VERSION 5.8 ;
BUSBITCHARS "[]" ;
DIVIDERCHAR "/" ;
UNITS
    DATABASE MICRONS 1000 ;
END UNITS

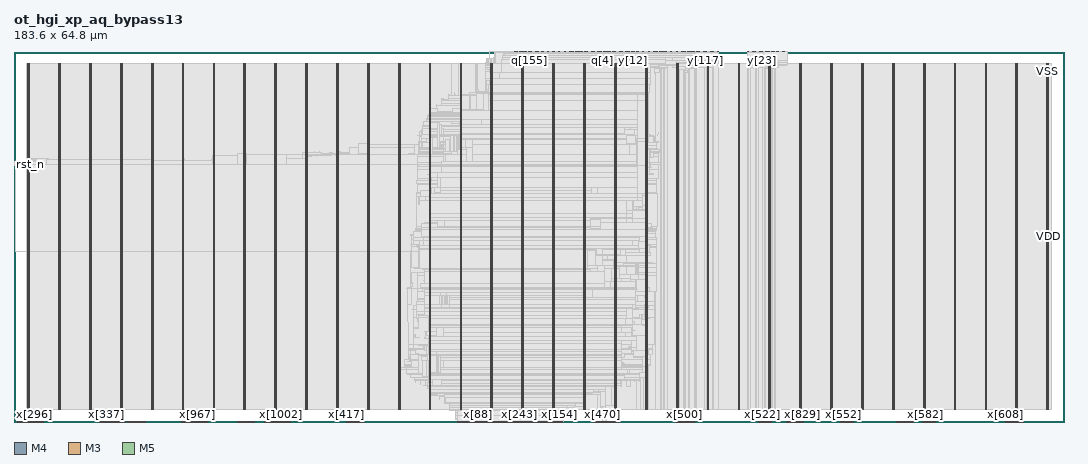
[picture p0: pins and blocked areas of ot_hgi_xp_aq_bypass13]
MACRO ot_hgi_xp_aq_bypass13
  FOREIGN ot_hgi_xp_aq_bypass13 0 0 ;
  CLASS BLOCK ;
  SIZE 183.6 BY 64.8 ;
  PIN clk
    DIRECTION INPUT ;
    USE SIGNAL ;
    PORT
      LAYER M4 ;
        RECT  0 44.88 0.084 44.904 ;
    END
  END clk
  PIN e[0]
    DIRECTION OUTPUT ;
    USE SIGNAL ;
    PORT
      LAYER M3 ;
        RECT  101.844 64.763 101.862 64.8 ;
    END
  END e[0]
  PIN e[1]
    DIRECTION OUTPUT ;
    USE SIGNAL ;
    PORT
      LAYER M3 ;
        RECT  101.916 64.763 101.934 64.8 ;
    END
  END e[1]
  PIN e[2]
    DIRECTION OUTPUT ;
    USE SIGNAL ;
    PORT
      LAYER M3 ;
        RECT  101.988 64.763 102.006 64.8 ;
    END
  END e[2]
  PIN e[3]
    DIRECTION OUTPUT ;
    USE SIGNAL ;
    PORT
      LAYER M3 ;
        RECT  102.06 64.763 102.078 64.8 ;
    END
  END e[3]
  PIN e[4]
    DIRECTION OUTPUT ;
    USE SIGNAL ;
    PORT
      LAYER M3 ;
        RECT  102.132 64.763 102.15 64.8 ;
    END
  END e[4]
  PIN e[5]
    DIRECTION OUTPUT ;
    USE SIGNAL ;
    PORT
      LAYER M3 ;
        RECT  102.204 64.763 102.222 64.8 ;
    END
  END e[5]
  PIN e[6]
    DIRECTION OUTPUT ;
    USE SIGNAL ;
    PORT
      LAYER M3 ;
        RECT  102.276 64.763 102.294 64.8 ;
    END
  END e[6]
  PIN e[7]
    DIRECTION OUTPUT ;
    USE SIGNAL ;
    PORT
      LAYER M3 ;
        RECT  102.348 64.763 102.366 64.8 ;
    END
  END e[7]
  PIN e[8]
    DIRECTION OUTPUT ;
    USE SIGNAL ;
    PORT
      LAYER M3 ;
        RECT  102.42 64.763 102.438 64.8 ;
    END
  END e[8]
  PIN e[9]
    DIRECTION OUTPUT ;
    USE SIGNAL ;
    PORT
      LAYER M3 ;
        RECT  102.492 64.763 102.51 64.8 ;
    END
  END e[9]
  PIN fault
    DIRECTION OUTPUT ;
    USE SIGNAL ;
    PORT
      LAYER M3 ;
        RECT  102.564 64.763 102.582 64.8 ;
    END
  END fault
  PIN fp4
    DIRECTION INPUT ;
    USE SIGNAL ;
    PORT
      LAYER M4 ;
        RECT  0 44.976 0.084 45 ;
    END
  END fp4
  PIN q[0]
    DIRECTION OUTPUT ;
    USE SIGNAL ;
    PORT
      LAYER M3 ;
        RECT  102.636 64.763 102.654 64.8 ;
    END
  END q[0]
  PIN q[100]
    DIRECTION OUTPUT ;
    USE SIGNAL ;
    PORT
      LAYER M5 ;
        RECT  89.136 64.716 89.16 64.8 ;
    END
  END q[100]
  PIN q[101]
    DIRECTION OUTPUT ;
    USE SIGNAL ;
    PORT
      LAYER M5 ;
        RECT  89.232 64.716 89.256 64.8 ;
    END
  END q[101]
  PIN q[102]
    DIRECTION OUTPUT ;
    USE SIGNAL ;
    PORT
      LAYER M5 ;
        RECT  89.328 64.716 89.352 64.8 ;
    END
  END q[102]
  PIN q[103]
    DIRECTION OUTPUT ;
    USE SIGNAL ;
    PORT
      LAYER M5 ;
        RECT  89.424 64.716 89.448 64.8 ;
    END
  END q[103]
  PIN q[104]
    DIRECTION OUTPUT ;
    USE SIGNAL ;
    PORT
      LAYER M5 ;
        RECT  89.52 64.716 89.544 64.8 ;
    END
  END q[104]
  PIN q[105]
    DIRECTION OUTPUT ;
    USE SIGNAL ;
    PORT
      LAYER M5 ;
        RECT  89.616 64.716 89.64 64.8 ;
    END
  END q[105]
  PIN q[106]
    DIRECTION OUTPUT ;
    USE SIGNAL ;
    PORT
      LAYER M5 ;
        RECT  89.712 64.716 89.736 64.8 ;
    END
  END q[106]
  PIN q[107]
    DIRECTION OUTPUT ;
    USE SIGNAL ;
    PORT
      LAYER M5 ;
        RECT  89.808 64.716 89.832 64.8 ;
    END
  END q[107]
  PIN q[108]
    DIRECTION OUTPUT ;
    USE SIGNAL ;
    PORT
      LAYER M5 ;
        RECT  89.904 64.716 89.928 64.8 ;
    END
  END q[108]
  PIN q[109]
    DIRECTION OUTPUT ;
    USE SIGNAL ;
    PORT
      LAYER M5 ;
        RECT  90 64.716 90.024 64.8 ;
    END
  END q[109]
  PIN q[10]
    DIRECTION OUTPUT ;
    USE SIGNAL ;
    PORT
      LAYER M3 ;
        RECT  103.356 64.763 103.374 64.8 ;
    END
  END q[10]
  PIN q[110]
    DIRECTION OUTPUT ;
    USE SIGNAL ;
    PORT
      LAYER M5 ;
        RECT  90.096 64.716 90.12 64.8 ;
    END
  END q[110]
  PIN q[111]
    DIRECTION OUTPUT ;
    USE SIGNAL ;
    PORT
      LAYER M5 ;
        RECT  90.192 64.716 90.216 64.8 ;
    END
  END q[111]
  PIN q[112]
    DIRECTION OUTPUT ;
    USE SIGNAL ;
    PORT
      LAYER M5 ;
        RECT  90.288 64.716 90.312 64.8 ;
    END
  END q[112]
  PIN q[113]
    DIRECTION OUTPUT ;
    USE SIGNAL ;
    PORT
      LAYER M5 ;
        RECT  90.384 64.716 90.408 64.8 ;
    END
  END q[113]
  PIN q[114]
    DIRECTION OUTPUT ;
    USE SIGNAL ;
    PORT
      LAYER M5 ;
        RECT  90.48 64.716 90.504 64.8 ;
    END
  END q[114]
  PIN q[115]
    DIRECTION OUTPUT ;
    USE SIGNAL ;
    PORT
      LAYER M5 ;
        RECT  90.576 64.716 90.6 64.8 ;
    END
  END q[115]
  PIN q[116]
    DIRECTION OUTPUT ;
    USE SIGNAL ;
    PORT
      LAYER M5 ;
        RECT  90.672 64.716 90.696 64.8 ;
    END
  END q[116]
  PIN q[117]
    DIRECTION OUTPUT ;
    USE SIGNAL ;
    PORT
      LAYER M5 ;
        RECT  96.912 64.716 96.936 64.8 ;
    END
  END q[117]
  PIN q[118]
    DIRECTION OUTPUT ;
    USE SIGNAL ;
    PORT
      LAYER M5 ;
        RECT  97.008 64.716 97.032 64.8 ;
    END
  END q[118]
  PIN q[119]
    DIRECTION OUTPUT ;
    USE SIGNAL ;
    PORT
      LAYER M5 ;
        RECT  97.104 64.716 97.128 64.8 ;
    END
  END q[119]
  PIN q[11]
    DIRECTION OUTPUT ;
    USE SIGNAL ;
    PORT
      LAYER M3 ;
        RECT  103.428 64.763 103.446 64.8 ;
    END
  END q[11]
  PIN q[120]
    DIRECTION OUTPUT ;
    USE SIGNAL ;
    PORT
      LAYER M5 ;
        RECT  97.2 64.716 97.224 64.8 ;
    END
  END q[120]
  PIN q[121]
    DIRECTION OUTPUT ;
    USE SIGNAL ;
    PORT
      LAYER M5 ;
        RECT  97.296 64.716 97.32 64.8 ;
    END
  END q[121]
  PIN q[122]
    DIRECTION OUTPUT ;
    USE SIGNAL ;
    PORT
      LAYER M5 ;
        RECT  97.392 64.716 97.416 64.8 ;
    END
  END q[122]
  PIN q[123]
    DIRECTION OUTPUT ;
    USE SIGNAL ;
    PORT
      LAYER M5 ;
        RECT  97.488 64.716 97.512 64.8 ;
    END
  END q[123]
  PIN q[124]
    DIRECTION OUTPUT ;
    USE SIGNAL ;
    PORT
      LAYER M5 ;
        RECT  97.584 64.716 97.608 64.8 ;
    END
  END q[124]
  PIN q[125]
    DIRECTION OUTPUT ;
    USE SIGNAL ;
    PORT
      LAYER M5 ;
        RECT  97.68 64.716 97.704 64.8 ;
    END
  END q[125]
  PIN q[126]
    DIRECTION OUTPUT ;
    USE SIGNAL ;
    PORT
      LAYER M5 ;
        RECT  97.776 64.716 97.8 64.8 ;
    END
  END q[126]
  PIN q[127]
    DIRECTION OUTPUT ;
    USE SIGNAL ;
    PORT
      LAYER M5 ;
        RECT  97.872 64.716 97.896 64.8 ;
    END
  END q[127]
  PIN q[128]
    DIRECTION OUTPUT ;
    USE SIGNAL ;
    PORT
      LAYER M5 ;
        RECT  97.968 64.716 97.992 64.8 ;
    END
  END q[128]
  PIN q[129]
    DIRECTION OUTPUT ;
    USE SIGNAL ;
    PORT
      LAYER M5 ;
        RECT  98.064 64.716 98.088 64.8 ;
    END
  END q[129]
  PIN q[12]
    DIRECTION OUTPUT ;
    USE SIGNAL ;
    PORT
      LAYER M3 ;
        RECT  103.5 64.763 103.518 64.8 ;
    END
  END q[12]
  PIN q[130]
    DIRECTION OUTPUT ;
    USE SIGNAL ;
    PORT
      LAYER M5 ;
        RECT  98.16 64.716 98.184 64.8 ;
    END
  END q[130]
  PIN q[131]
    DIRECTION OUTPUT ;
    USE SIGNAL ;
    PORT
      LAYER M5 ;
        RECT  98.256 64.716 98.28 64.8 ;
    END
  END q[131]
  PIN q[132]
    DIRECTION OUTPUT ;
    USE SIGNAL ;
    PORT
      LAYER M5 ;
        RECT  98.352 64.716 98.376 64.8 ;
    END
  END q[132]
  PIN q[133]
    DIRECTION OUTPUT ;
    USE SIGNAL ;
    PORT
      LAYER M5 ;
        RECT  98.448 64.716 98.472 64.8 ;
    END
  END q[133]
  PIN q[134]
    DIRECTION OUTPUT ;
    USE SIGNAL ;
    PORT
      LAYER M5 ;
        RECT  98.544 64.716 98.568 64.8 ;
    END
  END q[134]
  PIN q[135]
    DIRECTION OUTPUT ;
    USE SIGNAL ;
    PORT
      LAYER M5 ;
        RECT  98.64 64.716 98.664 64.8 ;
    END
  END q[135]
  PIN q[136]
    DIRECTION OUTPUT ;
    USE SIGNAL ;
    PORT
      LAYER M5 ;
        RECT  98.736 64.716 98.76 64.8 ;
    END
  END q[136]
  PIN q[137]
    DIRECTION OUTPUT ;
    USE SIGNAL ;
    PORT
      LAYER M5 ;
        RECT  98.832 64.716 98.856 64.8 ;
    END
  END q[137]
  PIN q[138]
    DIRECTION OUTPUT ;
    USE SIGNAL ;
    PORT
      LAYER M5 ;
        RECT  98.928 64.716 98.952 64.8 ;
    END
  END q[138]
  PIN q[139]
    DIRECTION OUTPUT ;
    USE SIGNAL ;
    PORT
      LAYER M5 ;
        RECT  99.024 64.716 99.048 64.8 ;
    END
  END q[139]
  PIN q[13]
    DIRECTION OUTPUT ;
    USE SIGNAL ;
    PORT
      LAYER M3 ;
        RECT  103.572 64.763 103.59 64.8 ;
    END
  END q[13]
  PIN q[140]
    DIRECTION OUTPUT ;
    USE SIGNAL ;
    PORT
      LAYER M5 ;
        RECT  99.12 64.716 99.144 64.8 ;
    END
  END q[140]
  PIN q[141]
    DIRECTION OUTPUT ;
    USE SIGNAL ;
    PORT
      LAYER M5 ;
        RECT  99.216 64.716 99.24 64.8 ;
    END
  END q[141]
  PIN q[142]
    DIRECTION OUTPUT ;
    USE SIGNAL ;
    PORT
      LAYER M5 ;
        RECT  99.312 64.716 99.336 64.8 ;
    END
  END q[142]
  PIN q[143]
    DIRECTION OUTPUT ;
    USE SIGNAL ;
    PORT
      LAYER M5 ;
        RECT  99.408 64.716 99.432 64.8 ;
    END
  END q[143]
  PIN q[144]
    DIRECTION OUTPUT ;
    USE SIGNAL ;
    PORT
      LAYER M5 ;
        RECT  99.504 64.716 99.528 64.8 ;
    END
  END q[144]
  PIN q[145]
    DIRECTION OUTPUT ;
    USE SIGNAL ;
    PORT
      LAYER M5 ;
        RECT  99.6 64.716 99.624 64.8 ;
    END
  END q[145]
  PIN q[146]
    DIRECTION OUTPUT ;
    USE SIGNAL ;
    PORT
      LAYER M5 ;
        RECT  99.696 64.716 99.72 64.8 ;
    END
  END q[146]
  PIN q[147]
    DIRECTION OUTPUT ;
    USE SIGNAL ;
    PORT
      LAYER M5 ;
        RECT  99.792 64.716 99.816 64.8 ;
    END
  END q[147]
  PIN q[148]
    DIRECTION OUTPUT ;
    USE SIGNAL ;
    PORT
      LAYER M5 ;
        RECT  99.888 64.716 99.912 64.8 ;
    END
  END q[148]
  PIN q[149]
    DIRECTION OUTPUT ;
    USE SIGNAL ;
    PORT
      LAYER M3 ;
        RECT  89.748 64.763 89.766 64.8 ;
    END
  END q[149]
  PIN q[14]
    DIRECTION OUTPUT ;
    USE SIGNAL ;
    PORT
      LAYER M3 ;
        RECT  103.644 64.763 103.662 64.8 ;
    END
  END q[14]
  PIN q[150]
    DIRECTION OUTPUT ;
    USE SIGNAL ;
    PORT
      LAYER M3 ;
        RECT  89.82 64.763 89.838 64.8 ;
    END
  END q[150]
  PIN q[151]
    DIRECTION OUTPUT ;
    USE SIGNAL ;
    PORT
      LAYER M3 ;
        RECT  89.892 64.763 89.91 64.8 ;
    END
  END q[151]
  PIN q[152]
    DIRECTION OUTPUT ;
    USE SIGNAL ;
    PORT
      LAYER M3 ;
        RECT  89.964 64.763 89.982 64.8 ;
    END
  END q[152]
  PIN q[153]
    DIRECTION OUTPUT ;
    USE SIGNAL ;
    PORT
      LAYER M3 ;
        RECT  90.036 64.763 90.054 64.8 ;
    END
  END q[153]
  PIN q[154]
    DIRECTION OUTPUT ;
    USE SIGNAL ;
    PORT
      LAYER M3 ;
        RECT  90.108 64.763 90.126 64.8 ;
    END
  END q[154]
  PIN q[155]
    DIRECTION OUTPUT ;
    USE SIGNAL ;
    PORT
      LAYER M3 ;
        RECT  90.18 64.763 90.198 64.8 ;
    END
  END q[155]
  PIN q[156]
    DIRECTION OUTPUT ;
    USE SIGNAL ;
    PORT
      LAYER M3 ;
        RECT  90.252 64.763 90.27 64.8 ;
    END
  END q[156]
  PIN q[157]
    DIRECTION OUTPUT ;
    USE SIGNAL ;
    PORT
      LAYER M3 ;
        RECT  90.324 64.763 90.342 64.8 ;
    END
  END q[157]
  PIN q[158]
    DIRECTION OUTPUT ;
    USE SIGNAL ;
    PORT
      LAYER M3 ;
        RECT  90.396 64.763 90.414 64.8 ;
    END
  END q[158]
  PIN q[159]
    DIRECTION OUTPUT ;
    USE SIGNAL ;
    PORT
      LAYER M3 ;
        RECT  90.468 64.763 90.486 64.8 ;
    END
  END q[159]
  PIN q[15]
    DIRECTION OUTPUT ;
    USE SIGNAL ;
    PORT
      LAYER M3 ;
        RECT  103.716 64.763 103.734 64.8 ;
    END
  END q[15]
  PIN q[160]
    DIRECTION OUTPUT ;
    USE SIGNAL ;
    PORT
      LAYER M3 ;
        RECT  90.54 64.763 90.558 64.8 ;
    END
  END q[160]
  PIN q[161]
    DIRECTION OUTPUT ;
    USE SIGNAL ;
    PORT
      LAYER M3 ;
        RECT  90.612 64.763 90.63 64.8 ;
    END
  END q[161]
  PIN q[162]
    DIRECTION OUTPUT ;
    USE SIGNAL ;
    PORT
      LAYER M3 ;
        RECT  90.684 64.763 90.702 64.8 ;
    END
  END q[162]
  PIN q[163]
    DIRECTION OUTPUT ;
    USE SIGNAL ;
    PORT
      LAYER M3 ;
        RECT  90.756 64.763 90.774 64.8 ;
    END
  END q[163]
  PIN q[164]
    DIRECTION OUTPUT ;
    USE SIGNAL ;
    PORT
      LAYER M3 ;
        RECT  90.828 64.763 90.846 64.8 ;
    END
  END q[164]
  PIN q[165]
    DIRECTION OUTPUT ;
    USE SIGNAL ;
    PORT
      LAYER M3 ;
        RECT  90.9 64.763 90.918 64.8 ;
    END
  END q[165]
  PIN q[166]
    DIRECTION OUTPUT ;
    USE SIGNAL ;
    PORT
      LAYER M3 ;
        RECT  90.972 64.763 90.99 64.8 ;
    END
  END q[166]
  PIN q[167]
    DIRECTION OUTPUT ;
    USE SIGNAL ;
    PORT
      LAYER M3 ;
        RECT  91.044 64.763 91.062 64.8 ;
    END
  END q[167]
  PIN q[168]
    DIRECTION OUTPUT ;
    USE SIGNAL ;
    PORT
      LAYER M3 ;
        RECT  91.116 64.763 91.134 64.8 ;
    END
  END q[168]
  PIN q[169]
    DIRECTION OUTPUT ;
    USE SIGNAL ;
    PORT
      LAYER M3 ;
        RECT  91.188 64.763 91.206 64.8 ;
    END
  END q[169]
  PIN q[16]
    DIRECTION OUTPUT ;
    USE SIGNAL ;
    PORT
      LAYER M3 ;
        RECT  103.788 64.763 103.806 64.8 ;
    END
  END q[16]
  PIN q[170]
    DIRECTION OUTPUT ;
    USE SIGNAL ;
    PORT
      LAYER M3 ;
        RECT  91.26 64.763 91.278 64.8 ;
    END
  END q[170]
  PIN q[171]
    DIRECTION OUTPUT ;
    USE SIGNAL ;
    PORT
      LAYER M3 ;
        RECT  91.332 64.763 91.35 64.8 ;
    END
  END q[171]
  PIN q[172]
    DIRECTION OUTPUT ;
    USE SIGNAL ;
    PORT
      LAYER M3 ;
        RECT  91.404 64.763 91.422 64.8 ;
    END
  END q[172]
  PIN q[173]
    DIRECTION OUTPUT ;
    USE SIGNAL ;
    PORT
      LAYER M3 ;
        RECT  91.476 64.763 91.494 64.8 ;
    END
  END q[173]
  PIN q[174]
    DIRECTION OUTPUT ;
    USE SIGNAL ;
    PORT
      LAYER M3 ;
        RECT  91.548 64.763 91.566 64.8 ;
    END
  END q[174]
  PIN q[175]
    DIRECTION OUTPUT ;
    USE SIGNAL ;
    PORT
      LAYER M3 ;
        RECT  91.62 64.763 91.638 64.8 ;
    END
  END q[175]
  PIN q[176]
    DIRECTION OUTPUT ;
    USE SIGNAL ;
    PORT
      LAYER M3 ;
        RECT  91.692 64.763 91.71 64.8 ;
    END
  END q[176]
  PIN q[177]
    DIRECTION OUTPUT ;
    USE SIGNAL ;
    PORT
      LAYER M3 ;
        RECT  91.764 64.763 91.782 64.8 ;
    END
  END q[177]
  PIN q[178]
    DIRECTION OUTPUT ;
    USE SIGNAL ;
    PORT
      LAYER M3 ;
        RECT  91.836 64.763 91.854 64.8 ;
    END
  END q[178]
  PIN q[179]
    DIRECTION OUTPUT ;
    USE SIGNAL ;
    PORT
      LAYER M3 ;
        RECT  91.908 64.763 91.926 64.8 ;
    END
  END q[179]
  PIN q[17]
    DIRECTION OUTPUT ;
    USE SIGNAL ;
    PORT
      LAYER M3 ;
        RECT  103.86 64.763 103.878 64.8 ;
    END
  END q[17]
  PIN q[180]
    DIRECTION OUTPUT ;
    USE SIGNAL ;
    PORT
      LAYER M3 ;
        RECT  91.98 64.763 91.998 64.8 ;
    END
  END q[180]
  PIN q[181]
    DIRECTION OUTPUT ;
    USE SIGNAL ;
    PORT
      LAYER M5 ;
        RECT  93.84 64.716 93.864 64.8 ;
    END
  END q[181]
  PIN q[182]
    DIRECTION OUTPUT ;
    USE SIGNAL ;
    PORT
      LAYER M5 ;
        RECT  93.936 64.716 93.96 64.8 ;
    END
  END q[182]
  PIN q[183]
    DIRECTION OUTPUT ;
    USE SIGNAL ;
    PORT
      LAYER M5 ;
        RECT  94.032 64.716 94.056 64.8 ;
    END
  END q[183]
  PIN q[184]
    DIRECTION OUTPUT ;
    USE SIGNAL ;
    PORT
      LAYER M5 ;
        RECT  94.128 64.716 94.152 64.8 ;
    END
  END q[184]
  PIN q[185]
    DIRECTION OUTPUT ;
    USE SIGNAL ;
    PORT
      LAYER M5 ;
        RECT  94.224 64.716 94.248 64.8 ;
    END
  END q[185]
  PIN q[186]
    DIRECTION OUTPUT ;
    USE SIGNAL ;
    PORT
      LAYER M5 ;
        RECT  94.32 64.716 94.344 64.8 ;
    END
  END q[186]
  PIN q[187]
    DIRECTION OUTPUT ;
    USE SIGNAL ;
    PORT
      LAYER M5 ;
        RECT  94.416 64.716 94.44 64.8 ;
    END
  END q[187]
  PIN q[188]
    DIRECTION OUTPUT ;
    USE SIGNAL ;
    PORT
      LAYER M5 ;
        RECT  94.512 64.716 94.536 64.8 ;
    END
  END q[188]
  PIN q[189]
    DIRECTION OUTPUT ;
    USE SIGNAL ;
    PORT
      LAYER M5 ;
        RECT  94.608 64.716 94.632 64.8 ;
    END
  END q[189]
  PIN q[18]
    DIRECTION OUTPUT ;
    USE SIGNAL ;
    PORT
      LAYER M3 ;
        RECT  103.932 64.763 103.95 64.8 ;
    END
  END q[18]
  PIN q[190]
    DIRECTION OUTPUT ;
    USE SIGNAL ;
    PORT
      LAYER M5 ;
        RECT  94.704 64.716 94.728 64.8 ;
    END
  END q[190]
  PIN q[191]
    DIRECTION OUTPUT ;
    USE SIGNAL ;
    PORT
      LAYER M5 ;
        RECT  94.8 64.716 94.824 64.8 ;
    END
  END q[191]
  PIN q[192]
    DIRECTION OUTPUT ;
    USE SIGNAL ;
    PORT
      LAYER M5 ;
        RECT  94.896 64.716 94.92 64.8 ;
    END
  END q[192]
  PIN q[193]
    DIRECTION OUTPUT ;
    USE SIGNAL ;
    PORT
      LAYER M5 ;
        RECT  94.992 64.716 95.016 64.8 ;
    END
  END q[193]
  PIN q[194]
    DIRECTION OUTPUT ;
    USE SIGNAL ;
    PORT
      LAYER M5 ;
        RECT  95.088 64.716 95.112 64.8 ;
    END
  END q[194]
  PIN q[195]
    DIRECTION OUTPUT ;
    USE SIGNAL ;
    PORT
      LAYER M5 ;
        RECT  95.184 64.716 95.208 64.8 ;
    END
  END q[195]
  PIN q[196]
    DIRECTION OUTPUT ;
    USE SIGNAL ;
    PORT
      LAYER M5 ;
        RECT  95.28 64.716 95.304 64.8 ;
    END
  END q[196]
  PIN q[197]
    DIRECTION OUTPUT ;
    USE SIGNAL ;
    PORT
      LAYER M5 ;
        RECT  95.376 64.716 95.4 64.8 ;
    END
  END q[197]
  PIN q[198]
    DIRECTION OUTPUT ;
    USE SIGNAL ;
    PORT
      LAYER M5 ;
        RECT  95.472 64.716 95.496 64.8 ;
    END
  END q[198]
  PIN q[199]
    DIRECTION OUTPUT ;
    USE SIGNAL ;
    PORT
      LAYER M5 ;
        RECT  95.568 64.716 95.592 64.8 ;
    END
  END q[199]
  PIN q[19]
    DIRECTION OUTPUT ;
    USE SIGNAL ;
    PORT
      LAYER M3 ;
        RECT  104.004 64.763 104.022 64.8 ;
    END
  END q[19]
  PIN q[1]
    DIRECTION OUTPUT ;
    USE SIGNAL ;
    PORT
      LAYER M3 ;
        RECT  102.708 64.763 102.726 64.8 ;
    END
  END q[1]
  PIN q[200]
    DIRECTION OUTPUT ;
    USE SIGNAL ;
    PORT
      LAYER M5 ;
        RECT  95.664 64.716 95.688 64.8 ;
    END
  END q[200]
  PIN q[201]
    DIRECTION OUTPUT ;
    USE SIGNAL ;
    PORT
      LAYER M5 ;
        RECT  95.76 64.716 95.784 64.8 ;
    END
  END q[201]
  PIN q[202]
    DIRECTION OUTPUT ;
    USE SIGNAL ;
    PORT
      LAYER M5 ;
        RECT  95.856 64.716 95.88 64.8 ;
    END
  END q[202]
  PIN q[203]
    DIRECTION OUTPUT ;
    USE SIGNAL ;
    PORT
      LAYER M5 ;
        RECT  95.952 64.716 95.976 64.8 ;
    END
  END q[203]
  PIN q[204]
    DIRECTION OUTPUT ;
    USE SIGNAL ;
    PORT
      LAYER M5 ;
        RECT  96.048 64.716 96.072 64.8 ;
    END
  END q[204]
  PIN q[205]
    DIRECTION OUTPUT ;
    USE SIGNAL ;
    PORT
      LAYER M5 ;
        RECT  96.144 64.716 96.168 64.8 ;
    END
  END q[205]
  PIN q[206]
    DIRECTION OUTPUT ;
    USE SIGNAL ;
    PORT
      LAYER M5 ;
        RECT  96.24 64.716 96.264 64.8 ;
    END
  END q[206]
  PIN q[207]
    DIRECTION OUTPUT ;
    USE SIGNAL ;
    PORT
      LAYER M5 ;
        RECT  96.336 64.716 96.36 64.8 ;
    END
  END q[207]
  PIN q[208]
    DIRECTION OUTPUT ;
    USE SIGNAL ;
    PORT
      LAYER M5 ;
        RECT  96.432 64.716 96.456 64.8 ;
    END
  END q[208]
  PIN q[209]
    DIRECTION OUTPUT ;
    USE SIGNAL ;
    PORT
      LAYER M5 ;
        RECT  96.528 64.716 96.552 64.8 ;
    END
  END q[209]
  PIN q[20]
    DIRECTION OUTPUT ;
    USE SIGNAL ;
    PORT
      LAYER M3 ;
        RECT  104.076 64.763 104.094 64.8 ;
    END
  END q[20]
  PIN q[210]
    DIRECTION OUTPUT ;
    USE SIGNAL ;
    PORT
      LAYER M5 ;
        RECT  96.624 64.716 96.648 64.8 ;
    END
  END q[210]
  PIN q[211]
    DIRECTION OUTPUT ;
    USE SIGNAL ;
    PORT
      LAYER M5 ;
        RECT  96.72 64.716 96.744 64.8 ;
    END
  END q[211]
  PIN q[212]
    DIRECTION OUTPUT ;
    USE SIGNAL ;
    PORT
      LAYER M5 ;
        RECT  96.816 64.716 96.84 64.8 ;
    END
  END q[212]
  PIN q[213]
    DIRECTION OUTPUT ;
    USE SIGNAL ;
    PORT
      LAYER M5 ;
        RECT  99.984 64.716 100.008 64.8 ;
    END
  END q[213]
  PIN q[214]
    DIRECTION OUTPUT ;
    USE SIGNAL ;
    PORT
      LAYER M5 ;
        RECT  100.08 64.716 100.104 64.8 ;
    END
  END q[214]
  PIN q[215]
    DIRECTION OUTPUT ;
    USE SIGNAL ;
    PORT
      LAYER M5 ;
        RECT  100.176 64.716 100.2 64.8 ;
    END
  END q[215]
  PIN q[216]
    DIRECTION OUTPUT ;
    USE SIGNAL ;
    PORT
      LAYER M5 ;
        RECT  100.272 64.716 100.296 64.8 ;
    END
  END q[216]
  PIN q[217]
    DIRECTION OUTPUT ;
    USE SIGNAL ;
    PORT
      LAYER M5 ;
        RECT  100.368 64.716 100.392 64.8 ;
    END
  END q[217]
  PIN q[218]
    DIRECTION OUTPUT ;
    USE SIGNAL ;
    PORT
      LAYER M5 ;
        RECT  100.464 64.716 100.488 64.8 ;
    END
  END q[218]
  PIN q[219]
    DIRECTION OUTPUT ;
    USE SIGNAL ;
    PORT
      LAYER M5 ;
        RECT  100.56 64.716 100.584 64.8 ;
    END
  END q[219]
  PIN q[21]
    DIRECTION OUTPUT ;
    USE SIGNAL ;
    PORT
      LAYER M3 ;
        RECT  87.444 64.763 87.462 64.8 ;
    END
  END q[21]
  PIN q[220]
    DIRECTION OUTPUT ;
    USE SIGNAL ;
    PORT
      LAYER M5 ;
        RECT  100.656 64.716 100.68 64.8 ;
    END
  END q[220]
  PIN q[221]
    DIRECTION OUTPUT ;
    USE SIGNAL ;
    PORT
      LAYER M5 ;
        RECT  100.752 64.716 100.776 64.8 ;
    END
  END q[221]
  PIN q[222]
    DIRECTION OUTPUT ;
    USE SIGNAL ;
    PORT
      LAYER M5 ;
        RECT  100.848 64.716 100.872 64.8 ;
    END
  END q[222]
  PIN q[223]
    DIRECTION OUTPUT ;
    USE SIGNAL ;
    PORT
      LAYER M5 ;
        RECT  100.944 64.716 100.968 64.8 ;
    END
  END q[223]
  PIN q[224]
    DIRECTION OUTPUT ;
    USE SIGNAL ;
    PORT
      LAYER M5 ;
        RECT  101.04 64.716 101.064 64.8 ;
    END
  END q[224]
  PIN q[225]
    DIRECTION OUTPUT ;
    USE SIGNAL ;
    PORT
      LAYER M5 ;
        RECT  101.136 64.716 101.16 64.8 ;
    END
  END q[225]
  PIN q[226]
    DIRECTION OUTPUT ;
    USE SIGNAL ;
    PORT
      LAYER M5 ;
        RECT  101.232 64.716 101.256 64.8 ;
    END
  END q[226]
  PIN q[227]
    DIRECTION OUTPUT ;
    USE SIGNAL ;
    PORT
      LAYER M5 ;
        RECT  101.328 64.716 101.352 64.8 ;
    END
  END q[227]
  PIN q[228]
    DIRECTION OUTPUT ;
    USE SIGNAL ;
    PORT
      LAYER M5 ;
        RECT  101.424 64.716 101.448 64.8 ;
    END
  END q[228]
  PIN q[229]
    DIRECTION OUTPUT ;
    USE SIGNAL ;
    PORT
      LAYER M5 ;
        RECT  101.52 64.716 101.544 64.8 ;
    END
  END q[229]
  PIN q[22]
    DIRECTION OUTPUT ;
    USE SIGNAL ;
    PORT
      LAYER M3 ;
        RECT  87.516 64.763 87.534 64.8 ;
    END
  END q[22]
  PIN q[230]
    DIRECTION OUTPUT ;
    USE SIGNAL ;
    PORT
      LAYER M5 ;
        RECT  101.616 64.716 101.64 64.8 ;
    END
  END q[230]
  PIN q[231]
    DIRECTION OUTPUT ;
    USE SIGNAL ;
    PORT
      LAYER M5 ;
        RECT  101.712 64.716 101.736 64.8 ;
    END
  END q[231]
  PIN q[232]
    DIRECTION OUTPUT ;
    USE SIGNAL ;
    PORT
      LAYER M5 ;
        RECT  101.808 64.716 101.832 64.8 ;
    END
  END q[232]
  PIN q[233]
    DIRECTION OUTPUT ;
    USE SIGNAL ;
    PORT
      LAYER M5 ;
        RECT  101.904 64.716 101.928 64.8 ;
    END
  END q[233]
  PIN q[234]
    DIRECTION OUTPUT ;
    USE SIGNAL ;
    PORT
      LAYER M5 ;
        RECT  102 64.716 102.024 64.8 ;
    END
  END q[234]
  PIN q[235]
    DIRECTION OUTPUT ;
    USE SIGNAL ;
    PORT
      LAYER M5 ;
        RECT  102.096 64.716 102.12 64.8 ;
    END
  END q[235]
  PIN q[236]
    DIRECTION OUTPUT ;
    USE SIGNAL ;
    PORT
      LAYER M5 ;
        RECT  102.192 64.716 102.216 64.8 ;
    END
  END q[236]
  PIN q[237]
    DIRECTION OUTPUT ;
    USE SIGNAL ;
    PORT
      LAYER M5 ;
        RECT  102.288 64.716 102.312 64.8 ;
    END
  END q[237]
  PIN q[238]
    DIRECTION OUTPUT ;
    USE SIGNAL ;
    PORT
      LAYER M5 ;
        RECT  102.384 64.716 102.408 64.8 ;
    END
  END q[238]
  PIN q[239]
    DIRECTION OUTPUT ;
    USE SIGNAL ;
    PORT
      LAYER M5 ;
        RECT  102.48 64.716 102.504 64.8 ;
    END
  END q[239]
  PIN q[23]
    DIRECTION OUTPUT ;
    USE SIGNAL ;
    PORT
      LAYER M3 ;
        RECT  87.588 64.763 87.606 64.8 ;
    END
  END q[23]
  PIN q[240]
    DIRECTION OUTPUT ;
    USE SIGNAL ;
    PORT
      LAYER M5 ;
        RECT  102.576 64.716 102.6 64.8 ;
    END
  END q[240]
  PIN q[241]
    DIRECTION OUTPUT ;
    USE SIGNAL ;
    PORT
      LAYER M5 ;
        RECT  102.672 64.716 102.696 64.8 ;
    END
  END q[241]
  PIN q[242]
    DIRECTION OUTPUT ;
    USE SIGNAL ;
    PORT
      LAYER M5 ;
        RECT  102.768 64.716 102.792 64.8 ;
    END
  END q[242]
  PIN q[243]
    DIRECTION OUTPUT ;
    USE SIGNAL ;
    PORT
      LAYER M5 ;
        RECT  102.864 64.716 102.888 64.8 ;
    END
  END q[243]
  PIN q[244]
    DIRECTION OUTPUT ;
    USE SIGNAL ;
    PORT
      LAYER M5 ;
        RECT  102.96 64.716 102.984 64.8 ;
    END
  END q[244]
  PIN q[245]
    DIRECTION OUTPUT ;
    USE SIGNAL ;
    PORT
      LAYER M3 ;
        RECT  106.452 64.763 106.47 64.8 ;
    END
  END q[245]
  PIN q[246]
    DIRECTION OUTPUT ;
    USE SIGNAL ;
    PORT
      LAYER M3 ;
        RECT  106.524 64.763 106.542 64.8 ;
    END
  END q[246]
  PIN q[247]
    DIRECTION OUTPUT ;
    USE SIGNAL ;
    PORT
      LAYER M3 ;
        RECT  106.596 64.763 106.614 64.8 ;
    END
  END q[247]
  PIN q[248]
    DIRECTION OUTPUT ;
    USE SIGNAL ;
    PORT
      LAYER M3 ;
        RECT  106.668 64.763 106.686 64.8 ;
    END
  END q[248]
  PIN q[249]
    DIRECTION OUTPUT ;
    USE SIGNAL ;
    PORT
      LAYER M3 ;
        RECT  106.74 64.763 106.758 64.8 ;
    END
  END q[249]
  PIN q[24]
    DIRECTION OUTPUT ;
    USE SIGNAL ;
    PORT
      LAYER M3 ;
        RECT  87.66 64.763 87.678 64.8 ;
    END
  END q[24]
  PIN q[250]
    DIRECTION OUTPUT ;
    USE SIGNAL ;
    PORT
      LAYER M3 ;
        RECT  106.812 64.763 106.83 64.8 ;
    END
  END q[250]
  PIN q[251]
    DIRECTION OUTPUT ;
    USE SIGNAL ;
    PORT
      LAYER M3 ;
        RECT  106.884 64.763 106.902 64.8 ;
    END
  END q[251]
  PIN q[252]
    DIRECTION OUTPUT ;
    USE SIGNAL ;
    PORT
      LAYER M3 ;
        RECT  106.956 64.763 106.974 64.8 ;
    END
  END q[252]
  PIN q[253]
    DIRECTION OUTPUT ;
    USE SIGNAL ;
    PORT
      LAYER M3 ;
        RECT  107.028 64.763 107.046 64.8 ;
    END
  END q[253]
  PIN q[254]
    DIRECTION OUTPUT ;
    USE SIGNAL ;
    PORT
      LAYER M3 ;
        RECT  107.1 64.763 107.118 64.8 ;
    END
  END q[254]
  PIN q[255]
    DIRECTION OUTPUT ;
    USE SIGNAL ;
    PORT
      LAYER M3 ;
        RECT  107.172 64.763 107.19 64.8 ;
    END
  END q[255]
  PIN q[25]
    DIRECTION OUTPUT ;
    USE SIGNAL ;
    PORT
      LAYER M3 ;
        RECT  87.732 64.763 87.75 64.8 ;
    END
  END q[25]
  PIN q[26]
    DIRECTION OUTPUT ;
    USE SIGNAL ;
    PORT
      LAYER M3 ;
        RECT  87.804 64.763 87.822 64.8 ;
    END
  END q[26]
  PIN q[27]
    DIRECTION OUTPUT ;
    USE SIGNAL ;
    PORT
      LAYER M3 ;
        RECT  87.876 64.763 87.894 64.8 ;
    END
  END q[27]
  PIN q[28]
    DIRECTION OUTPUT ;
    USE SIGNAL ;
    PORT
      LAYER M3 ;
        RECT  87.948 64.763 87.966 64.8 ;
    END
  END q[28]
  PIN q[29]
    DIRECTION OUTPUT ;
    USE SIGNAL ;
    PORT
      LAYER M3 ;
        RECT  88.02 64.763 88.038 64.8 ;
    END
  END q[29]
  PIN q[2]
    DIRECTION OUTPUT ;
    USE SIGNAL ;
    PORT
      LAYER M3 ;
        RECT  102.78 64.763 102.798 64.8 ;
    END
  END q[2]
  PIN q[30]
    DIRECTION OUTPUT ;
    USE SIGNAL ;
    PORT
      LAYER M3 ;
        RECT  88.092 64.763 88.11 64.8 ;
    END
  END q[30]
  PIN q[31]
    DIRECTION OUTPUT ;
    USE SIGNAL ;
    PORT
      LAYER M3 ;
        RECT  88.164 64.763 88.182 64.8 ;
    END
  END q[31]
  PIN q[32]
    DIRECTION OUTPUT ;
    USE SIGNAL ;
    PORT
      LAYER M3 ;
        RECT  88.236 64.763 88.254 64.8 ;
    END
  END q[32]
  PIN q[33]
    DIRECTION OUTPUT ;
    USE SIGNAL ;
    PORT
      LAYER M3 ;
        RECT  88.308 64.763 88.326 64.8 ;
    END
  END q[33]
  PIN q[34]
    DIRECTION OUTPUT ;
    USE SIGNAL ;
    PORT
      LAYER M3 ;
        RECT  88.38 64.763 88.398 64.8 ;
    END
  END q[34]
  PIN q[35]
    DIRECTION OUTPUT ;
    USE SIGNAL ;
    PORT
      LAYER M3 ;
        RECT  88.452 64.763 88.47 64.8 ;
    END
  END q[35]
  PIN q[36]
    DIRECTION OUTPUT ;
    USE SIGNAL ;
    PORT
      LAYER M3 ;
        RECT  88.524 64.763 88.542 64.8 ;
    END
  END q[36]
  PIN q[37]
    DIRECTION OUTPUT ;
    USE SIGNAL ;
    PORT
      LAYER M3 ;
        RECT  88.596 64.763 88.614 64.8 ;
    END
  END q[37]
  PIN q[38]
    DIRECTION OUTPUT ;
    USE SIGNAL ;
    PORT
      LAYER M3 ;
        RECT  88.668 64.763 88.686 64.8 ;
    END
  END q[38]
  PIN q[39]
    DIRECTION OUTPUT ;
    USE SIGNAL ;
    PORT
      LAYER M3 ;
        RECT  88.74 64.763 88.758 64.8 ;
    END
  END q[39]
  PIN q[3]
    DIRECTION OUTPUT ;
    USE SIGNAL ;
    PORT
      LAYER M3 ;
        RECT  102.852 64.763 102.87 64.8 ;
    END
  END q[3]
  PIN q[40]
    DIRECTION OUTPUT ;
    USE SIGNAL ;
    PORT
      LAYER M3 ;
        RECT  88.812 64.763 88.83 64.8 ;
    END
  END q[40]
  PIN q[41]
    DIRECTION OUTPUT ;
    USE SIGNAL ;
    PORT
      LAYER M3 ;
        RECT  88.884 64.763 88.902 64.8 ;
    END
  END q[41]
  PIN q[42]
    DIRECTION OUTPUT ;
    USE SIGNAL ;
    PORT
      LAYER M3 ;
        RECT  88.956 64.763 88.974 64.8 ;
    END
  END q[42]
  PIN q[43]
    DIRECTION OUTPUT ;
    USE SIGNAL ;
    PORT
      LAYER M3 ;
        RECT  89.028 64.763 89.046 64.8 ;
    END
  END q[43]
  PIN q[44]
    DIRECTION OUTPUT ;
    USE SIGNAL ;
    PORT
      LAYER M3 ;
        RECT  89.1 64.763 89.118 64.8 ;
    END
  END q[44]
  PIN q[45]
    DIRECTION OUTPUT ;
    USE SIGNAL ;
    PORT
      LAYER M3 ;
        RECT  89.172 64.763 89.19 64.8 ;
    END
  END q[45]
  PIN q[46]
    DIRECTION OUTPUT ;
    USE SIGNAL ;
    PORT
      LAYER M3 ;
        RECT  89.244 64.763 89.262 64.8 ;
    END
  END q[46]
  PIN q[47]
    DIRECTION OUTPUT ;
    USE SIGNAL ;
    PORT
      LAYER M3 ;
        RECT  89.316 64.763 89.334 64.8 ;
    END
  END q[47]
  PIN q[48]
    DIRECTION OUTPUT ;
    USE SIGNAL ;
    PORT
      LAYER M3 ;
        RECT  89.388 64.763 89.406 64.8 ;
    END
  END q[48]
  PIN q[49]
    DIRECTION OUTPUT ;
    USE SIGNAL ;
    PORT
      LAYER M3 ;
        RECT  89.46 64.763 89.478 64.8 ;
    END
  END q[49]
  PIN q[4]
    DIRECTION OUTPUT ;
    USE SIGNAL ;
    PORT
      LAYER M3 ;
        RECT  102.924 64.763 102.942 64.8 ;
    END
  END q[4]
  PIN q[50]
    DIRECTION OUTPUT ;
    USE SIGNAL ;
    PORT
      LAYER M3 ;
        RECT  89.532 64.763 89.55 64.8 ;
    END
  END q[50]
  PIN q[51]
    DIRECTION OUTPUT ;
    USE SIGNAL ;
    PORT
      LAYER M3 ;
        RECT  89.604 64.763 89.622 64.8 ;
    END
  END q[51]
  PIN q[52]
    DIRECTION OUTPUT ;
    USE SIGNAL ;
    PORT
      LAYER M3 ;
        RECT  89.676 64.763 89.694 64.8 ;
    END
  END q[52]
  PIN q[53]
    DIRECTION OUTPUT ;
    USE SIGNAL ;
    PORT
      LAYER M5 ;
        RECT  90.768 64.716 90.792 64.8 ;
    END
  END q[53]
  PIN q[54]
    DIRECTION OUTPUT ;
    USE SIGNAL ;
    PORT
      LAYER M5 ;
        RECT  90.864 64.716 90.888 64.8 ;
    END
  END q[54]
  PIN q[55]
    DIRECTION OUTPUT ;
    USE SIGNAL ;
    PORT
      LAYER M5 ;
        RECT  90.96 64.716 90.984 64.8 ;
    END
  END q[55]
  PIN q[56]
    DIRECTION OUTPUT ;
    USE SIGNAL ;
    PORT
      LAYER M5 ;
        RECT  91.056 64.716 91.08 64.8 ;
    END
  END q[56]
  PIN q[57]
    DIRECTION OUTPUT ;
    USE SIGNAL ;
    PORT
      LAYER M5 ;
        RECT  91.152 64.716 91.176 64.8 ;
    END
  END q[57]
  PIN q[58]
    DIRECTION OUTPUT ;
    USE SIGNAL ;
    PORT
      LAYER M5 ;
        RECT  91.248 64.716 91.272 64.8 ;
    END
  END q[58]
  PIN q[59]
    DIRECTION OUTPUT ;
    USE SIGNAL ;
    PORT
      LAYER M5 ;
        RECT  91.344 64.716 91.368 64.8 ;
    END
  END q[59]
  PIN q[5]
    DIRECTION OUTPUT ;
    USE SIGNAL ;
    PORT
      LAYER M3 ;
        RECT  102.996 64.763 103.014 64.8 ;
    END
  END q[5]
  PIN q[60]
    DIRECTION OUTPUT ;
    USE SIGNAL ;
    PORT
      LAYER M5 ;
        RECT  91.44 64.716 91.464 64.8 ;
    END
  END q[60]
  PIN q[61]
    DIRECTION OUTPUT ;
    USE SIGNAL ;
    PORT
      LAYER M5 ;
        RECT  91.536 64.716 91.56 64.8 ;
    END
  END q[61]
  PIN q[62]
    DIRECTION OUTPUT ;
    USE SIGNAL ;
    PORT
      LAYER M5 ;
        RECT  91.632 64.716 91.656 64.8 ;
    END
  END q[62]
  PIN q[63]
    DIRECTION OUTPUT ;
    USE SIGNAL ;
    PORT
      LAYER M5 ;
        RECT  91.728 64.716 91.752 64.8 ;
    END
  END q[63]
  PIN q[64]
    DIRECTION OUTPUT ;
    USE SIGNAL ;
    PORT
      LAYER M5 ;
        RECT  91.824 64.716 91.848 64.8 ;
    END
  END q[64]
  PIN q[65]
    DIRECTION OUTPUT ;
    USE SIGNAL ;
    PORT
      LAYER M5 ;
        RECT  91.92 64.716 91.944 64.8 ;
    END
  END q[65]
  PIN q[66]
    DIRECTION OUTPUT ;
    USE SIGNAL ;
    PORT
      LAYER M5 ;
        RECT  92.016 64.716 92.04 64.8 ;
    END
  END q[66]
  PIN q[67]
    DIRECTION OUTPUT ;
    USE SIGNAL ;
    PORT
      LAYER M5 ;
        RECT  92.112 64.716 92.136 64.8 ;
    END
  END q[67]
  PIN q[68]
    DIRECTION OUTPUT ;
    USE SIGNAL ;
    PORT
      LAYER M5 ;
        RECT  92.208 64.716 92.232 64.8 ;
    END
  END q[68]
  PIN q[69]
    DIRECTION OUTPUT ;
    USE SIGNAL ;
    PORT
      LAYER M5 ;
        RECT  92.304 64.716 92.328 64.8 ;
    END
  END q[69]
  PIN q[6]
    DIRECTION OUTPUT ;
    USE SIGNAL ;
    PORT
      LAYER M3 ;
        RECT  103.068 64.763 103.086 64.8 ;
    END
  END q[6]
  PIN q[70]
    DIRECTION OUTPUT ;
    USE SIGNAL ;
    PORT
      LAYER M5 ;
        RECT  92.4 64.716 92.424 64.8 ;
    END
  END q[70]
  PIN q[71]
    DIRECTION OUTPUT ;
    USE SIGNAL ;
    PORT
      LAYER M5 ;
        RECT  92.496 64.716 92.52 64.8 ;
    END
  END q[71]
  PIN q[72]
    DIRECTION OUTPUT ;
    USE SIGNAL ;
    PORT
      LAYER M5 ;
        RECT  92.592 64.716 92.616 64.8 ;
    END
  END q[72]
  PIN q[73]
    DIRECTION OUTPUT ;
    USE SIGNAL ;
    PORT
      LAYER M5 ;
        RECT  92.688 64.716 92.712 64.8 ;
    END
  END q[73]
  PIN q[74]
    DIRECTION OUTPUT ;
    USE SIGNAL ;
    PORT
      LAYER M5 ;
        RECT  92.784 64.716 92.808 64.8 ;
    END
  END q[74]
  PIN q[75]
    DIRECTION OUTPUT ;
    USE SIGNAL ;
    PORT
      LAYER M5 ;
        RECT  92.88 64.716 92.904 64.8 ;
    END
  END q[75]
  PIN q[76]
    DIRECTION OUTPUT ;
    USE SIGNAL ;
    PORT
      LAYER M5 ;
        RECT  92.976 64.716 93 64.8 ;
    END
  END q[76]
  PIN q[77]
    DIRECTION OUTPUT ;
    USE SIGNAL ;
    PORT
      LAYER M5 ;
        RECT  93.072 64.716 93.096 64.8 ;
    END
  END q[77]
  PIN q[78]
    DIRECTION OUTPUT ;
    USE SIGNAL ;
    PORT
      LAYER M5 ;
        RECT  93.168 64.716 93.192 64.8 ;
    END
  END q[78]
  PIN q[79]
    DIRECTION OUTPUT ;
    USE SIGNAL ;
    PORT
      LAYER M5 ;
        RECT  93.264 64.716 93.288 64.8 ;
    END
  END q[79]
  PIN q[7]
    DIRECTION OUTPUT ;
    USE SIGNAL ;
    PORT
      LAYER M3 ;
        RECT  103.14 64.763 103.158 64.8 ;
    END
  END q[7]
  PIN q[80]
    DIRECTION OUTPUT ;
    USE SIGNAL ;
    PORT
      LAYER M5 ;
        RECT  93.36 64.716 93.384 64.8 ;
    END
  END q[80]
  PIN q[81]
    DIRECTION OUTPUT ;
    USE SIGNAL ;
    PORT
      LAYER M5 ;
        RECT  93.456 64.716 93.48 64.8 ;
    END
  END q[81]
  PIN q[82]
    DIRECTION OUTPUT ;
    USE SIGNAL ;
    PORT
      LAYER M5 ;
        RECT  93.552 64.716 93.576 64.8 ;
    END
  END q[82]
  PIN q[83]
    DIRECTION OUTPUT ;
    USE SIGNAL ;
    PORT
      LAYER M5 ;
        RECT  93.648 64.716 93.672 64.8 ;
    END
  END q[83]
  PIN q[84]
    DIRECTION OUTPUT ;
    USE SIGNAL ;
    PORT
      LAYER M5 ;
        RECT  93.744 64.716 93.768 64.8 ;
    END
  END q[84]
  PIN q[85]
    DIRECTION OUTPUT ;
    USE SIGNAL ;
    PORT
      LAYER M5 ;
        RECT  87.696 64.716 87.72 64.8 ;
    END
  END q[85]
  PIN q[86]
    DIRECTION OUTPUT ;
    USE SIGNAL ;
    PORT
      LAYER M5 ;
        RECT  87.792 64.716 87.816 64.8 ;
    END
  END q[86]
  PIN q[87]
    DIRECTION OUTPUT ;
    USE SIGNAL ;
    PORT
      LAYER M5 ;
        RECT  87.888 64.716 87.912 64.8 ;
    END
  END q[87]
  PIN q[88]
    DIRECTION OUTPUT ;
    USE SIGNAL ;
    PORT
      LAYER M5 ;
        RECT  87.984 64.716 88.008 64.8 ;
    END
  END q[88]
  PIN q[89]
    DIRECTION OUTPUT ;
    USE SIGNAL ;
    PORT
      LAYER M5 ;
        RECT  88.08 64.716 88.104 64.8 ;
    END
  END q[89]
  PIN q[8]
    DIRECTION OUTPUT ;
    USE SIGNAL ;
    PORT
      LAYER M3 ;
        RECT  103.212 64.763 103.23 64.8 ;
    END
  END q[8]
  PIN q[90]
    DIRECTION OUTPUT ;
    USE SIGNAL ;
    PORT
      LAYER M5 ;
        RECT  88.176 64.716 88.2 64.8 ;
    END
  END q[90]
  PIN q[91]
    DIRECTION OUTPUT ;
    USE SIGNAL ;
    PORT
      LAYER M5 ;
        RECT  88.272 64.716 88.296 64.8 ;
    END
  END q[91]
  PIN q[92]
    DIRECTION OUTPUT ;
    USE SIGNAL ;
    PORT
      LAYER M5 ;
        RECT  88.368 64.716 88.392 64.8 ;
    END
  END q[92]
  PIN q[93]
    DIRECTION OUTPUT ;
    USE SIGNAL ;
    PORT
      LAYER M5 ;
        RECT  88.464 64.716 88.488 64.8 ;
    END
  END q[93]
  PIN q[94]
    DIRECTION OUTPUT ;
    USE SIGNAL ;
    PORT
      LAYER M5 ;
        RECT  88.56 64.716 88.584 64.8 ;
    END
  END q[94]
  PIN q[95]
    DIRECTION OUTPUT ;
    USE SIGNAL ;
    PORT
      LAYER M5 ;
        RECT  88.656 64.716 88.68 64.8 ;
    END
  END q[95]
  PIN q[96]
    DIRECTION OUTPUT ;
    USE SIGNAL ;
    PORT
      LAYER M5 ;
        RECT  88.752 64.716 88.776 64.8 ;
    END
  END q[96]
  PIN q[97]
    DIRECTION OUTPUT ;
    USE SIGNAL ;
    PORT
      LAYER M5 ;
        RECT  88.848 64.716 88.872 64.8 ;
    END
  END q[97]
  PIN q[98]
    DIRECTION OUTPUT ;
    USE SIGNAL ;
    PORT
      LAYER M5 ;
        RECT  88.944 64.716 88.968 64.8 ;
    END
  END q[98]
  PIN q[99]
    DIRECTION OUTPUT ;
    USE SIGNAL ;
    PORT
      LAYER M5 ;
        RECT  89.04 64.716 89.064 64.8 ;
    END
  END q[99]
  PIN q[9]
    DIRECTION OUTPUT ;
    USE SIGNAL ;
    PORT
      LAYER M3 ;
        RECT  103.284 64.763 103.302 64.8 ;
    END
  END q[9]
  PIN rst_n
    DIRECTION INPUT ;
    USE SIGNAL ;
    PORT
      LAYER M4 ;
        RECT  0 45.072 0.084 45.096 ;
    END
  END rst_n
  PIN v
    DIRECTION INPUT ;
    USE SIGNAL ;
    PORT
      LAYER M4 ;
        RECT  0 45.168 0.084 45.192 ;
    END
  END v
  PIN vo
    DIRECTION OUTPUT ;
    USE SIGNAL ;
    PORT
      LAYER M3 ;
        RECT  107.244 64.763 107.262 64.8 ;
    END
  END vo
  PIN x[0]
    DIRECTION INPUT ;
    USE SIGNAL ;
    PORT
      LAYER M5 ;
        RECT  80.592 0 80.616 0.084 ;
    END
  END x[0]
  PIN x[1000]
    DIRECTION INPUT ;
    USE SIGNAL ;
    PORT
      LAYER M3 ;
        RECT  46.62 0 46.638 0.037 ;
    END
  END x[1000]
  PIN x[1001]
    DIRECTION INPUT ;
    USE SIGNAL ;
    PORT
      LAYER M3 ;
        RECT  46.692 0 46.71 0.037 ;
    END
  END x[1001]
  PIN x[1002]
    DIRECTION INPUT ;
    USE SIGNAL ;
    PORT
      LAYER M3 ;
        RECT  46.764 0 46.782 0.037 ;
    END
  END x[1002]
  PIN x[1003]
    DIRECTION INPUT ;
    USE SIGNAL ;
    PORT
      LAYER M3 ;
        RECT  46.836 0 46.854 0.037 ;
    END
  END x[1003]
  PIN x[1004]
    DIRECTION INPUT ;
    USE SIGNAL ;
    PORT
      LAYER M3 ;
        RECT  46.908 0 46.926 0.037 ;
    END
  END x[1004]
  PIN x[1005]
    DIRECTION INPUT ;
    USE SIGNAL ;
    PORT
      LAYER M3 ;
        RECT  46.98 0 46.998 0.037 ;
    END
  END x[1005]
  PIN x[1006]
    DIRECTION INPUT ;
    USE SIGNAL ;
    PORT
      LAYER M3 ;
        RECT  47.052 0 47.07 0.037 ;
    END
  END x[1006]
  PIN x[1007]
    DIRECTION INPUT ;
    USE SIGNAL ;
    PORT
      LAYER M3 ;
        RECT  47.124 0 47.142 0.037 ;
    END
  END x[1007]
  PIN x[1008]
    DIRECTION INPUT ;
    USE SIGNAL ;
    PORT
      LAYER M3 ;
        RECT  47.196 0 47.214 0.037 ;
    END
  END x[1008]
  PIN x[1009]
    DIRECTION INPUT ;
    USE SIGNAL ;
    PORT
      LAYER M3 ;
        RECT  47.268 0 47.286 0.037 ;
    END
  END x[1009]
  PIN x[100]
    DIRECTION INPUT ;
    USE SIGNAL ;
    PORT
      LAYER M5 ;
        RECT  77.904 0 77.928 0.084 ;
    END
  END x[100]
  PIN x[1010]
    DIRECTION INPUT ;
    USE SIGNAL ;
    PORT
      LAYER M3 ;
        RECT  47.34 0 47.358 0.037 ;
    END
  END x[1010]
  PIN x[1011]
    DIRECTION INPUT ;
    USE SIGNAL ;
    PORT
      LAYER M3 ;
        RECT  47.412 0 47.43 0.037 ;
    END
  END x[1011]
  PIN x[1012]
    DIRECTION INPUT ;
    USE SIGNAL ;
    PORT
      LAYER M3 ;
        RECT  47.484 0 47.502 0.037 ;
    END
  END x[1012]
  PIN x[1013]
    DIRECTION INPUT ;
    USE SIGNAL ;
    PORT
      LAYER M3 ;
        RECT  47.556 0 47.574 0.037 ;
    END
  END x[1013]
  PIN x[1014]
    DIRECTION INPUT ;
    USE SIGNAL ;
    PORT
      LAYER M3 ;
        RECT  47.628 0 47.646 0.037 ;
    END
  END x[1014]
  PIN x[1015]
    DIRECTION INPUT ;
    USE SIGNAL ;
    PORT
      LAYER M3 ;
        RECT  47.7 0 47.718 0.037 ;
    END
  END x[1015]
  PIN x[1016]
    DIRECTION INPUT ;
    USE SIGNAL ;
    PORT
      LAYER M3 ;
        RECT  47.772 0 47.79 0.037 ;
    END
  END x[1016]
  PIN x[1017]
    DIRECTION INPUT ;
    USE SIGNAL ;
    PORT
      LAYER M3 ;
        RECT  47.844 0 47.862 0.037 ;
    END
  END x[1017]
  PIN x[1018]
    DIRECTION INPUT ;
    USE SIGNAL ;
    PORT
      LAYER M3 ;
        RECT  47.916 0 47.934 0.037 ;
    END
  END x[1018]
  PIN x[1019]
    DIRECTION INPUT ;
    USE SIGNAL ;
    PORT
      LAYER M3 ;
        RECT  47.988 0 48.006 0.037 ;
    END
  END x[1019]
  PIN x[101]
    DIRECTION INPUT ;
    USE SIGNAL ;
    PORT
      LAYER M5 ;
        RECT  78 0 78.024 0.084 ;
    END
  END x[101]
  PIN x[1020]
    DIRECTION INPUT ;
    USE SIGNAL ;
    PORT
      LAYER M3 ;
        RECT  48.06 0 48.078 0.037 ;
    END
  END x[1020]
  PIN x[1021]
    DIRECTION INPUT ;
    USE SIGNAL ;
    PORT
      LAYER M3 ;
        RECT  48.132 0 48.15 0.037 ;
    END
  END x[1021]
  PIN x[1022]
    DIRECTION INPUT ;
    USE SIGNAL ;
    PORT
      LAYER M3 ;
        RECT  48.204 0 48.222 0.037 ;
    END
  END x[1022]
  PIN x[1023]
    DIRECTION INPUT ;
    USE SIGNAL ;
    PORT
      LAYER M3 ;
        RECT  48.276 0 48.294 0.037 ;
    END
  END x[1023]
  PIN x[102]
    DIRECTION INPUT ;
    USE SIGNAL ;
    PORT
      LAYER M5 ;
        RECT  78.096 0 78.12 0.084 ;
    END
  END x[102]
  PIN x[103]
    DIRECTION INPUT ;
    USE SIGNAL ;
    PORT
      LAYER M5 ;
        RECT  78.192 0 78.216 0.084 ;
    END
  END x[103]
  PIN x[104]
    DIRECTION INPUT ;
    USE SIGNAL ;
    PORT
      LAYER M5 ;
        RECT  78.288 0 78.312 0.084 ;
    END
  END x[104]
  PIN x[105]
    DIRECTION INPUT ;
    USE SIGNAL ;
    PORT
      LAYER M5 ;
        RECT  78.384 0 78.408 0.084 ;
    END
  END x[105]
  PIN x[106]
    DIRECTION INPUT ;
    USE SIGNAL ;
    PORT
      LAYER M5 ;
        RECT  78.48 0 78.504 0.084 ;
    END
  END x[106]
  PIN x[107]
    DIRECTION INPUT ;
    USE SIGNAL ;
    PORT
      LAYER M5 ;
        RECT  78.576 0 78.6 0.084 ;
    END
  END x[107]
  PIN x[108]
    DIRECTION INPUT ;
    USE SIGNAL ;
    PORT
      LAYER M5 ;
        RECT  78.672 0 78.696 0.084 ;
    END
  END x[108]
  PIN x[109]
    DIRECTION INPUT ;
    USE SIGNAL ;
    PORT
      LAYER M5 ;
        RECT  78.768 0 78.792 0.084 ;
    END
  END x[109]
  PIN x[10]
    DIRECTION INPUT ;
    USE SIGNAL ;
    PORT
      LAYER M5 ;
        RECT  81.552 0 81.576 0.084 ;
    END
  END x[10]
  PIN x[110]
    DIRECTION INPUT ;
    USE SIGNAL ;
    PORT
      LAYER M5 ;
        RECT  78.864 0 78.888 0.084 ;
    END
  END x[110]
  PIN x[111]
    DIRECTION INPUT ;
    USE SIGNAL ;
    PORT
      LAYER M5 ;
        RECT  78.96 0 78.984 0.084 ;
    END
  END x[111]
  PIN x[112]
    DIRECTION INPUT ;
    USE SIGNAL ;
    PORT
      LAYER M5 ;
        RECT  79.056 0 79.08 0.084 ;
    END
  END x[112]
  PIN x[113]
    DIRECTION INPUT ;
    USE SIGNAL ;
    PORT
      LAYER M5 ;
        RECT  79.152 0 79.176 0.084 ;
    END
  END x[113]
  PIN x[114]
    DIRECTION INPUT ;
    USE SIGNAL ;
    PORT
      LAYER M5 ;
        RECT  79.248 0 79.272 0.084 ;
    END
  END x[114]
  PIN x[115]
    DIRECTION INPUT ;
    USE SIGNAL ;
    PORT
      LAYER M5 ;
        RECT  79.344 0 79.368 0.084 ;
    END
  END x[115]
  PIN x[116]
    DIRECTION INPUT ;
    USE SIGNAL ;
    PORT
      LAYER M5 ;
        RECT  79.44 0 79.464 0.084 ;
    END
  END x[116]
  PIN x[117]
    DIRECTION INPUT ;
    USE SIGNAL ;
    PORT
      LAYER M5 ;
        RECT  79.536 0 79.56 0.084 ;
    END
  END x[117]
  PIN x[118]
    DIRECTION INPUT ;
    USE SIGNAL ;
    PORT
      LAYER M5 ;
        RECT  79.632 0 79.656 0.084 ;
    END
  END x[118]
  PIN x[119]
    DIRECTION INPUT ;
    USE SIGNAL ;
    PORT
      LAYER M5 ;
        RECT  79.728 0 79.752 0.084 ;
    END
  END x[119]
  PIN x[11]
    DIRECTION INPUT ;
    USE SIGNAL ;
    PORT
      LAYER M5 ;
        RECT  81.648 0 81.672 0.084 ;
    END
  END x[11]
  PIN x[120]
    DIRECTION INPUT ;
    USE SIGNAL ;
    PORT
      LAYER M5 ;
        RECT  79.824 0 79.848 0.084 ;
    END
  END x[120]
  PIN x[121]
    DIRECTION INPUT ;
    USE SIGNAL ;
    PORT
      LAYER M5 ;
        RECT  79.92 0 79.944 0.084 ;
    END
  END x[121]
  PIN x[122]
    DIRECTION INPUT ;
    USE SIGNAL ;
    PORT
      LAYER M5 ;
        RECT  80.016 0 80.04 0.084 ;
    END
  END x[122]
  PIN x[123]
    DIRECTION INPUT ;
    USE SIGNAL ;
    PORT
      LAYER M5 ;
        RECT  80.112 0 80.136 0.084 ;
    END
  END x[123]
  PIN x[124]
    DIRECTION INPUT ;
    USE SIGNAL ;
    PORT
      LAYER M5 ;
        RECT  80.208 0 80.232 0.084 ;
    END
  END x[124]
  PIN x[125]
    DIRECTION INPUT ;
    USE SIGNAL ;
    PORT
      LAYER M5 ;
        RECT  80.304 0 80.328 0.084 ;
    END
  END x[125]
  PIN x[126]
    DIRECTION INPUT ;
    USE SIGNAL ;
    PORT
      LAYER M5 ;
        RECT  80.4 0 80.424 0.084 ;
    END
  END x[126]
  PIN x[127]
    DIRECTION INPUT ;
    USE SIGNAL ;
    PORT
      LAYER M5 ;
        RECT  80.496 0 80.52 0.084 ;
    END
  END x[127]
  PIN x[128]
    DIRECTION INPUT ;
    USE SIGNAL ;
    PORT
      LAYER M5 ;
        RECT  92.88 0 92.904 0.084 ;
    END
  END x[128]
  PIN x[129]
    DIRECTION INPUT ;
    USE SIGNAL ;
    PORT
      LAYER M5 ;
        RECT  92.976 0 93 0.084 ;
    END
  END x[129]
  PIN x[12]
    DIRECTION INPUT ;
    USE SIGNAL ;
    PORT
      LAYER M5 ;
        RECT  81.744 0 81.768 0.084 ;
    END
  END x[12]
  PIN x[130]
    DIRECTION INPUT ;
    USE SIGNAL ;
    PORT
      LAYER M5 ;
        RECT  93.072 0 93.096 0.084 ;
    END
  END x[130]
  PIN x[131]
    DIRECTION INPUT ;
    USE SIGNAL ;
    PORT
      LAYER M5 ;
        RECT  93.168 0 93.192 0.084 ;
    END
  END x[131]
  PIN x[132]
    DIRECTION INPUT ;
    USE SIGNAL ;
    PORT
      LAYER M5 ;
        RECT  93.264 0 93.288 0.084 ;
    END
  END x[132]
  PIN x[133]
    DIRECTION INPUT ;
    USE SIGNAL ;
    PORT
      LAYER M5 ;
        RECT  93.36 0 93.384 0.084 ;
    END
  END x[133]
  PIN x[134]
    DIRECTION INPUT ;
    USE SIGNAL ;
    PORT
      LAYER M5 ;
        RECT  93.456 0 93.48 0.084 ;
    END
  END x[134]
  PIN x[135]
    DIRECTION INPUT ;
    USE SIGNAL ;
    PORT
      LAYER M5 ;
        RECT  93.552 0 93.576 0.084 ;
    END
  END x[135]
  PIN x[136]
    DIRECTION INPUT ;
    USE SIGNAL ;
    PORT
      LAYER M5 ;
        RECT  93.648 0 93.672 0.084 ;
    END
  END x[136]
  PIN x[137]
    DIRECTION INPUT ;
    USE SIGNAL ;
    PORT
      LAYER M5 ;
        RECT  93.744 0 93.768 0.084 ;
    END
  END x[137]
  PIN x[138]
    DIRECTION INPUT ;
    USE SIGNAL ;
    PORT
      LAYER M5 ;
        RECT  93.84 0 93.864 0.084 ;
    END
  END x[138]
  PIN x[139]
    DIRECTION INPUT ;
    USE SIGNAL ;
    PORT
      LAYER M5 ;
        RECT  93.936 0 93.96 0.084 ;
    END
  END x[139]
  PIN x[13]
    DIRECTION INPUT ;
    USE SIGNAL ;
    PORT
      LAYER M5 ;
        RECT  81.84 0 81.864 0.084 ;
    END
  END x[13]
  PIN x[140]
    DIRECTION INPUT ;
    USE SIGNAL ;
    PORT
      LAYER M5 ;
        RECT  94.032 0 94.056 0.084 ;
    END
  END x[140]
  PIN x[141]
    DIRECTION INPUT ;
    USE SIGNAL ;
    PORT
      LAYER M5 ;
        RECT  94.128 0 94.152 0.084 ;
    END
  END x[141]
  PIN x[142]
    DIRECTION INPUT ;
    USE SIGNAL ;
    PORT
      LAYER M5 ;
        RECT  94.224 0 94.248 0.084 ;
    END
  END x[142]
  PIN x[143]
    DIRECTION INPUT ;
    USE SIGNAL ;
    PORT
      LAYER M5 ;
        RECT  94.32 0 94.344 0.084 ;
    END
  END x[143]
  PIN x[144]
    DIRECTION INPUT ;
    USE SIGNAL ;
    PORT
      LAYER M5 ;
        RECT  94.416 0 94.44 0.084 ;
    END
  END x[144]
  PIN x[145]
    DIRECTION INPUT ;
    USE SIGNAL ;
    PORT
      LAYER M5 ;
        RECT  94.512 0 94.536 0.084 ;
    END
  END x[145]
  PIN x[146]
    DIRECTION INPUT ;
    USE SIGNAL ;
    PORT
      LAYER M5 ;
        RECT  94.608 0 94.632 0.084 ;
    END
  END x[146]
  PIN x[147]
    DIRECTION INPUT ;
    USE SIGNAL ;
    PORT
      LAYER M5 ;
        RECT  94.704 0 94.728 0.084 ;
    END
  END x[147]
  PIN x[148]
    DIRECTION INPUT ;
    USE SIGNAL ;
    PORT
      LAYER M5 ;
        RECT  94.8 0 94.824 0.084 ;
    END
  END x[148]
  PIN x[149]
    DIRECTION INPUT ;
    USE SIGNAL ;
    PORT
      LAYER M5 ;
        RECT  94.896 0 94.92 0.084 ;
    END
  END x[149]
  PIN x[14]
    DIRECTION INPUT ;
    USE SIGNAL ;
    PORT
      LAYER M5 ;
        RECT  81.936 0 81.96 0.084 ;
    END
  END x[14]
  PIN x[150]
    DIRECTION INPUT ;
    USE SIGNAL ;
    PORT
      LAYER M5 ;
        RECT  94.992 0 95.016 0.084 ;
    END
  END x[150]
  PIN x[151]
    DIRECTION INPUT ;
    USE SIGNAL ;
    PORT
      LAYER M5 ;
        RECT  95.088 0 95.112 0.084 ;
    END
  END x[151]
  PIN x[152]
    DIRECTION INPUT ;
    USE SIGNAL ;
    PORT
      LAYER M5 ;
        RECT  95.184 0 95.208 0.084 ;
    END
  END x[152]
  PIN x[153]
    DIRECTION INPUT ;
    USE SIGNAL ;
    PORT
      LAYER M5 ;
        RECT  95.28 0 95.304 0.084 ;
    END
  END x[153]
  PIN x[154]
    DIRECTION INPUT ;
    USE SIGNAL ;
    PORT
      LAYER M5 ;
        RECT  95.376 0 95.4 0.084 ;
    END
  END x[154]
  PIN x[155]
    DIRECTION INPUT ;
    USE SIGNAL ;
    PORT
      LAYER M5 ;
        RECT  95.472 0 95.496 0.084 ;
    END
  END x[155]
  PIN x[156]
    DIRECTION INPUT ;
    USE SIGNAL ;
    PORT
      LAYER M5 ;
        RECT  95.568 0 95.592 0.084 ;
    END
  END x[156]
  PIN x[157]
    DIRECTION INPUT ;
    USE SIGNAL ;
    PORT
      LAYER M5 ;
        RECT  95.664 0 95.688 0.084 ;
    END
  END x[157]
  PIN x[158]
    DIRECTION INPUT ;
    USE SIGNAL ;
    PORT
      LAYER M5 ;
        RECT  95.76 0 95.784 0.084 ;
    END
  END x[158]
  PIN x[159]
    DIRECTION INPUT ;
    USE SIGNAL ;
    PORT
      LAYER M5 ;
        RECT  95.856 0 95.88 0.084 ;
    END
  END x[159]
  PIN x[15]
    DIRECTION INPUT ;
    USE SIGNAL ;
    PORT
      LAYER M5 ;
        RECT  82.032 0 82.056 0.084 ;
    END
  END x[15]
  PIN x[160]
    DIRECTION INPUT ;
    USE SIGNAL ;
    PORT
      LAYER M5 ;
        RECT  83.664 0 83.688 0.084 ;
    END
  END x[160]
  PIN x[161]
    DIRECTION INPUT ;
    USE SIGNAL ;
    PORT
      LAYER M5 ;
        RECT  83.76 0 83.784 0.084 ;
    END
  END x[161]
  PIN x[162]
    DIRECTION INPUT ;
    USE SIGNAL ;
    PORT
      LAYER M5 ;
        RECT  83.856 0 83.88 0.084 ;
    END
  END x[162]
  PIN x[163]
    DIRECTION INPUT ;
    USE SIGNAL ;
    PORT
      LAYER M5 ;
        RECT  83.952 0 83.976 0.084 ;
    END
  END x[163]
  PIN x[164]
    DIRECTION INPUT ;
    USE SIGNAL ;
    PORT
      LAYER M5 ;
        RECT  84.048 0 84.072 0.084 ;
    END
  END x[164]
  PIN x[165]
    DIRECTION INPUT ;
    USE SIGNAL ;
    PORT
      LAYER M5 ;
        RECT  84.144 0 84.168 0.084 ;
    END
  END x[165]
  PIN x[166]
    DIRECTION INPUT ;
    USE SIGNAL ;
    PORT
      LAYER M5 ;
        RECT  84.24 0 84.264 0.084 ;
    END
  END x[166]
  PIN x[167]
    DIRECTION INPUT ;
    USE SIGNAL ;
    PORT
      LAYER M5 ;
        RECT  84.336 0 84.36 0.084 ;
    END
  END x[167]
  PIN x[168]
    DIRECTION INPUT ;
    USE SIGNAL ;
    PORT
      LAYER M5 ;
        RECT  84.432 0 84.456 0.084 ;
    END
  END x[168]
  PIN x[169]
    DIRECTION INPUT ;
    USE SIGNAL ;
    PORT
      LAYER M5 ;
        RECT  84.528 0 84.552 0.084 ;
    END
  END x[169]
  PIN x[16]
    DIRECTION INPUT ;
    USE SIGNAL ;
    PORT
      LAYER M5 ;
        RECT  82.128 0 82.152 0.084 ;
    END
  END x[16]
  PIN x[170]
    DIRECTION INPUT ;
    USE SIGNAL ;
    PORT
      LAYER M5 ;
        RECT  84.624 0 84.648 0.084 ;
    END
  END x[170]
  PIN x[171]
    DIRECTION INPUT ;
    USE SIGNAL ;
    PORT
      LAYER M5 ;
        RECT  84.72 0 84.744 0.084 ;
    END
  END x[171]
  PIN x[172]
    DIRECTION INPUT ;
    USE SIGNAL ;
    PORT
      LAYER M5 ;
        RECT  84.816 0 84.84 0.084 ;
    END
  END x[172]
  PIN x[173]
    DIRECTION INPUT ;
    USE SIGNAL ;
    PORT
      LAYER M5 ;
        RECT  84.912 0 84.936 0.084 ;
    END
  END x[173]
  PIN x[174]
    DIRECTION INPUT ;
    USE SIGNAL ;
    PORT
      LAYER M5 ;
        RECT  85.008 0 85.032 0.084 ;
    END
  END x[174]
  PIN x[175]
    DIRECTION INPUT ;
    USE SIGNAL ;
    PORT
      LAYER M5 ;
        RECT  85.104 0 85.128 0.084 ;
    END
  END x[175]
  PIN x[176]
    DIRECTION INPUT ;
    USE SIGNAL ;
    PORT
      LAYER M5 ;
        RECT  85.2 0 85.224 0.084 ;
    END
  END x[176]
  PIN x[177]
    DIRECTION INPUT ;
    USE SIGNAL ;
    PORT
      LAYER M5 ;
        RECT  85.296 0 85.32 0.084 ;
    END
  END x[177]
  PIN x[178]
    DIRECTION INPUT ;
    USE SIGNAL ;
    PORT
      LAYER M5 ;
        RECT  85.392 0 85.416 0.084 ;
    END
  END x[178]
  PIN x[179]
    DIRECTION INPUT ;
    USE SIGNAL ;
    PORT
      LAYER M5 ;
        RECT  85.488 0 85.512 0.084 ;
    END
  END x[179]
  PIN x[17]
    DIRECTION INPUT ;
    USE SIGNAL ;
    PORT
      LAYER M5 ;
        RECT  82.224 0 82.248 0.084 ;
    END
  END x[17]
  PIN x[180]
    DIRECTION INPUT ;
    USE SIGNAL ;
    PORT
      LAYER M5 ;
        RECT  85.584 0 85.608 0.084 ;
    END
  END x[180]
  PIN x[181]
    DIRECTION INPUT ;
    USE SIGNAL ;
    PORT
      LAYER M5 ;
        RECT  85.68 0 85.704 0.084 ;
    END
  END x[181]
  PIN x[182]
    DIRECTION INPUT ;
    USE SIGNAL ;
    PORT
      LAYER M5 ;
        RECT  85.776 0 85.8 0.084 ;
    END
  END x[182]
  PIN x[183]
    DIRECTION INPUT ;
    USE SIGNAL ;
    PORT
      LAYER M5 ;
        RECT  85.872 0 85.896 0.084 ;
    END
  END x[183]
  PIN x[184]
    DIRECTION INPUT ;
    USE SIGNAL ;
    PORT
      LAYER M5 ;
        RECT  85.968 0 85.992 0.084 ;
    END
  END x[184]
  PIN x[185]
    DIRECTION INPUT ;
    USE SIGNAL ;
    PORT
      LAYER M5 ;
        RECT  86.064 0 86.088 0.084 ;
    END
  END x[185]
  PIN x[186]
    DIRECTION INPUT ;
    USE SIGNAL ;
    PORT
      LAYER M5 ;
        RECT  86.16 0 86.184 0.084 ;
    END
  END x[186]
  PIN x[187]
    DIRECTION INPUT ;
    USE SIGNAL ;
    PORT
      LAYER M5 ;
        RECT  86.256 0 86.28 0.084 ;
    END
  END x[187]
  PIN x[188]
    DIRECTION INPUT ;
    USE SIGNAL ;
    PORT
      LAYER M5 ;
        RECT  86.352 0 86.376 0.084 ;
    END
  END x[188]
  PIN x[189]
    DIRECTION INPUT ;
    USE SIGNAL ;
    PORT
      LAYER M5 ;
        RECT  86.448 0 86.472 0.084 ;
    END
  END x[189]
  PIN x[18]
    DIRECTION INPUT ;
    USE SIGNAL ;
    PORT
      LAYER M5 ;
        RECT  82.32 0 82.344 0.084 ;
    END
  END x[18]
  PIN x[190]
    DIRECTION INPUT ;
    USE SIGNAL ;
    PORT
      LAYER M5 ;
        RECT  86.544 0 86.568 0.084 ;
    END
  END x[190]
  PIN x[191]
    DIRECTION INPUT ;
    USE SIGNAL ;
    PORT
      LAYER M5 ;
        RECT  86.64 0 86.664 0.084 ;
    END
  END x[191]
  PIN x[192]
    DIRECTION INPUT ;
    USE SIGNAL ;
    PORT
      LAYER M5 ;
        RECT  86.736 0 86.76 0.084 ;
    END
  END x[192]
  PIN x[193]
    DIRECTION INPUT ;
    USE SIGNAL ;
    PORT
      LAYER M5 ;
        RECT  86.832 0 86.856 0.084 ;
    END
  END x[193]
  PIN x[194]
    DIRECTION INPUT ;
    USE SIGNAL ;
    PORT
      LAYER M5 ;
        RECT  86.928 0 86.952 0.084 ;
    END
  END x[194]
  PIN x[195]
    DIRECTION INPUT ;
    USE SIGNAL ;
    PORT
      LAYER M5 ;
        RECT  87.024 0 87.048 0.084 ;
    END
  END x[195]
  PIN x[196]
    DIRECTION INPUT ;
    USE SIGNAL ;
    PORT
      LAYER M5 ;
        RECT  87.12 0 87.144 0.084 ;
    END
  END x[196]
  PIN x[197]
    DIRECTION INPUT ;
    USE SIGNAL ;
    PORT
      LAYER M5 ;
        RECT  87.216 0 87.24 0.084 ;
    END
  END x[197]
  PIN x[198]
    DIRECTION INPUT ;
    USE SIGNAL ;
    PORT
      LAYER M5 ;
        RECT  87.312 0 87.336 0.084 ;
    END
  END x[198]
  PIN x[199]
    DIRECTION INPUT ;
    USE SIGNAL ;
    PORT
      LAYER M5 ;
        RECT  87.408 0 87.432 0.084 ;
    END
  END x[199]
  PIN x[19]
    DIRECTION INPUT ;
    USE SIGNAL ;
    PORT
      LAYER M5 ;
        RECT  82.416 0 82.44 0.084 ;
    END
  END x[19]
  PIN x[1]
    DIRECTION INPUT ;
    USE SIGNAL ;
    PORT
      LAYER M5 ;
        RECT  80.688 0 80.712 0.084 ;
    END
  END x[1]
  PIN x[200]
    DIRECTION INPUT ;
    USE SIGNAL ;
    PORT
      LAYER M5 ;
        RECT  87.504 0 87.528 0.084 ;
    END
  END x[200]
  PIN x[201]
    DIRECTION INPUT ;
    USE SIGNAL ;
    PORT
      LAYER M5 ;
        RECT  87.6 0 87.624 0.084 ;
    END
  END x[201]
  PIN x[202]
    DIRECTION INPUT ;
    USE SIGNAL ;
    PORT
      LAYER M5 ;
        RECT  87.696 0 87.72 0.084 ;
    END
  END x[202]
  PIN x[203]
    DIRECTION INPUT ;
    USE SIGNAL ;
    PORT
      LAYER M5 ;
        RECT  87.792 0 87.816 0.084 ;
    END
  END x[203]
  PIN x[204]
    DIRECTION INPUT ;
    USE SIGNAL ;
    PORT
      LAYER M5 ;
        RECT  87.888 0 87.912 0.084 ;
    END
  END x[204]
  PIN x[205]
    DIRECTION INPUT ;
    USE SIGNAL ;
    PORT
      LAYER M5 ;
        RECT  87.984 0 88.008 0.084 ;
    END
  END x[205]
  PIN x[206]
    DIRECTION INPUT ;
    USE SIGNAL ;
    PORT
      LAYER M5 ;
        RECT  88.08 0 88.104 0.084 ;
    END
  END x[206]
  PIN x[207]
    DIRECTION INPUT ;
    USE SIGNAL ;
    PORT
      LAYER M5 ;
        RECT  88.176 0 88.2 0.084 ;
    END
  END x[207]
  PIN x[208]
    DIRECTION INPUT ;
    USE SIGNAL ;
    PORT
      LAYER M5 ;
        RECT  88.272 0 88.296 0.084 ;
    END
  END x[208]
  PIN x[209]
    DIRECTION INPUT ;
    USE SIGNAL ;
    PORT
      LAYER M5 ;
        RECT  88.368 0 88.392 0.084 ;
    END
  END x[209]
  PIN x[20]
    DIRECTION INPUT ;
    USE SIGNAL ;
    PORT
      LAYER M5 ;
        RECT  82.512 0 82.536 0.084 ;
    END
  END x[20]
  PIN x[210]
    DIRECTION INPUT ;
    USE SIGNAL ;
    PORT
      LAYER M5 ;
        RECT  88.464 0 88.488 0.084 ;
    END
  END x[210]
  PIN x[211]
    DIRECTION INPUT ;
    USE SIGNAL ;
    PORT
      LAYER M5 ;
        RECT  88.56 0 88.584 0.084 ;
    END
  END x[211]
  PIN x[212]
    DIRECTION INPUT ;
    USE SIGNAL ;
    PORT
      LAYER M5 ;
        RECT  88.656 0 88.68 0.084 ;
    END
  END x[212]
  PIN x[213]
    DIRECTION INPUT ;
    USE SIGNAL ;
    PORT
      LAYER M5 ;
        RECT  88.752 0 88.776 0.084 ;
    END
  END x[213]
  PIN x[214]
    DIRECTION INPUT ;
    USE SIGNAL ;
    PORT
      LAYER M5 ;
        RECT  88.848 0 88.872 0.084 ;
    END
  END x[214]
  PIN x[215]
    DIRECTION INPUT ;
    USE SIGNAL ;
    PORT
      LAYER M5 ;
        RECT  88.944 0 88.968 0.084 ;
    END
  END x[215]
  PIN x[216]
    DIRECTION INPUT ;
    USE SIGNAL ;
    PORT
      LAYER M5 ;
        RECT  89.04 0 89.064 0.084 ;
    END
  END x[216]
  PIN x[217]
    DIRECTION INPUT ;
    USE SIGNAL ;
    PORT
      LAYER M5 ;
        RECT  89.136 0 89.16 0.084 ;
    END
  END x[217]
  PIN x[218]
    DIRECTION INPUT ;
    USE SIGNAL ;
    PORT
      LAYER M5 ;
        RECT  89.232 0 89.256 0.084 ;
    END
  END x[218]
  PIN x[219]
    DIRECTION INPUT ;
    USE SIGNAL ;
    PORT
      LAYER M5 ;
        RECT  89.328 0 89.352 0.084 ;
    END
  END x[219]
  PIN x[21]
    DIRECTION INPUT ;
    USE SIGNAL ;
    PORT
      LAYER M5 ;
        RECT  82.608 0 82.632 0.084 ;
    END
  END x[21]
  PIN x[220]
    DIRECTION INPUT ;
    USE SIGNAL ;
    PORT
      LAYER M5 ;
        RECT  89.424 0 89.448 0.084 ;
    END
  END x[220]
  PIN x[221]
    DIRECTION INPUT ;
    USE SIGNAL ;
    PORT
      LAYER M5 ;
        RECT  89.52 0 89.544 0.084 ;
    END
  END x[221]
  PIN x[222]
    DIRECTION INPUT ;
    USE SIGNAL ;
    PORT
      LAYER M5 ;
        RECT  89.616 0 89.64 0.084 ;
    END
  END x[222]
  PIN x[223]
    DIRECTION INPUT ;
    USE SIGNAL ;
    PORT
      LAYER M5 ;
        RECT  89.712 0 89.736 0.084 ;
    END
  END x[223]
  PIN x[224]
    DIRECTION INPUT ;
    USE SIGNAL ;
    PORT
      LAYER M3 ;
        RECT  86.94 0 86.958 0.037 ;
    END
  END x[224]
  PIN x[225]
    DIRECTION INPUT ;
    USE SIGNAL ;
    PORT
      LAYER M3 ;
        RECT  87.012 0 87.03 0.037 ;
    END
  END x[225]
  PIN x[226]
    DIRECTION INPUT ;
    USE SIGNAL ;
    PORT
      LAYER M3 ;
        RECT  87.084 0 87.102 0.037 ;
    END
  END x[226]
  PIN x[227]
    DIRECTION INPUT ;
    USE SIGNAL ;
    PORT
      LAYER M3 ;
        RECT  87.156 0 87.174 0.037 ;
    END
  END x[227]
  PIN x[228]
    DIRECTION INPUT ;
    USE SIGNAL ;
    PORT
      LAYER M3 ;
        RECT  87.228 0 87.246 0.037 ;
    END
  END x[228]
  PIN x[229]
    DIRECTION INPUT ;
    USE SIGNAL ;
    PORT
      LAYER M3 ;
        RECT  87.3 0 87.318 0.037 ;
    END
  END x[229]
  PIN x[22]
    DIRECTION INPUT ;
    USE SIGNAL ;
    PORT
      LAYER M5 ;
        RECT  82.704 0 82.728 0.084 ;
    END
  END x[22]
  PIN x[230]
    DIRECTION INPUT ;
    USE SIGNAL ;
    PORT
      LAYER M3 ;
        RECT  87.372 0 87.39 0.037 ;
    END
  END x[230]
  PIN x[231]
    DIRECTION INPUT ;
    USE SIGNAL ;
    PORT
      LAYER M3 ;
        RECT  87.444 0 87.462 0.037 ;
    END
  END x[231]
  PIN x[232]
    DIRECTION INPUT ;
    USE SIGNAL ;
    PORT
      LAYER M3 ;
        RECT  87.516 0 87.534 0.037 ;
    END
  END x[232]
  PIN x[233]
    DIRECTION INPUT ;
    USE SIGNAL ;
    PORT
      LAYER M3 ;
        RECT  87.588 0 87.606 0.037 ;
    END
  END x[233]
  PIN x[234]
    DIRECTION INPUT ;
    USE SIGNAL ;
    PORT
      LAYER M3 ;
        RECT  87.66 0 87.678 0.037 ;
    END
  END x[234]
  PIN x[235]
    DIRECTION INPUT ;
    USE SIGNAL ;
    PORT
      LAYER M3 ;
        RECT  87.732 0 87.75 0.037 ;
    END
  END x[235]
  PIN x[236]
    DIRECTION INPUT ;
    USE SIGNAL ;
    PORT
      LAYER M3 ;
        RECT  87.804 0 87.822 0.037 ;
    END
  END x[236]
  PIN x[237]
    DIRECTION INPUT ;
    USE SIGNAL ;
    PORT
      LAYER M3 ;
        RECT  87.876 0 87.894 0.037 ;
    END
  END x[237]
  PIN x[238]
    DIRECTION INPUT ;
    USE SIGNAL ;
    PORT
      LAYER M3 ;
        RECT  87.948 0 87.966 0.037 ;
    END
  END x[238]
  PIN x[239]
    DIRECTION INPUT ;
    USE SIGNAL ;
    PORT
      LAYER M3 ;
        RECT  88.02 0 88.038 0.037 ;
    END
  END x[239]
  PIN x[23]
    DIRECTION INPUT ;
    USE SIGNAL ;
    PORT
      LAYER M5 ;
        RECT  82.8 0 82.824 0.084 ;
    END
  END x[23]
  PIN x[240]
    DIRECTION INPUT ;
    USE SIGNAL ;
    PORT
      LAYER M3 ;
        RECT  88.092 0 88.11 0.037 ;
    END
  END x[240]
  PIN x[241]
    DIRECTION INPUT ;
    USE SIGNAL ;
    PORT
      LAYER M3 ;
        RECT  88.164 0 88.182 0.037 ;
    END
  END x[241]
  PIN x[242]
    DIRECTION INPUT ;
    USE SIGNAL ;
    PORT
      LAYER M3 ;
        RECT  88.236 0 88.254 0.037 ;
    END
  END x[242]
  PIN x[243]
    DIRECTION INPUT ;
    USE SIGNAL ;
    PORT
      LAYER M3 ;
        RECT  88.308 0 88.326 0.037 ;
    END
  END x[243]
  PIN x[244]
    DIRECTION INPUT ;
    USE SIGNAL ;
    PORT
      LAYER M3 ;
        RECT  88.38 0 88.398 0.037 ;
    END
  END x[244]
  PIN x[245]
    DIRECTION INPUT ;
    USE SIGNAL ;
    PORT
      LAYER M3 ;
        RECT  88.452 0 88.47 0.037 ;
    END
  END x[245]
  PIN x[246]
    DIRECTION INPUT ;
    USE SIGNAL ;
    PORT
      LAYER M3 ;
        RECT  88.524 0 88.542 0.037 ;
    END
  END x[246]
  PIN x[247]
    DIRECTION INPUT ;
    USE SIGNAL ;
    PORT
      LAYER M3 ;
        RECT  88.596 0 88.614 0.037 ;
    END
  END x[247]
  PIN x[248]
    DIRECTION INPUT ;
    USE SIGNAL ;
    PORT
      LAYER M3 ;
        RECT  88.668 0 88.686 0.037 ;
    END
  END x[248]
  PIN x[249]
    DIRECTION INPUT ;
    USE SIGNAL ;
    PORT
      LAYER M3 ;
        RECT  88.74 0 88.758 0.037 ;
    END
  END x[249]
  PIN x[24]
    DIRECTION INPUT ;
    USE SIGNAL ;
    PORT
      LAYER M5 ;
        RECT  82.896 0 82.92 0.084 ;
    END
  END x[24]
  PIN x[250]
    DIRECTION INPUT ;
    USE SIGNAL ;
    PORT
      LAYER M3 ;
        RECT  88.812 0 88.83 0.037 ;
    END
  END x[250]
  PIN x[251]
    DIRECTION INPUT ;
    USE SIGNAL ;
    PORT
      LAYER M3 ;
        RECT  88.884 0 88.902 0.037 ;
    END
  END x[251]
  PIN x[252]
    DIRECTION INPUT ;
    USE SIGNAL ;
    PORT
      LAYER M3 ;
        RECT  88.956 0 88.974 0.037 ;
    END
  END x[252]
  PIN x[253]
    DIRECTION INPUT ;
    USE SIGNAL ;
    PORT
      LAYER M3 ;
        RECT  89.028 0 89.046 0.037 ;
    END
  END x[253]
  PIN x[254]
    DIRECTION INPUT ;
    USE SIGNAL ;
    PORT
      LAYER M3 ;
        RECT  89.1 0 89.118 0.037 ;
    END
  END x[254]
  PIN x[255]
    DIRECTION INPUT ;
    USE SIGNAL ;
    PORT
      LAYER M3 ;
        RECT  89.172 0 89.19 0.037 ;
    END
  END x[255]
  PIN x[256]
    DIRECTION INPUT ;
    USE SIGNAL ;
    PORT
      LAYER M5 ;
        RECT  102.864 0 102.888 0.084 ;
    END
  END x[256]
  PIN x[257]
    DIRECTION INPUT ;
    USE SIGNAL ;
    PORT
      LAYER M5 ;
        RECT  102.96 0 102.984 0.084 ;
    END
  END x[257]
  PIN x[258]
    DIRECTION INPUT ;
    USE SIGNAL ;
    PORT
      LAYER M5 ;
        RECT  103.056 0 103.08 0.084 ;
    END
  END x[258]
  PIN x[259]
    DIRECTION INPUT ;
    USE SIGNAL ;
    PORT
      LAYER M5 ;
        RECT  103.152 0 103.176 0.084 ;
    END
  END x[259]
  PIN x[25]
    DIRECTION INPUT ;
    USE SIGNAL ;
    PORT
      LAYER M5 ;
        RECT  82.992 0 83.016 0.084 ;
    END
  END x[25]
  PIN x[260]
    DIRECTION INPUT ;
    USE SIGNAL ;
    PORT
      LAYER M5 ;
        RECT  103.248 0 103.272 0.084 ;
    END
  END x[260]
  PIN x[261]
    DIRECTION INPUT ;
    USE SIGNAL ;
    PORT
      LAYER M5 ;
        RECT  103.344 0 103.368 0.084 ;
    END
  END x[261]
  PIN x[262]
    DIRECTION INPUT ;
    USE SIGNAL ;
    PORT
      LAYER M5 ;
        RECT  103.44 0 103.464 0.084 ;
    END
  END x[262]
  PIN x[263]
    DIRECTION INPUT ;
    USE SIGNAL ;
    PORT
      LAYER M5 ;
        RECT  103.536 0 103.56 0.084 ;
    END
  END x[263]
  PIN x[264]
    DIRECTION INPUT ;
    USE SIGNAL ;
    PORT
      LAYER M5 ;
        RECT  103.632 0 103.656 0.084 ;
    END
  END x[264]
  PIN x[265]
    DIRECTION INPUT ;
    USE SIGNAL ;
    PORT
      LAYER M5 ;
        RECT  103.728 0 103.752 0.084 ;
    END
  END x[265]
  PIN x[266]
    DIRECTION INPUT ;
    USE SIGNAL ;
    PORT
      LAYER M5 ;
        RECT  103.824 0 103.848 0.084 ;
    END
  END x[266]
  PIN x[267]
    DIRECTION INPUT ;
    USE SIGNAL ;
    PORT
      LAYER M5 ;
        RECT  103.92 0 103.944 0.084 ;
    END
  END x[267]
  PIN x[268]
    DIRECTION INPUT ;
    USE SIGNAL ;
    PORT
      LAYER M5 ;
        RECT  104.016 0 104.04 0.084 ;
    END
  END x[268]
  PIN x[269]
    DIRECTION INPUT ;
    USE SIGNAL ;
    PORT
      LAYER M5 ;
        RECT  104.112 0 104.136 0.084 ;
    END
  END x[269]
  PIN x[26]
    DIRECTION INPUT ;
    USE SIGNAL ;
    PORT
      LAYER M5 ;
        RECT  83.088 0 83.112 0.084 ;
    END
  END x[26]
  PIN x[270]
    DIRECTION INPUT ;
    USE SIGNAL ;
    PORT
      LAYER M5 ;
        RECT  104.208 0 104.232 0.084 ;
    END
  END x[270]
  PIN x[271]
    DIRECTION INPUT ;
    USE SIGNAL ;
    PORT
      LAYER M5 ;
        RECT  104.304 0 104.328 0.084 ;
    END
  END x[271]
  PIN x[272]
    DIRECTION INPUT ;
    USE SIGNAL ;
    PORT
      LAYER M5 ;
        RECT  104.4 0 104.424 0.084 ;
    END
  END x[272]
  PIN x[273]
    DIRECTION INPUT ;
    USE SIGNAL ;
    PORT
      LAYER M5 ;
        RECT  104.496 0 104.52 0.084 ;
    END
  END x[273]
  PIN x[274]
    DIRECTION INPUT ;
    USE SIGNAL ;
    PORT
      LAYER M5 ;
        RECT  104.592 0 104.616 0.084 ;
    END
  END x[274]
  PIN x[275]
    DIRECTION INPUT ;
    USE SIGNAL ;
    PORT
      LAYER M5 ;
        RECT  104.688 0 104.712 0.084 ;
    END
  END x[275]
  PIN x[276]
    DIRECTION INPUT ;
    USE SIGNAL ;
    PORT
      LAYER M5 ;
        RECT  104.784 0 104.808 0.084 ;
    END
  END x[276]
  PIN x[277]
    DIRECTION INPUT ;
    USE SIGNAL ;
    PORT
      LAYER M5 ;
        RECT  104.88 0 104.904 0.084 ;
    END
  END x[277]
  PIN x[278]
    DIRECTION INPUT ;
    USE SIGNAL ;
    PORT
      LAYER M5 ;
        RECT  104.976 0 105 0.084 ;
    END
  END x[278]
  PIN x[279]
    DIRECTION INPUT ;
    USE SIGNAL ;
    PORT
      LAYER M5 ;
        RECT  105.072 0 105.096 0.084 ;
    END
  END x[279]
  PIN x[27]
    DIRECTION INPUT ;
    USE SIGNAL ;
    PORT
      LAYER M5 ;
        RECT  83.184 0 83.208 0.084 ;
    END
  END x[27]
  PIN x[280]
    DIRECTION INPUT ;
    USE SIGNAL ;
    PORT
      LAYER M5 ;
        RECT  105.168 0 105.192 0.084 ;
    END
  END x[280]
  PIN x[281]
    DIRECTION INPUT ;
    USE SIGNAL ;
    PORT
      LAYER M5 ;
        RECT  105.264 0 105.288 0.084 ;
    END
  END x[281]
  PIN x[282]
    DIRECTION INPUT ;
    USE SIGNAL ;
    PORT
      LAYER M5 ;
        RECT  105.36 0 105.384 0.084 ;
    END
  END x[282]
  PIN x[283]
    DIRECTION INPUT ;
    USE SIGNAL ;
    PORT
      LAYER M5 ;
        RECT  105.456 0 105.48 0.084 ;
    END
  END x[283]
  PIN x[284]
    DIRECTION INPUT ;
    USE SIGNAL ;
    PORT
      LAYER M5 ;
        RECT  105.552 0 105.576 0.084 ;
    END
  END x[284]
  PIN x[285]
    DIRECTION INPUT ;
    USE SIGNAL ;
    PORT
      LAYER M5 ;
        RECT  105.648 0 105.672 0.084 ;
    END
  END x[285]
  PIN x[286]
    DIRECTION INPUT ;
    USE SIGNAL ;
    PORT
      LAYER M5 ;
        RECT  105.744 0 105.768 0.084 ;
    END
  END x[286]
  PIN x[287]
    DIRECTION INPUT ;
    USE SIGNAL ;
    PORT
      LAYER M5 ;
        RECT  105.84 0 105.864 0.084 ;
    END
  END x[287]
  PIN x[288]
    DIRECTION INPUT ;
    USE SIGNAL ;
    PORT
      LAYER M3 ;
        RECT  0.54 0 0.558 0.037 ;
    END
  END x[288]
  PIN x[289]
    DIRECTION INPUT ;
    USE SIGNAL ;
    PORT
      LAYER M3 ;
        RECT  0.612 0 0.63 0.037 ;
    END
  END x[289]
  PIN x[28]
    DIRECTION INPUT ;
    USE SIGNAL ;
    PORT
      LAYER M5 ;
        RECT  83.28 0 83.304 0.084 ;
    END
  END x[28]
  PIN x[290]
    DIRECTION INPUT ;
    USE SIGNAL ;
    PORT
      LAYER M3 ;
        RECT  0.684 0 0.702 0.037 ;
    END
  END x[290]
  PIN x[291]
    DIRECTION INPUT ;
    USE SIGNAL ;
    PORT
      LAYER M3 ;
        RECT  0.756 0 0.774 0.037 ;
    END
  END x[291]
  PIN x[292]
    DIRECTION INPUT ;
    USE SIGNAL ;
    PORT
      LAYER M3 ;
        RECT  0.828 0 0.846 0.037 ;
    END
  END x[292]
  PIN x[293]
    DIRECTION INPUT ;
    USE SIGNAL ;
    PORT
      LAYER M3 ;
        RECT  0.9 0 0.918 0.037 ;
    END
  END x[293]
  PIN x[294]
    DIRECTION INPUT ;
    USE SIGNAL ;
    PORT
      LAYER M3 ;
        RECT  0.972 0 0.99 0.037 ;
    END
  END x[294]
  PIN x[295]
    DIRECTION INPUT ;
    USE SIGNAL ;
    PORT
      LAYER M3 ;
        RECT  1.044 0 1.062 0.037 ;
    END
  END x[295]
  PIN x[296]
    DIRECTION INPUT ;
    USE SIGNAL ;
    PORT
      LAYER M3 ;
        RECT  1.116 0 1.134 0.037 ;
    END
  END x[296]
  PIN x[297]
    DIRECTION INPUT ;
    USE SIGNAL ;
    PORT
      LAYER M3 ;
        RECT  1.188 0 1.206 0.037 ;
    END
  END x[297]
  PIN x[298]
    DIRECTION INPUT ;
    USE SIGNAL ;
    PORT
      LAYER M3 ;
        RECT  1.26 0 1.278 0.037 ;
    END
  END x[298]
  PIN x[299]
    DIRECTION INPUT ;
    USE SIGNAL ;
    PORT
      LAYER M3 ;
        RECT  1.332 0 1.35 0.037 ;
    END
  END x[299]
  PIN x[29]
    DIRECTION INPUT ;
    USE SIGNAL ;
    PORT
      LAYER M5 ;
        RECT  83.376 0 83.4 0.084 ;
    END
  END x[29]
  PIN x[2]
    DIRECTION INPUT ;
    USE SIGNAL ;
    PORT
      LAYER M5 ;
        RECT  80.784 0 80.808 0.084 ;
    END
  END x[2]
  PIN x[300]
    DIRECTION INPUT ;
    USE SIGNAL ;
    PORT
      LAYER M3 ;
        RECT  1.404 0 1.422 0.037 ;
    END
  END x[300]
  PIN x[301]
    DIRECTION INPUT ;
    USE SIGNAL ;
    PORT
      LAYER M3 ;
        RECT  1.476 0 1.494 0.037 ;
    END
  END x[301]
  PIN x[302]
    DIRECTION INPUT ;
    USE SIGNAL ;
    PORT
      LAYER M3 ;
        RECT  1.548 0 1.566 0.037 ;
    END
  END x[302]
  PIN x[303]
    DIRECTION INPUT ;
    USE SIGNAL ;
    PORT
      LAYER M3 ;
        RECT  1.62 0 1.638 0.037 ;
    END
  END x[303]
  PIN x[304]
    DIRECTION INPUT ;
    USE SIGNAL ;
    PORT
      LAYER M3 ;
        RECT  1.692 0 1.71 0.037 ;
    END
  END x[304]
  PIN x[305]
    DIRECTION INPUT ;
    USE SIGNAL ;
    PORT
      LAYER M3 ;
        RECT  1.764 0 1.782 0.037 ;
    END
  END x[305]
  PIN x[306]
    DIRECTION INPUT ;
    USE SIGNAL ;
    PORT
      LAYER M3 ;
        RECT  1.836 0 1.854 0.037 ;
    END
  END x[306]
  PIN x[307]
    DIRECTION INPUT ;
    USE SIGNAL ;
    PORT
      LAYER M3 ;
        RECT  1.908 0 1.926 0.037 ;
    END
  END x[307]
  PIN x[308]
    DIRECTION INPUT ;
    USE SIGNAL ;
    PORT
      LAYER M3 ;
        RECT  1.98 0 1.998 0.037 ;
    END
  END x[308]
  PIN x[309]
    DIRECTION INPUT ;
    USE SIGNAL ;
    PORT
      LAYER M3 ;
        RECT  2.052 0 2.07 0.037 ;
    END
  END x[309]
  PIN x[30]
    DIRECTION INPUT ;
    USE SIGNAL ;
    PORT
      LAYER M5 ;
        RECT  83.472 0 83.496 0.084 ;
    END
  END x[30]
  PIN x[310]
    DIRECTION INPUT ;
    USE SIGNAL ;
    PORT
      LAYER M3 ;
        RECT  2.124 0 2.142 0.037 ;
    END
  END x[310]
  PIN x[311]
    DIRECTION INPUT ;
    USE SIGNAL ;
    PORT
      LAYER M3 ;
        RECT  2.196 0 2.214 0.037 ;
    END
  END x[311]
  PIN x[312]
    DIRECTION INPUT ;
    USE SIGNAL ;
    PORT
      LAYER M3 ;
        RECT  2.268 0 2.286 0.037 ;
    END
  END x[312]
  PIN x[313]
    DIRECTION INPUT ;
    USE SIGNAL ;
    PORT
      LAYER M3 ;
        RECT  2.34 0 2.358 0.037 ;
    END
  END x[313]
  PIN x[314]
    DIRECTION INPUT ;
    USE SIGNAL ;
    PORT
      LAYER M3 ;
        RECT  2.412 0 2.43 0.037 ;
    END
  END x[314]
  PIN x[315]
    DIRECTION INPUT ;
    USE SIGNAL ;
    PORT
      LAYER M3 ;
        RECT  2.484 0 2.502 0.037 ;
    END
  END x[315]
  PIN x[316]
    DIRECTION INPUT ;
    USE SIGNAL ;
    PORT
      LAYER M3 ;
        RECT  2.556 0 2.574 0.037 ;
    END
  END x[316]
  PIN x[317]
    DIRECTION INPUT ;
    USE SIGNAL ;
    PORT
      LAYER M3 ;
        RECT  2.628 0 2.646 0.037 ;
    END
  END x[317]
  PIN x[318]
    DIRECTION INPUT ;
    USE SIGNAL ;
    PORT
      LAYER M3 ;
        RECT  2.7 0 2.718 0.037 ;
    END
  END x[318]
  PIN x[319]
    DIRECTION INPUT ;
    USE SIGNAL ;
    PORT
      LAYER M3 ;
        RECT  2.772 0 2.79 0.037 ;
    END
  END x[319]
  PIN x[31]
    DIRECTION INPUT ;
    USE SIGNAL ;
    PORT
      LAYER M5 ;
        RECT  83.568 0 83.592 0.084 ;
    END
  END x[31]
  PIN x[320]
    DIRECTION INPUT ;
    USE SIGNAL ;
    PORT
      LAYER M3 ;
        RECT  14.94 0 14.958 0.037 ;
    END
  END x[320]
  PIN x[321]
    DIRECTION INPUT ;
    USE SIGNAL ;
    PORT
      LAYER M3 ;
        RECT  15.012 0 15.03 0.037 ;
    END
  END x[321]
  PIN x[322]
    DIRECTION INPUT ;
    USE SIGNAL ;
    PORT
      LAYER M3 ;
        RECT  15.084 0 15.102 0.037 ;
    END
  END x[322]
  PIN x[323]
    DIRECTION INPUT ;
    USE SIGNAL ;
    PORT
      LAYER M3 ;
        RECT  15.156 0 15.174 0.037 ;
    END
  END x[323]
  PIN x[324]
    DIRECTION INPUT ;
    USE SIGNAL ;
    PORT
      LAYER M3 ;
        RECT  15.228 0 15.246 0.037 ;
    END
  END x[324]
  PIN x[325]
    DIRECTION INPUT ;
    USE SIGNAL ;
    PORT
      LAYER M3 ;
        RECT  15.3 0 15.318 0.037 ;
    END
  END x[325]
  PIN x[326]
    DIRECTION INPUT ;
    USE SIGNAL ;
    PORT
      LAYER M3 ;
        RECT  15.372 0 15.39 0.037 ;
    END
  END x[326]
  PIN x[327]
    DIRECTION INPUT ;
    USE SIGNAL ;
    PORT
      LAYER M3 ;
        RECT  15.444 0 15.462 0.037 ;
    END
  END x[327]
  PIN x[328]
    DIRECTION INPUT ;
    USE SIGNAL ;
    PORT
      LAYER M3 ;
        RECT  15.516 0 15.534 0.037 ;
    END
  END x[328]
  PIN x[329]
    DIRECTION INPUT ;
    USE SIGNAL ;
    PORT
      LAYER M3 ;
        RECT  15.588 0 15.606 0.037 ;
    END
  END x[329]
  PIN x[32]
    DIRECTION INPUT ;
    USE SIGNAL ;
    PORT
      LAYER M5 ;
        RECT  89.808 0 89.832 0.084 ;
    END
  END x[32]
  PIN x[330]
    DIRECTION INPUT ;
    USE SIGNAL ;
    PORT
      LAYER M3 ;
        RECT  15.66 0 15.678 0.037 ;
    END
  END x[330]
  PIN x[331]
    DIRECTION INPUT ;
    USE SIGNAL ;
    PORT
      LAYER M3 ;
        RECT  15.732 0 15.75 0.037 ;
    END
  END x[331]
  PIN x[332]
    DIRECTION INPUT ;
    USE SIGNAL ;
    PORT
      LAYER M3 ;
        RECT  15.804 0 15.822 0.037 ;
    END
  END x[332]
  PIN x[333]
    DIRECTION INPUT ;
    USE SIGNAL ;
    PORT
      LAYER M3 ;
        RECT  15.876 0 15.894 0.037 ;
    END
  END x[333]
  PIN x[334]
    DIRECTION INPUT ;
    USE SIGNAL ;
    PORT
      LAYER M3 ;
        RECT  15.948 0 15.966 0.037 ;
    END
  END x[334]
  PIN x[335]
    DIRECTION INPUT ;
    USE SIGNAL ;
    PORT
      LAYER M3 ;
        RECT  16.02 0 16.038 0.037 ;
    END
  END x[335]
  PIN x[336]
    DIRECTION INPUT ;
    USE SIGNAL ;
    PORT
      LAYER M3 ;
        RECT  16.092 0 16.11 0.037 ;
    END
  END x[336]
  PIN x[337]
    DIRECTION INPUT ;
    USE SIGNAL ;
    PORT
      LAYER M3 ;
        RECT  16.164 0 16.182 0.037 ;
    END
  END x[337]
  PIN x[338]
    DIRECTION INPUT ;
    USE SIGNAL ;
    PORT
      LAYER M3 ;
        RECT  16.236 0 16.254 0.037 ;
    END
  END x[338]
  PIN x[339]
    DIRECTION INPUT ;
    USE SIGNAL ;
    PORT
      LAYER M3 ;
        RECT  16.308 0 16.326 0.037 ;
    END
  END x[339]
  PIN x[33]
    DIRECTION INPUT ;
    USE SIGNAL ;
    PORT
      LAYER M5 ;
        RECT  89.904 0 89.928 0.084 ;
    END
  END x[33]
  PIN x[340]
    DIRECTION INPUT ;
    USE SIGNAL ;
    PORT
      LAYER M3 ;
        RECT  16.38 0 16.398 0.037 ;
    END
  END x[340]
  PIN x[341]
    DIRECTION INPUT ;
    USE SIGNAL ;
    PORT
      LAYER M3 ;
        RECT  16.452 0 16.47 0.037 ;
    END
  END x[341]
  PIN x[342]
    DIRECTION INPUT ;
    USE SIGNAL ;
    PORT
      LAYER M3 ;
        RECT  16.524 0 16.542 0.037 ;
    END
  END x[342]
  PIN x[343]
    DIRECTION INPUT ;
    USE SIGNAL ;
    PORT
      LAYER M3 ;
        RECT  16.596 0 16.614 0.037 ;
    END
  END x[343]
  PIN x[344]
    DIRECTION INPUT ;
    USE SIGNAL ;
    PORT
      LAYER M3 ;
        RECT  16.668 0 16.686 0.037 ;
    END
  END x[344]
  PIN x[345]
    DIRECTION INPUT ;
    USE SIGNAL ;
    PORT
      LAYER M3 ;
        RECT  16.74 0 16.758 0.037 ;
    END
  END x[345]
  PIN x[346]
    DIRECTION INPUT ;
    USE SIGNAL ;
    PORT
      LAYER M3 ;
        RECT  16.812 0 16.83 0.037 ;
    END
  END x[346]
  PIN x[347]
    DIRECTION INPUT ;
    USE SIGNAL ;
    PORT
      LAYER M3 ;
        RECT  16.884 0 16.902 0.037 ;
    END
  END x[347]
  PIN x[348]
    DIRECTION INPUT ;
    USE SIGNAL ;
    PORT
      LAYER M3 ;
        RECT  16.956 0 16.974 0.037 ;
    END
  END x[348]
  PIN x[349]
    DIRECTION INPUT ;
    USE SIGNAL ;
    PORT
      LAYER M3 ;
        RECT  17.028 0 17.046 0.037 ;
    END
  END x[349]
  PIN x[34]
    DIRECTION INPUT ;
    USE SIGNAL ;
    PORT
      LAYER M5 ;
        RECT  90 0 90.024 0.084 ;
    END
  END x[34]
  PIN x[350]
    DIRECTION INPUT ;
    USE SIGNAL ;
    PORT
      LAYER M3 ;
        RECT  17.1 0 17.118 0.037 ;
    END
  END x[350]
  PIN x[351]
    DIRECTION INPUT ;
    USE SIGNAL ;
    PORT
      LAYER M3 ;
        RECT  17.172 0 17.19 0.037 ;
    END
  END x[351]
  PIN x[352]
    DIRECTION INPUT ;
    USE SIGNAL ;
    PORT
      LAYER M3 ;
        RECT  29.34 0 29.358 0.037 ;
    END
  END x[352]
  PIN x[353]
    DIRECTION INPUT ;
    USE SIGNAL ;
    PORT
      LAYER M3 ;
        RECT  29.412 0 29.43 0.037 ;
    END
  END x[353]
  PIN x[354]
    DIRECTION INPUT ;
    USE SIGNAL ;
    PORT
      LAYER M3 ;
        RECT  29.484 0 29.502 0.037 ;
    END
  END x[354]
  PIN x[355]
    DIRECTION INPUT ;
    USE SIGNAL ;
    PORT
      LAYER M3 ;
        RECT  29.556 0 29.574 0.037 ;
    END
  END x[355]
  PIN x[356]
    DIRECTION INPUT ;
    USE SIGNAL ;
    PORT
      LAYER M3 ;
        RECT  29.628 0 29.646 0.037 ;
    END
  END x[356]
  PIN x[357]
    DIRECTION INPUT ;
    USE SIGNAL ;
    PORT
      LAYER M3 ;
        RECT  29.7 0 29.718 0.037 ;
    END
  END x[357]
  PIN x[358]
    DIRECTION INPUT ;
    USE SIGNAL ;
    PORT
      LAYER M3 ;
        RECT  29.772 0 29.79 0.037 ;
    END
  END x[358]
  PIN x[359]
    DIRECTION INPUT ;
    USE SIGNAL ;
    PORT
      LAYER M3 ;
        RECT  29.844 0 29.862 0.037 ;
    END
  END x[359]
  PIN x[35]
    DIRECTION INPUT ;
    USE SIGNAL ;
    PORT
      LAYER M5 ;
        RECT  90.096 0 90.12 0.084 ;
    END
  END x[35]
  PIN x[360]
    DIRECTION INPUT ;
    USE SIGNAL ;
    PORT
      LAYER M3 ;
        RECT  29.916 0 29.934 0.037 ;
    END
  END x[360]
  PIN x[361]
    DIRECTION INPUT ;
    USE SIGNAL ;
    PORT
      LAYER M3 ;
        RECT  29.988 0 30.006 0.037 ;
    END
  END x[361]
  PIN x[362]
    DIRECTION INPUT ;
    USE SIGNAL ;
    PORT
      LAYER M3 ;
        RECT  30.06 0 30.078 0.037 ;
    END
  END x[362]
  PIN x[363]
    DIRECTION INPUT ;
    USE SIGNAL ;
    PORT
      LAYER M3 ;
        RECT  30.132 0 30.15 0.037 ;
    END
  END x[363]
  PIN x[364]
    DIRECTION INPUT ;
    USE SIGNAL ;
    PORT
      LAYER M3 ;
        RECT  30.204 0 30.222 0.037 ;
    END
  END x[364]
  PIN x[365]
    DIRECTION INPUT ;
    USE SIGNAL ;
    PORT
      LAYER M3 ;
        RECT  30.276 0 30.294 0.037 ;
    END
  END x[365]
  PIN x[366]
    DIRECTION INPUT ;
    USE SIGNAL ;
    PORT
      LAYER M3 ;
        RECT  30.348 0 30.366 0.037 ;
    END
  END x[366]
  PIN x[367]
    DIRECTION INPUT ;
    USE SIGNAL ;
    PORT
      LAYER M3 ;
        RECT  30.42 0 30.438 0.037 ;
    END
  END x[367]
  PIN x[368]
    DIRECTION INPUT ;
    USE SIGNAL ;
    PORT
      LAYER M3 ;
        RECT  30.492 0 30.51 0.037 ;
    END
  END x[368]
  PIN x[369]
    DIRECTION INPUT ;
    USE SIGNAL ;
    PORT
      LAYER M3 ;
        RECT  30.564 0 30.582 0.037 ;
    END
  END x[369]
  PIN x[36]
    DIRECTION INPUT ;
    USE SIGNAL ;
    PORT
      LAYER M5 ;
        RECT  90.192 0 90.216 0.084 ;
    END
  END x[36]
  PIN x[370]
    DIRECTION INPUT ;
    USE SIGNAL ;
    PORT
      LAYER M3 ;
        RECT  30.636 0 30.654 0.037 ;
    END
  END x[370]
  PIN x[371]
    DIRECTION INPUT ;
    USE SIGNAL ;
    PORT
      LAYER M3 ;
        RECT  30.708 0 30.726 0.037 ;
    END
  END x[371]
  PIN x[372]
    DIRECTION INPUT ;
    USE SIGNAL ;
    PORT
      LAYER M3 ;
        RECT  30.78 0 30.798 0.037 ;
    END
  END x[372]
  PIN x[373]
    DIRECTION INPUT ;
    USE SIGNAL ;
    PORT
      LAYER M3 ;
        RECT  30.852 0 30.87 0.037 ;
    END
  END x[373]
  PIN x[374]
    DIRECTION INPUT ;
    USE SIGNAL ;
    PORT
      LAYER M3 ;
        RECT  30.924 0 30.942 0.037 ;
    END
  END x[374]
  PIN x[375]
    DIRECTION INPUT ;
    USE SIGNAL ;
    PORT
      LAYER M3 ;
        RECT  30.996 0 31.014 0.037 ;
    END
  END x[375]
  PIN x[376]
    DIRECTION INPUT ;
    USE SIGNAL ;
    PORT
      LAYER M3 ;
        RECT  31.068 0 31.086 0.037 ;
    END
  END x[376]
  PIN x[377]
    DIRECTION INPUT ;
    USE SIGNAL ;
    PORT
      LAYER M3 ;
        RECT  31.14 0 31.158 0.037 ;
    END
  END x[377]
  PIN x[378]
    DIRECTION INPUT ;
    USE SIGNAL ;
    PORT
      LAYER M3 ;
        RECT  31.212 0 31.23 0.037 ;
    END
  END x[378]
  PIN x[379]
    DIRECTION INPUT ;
    USE SIGNAL ;
    PORT
      LAYER M3 ;
        RECT  31.284 0 31.302 0.037 ;
    END
  END x[379]
  PIN x[37]
    DIRECTION INPUT ;
    USE SIGNAL ;
    PORT
      LAYER M5 ;
        RECT  90.288 0 90.312 0.084 ;
    END
  END x[37]
  PIN x[380]
    DIRECTION INPUT ;
    USE SIGNAL ;
    PORT
      LAYER M3 ;
        RECT  31.356 0 31.374 0.037 ;
    END
  END x[380]
  PIN x[381]
    DIRECTION INPUT ;
    USE SIGNAL ;
    PORT
      LAYER M3 ;
        RECT  31.428 0 31.446 0.037 ;
    END
  END x[381]
  PIN x[382]
    DIRECTION INPUT ;
    USE SIGNAL ;
    PORT
      LAYER M3 ;
        RECT  31.5 0 31.518 0.037 ;
    END
  END x[382]
  PIN x[383]
    DIRECTION INPUT ;
    USE SIGNAL ;
    PORT
      LAYER M3 ;
        RECT  31.572 0 31.59 0.037 ;
    END
  END x[383]
  PIN x[384]
    DIRECTION INPUT ;
    USE SIGNAL ;
    PORT
      LAYER M3 ;
        RECT  43.74 0 43.758 0.037 ;
    END
  END x[384]
  PIN x[385]
    DIRECTION INPUT ;
    USE SIGNAL ;
    PORT
      LAYER M3 ;
        RECT  43.812 0 43.83 0.037 ;
    END
  END x[385]
  PIN x[386]
    DIRECTION INPUT ;
    USE SIGNAL ;
    PORT
      LAYER M3 ;
        RECT  43.884 0 43.902 0.037 ;
    END
  END x[386]
  PIN x[387]
    DIRECTION INPUT ;
    USE SIGNAL ;
    PORT
      LAYER M3 ;
        RECT  43.956 0 43.974 0.037 ;
    END
  END x[387]
  PIN x[388]
    DIRECTION INPUT ;
    USE SIGNAL ;
    PORT
      LAYER M3 ;
        RECT  44.028 0 44.046 0.037 ;
    END
  END x[388]
  PIN x[389]
    DIRECTION INPUT ;
    USE SIGNAL ;
    PORT
      LAYER M3 ;
        RECT  44.1 0 44.118 0.037 ;
    END
  END x[389]
  PIN x[38]
    DIRECTION INPUT ;
    USE SIGNAL ;
    PORT
      LAYER M5 ;
        RECT  90.384 0 90.408 0.084 ;
    END
  END x[38]
  PIN x[390]
    DIRECTION INPUT ;
    USE SIGNAL ;
    PORT
      LAYER M3 ;
        RECT  44.172 0 44.19 0.037 ;
    END
  END x[390]
  PIN x[391]
    DIRECTION INPUT ;
    USE SIGNAL ;
    PORT
      LAYER M3 ;
        RECT  44.244 0 44.262 0.037 ;
    END
  END x[391]
  PIN x[392]
    DIRECTION INPUT ;
    USE SIGNAL ;
    PORT
      LAYER M3 ;
        RECT  44.316 0 44.334 0.037 ;
    END
  END x[392]
  PIN x[393]
    DIRECTION INPUT ;
    USE SIGNAL ;
    PORT
      LAYER M3 ;
        RECT  44.388 0 44.406 0.037 ;
    END
  END x[393]
  PIN x[394]
    DIRECTION INPUT ;
    USE SIGNAL ;
    PORT
      LAYER M3 ;
        RECT  44.46 0 44.478 0.037 ;
    END
  END x[394]
  PIN x[395]
    DIRECTION INPUT ;
    USE SIGNAL ;
    PORT
      LAYER M3 ;
        RECT  44.532 0 44.55 0.037 ;
    END
  END x[395]
  PIN x[396]
    DIRECTION INPUT ;
    USE SIGNAL ;
    PORT
      LAYER M3 ;
        RECT  44.604 0 44.622 0.037 ;
    END
  END x[396]
  PIN x[397]
    DIRECTION INPUT ;
    USE SIGNAL ;
    PORT
      LAYER M3 ;
        RECT  44.676 0 44.694 0.037 ;
    END
  END x[397]
  PIN x[398]
    DIRECTION INPUT ;
    USE SIGNAL ;
    PORT
      LAYER M3 ;
        RECT  44.748 0 44.766 0.037 ;
    END
  END x[398]
  PIN x[399]
    DIRECTION INPUT ;
    USE SIGNAL ;
    PORT
      LAYER M3 ;
        RECT  44.82 0 44.838 0.037 ;
    END
  END x[399]
  PIN x[39]
    DIRECTION INPUT ;
    USE SIGNAL ;
    PORT
      LAYER M5 ;
        RECT  90.48 0 90.504 0.084 ;
    END
  END x[39]
  PIN x[3]
    DIRECTION INPUT ;
    USE SIGNAL ;
    PORT
      LAYER M5 ;
        RECT  80.88 0 80.904 0.084 ;
    END
  END x[3]
  PIN x[400]
    DIRECTION INPUT ;
    USE SIGNAL ;
    PORT
      LAYER M3 ;
        RECT  44.892 0 44.91 0.037 ;
    END
  END x[400]
  PIN x[401]
    DIRECTION INPUT ;
    USE SIGNAL ;
    PORT
      LAYER M3 ;
        RECT  44.964 0 44.982 0.037 ;
    END
  END x[401]
  PIN x[402]
    DIRECTION INPUT ;
    USE SIGNAL ;
    PORT
      LAYER M3 ;
        RECT  45.036 0 45.054 0.037 ;
    END
  END x[402]
  PIN x[403]
    DIRECTION INPUT ;
    USE SIGNAL ;
    PORT
      LAYER M3 ;
        RECT  45.108 0 45.126 0.037 ;
    END
  END x[403]
  PIN x[404]
    DIRECTION INPUT ;
    USE SIGNAL ;
    PORT
      LAYER M3 ;
        RECT  45.18 0 45.198 0.037 ;
    END
  END x[404]
  PIN x[405]
    DIRECTION INPUT ;
    USE SIGNAL ;
    PORT
      LAYER M3 ;
        RECT  45.252 0 45.27 0.037 ;
    END
  END x[405]
  PIN x[406]
    DIRECTION INPUT ;
    USE SIGNAL ;
    PORT
      LAYER M3 ;
        RECT  45.324 0 45.342 0.037 ;
    END
  END x[406]
  PIN x[407]
    DIRECTION INPUT ;
    USE SIGNAL ;
    PORT
      LAYER M3 ;
        RECT  45.396 0 45.414 0.037 ;
    END
  END x[407]
  PIN x[408]
    DIRECTION INPUT ;
    USE SIGNAL ;
    PORT
      LAYER M3 ;
        RECT  45.468 0 45.486 0.037 ;
    END
  END x[408]
  PIN x[409]
    DIRECTION INPUT ;
    USE SIGNAL ;
    PORT
      LAYER M3 ;
        RECT  45.54 0 45.558 0.037 ;
    END
  END x[409]
  PIN x[40]
    DIRECTION INPUT ;
    USE SIGNAL ;
    PORT
      LAYER M5 ;
        RECT  90.576 0 90.6 0.084 ;
    END
  END x[40]
  PIN x[410]
    DIRECTION INPUT ;
    USE SIGNAL ;
    PORT
      LAYER M3 ;
        RECT  45.612 0 45.63 0.037 ;
    END
  END x[410]
  PIN x[411]
    DIRECTION INPUT ;
    USE SIGNAL ;
    PORT
      LAYER M3 ;
        RECT  45.684 0 45.702 0.037 ;
    END
  END x[411]
  PIN x[412]
    DIRECTION INPUT ;
    USE SIGNAL ;
    PORT
      LAYER M3 ;
        RECT  45.756 0 45.774 0.037 ;
    END
  END x[412]
  PIN x[413]
    DIRECTION INPUT ;
    USE SIGNAL ;
    PORT
      LAYER M3 ;
        RECT  45.828 0 45.846 0.037 ;
    END
  END x[413]
  PIN x[414]
    DIRECTION INPUT ;
    USE SIGNAL ;
    PORT
      LAYER M3 ;
        RECT  45.9 0 45.918 0.037 ;
    END
  END x[414]
  PIN x[415]
    DIRECTION INPUT ;
    USE SIGNAL ;
    PORT
      LAYER M3 ;
        RECT  45.972 0 45.99 0.037 ;
    END
  END x[415]
  PIN x[416]
    DIRECTION INPUT ;
    USE SIGNAL ;
    PORT
      LAYER M3 ;
        RECT  58.14 0 58.158 0.037 ;
    END
  END x[416]
  PIN x[417]
    DIRECTION INPUT ;
    USE SIGNAL ;
    PORT
      LAYER M3 ;
        RECT  58.212 0 58.23 0.037 ;
    END
  END x[417]
  PIN x[418]
    DIRECTION INPUT ;
    USE SIGNAL ;
    PORT
      LAYER M3 ;
        RECT  58.284 0 58.302 0.037 ;
    END
  END x[418]
  PIN x[419]
    DIRECTION INPUT ;
    USE SIGNAL ;
    PORT
      LAYER M3 ;
        RECT  58.356 0 58.374 0.037 ;
    END
  END x[419]
  PIN x[41]
    DIRECTION INPUT ;
    USE SIGNAL ;
    PORT
      LAYER M5 ;
        RECT  90.672 0 90.696 0.084 ;
    END
  END x[41]
  PIN x[420]
    DIRECTION INPUT ;
    USE SIGNAL ;
    PORT
      LAYER M3 ;
        RECT  58.428 0 58.446 0.037 ;
    END
  END x[420]
  PIN x[421]
    DIRECTION INPUT ;
    USE SIGNAL ;
    PORT
      LAYER M3 ;
        RECT  58.5 0 58.518 0.037 ;
    END
  END x[421]
  PIN x[422]
    DIRECTION INPUT ;
    USE SIGNAL ;
    PORT
      LAYER M3 ;
        RECT  58.572 0 58.59 0.037 ;
    END
  END x[422]
  PIN x[423]
    DIRECTION INPUT ;
    USE SIGNAL ;
    PORT
      LAYER M3 ;
        RECT  58.644 0 58.662 0.037 ;
    END
  END x[423]
  PIN x[424]
    DIRECTION INPUT ;
    USE SIGNAL ;
    PORT
      LAYER M3 ;
        RECT  58.716 0 58.734 0.037 ;
    END
  END x[424]
  PIN x[425]
    DIRECTION INPUT ;
    USE SIGNAL ;
    PORT
      LAYER M3 ;
        RECT  58.788 0 58.806 0.037 ;
    END
  END x[425]
  PIN x[426]
    DIRECTION INPUT ;
    USE SIGNAL ;
    PORT
      LAYER M3 ;
        RECT  58.86 0 58.878 0.037 ;
    END
  END x[426]
  PIN x[427]
    DIRECTION INPUT ;
    USE SIGNAL ;
    PORT
      LAYER M3 ;
        RECT  58.932 0 58.95 0.037 ;
    END
  END x[427]
  PIN x[428]
    DIRECTION INPUT ;
    USE SIGNAL ;
    PORT
      LAYER M3 ;
        RECT  59.004 0 59.022 0.037 ;
    END
  END x[428]
  PIN x[429]
    DIRECTION INPUT ;
    USE SIGNAL ;
    PORT
      LAYER M3 ;
        RECT  59.076 0 59.094 0.037 ;
    END
  END x[429]
  PIN x[42]
    DIRECTION INPUT ;
    USE SIGNAL ;
    PORT
      LAYER M5 ;
        RECT  90.768 0 90.792 0.084 ;
    END
  END x[42]
  PIN x[430]
    DIRECTION INPUT ;
    USE SIGNAL ;
    PORT
      LAYER M3 ;
        RECT  59.148 0 59.166 0.037 ;
    END
  END x[430]
  PIN x[431]
    DIRECTION INPUT ;
    USE SIGNAL ;
    PORT
      LAYER M3 ;
        RECT  59.22 0 59.238 0.037 ;
    END
  END x[431]
  PIN x[432]
    DIRECTION INPUT ;
    USE SIGNAL ;
    PORT
      LAYER M3 ;
        RECT  59.292 0 59.31 0.037 ;
    END
  END x[432]
  PIN x[433]
    DIRECTION INPUT ;
    USE SIGNAL ;
    PORT
      LAYER M3 ;
        RECT  59.364 0 59.382 0.037 ;
    END
  END x[433]
  PIN x[434]
    DIRECTION INPUT ;
    USE SIGNAL ;
    PORT
      LAYER M3 ;
        RECT  59.436 0 59.454 0.037 ;
    END
  END x[434]
  PIN x[435]
    DIRECTION INPUT ;
    USE SIGNAL ;
    PORT
      LAYER M3 ;
        RECT  59.508 0 59.526 0.037 ;
    END
  END x[435]
  PIN x[436]
    DIRECTION INPUT ;
    USE SIGNAL ;
    PORT
      LAYER M3 ;
        RECT  59.58 0 59.598 0.037 ;
    END
  END x[436]
  PIN x[437]
    DIRECTION INPUT ;
    USE SIGNAL ;
    PORT
      LAYER M3 ;
        RECT  59.652 0 59.67 0.037 ;
    END
  END x[437]
  PIN x[438]
    DIRECTION INPUT ;
    USE SIGNAL ;
    PORT
      LAYER M3 ;
        RECT  59.724 0 59.742 0.037 ;
    END
  END x[438]
  PIN x[439]
    DIRECTION INPUT ;
    USE SIGNAL ;
    PORT
      LAYER M3 ;
        RECT  59.796 0 59.814 0.037 ;
    END
  END x[439]
  PIN x[43]
    DIRECTION INPUT ;
    USE SIGNAL ;
    PORT
      LAYER M5 ;
        RECT  90.864 0 90.888 0.084 ;
    END
  END x[43]
  PIN x[440]
    DIRECTION INPUT ;
    USE SIGNAL ;
    PORT
      LAYER M3 ;
        RECT  59.868 0 59.886 0.037 ;
    END
  END x[440]
  PIN x[441]
    DIRECTION INPUT ;
    USE SIGNAL ;
    PORT
      LAYER M3 ;
        RECT  59.94 0 59.958 0.037 ;
    END
  END x[441]
  PIN x[442]
    DIRECTION INPUT ;
    USE SIGNAL ;
    PORT
      LAYER M3 ;
        RECT  60.012 0 60.03 0.037 ;
    END
  END x[442]
  PIN x[443]
    DIRECTION INPUT ;
    USE SIGNAL ;
    PORT
      LAYER M3 ;
        RECT  60.084 0 60.102 0.037 ;
    END
  END x[443]
  PIN x[444]
    DIRECTION INPUT ;
    USE SIGNAL ;
    PORT
      LAYER M3 ;
        RECT  60.156 0 60.174 0.037 ;
    END
  END x[444]
  PIN x[445]
    DIRECTION INPUT ;
    USE SIGNAL ;
    PORT
      LAYER M3 ;
        RECT  60.228 0 60.246 0.037 ;
    END
  END x[445]
  PIN x[446]
    DIRECTION INPUT ;
    USE SIGNAL ;
    PORT
      LAYER M3 ;
        RECT  60.3 0 60.318 0.037 ;
    END
  END x[446]
  PIN x[447]
    DIRECTION INPUT ;
    USE SIGNAL ;
    PORT
      LAYER M3 ;
        RECT  60.372 0 60.39 0.037 ;
    END
  END x[447]
  PIN x[448]
    DIRECTION INPUT ;
    USE SIGNAL ;
    PORT
      LAYER M3 ;
        RECT  101.34 0 101.358 0.037 ;
    END
  END x[448]
  PIN x[449]
    DIRECTION INPUT ;
    USE SIGNAL ;
    PORT
      LAYER M3 ;
        RECT  101.412 0 101.43 0.037 ;
    END
  END x[449]
  PIN x[44]
    DIRECTION INPUT ;
    USE SIGNAL ;
    PORT
      LAYER M5 ;
        RECT  90.96 0 90.984 0.084 ;
    END
  END x[44]
  PIN x[450]
    DIRECTION INPUT ;
    USE SIGNAL ;
    PORT
      LAYER M3 ;
        RECT  101.484 0 101.502 0.037 ;
    END
  END x[450]
  PIN x[451]
    DIRECTION INPUT ;
    USE SIGNAL ;
    PORT
      LAYER M3 ;
        RECT  101.556 0 101.574 0.037 ;
    END
  END x[451]
  PIN x[452]
    DIRECTION INPUT ;
    USE SIGNAL ;
    PORT
      LAYER M3 ;
        RECT  101.628 0 101.646 0.037 ;
    END
  END x[452]
  PIN x[453]
    DIRECTION INPUT ;
    USE SIGNAL ;
    PORT
      LAYER M3 ;
        RECT  101.7 0 101.718 0.037 ;
    END
  END x[453]
  PIN x[454]
    DIRECTION INPUT ;
    USE SIGNAL ;
    PORT
      LAYER M3 ;
        RECT  101.772 0 101.79 0.037 ;
    END
  END x[454]
  PIN x[455]
    DIRECTION INPUT ;
    USE SIGNAL ;
    PORT
      LAYER M3 ;
        RECT  101.844 0 101.862 0.037 ;
    END
  END x[455]
  PIN x[456]
    DIRECTION INPUT ;
    USE SIGNAL ;
    PORT
      LAYER M3 ;
        RECT  101.916 0 101.934 0.037 ;
    END
  END x[456]
  PIN x[457]
    DIRECTION INPUT ;
    USE SIGNAL ;
    PORT
      LAYER M3 ;
        RECT  101.988 0 102.006 0.037 ;
    END
  END x[457]
  PIN x[458]
    DIRECTION INPUT ;
    USE SIGNAL ;
    PORT
      LAYER M3 ;
        RECT  102.06 0 102.078 0.037 ;
    END
  END x[458]
  PIN x[459]
    DIRECTION INPUT ;
    USE SIGNAL ;
    PORT
      LAYER M3 ;
        RECT  102.132 0 102.15 0.037 ;
    END
  END x[459]
  PIN x[45]
    DIRECTION INPUT ;
    USE SIGNAL ;
    PORT
      LAYER M5 ;
        RECT  91.056 0 91.08 0.084 ;
    END
  END x[45]
  PIN x[460]
    DIRECTION INPUT ;
    USE SIGNAL ;
    PORT
      LAYER M3 ;
        RECT  102.204 0 102.222 0.037 ;
    END
  END x[460]
  PIN x[461]
    DIRECTION INPUT ;
    USE SIGNAL ;
    PORT
      LAYER M3 ;
        RECT  102.276 0 102.294 0.037 ;
    END
  END x[461]
  PIN x[462]
    DIRECTION INPUT ;
    USE SIGNAL ;
    PORT
      LAYER M3 ;
        RECT  102.348 0 102.366 0.037 ;
    END
  END x[462]
  PIN x[463]
    DIRECTION INPUT ;
    USE SIGNAL ;
    PORT
      LAYER M3 ;
        RECT  102.42 0 102.438 0.037 ;
    END
  END x[463]
  PIN x[464]
    DIRECTION INPUT ;
    USE SIGNAL ;
    PORT
      LAYER M3 ;
        RECT  102.492 0 102.51 0.037 ;
    END
  END x[464]
  PIN x[465]
    DIRECTION INPUT ;
    USE SIGNAL ;
    PORT
      LAYER M3 ;
        RECT  102.564 0 102.582 0.037 ;
    END
  END x[465]
  PIN x[466]
    DIRECTION INPUT ;
    USE SIGNAL ;
    PORT
      LAYER M3 ;
        RECT  102.636 0 102.654 0.037 ;
    END
  END x[466]
  PIN x[467]
    DIRECTION INPUT ;
    USE SIGNAL ;
    PORT
      LAYER M3 ;
        RECT  102.708 0 102.726 0.037 ;
    END
  END x[467]
  PIN x[468]
    DIRECTION INPUT ;
    USE SIGNAL ;
    PORT
      LAYER M3 ;
        RECT  102.78 0 102.798 0.037 ;
    END
  END x[468]
  PIN x[469]
    DIRECTION INPUT ;
    USE SIGNAL ;
    PORT
      LAYER M3 ;
        RECT  102.852 0 102.87 0.037 ;
    END
  END x[469]
  PIN x[46]
    DIRECTION INPUT ;
    USE SIGNAL ;
    PORT
      LAYER M5 ;
        RECT  91.152 0 91.176 0.084 ;
    END
  END x[46]
  PIN x[470]
    DIRECTION INPUT ;
    USE SIGNAL ;
    PORT
      LAYER M3 ;
        RECT  102.924 0 102.942 0.037 ;
    END
  END x[470]
  PIN x[471]
    DIRECTION INPUT ;
    USE SIGNAL ;
    PORT
      LAYER M3 ;
        RECT  102.996 0 103.014 0.037 ;
    END
  END x[471]
  PIN x[472]
    DIRECTION INPUT ;
    USE SIGNAL ;
    PORT
      LAYER M3 ;
        RECT  103.068 0 103.086 0.037 ;
    END
  END x[472]
  PIN x[473]
    DIRECTION INPUT ;
    USE SIGNAL ;
    PORT
      LAYER M3 ;
        RECT  103.14 0 103.158 0.037 ;
    END
  END x[473]
  PIN x[474]
    DIRECTION INPUT ;
    USE SIGNAL ;
    PORT
      LAYER M3 ;
        RECT  103.212 0 103.23 0.037 ;
    END
  END x[474]
  PIN x[475]
    DIRECTION INPUT ;
    USE SIGNAL ;
    PORT
      LAYER M3 ;
        RECT  103.284 0 103.302 0.037 ;
    END
  END x[475]
  PIN x[476]
    DIRECTION INPUT ;
    USE SIGNAL ;
    PORT
      LAYER M3 ;
        RECT  103.356 0 103.374 0.037 ;
    END
  END x[476]
  PIN x[477]
    DIRECTION INPUT ;
    USE SIGNAL ;
    PORT
      LAYER M3 ;
        RECT  103.428 0 103.446 0.037 ;
    END
  END x[477]
  PIN x[478]
    DIRECTION INPUT ;
    USE SIGNAL ;
    PORT
      LAYER M3 ;
        RECT  103.5 0 103.518 0.037 ;
    END
  END x[478]
  PIN x[479]
    DIRECTION INPUT ;
    USE SIGNAL ;
    PORT
      LAYER M3 ;
        RECT  103.572 0 103.59 0.037 ;
    END
  END x[479]
  PIN x[47]
    DIRECTION INPUT ;
    USE SIGNAL ;
    PORT
      LAYER M5 ;
        RECT  91.248 0 91.272 0.084 ;
    END
  END x[47]
  PIN x[480]
    DIRECTION INPUT ;
    USE SIGNAL ;
    PORT
      LAYER M3 ;
        RECT  115.74 0 115.758 0.037 ;
    END
  END x[480]
  PIN x[481]
    DIRECTION INPUT ;
    USE SIGNAL ;
    PORT
      LAYER M3 ;
        RECT  115.812 0 115.83 0.037 ;
    END
  END x[481]
  PIN x[482]
    DIRECTION INPUT ;
    USE SIGNAL ;
    PORT
      LAYER M3 ;
        RECT  115.884 0 115.902 0.037 ;
    END
  END x[482]
  PIN x[483]
    DIRECTION INPUT ;
    USE SIGNAL ;
    PORT
      LAYER M3 ;
        RECT  115.956 0 115.974 0.037 ;
    END
  END x[483]
  PIN x[484]
    DIRECTION INPUT ;
    USE SIGNAL ;
    PORT
      LAYER M3 ;
        RECT  116.028 0 116.046 0.037 ;
    END
  END x[484]
  PIN x[485]
    DIRECTION INPUT ;
    USE SIGNAL ;
    PORT
      LAYER M3 ;
        RECT  116.1 0 116.118 0.037 ;
    END
  END x[485]
  PIN x[486]
    DIRECTION INPUT ;
    USE SIGNAL ;
    PORT
      LAYER M3 ;
        RECT  116.172 0 116.19 0.037 ;
    END
  END x[486]
  PIN x[487]
    DIRECTION INPUT ;
    USE SIGNAL ;
    PORT
      LAYER M3 ;
        RECT  116.244 0 116.262 0.037 ;
    END
  END x[487]
  PIN x[488]
    DIRECTION INPUT ;
    USE SIGNAL ;
    PORT
      LAYER M3 ;
        RECT  116.316 0 116.334 0.037 ;
    END
  END x[488]
  PIN x[489]
    DIRECTION INPUT ;
    USE SIGNAL ;
    PORT
      LAYER M3 ;
        RECT  116.388 0 116.406 0.037 ;
    END
  END x[489]
  PIN x[48]
    DIRECTION INPUT ;
    USE SIGNAL ;
    PORT
      LAYER M5 ;
        RECT  91.344 0 91.368 0.084 ;
    END
  END x[48]
  PIN x[490]
    DIRECTION INPUT ;
    USE SIGNAL ;
    PORT
      LAYER M3 ;
        RECT  116.46 0 116.478 0.037 ;
    END
  END x[490]
  PIN x[491]
    DIRECTION INPUT ;
    USE SIGNAL ;
    PORT
      LAYER M3 ;
        RECT  116.532 0 116.55 0.037 ;
    END
  END x[491]
  PIN x[492]
    DIRECTION INPUT ;
    USE SIGNAL ;
    PORT
      LAYER M3 ;
        RECT  116.604 0 116.622 0.037 ;
    END
  END x[492]
  PIN x[493]
    DIRECTION INPUT ;
    USE SIGNAL ;
    PORT
      LAYER M3 ;
        RECT  116.676 0 116.694 0.037 ;
    END
  END x[493]
  PIN x[494]
    DIRECTION INPUT ;
    USE SIGNAL ;
    PORT
      LAYER M3 ;
        RECT  116.748 0 116.766 0.037 ;
    END
  END x[494]
  PIN x[495]
    DIRECTION INPUT ;
    USE SIGNAL ;
    PORT
      LAYER M3 ;
        RECT  116.82 0 116.838 0.037 ;
    END
  END x[495]
  PIN x[496]
    DIRECTION INPUT ;
    USE SIGNAL ;
    PORT
      LAYER M3 ;
        RECT  116.892 0 116.91 0.037 ;
    END
  END x[496]
  PIN x[497]
    DIRECTION INPUT ;
    USE SIGNAL ;
    PORT
      LAYER M3 ;
        RECT  116.964 0 116.982 0.037 ;
    END
  END x[497]
  PIN x[498]
    DIRECTION INPUT ;
    USE SIGNAL ;
    PORT
      LAYER M3 ;
        RECT  117.036 0 117.054 0.037 ;
    END
  END x[498]
  PIN x[499]
    DIRECTION INPUT ;
    USE SIGNAL ;
    PORT
      LAYER M3 ;
        RECT  117.108 0 117.126 0.037 ;
    END
  END x[499]
  PIN x[49]
    DIRECTION INPUT ;
    USE SIGNAL ;
    PORT
      LAYER M5 ;
        RECT  91.44 0 91.464 0.084 ;
    END
  END x[49]
  PIN x[4]
    DIRECTION INPUT ;
    USE SIGNAL ;
    PORT
      LAYER M5 ;
        RECT  80.976 0 81 0.084 ;
    END
  END x[4]
  PIN x[500]
    DIRECTION INPUT ;
    USE SIGNAL ;
    PORT
      LAYER M3 ;
        RECT  117.18 0 117.198 0.037 ;
    END
  END x[500]
  PIN x[501]
    DIRECTION INPUT ;
    USE SIGNAL ;
    PORT
      LAYER M3 ;
        RECT  117.252 0 117.27 0.037 ;
    END
  END x[501]
  PIN x[502]
    DIRECTION INPUT ;
    USE SIGNAL ;
    PORT
      LAYER M3 ;
        RECT  117.324 0 117.342 0.037 ;
    END
  END x[502]
  PIN x[503]
    DIRECTION INPUT ;
    USE SIGNAL ;
    PORT
      LAYER M3 ;
        RECT  117.396 0 117.414 0.037 ;
    END
  END x[503]
  PIN x[504]
    DIRECTION INPUT ;
    USE SIGNAL ;
    PORT
      LAYER M3 ;
        RECT  117.468 0 117.486 0.037 ;
    END
  END x[504]
  PIN x[505]
    DIRECTION INPUT ;
    USE SIGNAL ;
    PORT
      LAYER M3 ;
        RECT  117.54 0 117.558 0.037 ;
    END
  END x[505]
  PIN x[506]
    DIRECTION INPUT ;
    USE SIGNAL ;
    PORT
      LAYER M3 ;
        RECT  117.612 0 117.63 0.037 ;
    END
  END x[506]
  PIN x[507]
    DIRECTION INPUT ;
    USE SIGNAL ;
    PORT
      LAYER M3 ;
        RECT  117.684 0 117.702 0.037 ;
    END
  END x[507]
  PIN x[508]
    DIRECTION INPUT ;
    USE SIGNAL ;
    PORT
      LAYER M3 ;
        RECT  117.756 0 117.774 0.037 ;
    END
  END x[508]
  PIN x[509]
    DIRECTION INPUT ;
    USE SIGNAL ;
    PORT
      LAYER M3 ;
        RECT  117.828 0 117.846 0.037 ;
    END
  END x[509]
  PIN x[50]
    DIRECTION INPUT ;
    USE SIGNAL ;
    PORT
      LAYER M5 ;
        RECT  91.536 0 91.56 0.084 ;
    END
  END x[50]
  PIN x[510]
    DIRECTION INPUT ;
    USE SIGNAL ;
    PORT
      LAYER M3 ;
        RECT  117.9 0 117.918 0.037 ;
    END
  END x[510]
  PIN x[511]
    DIRECTION INPUT ;
    USE SIGNAL ;
    PORT
      LAYER M3 ;
        RECT  117.972 0 117.99 0.037 ;
    END
  END x[511]
  PIN x[512]
    DIRECTION INPUT ;
    USE SIGNAL ;
    PORT
      LAYER M3 ;
        RECT  130.14 0 130.158 0.037 ;
    END
  END x[512]
  PIN x[513]
    DIRECTION INPUT ;
    USE SIGNAL ;
    PORT
      LAYER M3 ;
        RECT  130.212 0 130.23 0.037 ;
    END
  END x[513]
  PIN x[514]
    DIRECTION INPUT ;
    USE SIGNAL ;
    PORT
      LAYER M3 ;
        RECT  130.284 0 130.302 0.037 ;
    END
  END x[514]
  PIN x[515]
    DIRECTION INPUT ;
    USE SIGNAL ;
    PORT
      LAYER M3 ;
        RECT  130.356 0 130.374 0.037 ;
    END
  END x[515]
  PIN x[516]
    DIRECTION INPUT ;
    USE SIGNAL ;
    PORT
      LAYER M3 ;
        RECT  130.428 0 130.446 0.037 ;
    END
  END x[516]
  PIN x[517]
    DIRECTION INPUT ;
    USE SIGNAL ;
    PORT
      LAYER M3 ;
        RECT  130.5 0 130.518 0.037 ;
    END
  END x[517]
  PIN x[518]
    DIRECTION INPUT ;
    USE SIGNAL ;
    PORT
      LAYER M3 ;
        RECT  130.572 0 130.59 0.037 ;
    END
  END x[518]
  PIN x[519]
    DIRECTION INPUT ;
    USE SIGNAL ;
    PORT
      LAYER M3 ;
        RECT  130.644 0 130.662 0.037 ;
    END
  END x[519]
  PIN x[51]
    DIRECTION INPUT ;
    USE SIGNAL ;
    PORT
      LAYER M5 ;
        RECT  91.632 0 91.656 0.084 ;
    END
  END x[51]
  PIN x[520]
    DIRECTION INPUT ;
    USE SIGNAL ;
    PORT
      LAYER M3 ;
        RECT  130.716 0 130.734 0.037 ;
    END
  END x[520]
  PIN x[521]
    DIRECTION INPUT ;
    USE SIGNAL ;
    PORT
      LAYER M3 ;
        RECT  130.788 0 130.806 0.037 ;
    END
  END x[521]
  PIN x[522]
    DIRECTION INPUT ;
    USE SIGNAL ;
    PORT
      LAYER M3 ;
        RECT  130.86 0 130.878 0.037 ;
    END
  END x[522]
  PIN x[523]
    DIRECTION INPUT ;
    USE SIGNAL ;
    PORT
      LAYER M3 ;
        RECT  130.932 0 130.95 0.037 ;
    END
  END x[523]
  PIN x[524]
    DIRECTION INPUT ;
    USE SIGNAL ;
    PORT
      LAYER M3 ;
        RECT  131.004 0 131.022 0.037 ;
    END
  END x[524]
  PIN x[525]
    DIRECTION INPUT ;
    USE SIGNAL ;
    PORT
      LAYER M3 ;
        RECT  131.076 0 131.094 0.037 ;
    END
  END x[525]
  PIN x[526]
    DIRECTION INPUT ;
    USE SIGNAL ;
    PORT
      LAYER M3 ;
        RECT  131.148 0 131.166 0.037 ;
    END
  END x[526]
  PIN x[527]
    DIRECTION INPUT ;
    USE SIGNAL ;
    PORT
      LAYER M3 ;
        RECT  131.22 0 131.238 0.037 ;
    END
  END x[527]
  PIN x[528]
    DIRECTION INPUT ;
    USE SIGNAL ;
    PORT
      LAYER M3 ;
        RECT  131.292 0 131.31 0.037 ;
    END
  END x[528]
  PIN x[529]
    DIRECTION INPUT ;
    USE SIGNAL ;
    PORT
      LAYER M3 ;
        RECT  131.364 0 131.382 0.037 ;
    END
  END x[529]
  PIN x[52]
    DIRECTION INPUT ;
    USE SIGNAL ;
    PORT
      LAYER M5 ;
        RECT  91.728 0 91.752 0.084 ;
    END
  END x[52]
  PIN x[530]
    DIRECTION INPUT ;
    USE SIGNAL ;
    PORT
      LAYER M3 ;
        RECT  131.436 0 131.454 0.037 ;
    END
  END x[530]
  PIN x[531]
    DIRECTION INPUT ;
    USE SIGNAL ;
    PORT
      LAYER M3 ;
        RECT  131.508 0 131.526 0.037 ;
    END
  END x[531]
  PIN x[532]
    DIRECTION INPUT ;
    USE SIGNAL ;
    PORT
      LAYER M3 ;
        RECT  131.58 0 131.598 0.037 ;
    END
  END x[532]
  PIN x[533]
    DIRECTION INPUT ;
    USE SIGNAL ;
    PORT
      LAYER M3 ;
        RECT  131.652 0 131.67 0.037 ;
    END
  END x[533]
  PIN x[534]
    DIRECTION INPUT ;
    USE SIGNAL ;
    PORT
      LAYER M3 ;
        RECT  131.724 0 131.742 0.037 ;
    END
  END x[534]
  PIN x[535]
    DIRECTION INPUT ;
    USE SIGNAL ;
    PORT
      LAYER M3 ;
        RECT  131.796 0 131.814 0.037 ;
    END
  END x[535]
  PIN x[536]
    DIRECTION INPUT ;
    USE SIGNAL ;
    PORT
      LAYER M3 ;
        RECT  131.868 0 131.886 0.037 ;
    END
  END x[536]
  PIN x[537]
    DIRECTION INPUT ;
    USE SIGNAL ;
    PORT
      LAYER M3 ;
        RECT  131.94 0 131.958 0.037 ;
    END
  END x[537]
  PIN x[538]
    DIRECTION INPUT ;
    USE SIGNAL ;
    PORT
      LAYER M3 ;
        RECT  132.012 0 132.03 0.037 ;
    END
  END x[538]
  PIN x[539]
    DIRECTION INPUT ;
    USE SIGNAL ;
    PORT
      LAYER M3 ;
        RECT  132.084 0 132.102 0.037 ;
    END
  END x[539]
  PIN x[53]
    DIRECTION INPUT ;
    USE SIGNAL ;
    PORT
      LAYER M5 ;
        RECT  91.824 0 91.848 0.084 ;
    END
  END x[53]
  PIN x[540]
    DIRECTION INPUT ;
    USE SIGNAL ;
    PORT
      LAYER M3 ;
        RECT  132.156 0 132.174 0.037 ;
    END
  END x[540]
  PIN x[541]
    DIRECTION INPUT ;
    USE SIGNAL ;
    PORT
      LAYER M3 ;
        RECT  132.228 0 132.246 0.037 ;
    END
  END x[541]
  PIN x[542]
    DIRECTION INPUT ;
    USE SIGNAL ;
    PORT
      LAYER M3 ;
        RECT  132.3 0 132.318 0.037 ;
    END
  END x[542]
  PIN x[543]
    DIRECTION INPUT ;
    USE SIGNAL ;
    PORT
      LAYER M3 ;
        RECT  132.372 0 132.39 0.037 ;
    END
  END x[543]
  PIN x[544]
    DIRECTION INPUT ;
    USE SIGNAL ;
    PORT
      LAYER M3 ;
        RECT  144.54 0 144.558 0.037 ;
    END
  END x[544]
  PIN x[545]
    DIRECTION INPUT ;
    USE SIGNAL ;
    PORT
      LAYER M3 ;
        RECT  144.612 0 144.63 0.037 ;
    END
  END x[545]
  PIN x[546]
    DIRECTION INPUT ;
    USE SIGNAL ;
    PORT
      LAYER M3 ;
        RECT  144.684 0 144.702 0.037 ;
    END
  END x[546]
  PIN x[547]
    DIRECTION INPUT ;
    USE SIGNAL ;
    PORT
      LAYER M3 ;
        RECT  144.756 0 144.774 0.037 ;
    END
  END x[547]
  PIN x[548]
    DIRECTION INPUT ;
    USE SIGNAL ;
    PORT
      LAYER M3 ;
        RECT  144.828 0 144.846 0.037 ;
    END
  END x[548]
  PIN x[549]
    DIRECTION INPUT ;
    USE SIGNAL ;
    PORT
      LAYER M3 ;
        RECT  144.9 0 144.918 0.037 ;
    END
  END x[549]
  PIN x[54]
    DIRECTION INPUT ;
    USE SIGNAL ;
    PORT
      LAYER M5 ;
        RECT  91.92 0 91.944 0.084 ;
    END
  END x[54]
  PIN x[550]
    DIRECTION INPUT ;
    USE SIGNAL ;
    PORT
      LAYER M3 ;
        RECT  144.972 0 144.99 0.037 ;
    END
  END x[550]
  PIN x[551]
    DIRECTION INPUT ;
    USE SIGNAL ;
    PORT
      LAYER M3 ;
        RECT  145.044 0 145.062 0.037 ;
    END
  END x[551]
  PIN x[552]
    DIRECTION INPUT ;
    USE SIGNAL ;
    PORT
      LAYER M3 ;
        RECT  145.116 0 145.134 0.037 ;
    END
  END x[552]
  PIN x[553]
    DIRECTION INPUT ;
    USE SIGNAL ;
    PORT
      LAYER M3 ;
        RECT  145.188 0 145.206 0.037 ;
    END
  END x[553]
  PIN x[554]
    DIRECTION INPUT ;
    USE SIGNAL ;
    PORT
      LAYER M3 ;
        RECT  145.26 0 145.278 0.037 ;
    END
  END x[554]
  PIN x[555]
    DIRECTION INPUT ;
    USE SIGNAL ;
    PORT
      LAYER M3 ;
        RECT  145.332 0 145.35 0.037 ;
    END
  END x[555]
  PIN x[556]
    DIRECTION INPUT ;
    USE SIGNAL ;
    PORT
      LAYER M3 ;
        RECT  145.404 0 145.422 0.037 ;
    END
  END x[556]
  PIN x[557]
    DIRECTION INPUT ;
    USE SIGNAL ;
    PORT
      LAYER M3 ;
        RECT  145.476 0 145.494 0.037 ;
    END
  END x[557]
  PIN x[558]
    DIRECTION INPUT ;
    USE SIGNAL ;
    PORT
      LAYER M3 ;
        RECT  145.548 0 145.566 0.037 ;
    END
  END x[558]
  PIN x[559]
    DIRECTION INPUT ;
    USE SIGNAL ;
    PORT
      LAYER M3 ;
        RECT  145.62 0 145.638 0.037 ;
    END
  END x[559]
  PIN x[55]
    DIRECTION INPUT ;
    USE SIGNAL ;
    PORT
      LAYER M5 ;
        RECT  92.016 0 92.04 0.084 ;
    END
  END x[55]
  PIN x[560]
    DIRECTION INPUT ;
    USE SIGNAL ;
    PORT
      LAYER M3 ;
        RECT  145.692 0 145.71 0.037 ;
    END
  END x[560]
  PIN x[561]
    DIRECTION INPUT ;
    USE SIGNAL ;
    PORT
      LAYER M3 ;
        RECT  145.764 0 145.782 0.037 ;
    END
  END x[561]
  PIN x[562]
    DIRECTION INPUT ;
    USE SIGNAL ;
    PORT
      LAYER M3 ;
        RECT  145.836 0 145.854 0.037 ;
    END
  END x[562]
  PIN x[563]
    DIRECTION INPUT ;
    USE SIGNAL ;
    PORT
      LAYER M3 ;
        RECT  145.908 0 145.926 0.037 ;
    END
  END x[563]
  PIN x[564]
    DIRECTION INPUT ;
    USE SIGNAL ;
    PORT
      LAYER M3 ;
        RECT  145.98 0 145.998 0.037 ;
    END
  END x[564]
  PIN x[565]
    DIRECTION INPUT ;
    USE SIGNAL ;
    PORT
      LAYER M3 ;
        RECT  146.052 0 146.07 0.037 ;
    END
  END x[565]
  PIN x[566]
    DIRECTION INPUT ;
    USE SIGNAL ;
    PORT
      LAYER M3 ;
        RECT  146.124 0 146.142 0.037 ;
    END
  END x[566]
  PIN x[567]
    DIRECTION INPUT ;
    USE SIGNAL ;
    PORT
      LAYER M3 ;
        RECT  146.196 0 146.214 0.037 ;
    END
  END x[567]
  PIN x[568]
    DIRECTION INPUT ;
    USE SIGNAL ;
    PORT
      LAYER M3 ;
        RECT  146.268 0 146.286 0.037 ;
    END
  END x[568]
  PIN x[569]
    DIRECTION INPUT ;
    USE SIGNAL ;
    PORT
      LAYER M3 ;
        RECT  146.34 0 146.358 0.037 ;
    END
  END x[569]
  PIN x[56]
    DIRECTION INPUT ;
    USE SIGNAL ;
    PORT
      LAYER M5 ;
        RECT  92.112 0 92.136 0.084 ;
    END
  END x[56]
  PIN x[570]
    DIRECTION INPUT ;
    USE SIGNAL ;
    PORT
      LAYER M3 ;
        RECT  146.412 0 146.43 0.037 ;
    END
  END x[570]
  PIN x[571]
    DIRECTION INPUT ;
    USE SIGNAL ;
    PORT
      LAYER M3 ;
        RECT  146.484 0 146.502 0.037 ;
    END
  END x[571]
  PIN x[572]
    DIRECTION INPUT ;
    USE SIGNAL ;
    PORT
      LAYER M3 ;
        RECT  146.556 0 146.574 0.037 ;
    END
  END x[572]
  PIN x[573]
    DIRECTION INPUT ;
    USE SIGNAL ;
    PORT
      LAYER M3 ;
        RECT  146.628 0 146.646 0.037 ;
    END
  END x[573]
  PIN x[574]
    DIRECTION INPUT ;
    USE SIGNAL ;
    PORT
      LAYER M3 ;
        RECT  146.7 0 146.718 0.037 ;
    END
  END x[574]
  PIN x[575]
    DIRECTION INPUT ;
    USE SIGNAL ;
    PORT
      LAYER M3 ;
        RECT  146.772 0 146.79 0.037 ;
    END
  END x[575]
  PIN x[576]
    DIRECTION INPUT ;
    USE SIGNAL ;
    PORT
      LAYER M3 ;
        RECT  158.94 0 158.958 0.037 ;
    END
  END x[576]
  PIN x[577]
    DIRECTION INPUT ;
    USE SIGNAL ;
    PORT
      LAYER M3 ;
        RECT  159.012 0 159.03 0.037 ;
    END
  END x[577]
  PIN x[578]
    DIRECTION INPUT ;
    USE SIGNAL ;
    PORT
      LAYER M3 ;
        RECT  159.084 0 159.102 0.037 ;
    END
  END x[578]
  PIN x[579]
    DIRECTION INPUT ;
    USE SIGNAL ;
    PORT
      LAYER M3 ;
        RECT  159.156 0 159.174 0.037 ;
    END
  END x[579]
  PIN x[57]
    DIRECTION INPUT ;
    USE SIGNAL ;
    PORT
      LAYER M5 ;
        RECT  92.208 0 92.232 0.084 ;
    END
  END x[57]
  PIN x[580]
    DIRECTION INPUT ;
    USE SIGNAL ;
    PORT
      LAYER M3 ;
        RECT  159.228 0 159.246 0.037 ;
    END
  END x[580]
  PIN x[581]
    DIRECTION INPUT ;
    USE SIGNAL ;
    PORT
      LAYER M3 ;
        RECT  159.3 0 159.318 0.037 ;
    END
  END x[581]
  PIN x[582]
    DIRECTION INPUT ;
    USE SIGNAL ;
    PORT
      LAYER M3 ;
        RECT  159.372 0 159.39 0.037 ;
    END
  END x[582]
  PIN x[583]
    DIRECTION INPUT ;
    USE SIGNAL ;
    PORT
      LAYER M3 ;
        RECT  159.444 0 159.462 0.037 ;
    END
  END x[583]
  PIN x[584]
    DIRECTION INPUT ;
    USE SIGNAL ;
    PORT
      LAYER M3 ;
        RECT  159.516 0 159.534 0.037 ;
    END
  END x[584]
  PIN x[585]
    DIRECTION INPUT ;
    USE SIGNAL ;
    PORT
      LAYER M3 ;
        RECT  159.588 0 159.606 0.037 ;
    END
  END x[585]
  PIN x[586]
    DIRECTION INPUT ;
    USE SIGNAL ;
    PORT
      LAYER M3 ;
        RECT  159.66 0 159.678 0.037 ;
    END
  END x[586]
  PIN x[587]
    DIRECTION INPUT ;
    USE SIGNAL ;
    PORT
      LAYER M3 ;
        RECT  159.732 0 159.75 0.037 ;
    END
  END x[587]
  PIN x[588]
    DIRECTION INPUT ;
    USE SIGNAL ;
    PORT
      LAYER M3 ;
        RECT  159.804 0 159.822 0.037 ;
    END
  END x[588]
  PIN x[589]
    DIRECTION INPUT ;
    USE SIGNAL ;
    PORT
      LAYER M3 ;
        RECT  159.876 0 159.894 0.037 ;
    END
  END x[589]
  PIN x[58]
    DIRECTION INPUT ;
    USE SIGNAL ;
    PORT
      LAYER M5 ;
        RECT  92.304 0 92.328 0.084 ;
    END
  END x[58]
  PIN x[590]
    DIRECTION INPUT ;
    USE SIGNAL ;
    PORT
      LAYER M3 ;
        RECT  159.948 0 159.966 0.037 ;
    END
  END x[590]
  PIN x[591]
    DIRECTION INPUT ;
    USE SIGNAL ;
    PORT
      LAYER M3 ;
        RECT  160.02 0 160.038 0.037 ;
    END
  END x[591]
  PIN x[592]
    DIRECTION INPUT ;
    USE SIGNAL ;
    PORT
      LAYER M3 ;
        RECT  160.092 0 160.11 0.037 ;
    END
  END x[592]
  PIN x[593]
    DIRECTION INPUT ;
    USE SIGNAL ;
    PORT
      LAYER M3 ;
        RECT  160.164 0 160.182 0.037 ;
    END
  END x[593]
  PIN x[594]
    DIRECTION INPUT ;
    USE SIGNAL ;
    PORT
      LAYER M3 ;
        RECT  160.236 0 160.254 0.037 ;
    END
  END x[594]
  PIN x[595]
    DIRECTION INPUT ;
    USE SIGNAL ;
    PORT
      LAYER M3 ;
        RECT  160.308 0 160.326 0.037 ;
    END
  END x[595]
  PIN x[596]
    DIRECTION INPUT ;
    USE SIGNAL ;
    PORT
      LAYER M3 ;
        RECT  160.38 0 160.398 0.037 ;
    END
  END x[596]
  PIN x[597]
    DIRECTION INPUT ;
    USE SIGNAL ;
    PORT
      LAYER M3 ;
        RECT  160.452 0 160.47 0.037 ;
    END
  END x[597]
  PIN x[598]
    DIRECTION INPUT ;
    USE SIGNAL ;
    PORT
      LAYER M3 ;
        RECT  160.524 0 160.542 0.037 ;
    END
  END x[598]
  PIN x[599]
    DIRECTION INPUT ;
    USE SIGNAL ;
    PORT
      LAYER M3 ;
        RECT  160.596 0 160.614 0.037 ;
    END
  END x[599]
  PIN x[59]
    DIRECTION INPUT ;
    USE SIGNAL ;
    PORT
      LAYER M5 ;
        RECT  92.4 0 92.424 0.084 ;
    END
  END x[59]
  PIN x[5]
    DIRECTION INPUT ;
    USE SIGNAL ;
    PORT
      LAYER M5 ;
        RECT  81.072 0 81.096 0.084 ;
    END
  END x[5]
  PIN x[600]
    DIRECTION INPUT ;
    USE SIGNAL ;
    PORT
      LAYER M3 ;
        RECT  160.668 0 160.686 0.037 ;
    END
  END x[600]
  PIN x[601]
    DIRECTION INPUT ;
    USE SIGNAL ;
    PORT
      LAYER M3 ;
        RECT  160.74 0 160.758 0.037 ;
    END
  END x[601]
  PIN x[602]
    DIRECTION INPUT ;
    USE SIGNAL ;
    PORT
      LAYER M3 ;
        RECT  160.812 0 160.83 0.037 ;
    END
  END x[602]
  PIN x[603]
    DIRECTION INPUT ;
    USE SIGNAL ;
    PORT
      LAYER M3 ;
        RECT  160.884 0 160.902 0.037 ;
    END
  END x[603]
  PIN x[604]
    DIRECTION INPUT ;
    USE SIGNAL ;
    PORT
      LAYER M3 ;
        RECT  160.956 0 160.974 0.037 ;
    END
  END x[604]
  PIN x[605]
    DIRECTION INPUT ;
    USE SIGNAL ;
    PORT
      LAYER M3 ;
        RECT  161.028 0 161.046 0.037 ;
    END
  END x[605]
  PIN x[606]
    DIRECTION INPUT ;
    USE SIGNAL ;
    PORT
      LAYER M3 ;
        RECT  161.1 0 161.118 0.037 ;
    END
  END x[606]
  PIN x[607]
    DIRECTION INPUT ;
    USE SIGNAL ;
    PORT
      LAYER M3 ;
        RECT  161.172 0 161.19 0.037 ;
    END
  END x[607]
  PIN x[608]
    DIRECTION INPUT ;
    USE SIGNAL ;
    PORT
      LAYER M3 ;
        RECT  173.34 0 173.358 0.037 ;
    END
  END x[608]
  PIN x[609]
    DIRECTION INPUT ;
    USE SIGNAL ;
    PORT
      LAYER M3 ;
        RECT  173.412 0 173.43 0.037 ;
    END
  END x[609]
  PIN x[60]
    DIRECTION INPUT ;
    USE SIGNAL ;
    PORT
      LAYER M5 ;
        RECT  92.496 0 92.52 0.084 ;
    END
  END x[60]
  PIN x[610]
    DIRECTION INPUT ;
    USE SIGNAL ;
    PORT
      LAYER M3 ;
        RECT  173.484 0 173.502 0.037 ;
    END
  END x[610]
  PIN x[611]
    DIRECTION INPUT ;
    USE SIGNAL ;
    PORT
      LAYER M3 ;
        RECT  173.556 0 173.574 0.037 ;
    END
  END x[611]
  PIN x[612]
    DIRECTION INPUT ;
    USE SIGNAL ;
    PORT
      LAYER M3 ;
        RECT  173.628 0 173.646 0.037 ;
    END
  END x[612]
  PIN x[613]
    DIRECTION INPUT ;
    USE SIGNAL ;
    PORT
      LAYER M3 ;
        RECT  173.7 0 173.718 0.037 ;
    END
  END x[613]
  PIN x[614]
    DIRECTION INPUT ;
    USE SIGNAL ;
    PORT
      LAYER M3 ;
        RECT  173.772 0 173.79 0.037 ;
    END
  END x[614]
  PIN x[615]
    DIRECTION INPUT ;
    USE SIGNAL ;
    PORT
      LAYER M3 ;
        RECT  173.844 0 173.862 0.037 ;
    END
  END x[615]
  PIN x[616]
    DIRECTION INPUT ;
    USE SIGNAL ;
    PORT
      LAYER M3 ;
        RECT  173.916 0 173.934 0.037 ;
    END
  END x[616]
  PIN x[617]
    DIRECTION INPUT ;
    USE SIGNAL ;
    PORT
      LAYER M3 ;
        RECT  173.988 0 174.006 0.037 ;
    END
  END x[617]
  PIN x[618]
    DIRECTION INPUT ;
    USE SIGNAL ;
    PORT
      LAYER M3 ;
        RECT  174.06 0 174.078 0.037 ;
    END
  END x[618]
  PIN x[619]
    DIRECTION INPUT ;
    USE SIGNAL ;
    PORT
      LAYER M3 ;
        RECT  174.132 0 174.15 0.037 ;
    END
  END x[619]
  PIN x[61]
    DIRECTION INPUT ;
    USE SIGNAL ;
    PORT
      LAYER M5 ;
        RECT  92.592 0 92.616 0.084 ;
    END
  END x[61]
  PIN x[620]
    DIRECTION INPUT ;
    USE SIGNAL ;
    PORT
      LAYER M3 ;
        RECT  174.204 0 174.222 0.037 ;
    END
  END x[620]
  PIN x[621]
    DIRECTION INPUT ;
    USE SIGNAL ;
    PORT
      LAYER M3 ;
        RECT  174.276 0 174.294 0.037 ;
    END
  END x[621]
  PIN x[622]
    DIRECTION INPUT ;
    USE SIGNAL ;
    PORT
      LAYER M3 ;
        RECT  174.348 0 174.366 0.037 ;
    END
  END x[622]
  PIN x[623]
    DIRECTION INPUT ;
    USE SIGNAL ;
    PORT
      LAYER M3 ;
        RECT  174.42 0 174.438 0.037 ;
    END
  END x[623]
  PIN x[624]
    DIRECTION INPUT ;
    USE SIGNAL ;
    PORT
      LAYER M3 ;
        RECT  174.492 0 174.51 0.037 ;
    END
  END x[624]
  PIN x[625]
    DIRECTION INPUT ;
    USE SIGNAL ;
    PORT
      LAYER M3 ;
        RECT  174.564 0 174.582 0.037 ;
    END
  END x[625]
  PIN x[626]
    DIRECTION INPUT ;
    USE SIGNAL ;
    PORT
      LAYER M3 ;
        RECT  174.636 0 174.654 0.037 ;
    END
  END x[626]
  PIN x[627]
    DIRECTION INPUT ;
    USE SIGNAL ;
    PORT
      LAYER M3 ;
        RECT  174.708 0 174.726 0.037 ;
    END
  END x[627]
  PIN x[628]
    DIRECTION INPUT ;
    USE SIGNAL ;
    PORT
      LAYER M3 ;
        RECT  174.78 0 174.798 0.037 ;
    END
  END x[628]
  PIN x[629]
    DIRECTION INPUT ;
    USE SIGNAL ;
    PORT
      LAYER M3 ;
        RECT  174.852 0 174.87 0.037 ;
    END
  END x[629]
  PIN x[62]
    DIRECTION INPUT ;
    USE SIGNAL ;
    PORT
      LAYER M5 ;
        RECT  92.688 0 92.712 0.084 ;
    END
  END x[62]
  PIN x[630]
    DIRECTION INPUT ;
    USE SIGNAL ;
    PORT
      LAYER M3 ;
        RECT  174.924 0 174.942 0.037 ;
    END
  END x[630]
  PIN x[631]
    DIRECTION INPUT ;
    USE SIGNAL ;
    PORT
      LAYER M3 ;
        RECT  174.996 0 175.014 0.037 ;
    END
  END x[631]
  PIN x[632]
    DIRECTION INPUT ;
    USE SIGNAL ;
    PORT
      LAYER M3 ;
        RECT  175.068 0 175.086 0.037 ;
    END
  END x[632]
  PIN x[633]
    DIRECTION INPUT ;
    USE SIGNAL ;
    PORT
      LAYER M3 ;
        RECT  175.14 0 175.158 0.037 ;
    END
  END x[633]
  PIN x[634]
    DIRECTION INPUT ;
    USE SIGNAL ;
    PORT
      LAYER M3 ;
        RECT  175.212 0 175.23 0.037 ;
    END
  END x[634]
  PIN x[635]
    DIRECTION INPUT ;
    USE SIGNAL ;
    PORT
      LAYER M3 ;
        RECT  175.284 0 175.302 0.037 ;
    END
  END x[635]
  PIN x[636]
    DIRECTION INPUT ;
    USE SIGNAL ;
    PORT
      LAYER M3 ;
        RECT  175.356 0 175.374 0.037 ;
    END
  END x[636]
  PIN x[637]
    DIRECTION INPUT ;
    USE SIGNAL ;
    PORT
      LAYER M3 ;
        RECT  175.428 0 175.446 0.037 ;
    END
  END x[637]
  PIN x[638]
    DIRECTION INPUT ;
    USE SIGNAL ;
    PORT
      LAYER M3 ;
        RECT  175.5 0 175.518 0.037 ;
    END
  END x[638]
  PIN x[639]
    DIRECTION INPUT ;
    USE SIGNAL ;
    PORT
      LAYER M3 ;
        RECT  175.572 0 175.59 0.037 ;
    END
  END x[639]
  PIN x[63]
    DIRECTION INPUT ;
    USE SIGNAL ;
    PORT
      LAYER M5 ;
        RECT  92.784 0 92.808 0.084 ;
    END
  END x[63]
  PIN x[640]
    DIRECTION INPUT ;
    USE SIGNAL ;
    PORT
      LAYER M5 ;
        RECT  0.72 0 0.744 0.084 ;
    END
  END x[640]
  PIN x[641]
    DIRECTION INPUT ;
    USE SIGNAL ;
    PORT
      LAYER M5 ;
        RECT  0.816 0 0.84 0.084 ;
    END
  END x[641]
  PIN x[642]
    DIRECTION INPUT ;
    USE SIGNAL ;
    PORT
      LAYER M5 ;
        RECT  0.912 0 0.936 0.084 ;
    END
  END x[642]
  PIN x[643]
    DIRECTION INPUT ;
    USE SIGNAL ;
    PORT
      LAYER M5 ;
        RECT  1.008 0 1.032 0.084 ;
    END
  END x[643]
  PIN x[644]
    DIRECTION INPUT ;
    USE SIGNAL ;
    PORT
      LAYER M5 ;
        RECT  1.104 0 1.128 0.084 ;
    END
  END x[644]
  PIN x[645]
    DIRECTION INPUT ;
    USE SIGNAL ;
    PORT
      LAYER M5 ;
        RECT  1.2 0 1.224 0.084 ;
    END
  END x[645]
  PIN x[646]
    DIRECTION INPUT ;
    USE SIGNAL ;
    PORT
      LAYER M5 ;
        RECT  1.296 0 1.32 0.084 ;
    END
  END x[646]
  PIN x[647]
    DIRECTION INPUT ;
    USE SIGNAL ;
    PORT
      LAYER M5 ;
        RECT  1.392 0 1.416 0.084 ;
    END
  END x[647]
  PIN x[648]
    DIRECTION INPUT ;
    USE SIGNAL ;
    PORT
      LAYER M5 ;
        RECT  1.488 0 1.512 0.084 ;
    END
  END x[648]
  PIN x[649]
    DIRECTION INPUT ;
    USE SIGNAL ;
    PORT
      LAYER M5 ;
        RECT  1.584 0 1.608 0.084 ;
    END
  END x[649]
  PIN x[64]
    DIRECTION INPUT ;
    USE SIGNAL ;
    PORT
      LAYER M3 ;
        RECT  79.452 0 79.47 0.037 ;
    END
  END x[64]
  PIN x[650]
    DIRECTION INPUT ;
    USE SIGNAL ;
    PORT
      LAYER M5 ;
        RECT  1.68 0 1.704 0.084 ;
    END
  END x[650]
  PIN x[651]
    DIRECTION INPUT ;
    USE SIGNAL ;
    PORT
      LAYER M5 ;
        RECT  1.776 0 1.8 0.084 ;
    END
  END x[651]
  PIN x[652]
    DIRECTION INPUT ;
    USE SIGNAL ;
    PORT
      LAYER M5 ;
        RECT  1.872 0 1.896 0.084 ;
    END
  END x[652]
  PIN x[653]
    DIRECTION INPUT ;
    USE SIGNAL ;
    PORT
      LAYER M5 ;
        RECT  1.968 0 1.992 0.084 ;
    END
  END x[653]
  PIN x[654]
    DIRECTION INPUT ;
    USE SIGNAL ;
    PORT
      LAYER M5 ;
        RECT  2.064 0 2.088 0.084 ;
    END
  END x[654]
  PIN x[655]
    DIRECTION INPUT ;
    USE SIGNAL ;
    PORT
      LAYER M5 ;
        RECT  2.16 0 2.184 0.084 ;
    END
  END x[655]
  PIN x[656]
    DIRECTION INPUT ;
    USE SIGNAL ;
    PORT
      LAYER M5 ;
        RECT  2.256 0 2.28 0.084 ;
    END
  END x[656]
  PIN x[657]
    DIRECTION INPUT ;
    USE SIGNAL ;
    PORT
      LAYER M5 ;
        RECT  2.352 0 2.376 0.084 ;
    END
  END x[657]
  PIN x[658]
    DIRECTION INPUT ;
    USE SIGNAL ;
    PORT
      LAYER M5 ;
        RECT  2.448 0 2.472 0.084 ;
    END
  END x[658]
  PIN x[659]
    DIRECTION INPUT ;
    USE SIGNAL ;
    PORT
      LAYER M5 ;
        RECT  2.544 0 2.568 0.084 ;
    END
  END x[659]
  PIN x[65]
    DIRECTION INPUT ;
    USE SIGNAL ;
    PORT
      LAYER M3 ;
        RECT  79.524 0 79.542 0.037 ;
    END
  END x[65]
  PIN x[660]
    DIRECTION INPUT ;
    USE SIGNAL ;
    PORT
      LAYER M5 ;
        RECT  2.64 0 2.664 0.084 ;
    END
  END x[660]
  PIN x[661]
    DIRECTION INPUT ;
    USE SIGNAL ;
    PORT
      LAYER M5 ;
        RECT  2.736 0 2.76 0.084 ;
    END
  END x[661]
  PIN x[662]
    DIRECTION INPUT ;
    USE SIGNAL ;
    PORT
      LAYER M5 ;
        RECT  2.832 0 2.856 0.084 ;
    END
  END x[662]
  PIN x[663]
    DIRECTION INPUT ;
    USE SIGNAL ;
    PORT
      LAYER M5 ;
        RECT  2.928 0 2.952 0.084 ;
    END
  END x[663]
  PIN x[664]
    DIRECTION INPUT ;
    USE SIGNAL ;
    PORT
      LAYER M5 ;
        RECT  3.024 0 3.048 0.084 ;
    END
  END x[664]
  PIN x[665]
    DIRECTION INPUT ;
    USE SIGNAL ;
    PORT
      LAYER M5 ;
        RECT  3.12 0 3.144 0.084 ;
    END
  END x[665]
  PIN x[666]
    DIRECTION INPUT ;
    USE SIGNAL ;
    PORT
      LAYER M5 ;
        RECT  3.216 0 3.24 0.084 ;
    END
  END x[666]
  PIN x[667]
    DIRECTION INPUT ;
    USE SIGNAL ;
    PORT
      LAYER M5 ;
        RECT  3.312 0 3.336 0.084 ;
    END
  END x[667]
  PIN x[668]
    DIRECTION INPUT ;
    USE SIGNAL ;
    PORT
      LAYER M5 ;
        RECT  3.408 0 3.432 0.084 ;
    END
  END x[668]
  PIN x[669]
    DIRECTION INPUT ;
    USE SIGNAL ;
    PORT
      LAYER M5 ;
        RECT  3.504 0 3.528 0.084 ;
    END
  END x[669]
  PIN x[66]
    DIRECTION INPUT ;
    USE SIGNAL ;
    PORT
      LAYER M3 ;
        RECT  79.596 0 79.614 0.037 ;
    END
  END x[66]
  PIN x[670]
    DIRECTION INPUT ;
    USE SIGNAL ;
    PORT
      LAYER M5 ;
        RECT  3.6 0 3.624 0.084 ;
    END
  END x[670]
  PIN x[671]
    DIRECTION INPUT ;
    USE SIGNAL ;
    PORT
      LAYER M5 ;
        RECT  3.696 0 3.72 0.084 ;
    END
  END x[671]
  PIN x[672]
    DIRECTION INPUT ;
    USE SIGNAL ;
    PORT
      LAYER M5 ;
        RECT  19.92 0 19.944 0.084 ;
    END
  END x[672]
  PIN x[673]
    DIRECTION INPUT ;
    USE SIGNAL ;
    PORT
      LAYER M5 ;
        RECT  20.016 0 20.04 0.084 ;
    END
  END x[673]
  PIN x[674]
    DIRECTION INPUT ;
    USE SIGNAL ;
    PORT
      LAYER M5 ;
        RECT  20.112 0 20.136 0.084 ;
    END
  END x[674]
  PIN x[675]
    DIRECTION INPUT ;
    USE SIGNAL ;
    PORT
      LAYER M5 ;
        RECT  20.208 0 20.232 0.084 ;
    END
  END x[675]
  PIN x[676]
    DIRECTION INPUT ;
    USE SIGNAL ;
    PORT
      LAYER M5 ;
        RECT  20.304 0 20.328 0.084 ;
    END
  END x[676]
  PIN x[677]
    DIRECTION INPUT ;
    USE SIGNAL ;
    PORT
      LAYER M5 ;
        RECT  20.4 0 20.424 0.084 ;
    END
  END x[677]
  PIN x[678]
    DIRECTION INPUT ;
    USE SIGNAL ;
    PORT
      LAYER M5 ;
        RECT  20.496 0 20.52 0.084 ;
    END
  END x[678]
  PIN x[679]
    DIRECTION INPUT ;
    USE SIGNAL ;
    PORT
      LAYER M5 ;
        RECT  20.592 0 20.616 0.084 ;
    END
  END x[679]
  PIN x[67]
    DIRECTION INPUT ;
    USE SIGNAL ;
    PORT
      LAYER M3 ;
        RECT  79.668 0 79.686 0.037 ;
    END
  END x[67]
  PIN x[680]
    DIRECTION INPUT ;
    USE SIGNAL ;
    PORT
      LAYER M5 ;
        RECT  20.688 0 20.712 0.084 ;
    END
  END x[680]
  PIN x[681]
    DIRECTION INPUT ;
    USE SIGNAL ;
    PORT
      LAYER M5 ;
        RECT  20.784 0 20.808 0.084 ;
    END
  END x[681]
  PIN x[682]
    DIRECTION INPUT ;
    USE SIGNAL ;
    PORT
      LAYER M5 ;
        RECT  20.88 0 20.904 0.084 ;
    END
  END x[682]
  PIN x[683]
    DIRECTION INPUT ;
    USE SIGNAL ;
    PORT
      LAYER M5 ;
        RECT  20.976 0 21 0.084 ;
    END
  END x[683]
  PIN x[684]
    DIRECTION INPUT ;
    USE SIGNAL ;
    PORT
      LAYER M5 ;
        RECT  21.072 0 21.096 0.084 ;
    END
  END x[684]
  PIN x[685]
    DIRECTION INPUT ;
    USE SIGNAL ;
    PORT
      LAYER M5 ;
        RECT  21.168 0 21.192 0.084 ;
    END
  END x[685]
  PIN x[686]
    DIRECTION INPUT ;
    USE SIGNAL ;
    PORT
      LAYER M5 ;
        RECT  21.264 0 21.288 0.084 ;
    END
  END x[686]
  PIN x[687]
    DIRECTION INPUT ;
    USE SIGNAL ;
    PORT
      LAYER M5 ;
        RECT  21.36 0 21.384 0.084 ;
    END
  END x[687]
  PIN x[688]
    DIRECTION INPUT ;
    USE SIGNAL ;
    PORT
      LAYER M5 ;
        RECT  21.456 0 21.48 0.084 ;
    END
  END x[688]
  PIN x[689]
    DIRECTION INPUT ;
    USE SIGNAL ;
    PORT
      LAYER M5 ;
        RECT  21.552 0 21.576 0.084 ;
    END
  END x[689]
  PIN x[68]
    DIRECTION INPUT ;
    USE SIGNAL ;
    PORT
      LAYER M3 ;
        RECT  79.74 0 79.758 0.037 ;
    END
  END x[68]
  PIN x[690]
    DIRECTION INPUT ;
    USE SIGNAL ;
    PORT
      LAYER M5 ;
        RECT  21.648 0 21.672 0.084 ;
    END
  END x[690]
  PIN x[691]
    DIRECTION INPUT ;
    USE SIGNAL ;
    PORT
      LAYER M5 ;
        RECT  21.744 0 21.768 0.084 ;
    END
  END x[691]
  PIN x[692]
    DIRECTION INPUT ;
    USE SIGNAL ;
    PORT
      LAYER M5 ;
        RECT  21.84 0 21.864 0.084 ;
    END
  END x[692]
  PIN x[693]
    DIRECTION INPUT ;
    USE SIGNAL ;
    PORT
      LAYER M5 ;
        RECT  21.936 0 21.96 0.084 ;
    END
  END x[693]
  PIN x[694]
    DIRECTION INPUT ;
    USE SIGNAL ;
    PORT
      LAYER M5 ;
        RECT  22.032 0 22.056 0.084 ;
    END
  END x[694]
  PIN x[695]
    DIRECTION INPUT ;
    USE SIGNAL ;
    PORT
      LAYER M5 ;
        RECT  22.128 0 22.152 0.084 ;
    END
  END x[695]
  PIN x[696]
    DIRECTION INPUT ;
    USE SIGNAL ;
    PORT
      LAYER M5 ;
        RECT  22.224 0 22.248 0.084 ;
    END
  END x[696]
  PIN x[697]
    DIRECTION INPUT ;
    USE SIGNAL ;
    PORT
      LAYER M5 ;
        RECT  22.32 0 22.344 0.084 ;
    END
  END x[697]
  PIN x[698]
    DIRECTION INPUT ;
    USE SIGNAL ;
    PORT
      LAYER M5 ;
        RECT  22.416 0 22.44 0.084 ;
    END
  END x[698]
  PIN x[699]
    DIRECTION INPUT ;
    USE SIGNAL ;
    PORT
      LAYER M5 ;
        RECT  22.512 0 22.536 0.084 ;
    END
  END x[699]
  PIN x[69]
    DIRECTION INPUT ;
    USE SIGNAL ;
    PORT
      LAYER M3 ;
        RECT  79.812 0 79.83 0.037 ;
    END
  END x[69]
  PIN x[6]
    DIRECTION INPUT ;
    USE SIGNAL ;
    PORT
      LAYER M5 ;
        RECT  81.168 0 81.192 0.084 ;
    END
  END x[6]
  PIN x[700]
    DIRECTION INPUT ;
    USE SIGNAL ;
    PORT
      LAYER M5 ;
        RECT  22.608 0 22.632 0.084 ;
    END
  END x[700]
  PIN x[701]
    DIRECTION INPUT ;
    USE SIGNAL ;
    PORT
      LAYER M5 ;
        RECT  22.704 0 22.728 0.084 ;
    END
  END x[701]
  PIN x[702]
    DIRECTION INPUT ;
    USE SIGNAL ;
    PORT
      LAYER M5 ;
        RECT  22.8 0 22.824 0.084 ;
    END
  END x[702]
  PIN x[703]
    DIRECTION INPUT ;
    USE SIGNAL ;
    PORT
      LAYER M5 ;
        RECT  22.896 0 22.92 0.084 ;
    END
  END x[703]
  PIN x[704]
    DIRECTION INPUT ;
    USE SIGNAL ;
    PORT
      LAYER M5 ;
        RECT  39.12 0 39.144 0.084 ;
    END
  END x[704]
  PIN x[705]
    DIRECTION INPUT ;
    USE SIGNAL ;
    PORT
      LAYER M5 ;
        RECT  39.216 0 39.24 0.084 ;
    END
  END x[705]
  PIN x[706]
    DIRECTION INPUT ;
    USE SIGNAL ;
    PORT
      LAYER M5 ;
        RECT  39.312 0 39.336 0.084 ;
    END
  END x[706]
  PIN x[707]
    DIRECTION INPUT ;
    USE SIGNAL ;
    PORT
      LAYER M5 ;
        RECT  39.408 0 39.432 0.084 ;
    END
  END x[707]
  PIN x[708]
    DIRECTION INPUT ;
    USE SIGNAL ;
    PORT
      LAYER M5 ;
        RECT  39.504 0 39.528 0.084 ;
    END
  END x[708]
  PIN x[709]
    DIRECTION INPUT ;
    USE SIGNAL ;
    PORT
      LAYER M5 ;
        RECT  39.6 0 39.624 0.084 ;
    END
  END x[709]
  PIN x[70]
    DIRECTION INPUT ;
    USE SIGNAL ;
    PORT
      LAYER M3 ;
        RECT  79.884 0 79.902 0.037 ;
    END
  END x[70]
  PIN x[710]
    DIRECTION INPUT ;
    USE SIGNAL ;
    PORT
      LAYER M5 ;
        RECT  39.696 0 39.72 0.084 ;
    END
  END x[710]
  PIN x[711]
    DIRECTION INPUT ;
    USE SIGNAL ;
    PORT
      LAYER M5 ;
        RECT  39.792 0 39.816 0.084 ;
    END
  END x[711]
  PIN x[712]
    DIRECTION INPUT ;
    USE SIGNAL ;
    PORT
      LAYER M5 ;
        RECT  39.888 0 39.912 0.084 ;
    END
  END x[712]
  PIN x[713]
    DIRECTION INPUT ;
    USE SIGNAL ;
    PORT
      LAYER M5 ;
        RECT  39.984 0 40.008 0.084 ;
    END
  END x[713]
  PIN x[714]
    DIRECTION INPUT ;
    USE SIGNAL ;
    PORT
      LAYER M5 ;
        RECT  40.08 0 40.104 0.084 ;
    END
  END x[714]
  PIN x[715]
    DIRECTION INPUT ;
    USE SIGNAL ;
    PORT
      LAYER M5 ;
        RECT  40.176 0 40.2 0.084 ;
    END
  END x[715]
  PIN x[716]
    DIRECTION INPUT ;
    USE SIGNAL ;
    PORT
      LAYER M5 ;
        RECT  40.272 0 40.296 0.084 ;
    END
  END x[716]
  PIN x[717]
    DIRECTION INPUT ;
    USE SIGNAL ;
    PORT
      LAYER M5 ;
        RECT  40.368 0 40.392 0.084 ;
    END
  END x[717]
  PIN x[718]
    DIRECTION INPUT ;
    USE SIGNAL ;
    PORT
      LAYER M5 ;
        RECT  40.464 0 40.488 0.084 ;
    END
  END x[718]
  PIN x[719]
    DIRECTION INPUT ;
    USE SIGNAL ;
    PORT
      LAYER M5 ;
        RECT  40.56 0 40.584 0.084 ;
    END
  END x[719]
  PIN x[71]
    DIRECTION INPUT ;
    USE SIGNAL ;
    PORT
      LAYER M3 ;
        RECT  79.956 0 79.974 0.037 ;
    END
  END x[71]
  PIN x[720]
    DIRECTION INPUT ;
    USE SIGNAL ;
    PORT
      LAYER M5 ;
        RECT  40.656 0 40.68 0.084 ;
    END
  END x[720]
  PIN x[721]
    DIRECTION INPUT ;
    USE SIGNAL ;
    PORT
      LAYER M5 ;
        RECT  40.752 0 40.776 0.084 ;
    END
  END x[721]
  PIN x[722]
    DIRECTION INPUT ;
    USE SIGNAL ;
    PORT
      LAYER M5 ;
        RECT  40.848 0 40.872 0.084 ;
    END
  END x[722]
  PIN x[723]
    DIRECTION INPUT ;
    USE SIGNAL ;
    PORT
      LAYER M5 ;
        RECT  40.944 0 40.968 0.084 ;
    END
  END x[723]
  PIN x[724]
    DIRECTION INPUT ;
    USE SIGNAL ;
    PORT
      LAYER M5 ;
        RECT  41.04 0 41.064 0.084 ;
    END
  END x[724]
  PIN x[725]
    DIRECTION INPUT ;
    USE SIGNAL ;
    PORT
      LAYER M5 ;
        RECT  41.136 0 41.16 0.084 ;
    END
  END x[725]
  PIN x[726]
    DIRECTION INPUT ;
    USE SIGNAL ;
    PORT
      LAYER M5 ;
        RECT  41.232 0 41.256 0.084 ;
    END
  END x[726]
  PIN x[727]
    DIRECTION INPUT ;
    USE SIGNAL ;
    PORT
      LAYER M5 ;
        RECT  41.328 0 41.352 0.084 ;
    END
  END x[727]
  PIN x[728]
    DIRECTION INPUT ;
    USE SIGNAL ;
    PORT
      LAYER M5 ;
        RECT  41.424 0 41.448 0.084 ;
    END
  END x[728]
  PIN x[729]
    DIRECTION INPUT ;
    USE SIGNAL ;
    PORT
      LAYER M5 ;
        RECT  41.52 0 41.544 0.084 ;
    END
  END x[729]
  PIN x[72]
    DIRECTION INPUT ;
    USE SIGNAL ;
    PORT
      LAYER M3 ;
        RECT  80.028 0 80.046 0.037 ;
    END
  END x[72]
  PIN x[730]
    DIRECTION INPUT ;
    USE SIGNAL ;
    PORT
      LAYER M5 ;
        RECT  41.616 0 41.64 0.084 ;
    END
  END x[730]
  PIN x[731]
    DIRECTION INPUT ;
    USE SIGNAL ;
    PORT
      LAYER M5 ;
        RECT  41.712 0 41.736 0.084 ;
    END
  END x[731]
  PIN x[732]
    DIRECTION INPUT ;
    USE SIGNAL ;
    PORT
      LAYER M5 ;
        RECT  41.808 0 41.832 0.084 ;
    END
  END x[732]
  PIN x[733]
    DIRECTION INPUT ;
    USE SIGNAL ;
    PORT
      LAYER M5 ;
        RECT  41.904 0 41.928 0.084 ;
    END
  END x[733]
  PIN x[734]
    DIRECTION INPUT ;
    USE SIGNAL ;
    PORT
      LAYER M5 ;
        RECT  42 0 42.024 0.084 ;
    END
  END x[734]
  PIN x[735]
    DIRECTION INPUT ;
    USE SIGNAL ;
    PORT
      LAYER M5 ;
        RECT  42.096 0 42.12 0.084 ;
    END
  END x[735]
  PIN x[736]
    DIRECTION INPUT ;
    USE SIGNAL ;
    PORT
      LAYER M5 ;
        RECT  58.32 0 58.344 0.084 ;
    END
  END x[736]
  PIN x[737]
    DIRECTION INPUT ;
    USE SIGNAL ;
    PORT
      LAYER M5 ;
        RECT  58.416 0 58.44 0.084 ;
    END
  END x[737]
  PIN x[738]
    DIRECTION INPUT ;
    USE SIGNAL ;
    PORT
      LAYER M5 ;
        RECT  58.512 0 58.536 0.084 ;
    END
  END x[738]
  PIN x[739]
    DIRECTION INPUT ;
    USE SIGNAL ;
    PORT
      LAYER M5 ;
        RECT  58.608 0 58.632 0.084 ;
    END
  END x[739]
  PIN x[73]
    DIRECTION INPUT ;
    USE SIGNAL ;
    PORT
      LAYER M3 ;
        RECT  80.1 0 80.118 0.037 ;
    END
  END x[73]
  PIN x[740]
    DIRECTION INPUT ;
    USE SIGNAL ;
    PORT
      LAYER M5 ;
        RECT  58.704 0 58.728 0.084 ;
    END
  END x[740]
  PIN x[741]
    DIRECTION INPUT ;
    USE SIGNAL ;
    PORT
      LAYER M5 ;
        RECT  58.8 0 58.824 0.084 ;
    END
  END x[741]
  PIN x[742]
    DIRECTION INPUT ;
    USE SIGNAL ;
    PORT
      LAYER M5 ;
        RECT  58.896 0 58.92 0.084 ;
    END
  END x[742]
  PIN x[743]
    DIRECTION INPUT ;
    USE SIGNAL ;
    PORT
      LAYER M5 ;
        RECT  58.992 0 59.016 0.084 ;
    END
  END x[743]
  PIN x[744]
    DIRECTION INPUT ;
    USE SIGNAL ;
    PORT
      LAYER M5 ;
        RECT  59.088 0 59.112 0.084 ;
    END
  END x[744]
  PIN x[745]
    DIRECTION INPUT ;
    USE SIGNAL ;
    PORT
      LAYER M5 ;
        RECT  59.184 0 59.208 0.084 ;
    END
  END x[745]
  PIN x[746]
    DIRECTION INPUT ;
    USE SIGNAL ;
    PORT
      LAYER M5 ;
        RECT  59.28 0 59.304 0.084 ;
    END
  END x[746]
  PIN x[747]
    DIRECTION INPUT ;
    USE SIGNAL ;
    PORT
      LAYER M5 ;
        RECT  59.376 0 59.4 0.084 ;
    END
  END x[747]
  PIN x[748]
    DIRECTION INPUT ;
    USE SIGNAL ;
    PORT
      LAYER M5 ;
        RECT  59.472 0 59.496 0.084 ;
    END
  END x[748]
  PIN x[749]
    DIRECTION INPUT ;
    USE SIGNAL ;
    PORT
      LAYER M5 ;
        RECT  59.568 0 59.592 0.084 ;
    END
  END x[749]
  PIN x[74]
    DIRECTION INPUT ;
    USE SIGNAL ;
    PORT
      LAYER M3 ;
        RECT  80.172 0 80.19 0.037 ;
    END
  END x[74]
  PIN x[750]
    DIRECTION INPUT ;
    USE SIGNAL ;
    PORT
      LAYER M5 ;
        RECT  59.664 0 59.688 0.084 ;
    END
  END x[750]
  PIN x[751]
    DIRECTION INPUT ;
    USE SIGNAL ;
    PORT
      LAYER M5 ;
        RECT  59.76 0 59.784 0.084 ;
    END
  END x[751]
  PIN x[752]
    DIRECTION INPUT ;
    USE SIGNAL ;
    PORT
      LAYER M5 ;
        RECT  59.856 0 59.88 0.084 ;
    END
  END x[752]
  PIN x[753]
    DIRECTION INPUT ;
    USE SIGNAL ;
    PORT
      LAYER M5 ;
        RECT  59.952 0 59.976 0.084 ;
    END
  END x[753]
  PIN x[754]
    DIRECTION INPUT ;
    USE SIGNAL ;
    PORT
      LAYER M5 ;
        RECT  60.048 0 60.072 0.084 ;
    END
  END x[754]
  PIN x[755]
    DIRECTION INPUT ;
    USE SIGNAL ;
    PORT
      LAYER M5 ;
        RECT  60.144 0 60.168 0.084 ;
    END
  END x[755]
  PIN x[756]
    DIRECTION INPUT ;
    USE SIGNAL ;
    PORT
      LAYER M5 ;
        RECT  60.24 0 60.264 0.084 ;
    END
  END x[756]
  PIN x[757]
    DIRECTION INPUT ;
    USE SIGNAL ;
    PORT
      LAYER M5 ;
        RECT  60.336 0 60.36 0.084 ;
    END
  END x[757]
  PIN x[758]
    DIRECTION INPUT ;
    USE SIGNAL ;
    PORT
      LAYER M5 ;
        RECT  60.432 0 60.456 0.084 ;
    END
  END x[758]
  PIN x[759]
    DIRECTION INPUT ;
    USE SIGNAL ;
    PORT
      LAYER M5 ;
        RECT  60.528 0 60.552 0.084 ;
    END
  END x[759]
  PIN x[75]
    DIRECTION INPUT ;
    USE SIGNAL ;
    PORT
      LAYER M3 ;
        RECT  80.244 0 80.262 0.037 ;
    END
  END x[75]
  PIN x[760]
    DIRECTION INPUT ;
    USE SIGNAL ;
    PORT
      LAYER M5 ;
        RECT  60.624 0 60.648 0.084 ;
    END
  END x[760]
  PIN x[761]
    DIRECTION INPUT ;
    USE SIGNAL ;
    PORT
      LAYER M5 ;
        RECT  60.72 0 60.744 0.084 ;
    END
  END x[761]
  PIN x[762]
    DIRECTION INPUT ;
    USE SIGNAL ;
    PORT
      LAYER M5 ;
        RECT  60.816 0 60.84 0.084 ;
    END
  END x[762]
  PIN x[763]
    DIRECTION INPUT ;
    USE SIGNAL ;
    PORT
      LAYER M5 ;
        RECT  60.912 0 60.936 0.084 ;
    END
  END x[763]
  PIN x[764]
    DIRECTION INPUT ;
    USE SIGNAL ;
    PORT
      LAYER M5 ;
        RECT  61.008 0 61.032 0.084 ;
    END
  END x[764]
  PIN x[765]
    DIRECTION INPUT ;
    USE SIGNAL ;
    PORT
      LAYER M5 ;
        RECT  61.104 0 61.128 0.084 ;
    END
  END x[765]
  PIN x[766]
    DIRECTION INPUT ;
    USE SIGNAL ;
    PORT
      LAYER M5 ;
        RECT  61.2 0 61.224 0.084 ;
    END
  END x[766]
  PIN x[767]
    DIRECTION INPUT ;
    USE SIGNAL ;
    PORT
      LAYER M5 ;
        RECT  61.296 0 61.32 0.084 ;
    END
  END x[767]
  PIN x[768]
    DIRECTION INPUT ;
    USE SIGNAL ;
    PORT
      LAYER M5 ;
        RECT  115.92 0 115.944 0.084 ;
    END
  END x[768]
  PIN x[769]
    DIRECTION INPUT ;
    USE SIGNAL ;
    PORT
      LAYER M5 ;
        RECT  116.016 0 116.04 0.084 ;
    END
  END x[769]
  PIN x[76]
    DIRECTION INPUT ;
    USE SIGNAL ;
    PORT
      LAYER M3 ;
        RECT  80.316 0 80.334 0.037 ;
    END
  END x[76]
  PIN x[770]
    DIRECTION INPUT ;
    USE SIGNAL ;
    PORT
      LAYER M5 ;
        RECT  116.112 0 116.136 0.084 ;
    END
  END x[770]
  PIN x[771]
    DIRECTION INPUT ;
    USE SIGNAL ;
    PORT
      LAYER M5 ;
        RECT  116.208 0 116.232 0.084 ;
    END
  END x[771]
  PIN x[772]
    DIRECTION INPUT ;
    USE SIGNAL ;
    PORT
      LAYER M5 ;
        RECT  116.304 0 116.328 0.084 ;
    END
  END x[772]
  PIN x[773]
    DIRECTION INPUT ;
    USE SIGNAL ;
    PORT
      LAYER M5 ;
        RECT  116.4 0 116.424 0.084 ;
    END
  END x[773]
  PIN x[774]
    DIRECTION INPUT ;
    USE SIGNAL ;
    PORT
      LAYER M5 ;
        RECT  116.496 0 116.52 0.084 ;
    END
  END x[774]
  PIN x[775]
    DIRECTION INPUT ;
    USE SIGNAL ;
    PORT
      LAYER M5 ;
        RECT  116.592 0 116.616 0.084 ;
    END
  END x[775]
  PIN x[776]
    DIRECTION INPUT ;
    USE SIGNAL ;
    PORT
      LAYER M5 ;
        RECT  116.688 0 116.712 0.084 ;
    END
  END x[776]
  PIN x[777]
    DIRECTION INPUT ;
    USE SIGNAL ;
    PORT
      LAYER M5 ;
        RECT  116.784 0 116.808 0.084 ;
    END
  END x[777]
  PIN x[778]
    DIRECTION INPUT ;
    USE SIGNAL ;
    PORT
      LAYER M5 ;
        RECT  116.88 0 116.904 0.084 ;
    END
  END x[778]
  PIN x[779]
    DIRECTION INPUT ;
    USE SIGNAL ;
    PORT
      LAYER M5 ;
        RECT  116.976 0 117 0.084 ;
    END
  END x[779]
  PIN x[77]
    DIRECTION INPUT ;
    USE SIGNAL ;
    PORT
      LAYER M3 ;
        RECT  80.388 0 80.406 0.037 ;
    END
  END x[77]
  PIN x[780]
    DIRECTION INPUT ;
    USE SIGNAL ;
    PORT
      LAYER M5 ;
        RECT  117.072 0 117.096 0.084 ;
    END
  END x[780]
  PIN x[781]
    DIRECTION INPUT ;
    USE SIGNAL ;
    PORT
      LAYER M5 ;
        RECT  117.168 0 117.192 0.084 ;
    END
  END x[781]
  PIN x[782]
    DIRECTION INPUT ;
    USE SIGNAL ;
    PORT
      LAYER M5 ;
        RECT  117.264 0 117.288 0.084 ;
    END
  END x[782]
  PIN x[783]
    DIRECTION INPUT ;
    USE SIGNAL ;
    PORT
      LAYER M5 ;
        RECT  117.36 0 117.384 0.084 ;
    END
  END x[783]
  PIN x[784]
    DIRECTION INPUT ;
    USE SIGNAL ;
    PORT
      LAYER M5 ;
        RECT  117.456 0 117.48 0.084 ;
    END
  END x[784]
  PIN x[785]
    DIRECTION INPUT ;
    USE SIGNAL ;
    PORT
      LAYER M5 ;
        RECT  117.552 0 117.576 0.084 ;
    END
  END x[785]
  PIN x[786]
    DIRECTION INPUT ;
    USE SIGNAL ;
    PORT
      LAYER M5 ;
        RECT  117.648 0 117.672 0.084 ;
    END
  END x[786]
  PIN x[787]
    DIRECTION INPUT ;
    USE SIGNAL ;
    PORT
      LAYER M5 ;
        RECT  117.744 0 117.768 0.084 ;
    END
  END x[787]
  PIN x[788]
    DIRECTION INPUT ;
    USE SIGNAL ;
    PORT
      LAYER M5 ;
        RECT  117.84 0 117.864 0.084 ;
    END
  END x[788]
  PIN x[789]
    DIRECTION INPUT ;
    USE SIGNAL ;
    PORT
      LAYER M5 ;
        RECT  117.936 0 117.96 0.084 ;
    END
  END x[789]
  PIN x[78]
    DIRECTION INPUT ;
    USE SIGNAL ;
    PORT
      LAYER M3 ;
        RECT  80.46 0 80.478 0.037 ;
    END
  END x[78]
  PIN x[790]
    DIRECTION INPUT ;
    USE SIGNAL ;
    PORT
      LAYER M5 ;
        RECT  118.032 0 118.056 0.084 ;
    END
  END x[790]
  PIN x[791]
    DIRECTION INPUT ;
    USE SIGNAL ;
    PORT
      LAYER M5 ;
        RECT  118.128 0 118.152 0.084 ;
    END
  END x[791]
  PIN x[792]
    DIRECTION INPUT ;
    USE SIGNAL ;
    PORT
      LAYER M5 ;
        RECT  118.224 0 118.248 0.084 ;
    END
  END x[792]
  PIN x[793]
    DIRECTION INPUT ;
    USE SIGNAL ;
    PORT
      LAYER M5 ;
        RECT  118.32 0 118.344 0.084 ;
    END
  END x[793]
  PIN x[794]
    DIRECTION INPUT ;
    USE SIGNAL ;
    PORT
      LAYER M5 ;
        RECT  118.416 0 118.44 0.084 ;
    END
  END x[794]
  PIN x[795]
    DIRECTION INPUT ;
    USE SIGNAL ;
    PORT
      LAYER M5 ;
        RECT  118.512 0 118.536 0.084 ;
    END
  END x[795]
  PIN x[796]
    DIRECTION INPUT ;
    USE SIGNAL ;
    PORT
      LAYER M5 ;
        RECT  118.608 0 118.632 0.084 ;
    END
  END x[796]
  PIN x[797]
    DIRECTION INPUT ;
    USE SIGNAL ;
    PORT
      LAYER M5 ;
        RECT  118.704 0 118.728 0.084 ;
    END
  END x[797]
  PIN x[798]
    DIRECTION INPUT ;
    USE SIGNAL ;
    PORT
      LAYER M5 ;
        RECT  118.8 0 118.824 0.084 ;
    END
  END x[798]
  PIN x[799]
    DIRECTION INPUT ;
    USE SIGNAL ;
    PORT
      LAYER M5 ;
        RECT  118.896 0 118.92 0.084 ;
    END
  END x[799]
  PIN x[79]
    DIRECTION INPUT ;
    USE SIGNAL ;
    PORT
      LAYER M3 ;
        RECT  80.532 0 80.55 0.037 ;
    END
  END x[79]
  PIN x[7]
    DIRECTION INPUT ;
    USE SIGNAL ;
    PORT
      LAYER M5 ;
        RECT  81.264 0 81.288 0.084 ;
    END
  END x[7]
  PIN x[800]
    DIRECTION INPUT ;
    USE SIGNAL ;
    PORT
      LAYER M5 ;
        RECT  135.12 0 135.144 0.084 ;
    END
  END x[800]
  PIN x[801]
    DIRECTION INPUT ;
    USE SIGNAL ;
    PORT
      LAYER M5 ;
        RECT  135.216 0 135.24 0.084 ;
    END
  END x[801]
  PIN x[802]
    DIRECTION INPUT ;
    USE SIGNAL ;
    PORT
      LAYER M5 ;
        RECT  135.312 0 135.336 0.084 ;
    END
  END x[802]
  PIN x[803]
    DIRECTION INPUT ;
    USE SIGNAL ;
    PORT
      LAYER M5 ;
        RECT  135.408 0 135.432 0.084 ;
    END
  END x[803]
  PIN x[804]
    DIRECTION INPUT ;
    USE SIGNAL ;
    PORT
      LAYER M5 ;
        RECT  135.504 0 135.528 0.084 ;
    END
  END x[804]
  PIN x[805]
    DIRECTION INPUT ;
    USE SIGNAL ;
    PORT
      LAYER M5 ;
        RECT  135.6 0 135.624 0.084 ;
    END
  END x[805]
  PIN x[806]
    DIRECTION INPUT ;
    USE SIGNAL ;
    PORT
      LAYER M5 ;
        RECT  135.696 0 135.72 0.084 ;
    END
  END x[806]
  PIN x[807]
    DIRECTION INPUT ;
    USE SIGNAL ;
    PORT
      LAYER M5 ;
        RECT  135.792 0 135.816 0.084 ;
    END
  END x[807]
  PIN x[808]
    DIRECTION INPUT ;
    USE SIGNAL ;
    PORT
      LAYER M5 ;
        RECT  135.888 0 135.912 0.084 ;
    END
  END x[808]
  PIN x[809]
    DIRECTION INPUT ;
    USE SIGNAL ;
    PORT
      LAYER M5 ;
        RECT  135.984 0 136.008 0.084 ;
    END
  END x[809]
  PIN x[80]
    DIRECTION INPUT ;
    USE SIGNAL ;
    PORT
      LAYER M3 ;
        RECT  80.604 0 80.622 0.037 ;
    END
  END x[80]
  PIN x[810]
    DIRECTION INPUT ;
    USE SIGNAL ;
    PORT
      LAYER M5 ;
        RECT  136.08 0 136.104 0.084 ;
    END
  END x[810]
  PIN x[811]
    DIRECTION INPUT ;
    USE SIGNAL ;
    PORT
      LAYER M5 ;
        RECT  136.176 0 136.2 0.084 ;
    END
  END x[811]
  PIN x[812]
    DIRECTION INPUT ;
    USE SIGNAL ;
    PORT
      LAYER M5 ;
        RECT  136.272 0 136.296 0.084 ;
    END
  END x[812]
  PIN x[813]
    DIRECTION INPUT ;
    USE SIGNAL ;
    PORT
      LAYER M5 ;
        RECT  136.368 0 136.392 0.084 ;
    END
  END x[813]
  PIN x[814]
    DIRECTION INPUT ;
    USE SIGNAL ;
    PORT
      LAYER M5 ;
        RECT  136.464 0 136.488 0.084 ;
    END
  END x[814]
  PIN x[815]
    DIRECTION INPUT ;
    USE SIGNAL ;
    PORT
      LAYER M5 ;
        RECT  136.56 0 136.584 0.084 ;
    END
  END x[815]
  PIN x[816]
    DIRECTION INPUT ;
    USE SIGNAL ;
    PORT
      LAYER M5 ;
        RECT  136.656 0 136.68 0.084 ;
    END
  END x[816]
  PIN x[817]
    DIRECTION INPUT ;
    USE SIGNAL ;
    PORT
      LAYER M5 ;
        RECT  136.752 0 136.776 0.084 ;
    END
  END x[817]
  PIN x[818]
    DIRECTION INPUT ;
    USE SIGNAL ;
    PORT
      LAYER M5 ;
        RECT  136.848 0 136.872 0.084 ;
    END
  END x[818]
  PIN x[819]
    DIRECTION INPUT ;
    USE SIGNAL ;
    PORT
      LAYER M5 ;
        RECT  136.944 0 136.968 0.084 ;
    END
  END x[819]
  PIN x[81]
    DIRECTION INPUT ;
    USE SIGNAL ;
    PORT
      LAYER M3 ;
        RECT  80.676 0 80.694 0.037 ;
    END
  END x[81]
  PIN x[820]
    DIRECTION INPUT ;
    USE SIGNAL ;
    PORT
      LAYER M5 ;
        RECT  137.04 0 137.064 0.084 ;
    END
  END x[820]
  PIN x[821]
    DIRECTION INPUT ;
    USE SIGNAL ;
    PORT
      LAYER M5 ;
        RECT  137.136 0 137.16 0.084 ;
    END
  END x[821]
  PIN x[822]
    DIRECTION INPUT ;
    USE SIGNAL ;
    PORT
      LAYER M5 ;
        RECT  137.232 0 137.256 0.084 ;
    END
  END x[822]
  PIN x[823]
    DIRECTION INPUT ;
    USE SIGNAL ;
    PORT
      LAYER M5 ;
        RECT  137.328 0 137.352 0.084 ;
    END
  END x[823]
  PIN x[824]
    DIRECTION INPUT ;
    USE SIGNAL ;
    PORT
      LAYER M5 ;
        RECT  137.424 0 137.448 0.084 ;
    END
  END x[824]
  PIN x[825]
    DIRECTION INPUT ;
    USE SIGNAL ;
    PORT
      LAYER M5 ;
        RECT  137.52 0 137.544 0.084 ;
    END
  END x[825]
  PIN x[826]
    DIRECTION INPUT ;
    USE SIGNAL ;
    PORT
      LAYER M5 ;
        RECT  137.616 0 137.64 0.084 ;
    END
  END x[826]
  PIN x[827]
    DIRECTION INPUT ;
    USE SIGNAL ;
    PORT
      LAYER M5 ;
        RECT  137.712 0 137.736 0.084 ;
    END
  END x[827]
  PIN x[828]
    DIRECTION INPUT ;
    USE SIGNAL ;
    PORT
      LAYER M5 ;
        RECT  137.808 0 137.832 0.084 ;
    END
  END x[828]
  PIN x[829]
    DIRECTION INPUT ;
    USE SIGNAL ;
    PORT
      LAYER M5 ;
        RECT  137.904 0 137.928 0.084 ;
    END
  END x[829]
  PIN x[82]
    DIRECTION INPUT ;
    USE SIGNAL ;
    PORT
      LAYER M3 ;
        RECT  80.748 0 80.766 0.037 ;
    END
  END x[82]
  PIN x[830]
    DIRECTION INPUT ;
    USE SIGNAL ;
    PORT
      LAYER M5 ;
        RECT  138 0 138.024 0.084 ;
    END
  END x[830]
  PIN x[831]
    DIRECTION INPUT ;
    USE SIGNAL ;
    PORT
      LAYER M5 ;
        RECT  138.096 0 138.12 0.084 ;
    END
  END x[831]
  PIN x[832]
    DIRECTION INPUT ;
    USE SIGNAL ;
    PORT
      LAYER M5 ;
        RECT  154.32 0 154.344 0.084 ;
    END
  END x[832]
  PIN x[833]
    DIRECTION INPUT ;
    USE SIGNAL ;
    PORT
      LAYER M5 ;
        RECT  154.416 0 154.44 0.084 ;
    END
  END x[833]
  PIN x[834]
    DIRECTION INPUT ;
    USE SIGNAL ;
    PORT
      LAYER M5 ;
        RECT  154.512 0 154.536 0.084 ;
    END
  END x[834]
  PIN x[835]
    DIRECTION INPUT ;
    USE SIGNAL ;
    PORT
      LAYER M5 ;
        RECT  154.608 0 154.632 0.084 ;
    END
  END x[835]
  PIN x[836]
    DIRECTION INPUT ;
    USE SIGNAL ;
    PORT
      LAYER M5 ;
        RECT  154.704 0 154.728 0.084 ;
    END
  END x[836]
  PIN x[837]
    DIRECTION INPUT ;
    USE SIGNAL ;
    PORT
      LAYER M5 ;
        RECT  154.8 0 154.824 0.084 ;
    END
  END x[837]
  PIN x[838]
    DIRECTION INPUT ;
    USE SIGNAL ;
    PORT
      LAYER M5 ;
        RECT  154.896 0 154.92 0.084 ;
    END
  END x[838]
  PIN x[839]
    DIRECTION INPUT ;
    USE SIGNAL ;
    PORT
      LAYER M5 ;
        RECT  154.992 0 155.016 0.084 ;
    END
  END x[839]
  PIN x[83]
    DIRECTION INPUT ;
    USE SIGNAL ;
    PORT
      LAYER M3 ;
        RECT  80.82 0 80.838 0.037 ;
    END
  END x[83]
  PIN x[840]
    DIRECTION INPUT ;
    USE SIGNAL ;
    PORT
      LAYER M5 ;
        RECT  155.088 0 155.112 0.084 ;
    END
  END x[840]
  PIN x[841]
    DIRECTION INPUT ;
    USE SIGNAL ;
    PORT
      LAYER M5 ;
        RECT  155.184 0 155.208 0.084 ;
    END
  END x[841]
  PIN x[842]
    DIRECTION INPUT ;
    USE SIGNAL ;
    PORT
      LAYER M5 ;
        RECT  155.28 0 155.304 0.084 ;
    END
  END x[842]
  PIN x[843]
    DIRECTION INPUT ;
    USE SIGNAL ;
    PORT
      LAYER M5 ;
        RECT  155.376 0 155.4 0.084 ;
    END
  END x[843]
  PIN x[844]
    DIRECTION INPUT ;
    USE SIGNAL ;
    PORT
      LAYER M5 ;
        RECT  155.472 0 155.496 0.084 ;
    END
  END x[844]
  PIN x[845]
    DIRECTION INPUT ;
    USE SIGNAL ;
    PORT
      LAYER M5 ;
        RECT  155.568 0 155.592 0.084 ;
    END
  END x[845]
  PIN x[846]
    DIRECTION INPUT ;
    USE SIGNAL ;
    PORT
      LAYER M5 ;
        RECT  155.664 0 155.688 0.084 ;
    END
  END x[846]
  PIN x[847]
    DIRECTION INPUT ;
    USE SIGNAL ;
    PORT
      LAYER M5 ;
        RECT  155.76 0 155.784 0.084 ;
    END
  END x[847]
  PIN x[848]
    DIRECTION INPUT ;
    USE SIGNAL ;
    PORT
      LAYER M5 ;
        RECT  155.856 0 155.88 0.084 ;
    END
  END x[848]
  PIN x[849]
    DIRECTION INPUT ;
    USE SIGNAL ;
    PORT
      LAYER M5 ;
        RECT  155.952 0 155.976 0.084 ;
    END
  END x[849]
  PIN x[84]
    DIRECTION INPUT ;
    USE SIGNAL ;
    PORT
      LAYER M3 ;
        RECT  80.892 0 80.91 0.037 ;
    END
  END x[84]
  PIN x[850]
    DIRECTION INPUT ;
    USE SIGNAL ;
    PORT
      LAYER M5 ;
        RECT  156.048 0 156.072 0.084 ;
    END
  END x[850]
  PIN x[851]
    DIRECTION INPUT ;
    USE SIGNAL ;
    PORT
      LAYER M5 ;
        RECT  156.144 0 156.168 0.084 ;
    END
  END x[851]
  PIN x[852]
    DIRECTION INPUT ;
    USE SIGNAL ;
    PORT
      LAYER M5 ;
        RECT  156.24 0 156.264 0.084 ;
    END
  END x[852]
  PIN x[853]
    DIRECTION INPUT ;
    USE SIGNAL ;
    PORT
      LAYER M5 ;
        RECT  156.336 0 156.36 0.084 ;
    END
  END x[853]
  PIN x[854]
    DIRECTION INPUT ;
    USE SIGNAL ;
    PORT
      LAYER M5 ;
        RECT  156.432 0 156.456 0.084 ;
    END
  END x[854]
  PIN x[855]
    DIRECTION INPUT ;
    USE SIGNAL ;
    PORT
      LAYER M5 ;
        RECT  156.528 0 156.552 0.084 ;
    END
  END x[855]
  PIN x[856]
    DIRECTION INPUT ;
    USE SIGNAL ;
    PORT
      LAYER M5 ;
        RECT  156.624 0 156.648 0.084 ;
    END
  END x[856]
  PIN x[857]
    DIRECTION INPUT ;
    USE SIGNAL ;
    PORT
      LAYER M5 ;
        RECT  156.72 0 156.744 0.084 ;
    END
  END x[857]
  PIN x[858]
    DIRECTION INPUT ;
    USE SIGNAL ;
    PORT
      LAYER M5 ;
        RECT  156.816 0 156.84 0.084 ;
    END
  END x[858]
  PIN x[859]
    DIRECTION INPUT ;
    USE SIGNAL ;
    PORT
      LAYER M5 ;
        RECT  156.912 0 156.936 0.084 ;
    END
  END x[859]
  PIN x[85]
    DIRECTION INPUT ;
    USE SIGNAL ;
    PORT
      LAYER M3 ;
        RECT  80.964 0 80.982 0.037 ;
    END
  END x[85]
  PIN x[860]
    DIRECTION INPUT ;
    USE SIGNAL ;
    PORT
      LAYER M5 ;
        RECT  157.008 0 157.032 0.084 ;
    END
  END x[860]
  PIN x[861]
    DIRECTION INPUT ;
    USE SIGNAL ;
    PORT
      LAYER M5 ;
        RECT  157.104 0 157.128 0.084 ;
    END
  END x[861]
  PIN x[862]
    DIRECTION INPUT ;
    USE SIGNAL ;
    PORT
      LAYER M5 ;
        RECT  157.2 0 157.224 0.084 ;
    END
  END x[862]
  PIN x[863]
    DIRECTION INPUT ;
    USE SIGNAL ;
    PORT
      LAYER M5 ;
        RECT  157.296 0 157.32 0.084 ;
    END
  END x[863]
  PIN x[864]
    DIRECTION INPUT ;
    USE SIGNAL ;
    PORT
      LAYER M5 ;
        RECT  173.52 0 173.544 0.084 ;
    END
  END x[864]
  PIN x[865]
    DIRECTION INPUT ;
    USE SIGNAL ;
    PORT
      LAYER M5 ;
        RECT  173.616 0 173.64 0.084 ;
    END
  END x[865]
  PIN x[866]
    DIRECTION INPUT ;
    USE SIGNAL ;
    PORT
      LAYER M5 ;
        RECT  173.712 0 173.736 0.084 ;
    END
  END x[866]
  PIN x[867]
    DIRECTION INPUT ;
    USE SIGNAL ;
    PORT
      LAYER M5 ;
        RECT  173.808 0 173.832 0.084 ;
    END
  END x[867]
  PIN x[868]
    DIRECTION INPUT ;
    USE SIGNAL ;
    PORT
      LAYER M5 ;
        RECT  173.904 0 173.928 0.084 ;
    END
  END x[868]
  PIN x[869]
    DIRECTION INPUT ;
    USE SIGNAL ;
    PORT
      LAYER M5 ;
        RECT  174 0 174.024 0.084 ;
    END
  END x[869]
  PIN x[86]
    DIRECTION INPUT ;
    USE SIGNAL ;
    PORT
      LAYER M3 ;
        RECT  81.036 0 81.054 0.037 ;
    END
  END x[86]
  PIN x[870]
    DIRECTION INPUT ;
    USE SIGNAL ;
    PORT
      LAYER M5 ;
        RECT  174.096 0 174.12 0.084 ;
    END
  END x[870]
  PIN x[871]
    DIRECTION INPUT ;
    USE SIGNAL ;
    PORT
      LAYER M5 ;
        RECT  174.192 0 174.216 0.084 ;
    END
  END x[871]
  PIN x[872]
    DIRECTION INPUT ;
    USE SIGNAL ;
    PORT
      LAYER M5 ;
        RECT  174.288 0 174.312 0.084 ;
    END
  END x[872]
  PIN x[873]
    DIRECTION INPUT ;
    USE SIGNAL ;
    PORT
      LAYER M5 ;
        RECT  174.384 0 174.408 0.084 ;
    END
  END x[873]
  PIN x[874]
    DIRECTION INPUT ;
    USE SIGNAL ;
    PORT
      LAYER M5 ;
        RECT  174.48 0 174.504 0.084 ;
    END
  END x[874]
  PIN x[875]
    DIRECTION INPUT ;
    USE SIGNAL ;
    PORT
      LAYER M5 ;
        RECT  174.576 0 174.6 0.084 ;
    END
  END x[875]
  PIN x[876]
    DIRECTION INPUT ;
    USE SIGNAL ;
    PORT
      LAYER M5 ;
        RECT  174.672 0 174.696 0.084 ;
    END
  END x[876]
  PIN x[877]
    DIRECTION INPUT ;
    USE SIGNAL ;
    PORT
      LAYER M5 ;
        RECT  174.768 0 174.792 0.084 ;
    END
  END x[877]
  PIN x[878]
    DIRECTION INPUT ;
    USE SIGNAL ;
    PORT
      LAYER M5 ;
        RECT  174.864 0 174.888 0.084 ;
    END
  END x[878]
  PIN x[879]
    DIRECTION INPUT ;
    USE SIGNAL ;
    PORT
      LAYER M5 ;
        RECT  174.96 0 174.984 0.084 ;
    END
  END x[879]
  PIN x[87]
    DIRECTION INPUT ;
    USE SIGNAL ;
    PORT
      LAYER M3 ;
        RECT  81.108 0 81.126 0.037 ;
    END
  END x[87]
  PIN x[880]
    DIRECTION INPUT ;
    USE SIGNAL ;
    PORT
      LAYER M5 ;
        RECT  175.056 0 175.08 0.084 ;
    END
  END x[880]
  PIN x[881]
    DIRECTION INPUT ;
    USE SIGNAL ;
    PORT
      LAYER M5 ;
        RECT  175.152 0 175.176 0.084 ;
    END
  END x[881]
  PIN x[882]
    DIRECTION INPUT ;
    USE SIGNAL ;
    PORT
      LAYER M5 ;
        RECT  175.248 0 175.272 0.084 ;
    END
  END x[882]
  PIN x[883]
    DIRECTION INPUT ;
    USE SIGNAL ;
    PORT
      LAYER M5 ;
        RECT  175.344 0 175.368 0.084 ;
    END
  END x[883]
  PIN x[884]
    DIRECTION INPUT ;
    USE SIGNAL ;
    PORT
      LAYER M5 ;
        RECT  175.44 0 175.464 0.084 ;
    END
  END x[884]
  PIN x[885]
    DIRECTION INPUT ;
    USE SIGNAL ;
    PORT
      LAYER M5 ;
        RECT  175.536 0 175.56 0.084 ;
    END
  END x[885]
  PIN x[886]
    DIRECTION INPUT ;
    USE SIGNAL ;
    PORT
      LAYER M5 ;
        RECT  175.632 0 175.656 0.084 ;
    END
  END x[886]
  PIN x[887]
    DIRECTION INPUT ;
    USE SIGNAL ;
    PORT
      LAYER M5 ;
        RECT  175.728 0 175.752 0.084 ;
    END
  END x[887]
  PIN x[888]
    DIRECTION INPUT ;
    USE SIGNAL ;
    PORT
      LAYER M5 ;
        RECT  175.824 0 175.848 0.084 ;
    END
  END x[888]
  PIN x[889]
    DIRECTION INPUT ;
    USE SIGNAL ;
    PORT
      LAYER M5 ;
        RECT  175.92 0 175.944 0.084 ;
    END
  END x[889]
  PIN x[88]
    DIRECTION INPUT ;
    USE SIGNAL ;
    PORT
      LAYER M3 ;
        RECT  81.18 0 81.198 0.037 ;
    END
  END x[88]
  PIN x[890]
    DIRECTION INPUT ;
    USE SIGNAL ;
    PORT
      LAYER M5 ;
        RECT  176.016 0 176.04 0.084 ;
    END
  END x[890]
  PIN x[891]
    DIRECTION INPUT ;
    USE SIGNAL ;
    PORT
      LAYER M5 ;
        RECT  176.112 0 176.136 0.084 ;
    END
  END x[891]
  PIN x[892]
    DIRECTION INPUT ;
    USE SIGNAL ;
    PORT
      LAYER M5 ;
        RECT  176.208 0 176.232 0.084 ;
    END
  END x[892]
  PIN x[893]
    DIRECTION INPUT ;
    USE SIGNAL ;
    PORT
      LAYER M5 ;
        RECT  176.304 0 176.328 0.084 ;
    END
  END x[893]
  PIN x[894]
    DIRECTION INPUT ;
    USE SIGNAL ;
    PORT
      LAYER M5 ;
        RECT  176.4 0 176.424 0.084 ;
    END
  END x[894]
  PIN x[895]
    DIRECTION INPUT ;
    USE SIGNAL ;
    PORT
      LAYER M5 ;
        RECT  176.496 0 176.52 0.084 ;
    END
  END x[895]
  PIN x[896]
    DIRECTION INPUT ;
    USE SIGNAL ;
    PORT
      LAYER M3 ;
        RECT  2.844 0 2.862 0.037 ;
    END
  END x[896]
  PIN x[897]
    DIRECTION INPUT ;
    USE SIGNAL ;
    PORT
      LAYER M3 ;
        RECT  2.916 0 2.934 0.037 ;
    END
  END x[897]
  PIN x[898]
    DIRECTION INPUT ;
    USE SIGNAL ;
    PORT
      LAYER M3 ;
        RECT  2.988 0 3.006 0.037 ;
    END
  END x[898]
  PIN x[899]
    DIRECTION INPUT ;
    USE SIGNAL ;
    PORT
      LAYER M3 ;
        RECT  3.06 0 3.078 0.037 ;
    END
  END x[899]
  PIN x[89]
    DIRECTION INPUT ;
    USE SIGNAL ;
    PORT
      LAYER M3 ;
        RECT  81.252 0 81.27 0.037 ;
    END
  END x[89]
  PIN x[8]
    DIRECTION INPUT ;
    USE SIGNAL ;
    PORT
      LAYER M5 ;
        RECT  81.36 0 81.384 0.084 ;
    END
  END x[8]
  PIN x[900]
    DIRECTION INPUT ;
    USE SIGNAL ;
    PORT
      LAYER M3 ;
        RECT  3.132 0 3.15 0.037 ;
    END
  END x[900]
  PIN x[901]
    DIRECTION INPUT ;
    USE SIGNAL ;
    PORT
      LAYER M3 ;
        RECT  3.204 0 3.222 0.037 ;
    END
  END x[901]
  PIN x[902]
    DIRECTION INPUT ;
    USE SIGNAL ;
    PORT
      LAYER M3 ;
        RECT  3.276 0 3.294 0.037 ;
    END
  END x[902]
  PIN x[903]
    DIRECTION INPUT ;
    USE SIGNAL ;
    PORT
      LAYER M3 ;
        RECT  3.348 0 3.366 0.037 ;
    END
  END x[903]
  PIN x[904]
    DIRECTION INPUT ;
    USE SIGNAL ;
    PORT
      LAYER M3 ;
        RECT  3.42 0 3.438 0.037 ;
    END
  END x[904]
  PIN x[905]
    DIRECTION INPUT ;
    USE SIGNAL ;
    PORT
      LAYER M3 ;
        RECT  3.492 0 3.51 0.037 ;
    END
  END x[905]
  PIN x[906]
    DIRECTION INPUT ;
    USE SIGNAL ;
    PORT
      LAYER M3 ;
        RECT  3.564 0 3.582 0.037 ;
    END
  END x[906]
  PIN x[907]
    DIRECTION INPUT ;
    USE SIGNAL ;
    PORT
      LAYER M3 ;
        RECT  3.636 0 3.654 0.037 ;
    END
  END x[907]
  PIN x[908]
    DIRECTION INPUT ;
    USE SIGNAL ;
    PORT
      LAYER M3 ;
        RECT  3.708 0 3.726 0.037 ;
    END
  END x[908]
  PIN x[909]
    DIRECTION INPUT ;
    USE SIGNAL ;
    PORT
      LAYER M3 ;
        RECT  3.78 0 3.798 0.037 ;
    END
  END x[909]
  PIN x[90]
    DIRECTION INPUT ;
    USE SIGNAL ;
    PORT
      LAYER M3 ;
        RECT  81.324 0 81.342 0.037 ;
    END
  END x[90]
  PIN x[910]
    DIRECTION INPUT ;
    USE SIGNAL ;
    PORT
      LAYER M3 ;
        RECT  3.852 0 3.87 0.037 ;
    END
  END x[910]
  PIN x[911]
    DIRECTION INPUT ;
    USE SIGNAL ;
    PORT
      LAYER M3 ;
        RECT  3.924 0 3.942 0.037 ;
    END
  END x[911]
  PIN x[912]
    DIRECTION INPUT ;
    USE SIGNAL ;
    PORT
      LAYER M3 ;
        RECT  3.996 0 4.014 0.037 ;
    END
  END x[912]
  PIN x[913]
    DIRECTION INPUT ;
    USE SIGNAL ;
    PORT
      LAYER M3 ;
        RECT  4.068 0 4.086 0.037 ;
    END
  END x[913]
  PIN x[914]
    DIRECTION INPUT ;
    USE SIGNAL ;
    PORT
      LAYER M3 ;
        RECT  4.14 0 4.158 0.037 ;
    END
  END x[914]
  PIN x[915]
    DIRECTION INPUT ;
    USE SIGNAL ;
    PORT
      LAYER M3 ;
        RECT  4.212 0 4.23 0.037 ;
    END
  END x[915]
  PIN x[916]
    DIRECTION INPUT ;
    USE SIGNAL ;
    PORT
      LAYER M3 ;
        RECT  4.284 0 4.302 0.037 ;
    END
  END x[916]
  PIN x[917]
    DIRECTION INPUT ;
    USE SIGNAL ;
    PORT
      LAYER M3 ;
        RECT  4.356 0 4.374 0.037 ;
    END
  END x[917]
  PIN x[918]
    DIRECTION INPUT ;
    USE SIGNAL ;
    PORT
      LAYER M3 ;
        RECT  4.428 0 4.446 0.037 ;
    END
  END x[918]
  PIN x[919]
    DIRECTION INPUT ;
    USE SIGNAL ;
    PORT
      LAYER M3 ;
        RECT  4.5 0 4.518 0.037 ;
    END
  END x[919]
  PIN x[91]
    DIRECTION INPUT ;
    USE SIGNAL ;
    PORT
      LAYER M3 ;
        RECT  81.396 0 81.414 0.037 ;
    END
  END x[91]
  PIN x[920]
    DIRECTION INPUT ;
    USE SIGNAL ;
    PORT
      LAYER M3 ;
        RECT  4.572 0 4.59 0.037 ;
    END
  END x[920]
  PIN x[921]
    DIRECTION INPUT ;
    USE SIGNAL ;
    PORT
      LAYER M3 ;
        RECT  4.644 0 4.662 0.037 ;
    END
  END x[921]
  PIN x[922]
    DIRECTION INPUT ;
    USE SIGNAL ;
    PORT
      LAYER M3 ;
        RECT  4.716 0 4.734 0.037 ;
    END
  END x[922]
  PIN x[923]
    DIRECTION INPUT ;
    USE SIGNAL ;
    PORT
      LAYER M3 ;
        RECT  4.788 0 4.806 0.037 ;
    END
  END x[923]
  PIN x[924]
    DIRECTION INPUT ;
    USE SIGNAL ;
    PORT
      LAYER M3 ;
        RECT  4.86 0 4.878 0.037 ;
    END
  END x[924]
  PIN x[925]
    DIRECTION INPUT ;
    USE SIGNAL ;
    PORT
      LAYER M3 ;
        RECT  4.932 0 4.95 0.037 ;
    END
  END x[925]
  PIN x[926]
    DIRECTION INPUT ;
    USE SIGNAL ;
    PORT
      LAYER M3 ;
        RECT  5.004 0 5.022 0.037 ;
    END
  END x[926]
  PIN x[927]
    DIRECTION INPUT ;
    USE SIGNAL ;
    PORT
      LAYER M3 ;
        RECT  5.076 0 5.094 0.037 ;
    END
  END x[927]
  PIN x[928]
    DIRECTION INPUT ;
    USE SIGNAL ;
    PORT
      LAYER M3 ;
        RECT  17.244 0 17.262 0.037 ;
    END
  END x[928]
  PIN x[929]
    DIRECTION INPUT ;
    USE SIGNAL ;
    PORT
      LAYER M3 ;
        RECT  17.316 0 17.334 0.037 ;
    END
  END x[929]
  PIN x[92]
    DIRECTION INPUT ;
    USE SIGNAL ;
    PORT
      LAYER M3 ;
        RECT  81.468 0 81.486 0.037 ;
    END
  END x[92]
  PIN x[930]
    DIRECTION INPUT ;
    USE SIGNAL ;
    PORT
      LAYER M3 ;
        RECT  17.388 0 17.406 0.037 ;
    END
  END x[930]
  PIN x[931]
    DIRECTION INPUT ;
    USE SIGNAL ;
    PORT
      LAYER M3 ;
        RECT  17.46 0 17.478 0.037 ;
    END
  END x[931]
  PIN x[932]
    DIRECTION INPUT ;
    USE SIGNAL ;
    PORT
      LAYER M3 ;
        RECT  17.532 0 17.55 0.037 ;
    END
  END x[932]
  PIN x[933]
    DIRECTION INPUT ;
    USE SIGNAL ;
    PORT
      LAYER M3 ;
        RECT  17.604 0 17.622 0.037 ;
    END
  END x[933]
  PIN x[934]
    DIRECTION INPUT ;
    USE SIGNAL ;
    PORT
      LAYER M3 ;
        RECT  17.676 0 17.694 0.037 ;
    END
  END x[934]
  PIN x[935]
    DIRECTION INPUT ;
    USE SIGNAL ;
    PORT
      LAYER M3 ;
        RECT  17.748 0 17.766 0.037 ;
    END
  END x[935]
  PIN x[936]
    DIRECTION INPUT ;
    USE SIGNAL ;
    PORT
      LAYER M3 ;
        RECT  17.82 0 17.838 0.037 ;
    END
  END x[936]
  PIN x[937]
    DIRECTION INPUT ;
    USE SIGNAL ;
    PORT
      LAYER M3 ;
        RECT  17.892 0 17.91 0.037 ;
    END
  END x[937]
  PIN x[938]
    DIRECTION INPUT ;
    USE SIGNAL ;
    PORT
      LAYER M3 ;
        RECT  17.964 0 17.982 0.037 ;
    END
  END x[938]
  PIN x[939]
    DIRECTION INPUT ;
    USE SIGNAL ;
    PORT
      LAYER M3 ;
        RECT  18.036 0 18.054 0.037 ;
    END
  END x[939]
  PIN x[93]
    DIRECTION INPUT ;
    USE SIGNAL ;
    PORT
      LAYER M3 ;
        RECT  81.54 0 81.558 0.037 ;
    END
  END x[93]
  PIN x[940]
    DIRECTION INPUT ;
    USE SIGNAL ;
    PORT
      LAYER M3 ;
        RECT  18.108 0 18.126 0.037 ;
    END
  END x[940]
  PIN x[941]
    DIRECTION INPUT ;
    USE SIGNAL ;
    PORT
      LAYER M3 ;
        RECT  18.18 0 18.198 0.037 ;
    END
  END x[941]
  PIN x[942]
    DIRECTION INPUT ;
    USE SIGNAL ;
    PORT
      LAYER M3 ;
        RECT  18.252 0 18.27 0.037 ;
    END
  END x[942]
  PIN x[943]
    DIRECTION INPUT ;
    USE SIGNAL ;
    PORT
      LAYER M3 ;
        RECT  18.324 0 18.342 0.037 ;
    END
  END x[943]
  PIN x[944]
    DIRECTION INPUT ;
    USE SIGNAL ;
    PORT
      LAYER M3 ;
        RECT  18.396 0 18.414 0.037 ;
    END
  END x[944]
  PIN x[945]
    DIRECTION INPUT ;
    USE SIGNAL ;
    PORT
      LAYER M3 ;
        RECT  18.468 0 18.486 0.037 ;
    END
  END x[945]
  PIN x[946]
    DIRECTION INPUT ;
    USE SIGNAL ;
    PORT
      LAYER M3 ;
        RECT  18.54 0 18.558 0.037 ;
    END
  END x[946]
  PIN x[947]
    DIRECTION INPUT ;
    USE SIGNAL ;
    PORT
      LAYER M3 ;
        RECT  18.612 0 18.63 0.037 ;
    END
  END x[947]
  PIN x[948]
    DIRECTION INPUT ;
    USE SIGNAL ;
    PORT
      LAYER M3 ;
        RECT  18.684 0 18.702 0.037 ;
    END
  END x[948]
  PIN x[949]
    DIRECTION INPUT ;
    USE SIGNAL ;
    PORT
      LAYER M3 ;
        RECT  18.756 0 18.774 0.037 ;
    END
  END x[949]
  PIN x[94]
    DIRECTION INPUT ;
    USE SIGNAL ;
    PORT
      LAYER M3 ;
        RECT  81.612 0 81.63 0.037 ;
    END
  END x[94]
  PIN x[950]
    DIRECTION INPUT ;
    USE SIGNAL ;
    PORT
      LAYER M3 ;
        RECT  18.828 0 18.846 0.037 ;
    END
  END x[950]
  PIN x[951]
    DIRECTION INPUT ;
    USE SIGNAL ;
    PORT
      LAYER M3 ;
        RECT  18.9 0 18.918 0.037 ;
    END
  END x[951]
  PIN x[952]
    DIRECTION INPUT ;
    USE SIGNAL ;
    PORT
      LAYER M3 ;
        RECT  18.972 0 18.99 0.037 ;
    END
  END x[952]
  PIN x[953]
    DIRECTION INPUT ;
    USE SIGNAL ;
    PORT
      LAYER M3 ;
        RECT  19.044 0 19.062 0.037 ;
    END
  END x[953]
  PIN x[954]
    DIRECTION INPUT ;
    USE SIGNAL ;
    PORT
      LAYER M3 ;
        RECT  19.116 0 19.134 0.037 ;
    END
  END x[954]
  PIN x[955]
    DIRECTION INPUT ;
    USE SIGNAL ;
    PORT
      LAYER M3 ;
        RECT  19.188 0 19.206 0.037 ;
    END
  END x[955]
  PIN x[956]
    DIRECTION INPUT ;
    USE SIGNAL ;
    PORT
      LAYER M3 ;
        RECT  19.26 0 19.278 0.037 ;
    END
  END x[956]
  PIN x[957]
    DIRECTION INPUT ;
    USE SIGNAL ;
    PORT
      LAYER M3 ;
        RECT  19.332 0 19.35 0.037 ;
    END
  END x[957]
  PIN x[958]
    DIRECTION INPUT ;
    USE SIGNAL ;
    PORT
      LAYER M3 ;
        RECT  19.404 0 19.422 0.037 ;
    END
  END x[958]
  PIN x[959]
    DIRECTION INPUT ;
    USE SIGNAL ;
    PORT
      LAYER M3 ;
        RECT  19.476 0 19.494 0.037 ;
    END
  END x[959]
  PIN x[95]
    DIRECTION INPUT ;
    USE SIGNAL ;
    PORT
      LAYER M3 ;
        RECT  81.684 0 81.702 0.037 ;
    END
  END x[95]
  PIN x[960]
    DIRECTION INPUT ;
    USE SIGNAL ;
    PORT
      LAYER M3 ;
        RECT  31.644 0 31.662 0.037 ;
    END
  END x[960]
  PIN x[961]
    DIRECTION INPUT ;
    USE SIGNAL ;
    PORT
      LAYER M3 ;
        RECT  31.716 0 31.734 0.037 ;
    END
  END x[961]
  PIN x[962]
    DIRECTION INPUT ;
    USE SIGNAL ;
    PORT
      LAYER M3 ;
        RECT  31.788 0 31.806 0.037 ;
    END
  END x[962]
  PIN x[963]
    DIRECTION INPUT ;
    USE SIGNAL ;
    PORT
      LAYER M3 ;
        RECT  31.86 0 31.878 0.037 ;
    END
  END x[963]
  PIN x[964]
    DIRECTION INPUT ;
    USE SIGNAL ;
    PORT
      LAYER M3 ;
        RECT  31.932 0 31.95 0.037 ;
    END
  END x[964]
  PIN x[965]
    DIRECTION INPUT ;
    USE SIGNAL ;
    PORT
      LAYER M3 ;
        RECT  32.004 0 32.022 0.037 ;
    END
  END x[965]
  PIN x[966]
    DIRECTION INPUT ;
    USE SIGNAL ;
    PORT
      LAYER M3 ;
        RECT  32.076 0 32.094 0.037 ;
    END
  END x[966]
  PIN x[967]
    DIRECTION INPUT ;
    USE SIGNAL ;
    PORT
      LAYER M3 ;
        RECT  32.148 0 32.166 0.037 ;
    END
  END x[967]
  PIN x[968]
    DIRECTION INPUT ;
    USE SIGNAL ;
    PORT
      LAYER M3 ;
        RECT  32.22 0 32.238 0.037 ;
    END
  END x[968]
  PIN x[969]
    DIRECTION INPUT ;
    USE SIGNAL ;
    PORT
      LAYER M3 ;
        RECT  32.292 0 32.31 0.037 ;
    END
  END x[969]
  PIN x[96]
    DIRECTION INPUT ;
    USE SIGNAL ;
    PORT
      LAYER M5 ;
        RECT  77.52 0 77.544 0.084 ;
    END
  END x[96]
  PIN x[970]
    DIRECTION INPUT ;
    USE SIGNAL ;
    PORT
      LAYER M3 ;
        RECT  32.364 0 32.382 0.037 ;
    END
  END x[970]
  PIN x[971]
    DIRECTION INPUT ;
    USE SIGNAL ;
    PORT
      LAYER M3 ;
        RECT  32.436 0 32.454 0.037 ;
    END
  END x[971]
  PIN x[972]
    DIRECTION INPUT ;
    USE SIGNAL ;
    PORT
      LAYER M3 ;
        RECT  32.508 0 32.526 0.037 ;
    END
  END x[972]
  PIN x[973]
    DIRECTION INPUT ;
    USE SIGNAL ;
    PORT
      LAYER M3 ;
        RECT  32.58 0 32.598 0.037 ;
    END
  END x[973]
  PIN x[974]
    DIRECTION INPUT ;
    USE SIGNAL ;
    PORT
      LAYER M3 ;
        RECT  32.652 0 32.67 0.037 ;
    END
  END x[974]
  PIN x[975]
    DIRECTION INPUT ;
    USE SIGNAL ;
    PORT
      LAYER M3 ;
        RECT  32.724 0 32.742 0.037 ;
    END
  END x[975]
  PIN x[976]
    DIRECTION INPUT ;
    USE SIGNAL ;
    PORT
      LAYER M3 ;
        RECT  32.796 0 32.814 0.037 ;
    END
  END x[976]
  PIN x[977]
    DIRECTION INPUT ;
    USE SIGNAL ;
    PORT
      LAYER M3 ;
        RECT  32.868 0 32.886 0.037 ;
    END
  END x[977]
  PIN x[978]
    DIRECTION INPUT ;
    USE SIGNAL ;
    PORT
      LAYER M3 ;
        RECT  32.94 0 32.958 0.037 ;
    END
  END x[978]
  PIN x[979]
    DIRECTION INPUT ;
    USE SIGNAL ;
    PORT
      LAYER M3 ;
        RECT  33.012 0 33.03 0.037 ;
    END
  END x[979]
  PIN x[97]
    DIRECTION INPUT ;
    USE SIGNAL ;
    PORT
      LAYER M5 ;
        RECT  77.616 0 77.64 0.084 ;
    END
  END x[97]
  PIN x[980]
    DIRECTION INPUT ;
    USE SIGNAL ;
    PORT
      LAYER M3 ;
        RECT  33.084 0 33.102 0.037 ;
    END
  END x[980]
  PIN x[981]
    DIRECTION INPUT ;
    USE SIGNAL ;
    PORT
      LAYER M3 ;
        RECT  33.156 0 33.174 0.037 ;
    END
  END x[981]
  PIN x[982]
    DIRECTION INPUT ;
    USE SIGNAL ;
    PORT
      LAYER M3 ;
        RECT  33.228 0 33.246 0.037 ;
    END
  END x[982]
  PIN x[983]
    DIRECTION INPUT ;
    USE SIGNAL ;
    PORT
      LAYER M3 ;
        RECT  33.3 0 33.318 0.037 ;
    END
  END x[983]
  PIN x[984]
    DIRECTION INPUT ;
    USE SIGNAL ;
    PORT
      LAYER M3 ;
        RECT  33.372 0 33.39 0.037 ;
    END
  END x[984]
  PIN x[985]
    DIRECTION INPUT ;
    USE SIGNAL ;
    PORT
      LAYER M3 ;
        RECT  33.444 0 33.462 0.037 ;
    END
  END x[985]
  PIN x[986]
    DIRECTION INPUT ;
    USE SIGNAL ;
    PORT
      LAYER M3 ;
        RECT  33.516 0 33.534 0.037 ;
    END
  END x[986]
  PIN x[987]
    DIRECTION INPUT ;
    USE SIGNAL ;
    PORT
      LAYER M3 ;
        RECT  33.588 0 33.606 0.037 ;
    END
  END x[987]
  PIN x[988]
    DIRECTION INPUT ;
    USE SIGNAL ;
    PORT
      LAYER M3 ;
        RECT  33.66 0 33.678 0.037 ;
    END
  END x[988]
  PIN x[989]
    DIRECTION INPUT ;
    USE SIGNAL ;
    PORT
      LAYER M3 ;
        RECT  33.732 0 33.75 0.037 ;
    END
  END x[989]
  PIN x[98]
    DIRECTION INPUT ;
    USE SIGNAL ;
    PORT
      LAYER M5 ;
        RECT  77.712 0 77.736 0.084 ;
    END
  END x[98]
  PIN x[990]
    DIRECTION INPUT ;
    USE SIGNAL ;
    PORT
      LAYER M3 ;
        RECT  33.804 0 33.822 0.037 ;
    END
  END x[990]
  PIN x[991]
    DIRECTION INPUT ;
    USE SIGNAL ;
    PORT
      LAYER M3 ;
        RECT  33.876 0 33.894 0.037 ;
    END
  END x[991]
  PIN x[992]
    DIRECTION INPUT ;
    USE SIGNAL ;
    PORT
      LAYER M3 ;
        RECT  46.044 0 46.062 0.037 ;
    END
  END x[992]
  PIN x[993]
    DIRECTION INPUT ;
    USE SIGNAL ;
    PORT
      LAYER M3 ;
        RECT  46.116 0 46.134 0.037 ;
    END
  END x[993]
  PIN x[994]
    DIRECTION INPUT ;
    USE SIGNAL ;
    PORT
      LAYER M3 ;
        RECT  46.188 0 46.206 0.037 ;
    END
  END x[994]
  PIN x[995]
    DIRECTION INPUT ;
    USE SIGNAL ;
    PORT
      LAYER M3 ;
        RECT  46.26 0 46.278 0.037 ;
    END
  END x[995]
  PIN x[996]
    DIRECTION INPUT ;
    USE SIGNAL ;
    PORT
      LAYER M3 ;
        RECT  46.332 0 46.35 0.037 ;
    END
  END x[996]
  PIN x[997]
    DIRECTION INPUT ;
    USE SIGNAL ;
    PORT
      LAYER M3 ;
        RECT  46.404 0 46.422 0.037 ;
    END
  END x[997]
  PIN x[998]
    DIRECTION INPUT ;
    USE SIGNAL ;
    PORT
      LAYER M3 ;
        RECT  46.476 0 46.494 0.037 ;
    END
  END x[998]
  PIN x[999]
    DIRECTION INPUT ;
    USE SIGNAL ;
    PORT
      LAYER M3 ;
        RECT  46.548 0 46.566 0.037 ;
    END
  END x[999]
  PIN x[99]
    DIRECTION INPUT ;
    USE SIGNAL ;
    PORT
      LAYER M5 ;
        RECT  77.808 0 77.832 0.084 ;
    END
  END x[99]
  PIN x[9]
    DIRECTION INPUT ;
    USE SIGNAL ;
    PORT
      LAYER M5 ;
        RECT  81.456 0 81.48 0.084 ;
    END
  END x[9]
  PIN y[0]
    DIRECTION OUTPUT ;
    USE SIGNAL ;
    PORT
      LAYER M3 ;
        RECT  107.316 64.763 107.334 64.8 ;
    END
  END y[0]
  PIN y[100]
    DIRECTION OUTPUT ;
    USE SIGNAL ;
    PORT
      LAYER M5 ;
        RECT  133.776 64.716 133.8 64.8 ;
    END
  END y[100]
  PIN y[101]
    DIRECTION OUTPUT ;
    USE SIGNAL ;
    PORT
      LAYER M5 ;
        RECT  133.872 64.716 133.896 64.8 ;
    END
  END y[101]
  PIN y[102]
    DIRECTION OUTPUT ;
    USE SIGNAL ;
    PORT
      LAYER M5 ;
        RECT  133.968 64.716 133.992 64.8 ;
    END
  END y[102]
  PIN y[103]
    DIRECTION OUTPUT ;
    USE SIGNAL ;
    PORT
      LAYER M5 ;
        RECT  134.064 64.716 134.088 64.8 ;
    END
  END y[103]
  PIN y[104]
    DIRECTION OUTPUT ;
    USE SIGNAL ;
    PORT
      LAYER M5 ;
        RECT  134.16 64.716 134.184 64.8 ;
    END
  END y[104]
  PIN y[105]
    DIRECTION OUTPUT ;
    USE SIGNAL ;
    PORT
      LAYER M5 ;
        RECT  134.256 64.716 134.28 64.8 ;
    END
  END y[105]
  PIN y[106]
    DIRECTION OUTPUT ;
    USE SIGNAL ;
    PORT
      LAYER M5 ;
        RECT  134.352 64.716 134.376 64.8 ;
    END
  END y[106]
  PIN y[107]
    DIRECTION OUTPUT ;
    USE SIGNAL ;
    PORT
      LAYER M5 ;
        RECT  134.448 64.716 134.472 64.8 ;
    END
  END y[107]
  PIN y[108]
    DIRECTION OUTPUT ;
    USE SIGNAL ;
    PORT
      LAYER M5 ;
        RECT  134.544 64.716 134.568 64.8 ;
    END
  END y[108]
  PIN y[109]
    DIRECTION OUTPUT ;
    USE SIGNAL ;
    PORT
      LAYER M5 ;
        RECT  134.64 64.716 134.664 64.8 ;
    END
  END y[109]
  PIN y[10]
    DIRECTION OUTPUT ;
    USE SIGNAL ;
    PORT
      LAYER M3 ;
        RECT  108.036 64.763 108.054 64.8 ;
    END
  END y[10]
  PIN y[110]
    DIRECTION OUTPUT ;
    USE SIGNAL ;
    PORT
      LAYER M5 ;
        RECT  134.736 64.716 134.76 64.8 ;
    END
  END y[110]
  PIN y[111]
    DIRECTION OUTPUT ;
    USE SIGNAL ;
    PORT
      LAYER M5 ;
        RECT  134.832 64.716 134.856 64.8 ;
    END
  END y[111]
  PIN y[112]
    DIRECTION OUTPUT ;
    USE SIGNAL ;
    PORT
      LAYER M5 ;
        RECT  134.928 64.716 134.952 64.8 ;
    END
  END y[112]
  PIN y[113]
    DIRECTION OUTPUT ;
    USE SIGNAL ;
    PORT
      LAYER M5 ;
        RECT  135.024 64.716 135.048 64.8 ;
    END
  END y[113]
  PIN y[114]
    DIRECTION OUTPUT ;
    USE SIGNAL ;
    PORT
      LAYER M5 ;
        RECT  135.12 64.716 135.144 64.8 ;
    END
  END y[114]
  PIN y[115]
    DIRECTION OUTPUT ;
    USE SIGNAL ;
    PORT
      LAYER M5 ;
        RECT  135.216 64.716 135.24 64.8 ;
    END
  END y[115]
  PIN y[116]
    DIRECTION OUTPUT ;
    USE SIGNAL ;
    PORT
      LAYER M3 ;
        RECT  120.852 64.763 120.87 64.8 ;
    END
  END y[116]
  PIN y[117]
    DIRECTION OUTPUT ;
    USE SIGNAL ;
    PORT
      LAYER M3 ;
        RECT  120.924 64.763 120.942 64.8 ;
    END
  END y[117]
  PIN y[118]
    DIRECTION OUTPUT ;
    USE SIGNAL ;
    PORT
      LAYER M3 ;
        RECT  120.996 64.763 121.014 64.8 ;
    END
  END y[118]
  PIN y[119]
    DIRECTION OUTPUT ;
    USE SIGNAL ;
    PORT
      LAYER M3 ;
        RECT  121.068 64.763 121.086 64.8 ;
    END
  END y[119]
  PIN y[11]
    DIRECTION OUTPUT ;
    USE SIGNAL ;
    PORT
      LAYER M3 ;
        RECT  108.108 64.763 108.126 64.8 ;
    END
  END y[11]
  PIN y[120]
    DIRECTION OUTPUT ;
    USE SIGNAL ;
    PORT
      LAYER M3 ;
        RECT  121.14 64.763 121.158 64.8 ;
    END
  END y[120]
  PIN y[121]
    DIRECTION OUTPUT ;
    USE SIGNAL ;
    PORT
      LAYER M3 ;
        RECT  121.212 64.763 121.23 64.8 ;
    END
  END y[121]
  PIN y[122]
    DIRECTION OUTPUT ;
    USE SIGNAL ;
    PORT
      LAYER M3 ;
        RECT  121.284 64.763 121.302 64.8 ;
    END
  END y[122]
  PIN y[123]
    DIRECTION OUTPUT ;
    USE SIGNAL ;
    PORT
      LAYER M3 ;
        RECT  121.356 64.763 121.374 64.8 ;
    END
  END y[123]
  PIN y[124]
    DIRECTION OUTPUT ;
    USE SIGNAL ;
    PORT
      LAYER M3 ;
        RECT  121.428 64.763 121.446 64.8 ;
    END
  END y[124]
  PIN y[125]
    DIRECTION OUTPUT ;
    USE SIGNAL ;
    PORT
      LAYER M3 ;
        RECT  121.5 64.763 121.518 64.8 ;
    END
  END y[125]
  PIN y[126]
    DIRECTION OUTPUT ;
    USE SIGNAL ;
    PORT
      LAYER M3 ;
        RECT  121.572 64.763 121.59 64.8 ;
    END
  END y[126]
  PIN y[127]
    DIRECTION OUTPUT ;
    USE SIGNAL ;
    PORT
      LAYER M3 ;
        RECT  121.644 64.763 121.662 64.8 ;
    END
  END y[127]
  PIN y[128]
    DIRECTION OUTPUT ;
    USE SIGNAL ;
    PORT
      LAYER M3 ;
        RECT  121.716 64.763 121.734 64.8 ;
    END
  END y[128]
  PIN y[129]
    DIRECTION OUTPUT ;
    USE SIGNAL ;
    PORT
      LAYER M3 ;
        RECT  121.788 64.763 121.806 64.8 ;
    END
  END y[129]
  PIN y[12]
    DIRECTION OUTPUT ;
    USE SIGNAL ;
    PORT
      LAYER M3 ;
        RECT  108.18 64.763 108.198 64.8 ;
    END
  END y[12]
  PIN y[130]
    DIRECTION OUTPUT ;
    USE SIGNAL ;
    PORT
      LAYER M3 ;
        RECT  121.86 64.763 121.878 64.8 ;
    END
  END y[130]
  PIN y[131]
    DIRECTION OUTPUT ;
    USE SIGNAL ;
    PORT
      LAYER M3 ;
        RECT  121.932 64.763 121.95 64.8 ;
    END
  END y[131]
  PIN y[132]
    DIRECTION OUTPUT ;
    USE SIGNAL ;
    PORT
      LAYER M3 ;
        RECT  122.004 64.763 122.022 64.8 ;
    END
  END y[132]
  PIN y[133]
    DIRECTION OUTPUT ;
    USE SIGNAL ;
    PORT
      LAYER M3 ;
        RECT  122.076 64.763 122.094 64.8 ;
    END
  END y[133]
  PIN y[134]
    DIRECTION OUTPUT ;
    USE SIGNAL ;
    PORT
      LAYER M3 ;
        RECT  122.148 64.763 122.166 64.8 ;
    END
  END y[134]
  PIN y[135]
    DIRECTION OUTPUT ;
    USE SIGNAL ;
    PORT
      LAYER M3 ;
        RECT  122.22 64.763 122.238 64.8 ;
    END
  END y[135]
  PIN y[136]
    DIRECTION OUTPUT ;
    USE SIGNAL ;
    PORT
      LAYER M3 ;
        RECT  122.292 64.763 122.31 64.8 ;
    END
  END y[136]
  PIN y[137]
    DIRECTION OUTPUT ;
    USE SIGNAL ;
    PORT
      LAYER M3 ;
        RECT  122.364 64.763 122.382 64.8 ;
    END
  END y[137]
  PIN y[138]
    DIRECTION OUTPUT ;
    USE SIGNAL ;
    PORT
      LAYER M3 ;
        RECT  122.436 64.763 122.454 64.8 ;
    END
  END y[138]
  PIN y[139]
    DIRECTION OUTPUT ;
    USE SIGNAL ;
    PORT
      LAYER M3 ;
        RECT  122.508 64.763 122.526 64.8 ;
    END
  END y[139]
  PIN y[13]
    DIRECTION OUTPUT ;
    USE SIGNAL ;
    PORT
      LAYER M3 ;
        RECT  108.252 64.763 108.27 64.8 ;
    END
  END y[13]
  PIN y[140]
    DIRECTION OUTPUT ;
    USE SIGNAL ;
    PORT
      LAYER M3 ;
        RECT  122.58 64.763 122.598 64.8 ;
    END
  END y[140]
  PIN y[141]
    DIRECTION OUTPUT ;
    USE SIGNAL ;
    PORT
      LAYER M3 ;
        RECT  122.652 64.763 122.67 64.8 ;
    END
  END y[141]
  PIN y[142]
    DIRECTION OUTPUT ;
    USE SIGNAL ;
    PORT
      LAYER M3 ;
        RECT  122.724 64.763 122.742 64.8 ;
    END
  END y[142]
  PIN y[143]
    DIRECTION OUTPUT ;
    USE SIGNAL ;
    PORT
      LAYER M3 ;
        RECT  122.796 64.763 122.814 64.8 ;
    END
  END y[143]
  PIN y[144]
    DIRECTION OUTPUT ;
    USE SIGNAL ;
    PORT
      LAYER M3 ;
        RECT  122.868 64.763 122.886 64.8 ;
    END
  END y[144]
  PIN y[145]
    DIRECTION OUTPUT ;
    USE SIGNAL ;
    PORT
      LAYER M3 ;
        RECT  122.94 64.763 122.958 64.8 ;
    END
  END y[145]
  PIN y[146]
    DIRECTION OUTPUT ;
    USE SIGNAL ;
    PORT
      LAYER M3 ;
        RECT  123.012 64.763 123.03 64.8 ;
    END
  END y[146]
  PIN y[147]
    DIRECTION OUTPUT ;
    USE SIGNAL ;
    PORT
      LAYER M3 ;
        RECT  123.084 64.763 123.102 64.8 ;
    END
  END y[147]
  PIN y[148]
    DIRECTION OUTPUT ;
    USE SIGNAL ;
    PORT
      LAYER M5 ;
        RECT  109.968 64.716 109.992 64.8 ;
    END
  END y[148]
  PIN y[149]
    DIRECTION OUTPUT ;
    USE SIGNAL ;
    PORT
      LAYER M5 ;
        RECT  110.064 64.716 110.088 64.8 ;
    END
  END y[149]
  PIN y[14]
    DIRECTION OUTPUT ;
    USE SIGNAL ;
    PORT
      LAYER M3 ;
        RECT  108.324 64.763 108.342 64.8 ;
    END
  END y[14]
  PIN y[150]
    DIRECTION OUTPUT ;
    USE SIGNAL ;
    PORT
      LAYER M5 ;
        RECT  110.16 64.716 110.184 64.8 ;
    END
  END y[150]
  PIN y[151]
    DIRECTION OUTPUT ;
    USE SIGNAL ;
    PORT
      LAYER M5 ;
        RECT  110.256 64.716 110.28 64.8 ;
    END
  END y[151]
  PIN y[152]
    DIRECTION OUTPUT ;
    USE SIGNAL ;
    PORT
      LAYER M5 ;
        RECT  110.352 64.716 110.376 64.8 ;
    END
  END y[152]
  PIN y[153]
    DIRECTION OUTPUT ;
    USE SIGNAL ;
    PORT
      LAYER M5 ;
        RECT  110.448 64.716 110.472 64.8 ;
    END
  END y[153]
  PIN y[154]
    DIRECTION OUTPUT ;
    USE SIGNAL ;
    PORT
      LAYER M5 ;
        RECT  110.544 64.716 110.568 64.8 ;
    END
  END y[154]
  PIN y[155]
    DIRECTION OUTPUT ;
    USE SIGNAL ;
    PORT
      LAYER M5 ;
        RECT  110.64 64.716 110.664 64.8 ;
    END
  END y[155]
  PIN y[156]
    DIRECTION OUTPUT ;
    USE SIGNAL ;
    PORT
      LAYER M5 ;
        RECT  110.736 64.716 110.76 64.8 ;
    END
  END y[156]
  PIN y[157]
    DIRECTION OUTPUT ;
    USE SIGNAL ;
    PORT
      LAYER M5 ;
        RECT  110.832 64.716 110.856 64.8 ;
    END
  END y[157]
  PIN y[158]
    DIRECTION OUTPUT ;
    USE SIGNAL ;
    PORT
      LAYER M5 ;
        RECT  110.928 64.716 110.952 64.8 ;
    END
  END y[158]
  PIN y[159]
    DIRECTION OUTPUT ;
    USE SIGNAL ;
    PORT
      LAYER M5 ;
        RECT  111.024 64.716 111.048 64.8 ;
    END
  END y[159]
  PIN y[15]
    DIRECTION OUTPUT ;
    USE SIGNAL ;
    PORT
      LAYER M3 ;
        RECT  108.396 64.763 108.414 64.8 ;
    END
  END y[15]
  PIN y[160]
    DIRECTION OUTPUT ;
    USE SIGNAL ;
    PORT
      LAYER M5 ;
        RECT  111.12 64.716 111.144 64.8 ;
    END
  END y[160]
  PIN y[161]
    DIRECTION OUTPUT ;
    USE SIGNAL ;
    PORT
      LAYER M5 ;
        RECT  111.216 64.716 111.24 64.8 ;
    END
  END y[161]
  PIN y[162]
    DIRECTION OUTPUT ;
    USE SIGNAL ;
    PORT
      LAYER M5 ;
        RECT  111.312 64.716 111.336 64.8 ;
    END
  END y[162]
  PIN y[163]
    DIRECTION OUTPUT ;
    USE SIGNAL ;
    PORT
      LAYER M5 ;
        RECT  111.408 64.716 111.432 64.8 ;
    END
  END y[163]
  PIN y[164]
    DIRECTION OUTPUT ;
    USE SIGNAL ;
    PORT
      LAYER M5 ;
        RECT  111.504 64.716 111.528 64.8 ;
    END
  END y[164]
  PIN y[165]
    DIRECTION OUTPUT ;
    USE SIGNAL ;
    PORT
      LAYER M5 ;
        RECT  111.6 64.716 111.624 64.8 ;
    END
  END y[165]
  PIN y[166]
    DIRECTION OUTPUT ;
    USE SIGNAL ;
    PORT
      LAYER M5 ;
        RECT  111.696 64.716 111.72 64.8 ;
    END
  END y[166]
  PIN y[167]
    DIRECTION OUTPUT ;
    USE SIGNAL ;
    PORT
      LAYER M5 ;
        RECT  111.792 64.716 111.816 64.8 ;
    END
  END y[167]
  PIN y[168]
    DIRECTION OUTPUT ;
    USE SIGNAL ;
    PORT
      LAYER M5 ;
        RECT  111.888 64.716 111.912 64.8 ;
    END
  END y[168]
  PIN y[169]
    DIRECTION OUTPUT ;
    USE SIGNAL ;
    PORT
      LAYER M5 ;
        RECT  111.984 64.716 112.008 64.8 ;
    END
  END y[169]
  PIN y[16]
    DIRECTION OUTPUT ;
    USE SIGNAL ;
    PORT
      LAYER M3 ;
        RECT  108.468 64.763 108.486 64.8 ;
    END
  END y[16]
  PIN y[170]
    DIRECTION OUTPUT ;
    USE SIGNAL ;
    PORT
      LAYER M5 ;
        RECT  112.08 64.716 112.104 64.8 ;
    END
  END y[170]
  PIN y[171]
    DIRECTION OUTPUT ;
    USE SIGNAL ;
    PORT
      LAYER M5 ;
        RECT  112.176 64.716 112.2 64.8 ;
    END
  END y[171]
  PIN y[172]
    DIRECTION OUTPUT ;
    USE SIGNAL ;
    PORT
      LAYER M5 ;
        RECT  112.272 64.716 112.296 64.8 ;
    END
  END y[172]
  PIN y[173]
    DIRECTION OUTPUT ;
    USE SIGNAL ;
    PORT
      LAYER M5 ;
        RECT  112.368 64.716 112.392 64.8 ;
    END
  END y[173]
  PIN y[174]
    DIRECTION OUTPUT ;
    USE SIGNAL ;
    PORT
      LAYER M5 ;
        RECT  112.464 64.716 112.488 64.8 ;
    END
  END y[174]
  PIN y[175]
    DIRECTION OUTPUT ;
    USE SIGNAL ;
    PORT
      LAYER M5 ;
        RECT  112.56 64.716 112.584 64.8 ;
    END
  END y[175]
  PIN y[176]
    DIRECTION OUTPUT ;
    USE SIGNAL ;
    PORT
      LAYER M5 ;
        RECT  112.656 64.716 112.68 64.8 ;
    END
  END y[176]
  PIN y[177]
    DIRECTION OUTPUT ;
    USE SIGNAL ;
    PORT
      LAYER M5 ;
        RECT  112.752 64.716 112.776 64.8 ;
    END
  END y[177]
  PIN y[178]
    DIRECTION OUTPUT ;
    USE SIGNAL ;
    PORT
      LAYER M5 ;
        RECT  112.848 64.716 112.872 64.8 ;
    END
  END y[178]
  PIN y[179]
    DIRECTION OUTPUT ;
    USE SIGNAL ;
    PORT
      LAYER M5 ;
        RECT  112.944 64.716 112.968 64.8 ;
    END
  END y[179]
  PIN y[17]
    DIRECTION OUTPUT ;
    USE SIGNAL ;
    PORT
      LAYER M3 ;
        RECT  108.54 64.763 108.558 64.8 ;
    END
  END y[17]
  PIN y[180]
    DIRECTION OUTPUT ;
    USE SIGNAL ;
    PORT
      LAYER M3 ;
        RECT  116.244 64.763 116.262 64.8 ;
    END
  END y[180]
  PIN y[181]
    DIRECTION OUTPUT ;
    USE SIGNAL ;
    PORT
      LAYER M3 ;
        RECT  116.316 64.763 116.334 64.8 ;
    END
  END y[181]
  PIN y[182]
    DIRECTION OUTPUT ;
    USE SIGNAL ;
    PORT
      LAYER M3 ;
        RECT  116.388 64.763 116.406 64.8 ;
    END
  END y[182]
  PIN y[183]
    DIRECTION OUTPUT ;
    USE SIGNAL ;
    PORT
      LAYER M3 ;
        RECT  116.46 64.763 116.478 64.8 ;
    END
  END y[183]
  PIN y[184]
    DIRECTION OUTPUT ;
    USE SIGNAL ;
    PORT
      LAYER M3 ;
        RECT  116.532 64.763 116.55 64.8 ;
    END
  END y[184]
  PIN y[185]
    DIRECTION OUTPUT ;
    USE SIGNAL ;
    PORT
      LAYER M3 ;
        RECT  116.604 64.763 116.622 64.8 ;
    END
  END y[185]
  PIN y[186]
    DIRECTION OUTPUT ;
    USE SIGNAL ;
    PORT
      LAYER M3 ;
        RECT  116.676 64.763 116.694 64.8 ;
    END
  END y[186]
  PIN y[187]
    DIRECTION OUTPUT ;
    USE SIGNAL ;
    PORT
      LAYER M3 ;
        RECT  116.748 64.763 116.766 64.8 ;
    END
  END y[187]
  PIN y[188]
    DIRECTION OUTPUT ;
    USE SIGNAL ;
    PORT
      LAYER M3 ;
        RECT  116.82 64.763 116.838 64.8 ;
    END
  END y[188]
  PIN y[189]
    DIRECTION OUTPUT ;
    USE SIGNAL ;
    PORT
      LAYER M3 ;
        RECT  116.892 64.763 116.91 64.8 ;
    END
  END y[189]
  PIN y[18]
    DIRECTION OUTPUT ;
    USE SIGNAL ;
    PORT
      LAYER M3 ;
        RECT  108.612 64.763 108.63 64.8 ;
    END
  END y[18]
  PIN y[190]
    DIRECTION OUTPUT ;
    USE SIGNAL ;
    PORT
      LAYER M3 ;
        RECT  116.964 64.763 116.982 64.8 ;
    END
  END y[190]
  PIN y[191]
    DIRECTION OUTPUT ;
    USE SIGNAL ;
    PORT
      LAYER M3 ;
        RECT  117.036 64.763 117.054 64.8 ;
    END
  END y[191]
  PIN y[192]
    DIRECTION OUTPUT ;
    USE SIGNAL ;
    PORT
      LAYER M3 ;
        RECT  117.108 64.763 117.126 64.8 ;
    END
  END y[192]
  PIN y[193]
    DIRECTION OUTPUT ;
    USE SIGNAL ;
    PORT
      LAYER M3 ;
        RECT  117.18 64.763 117.198 64.8 ;
    END
  END y[193]
  PIN y[194]
    DIRECTION OUTPUT ;
    USE SIGNAL ;
    PORT
      LAYER M3 ;
        RECT  117.252 64.763 117.27 64.8 ;
    END
  END y[194]
  PIN y[195]
    DIRECTION OUTPUT ;
    USE SIGNAL ;
    PORT
      LAYER M3 ;
        RECT  117.324 64.763 117.342 64.8 ;
    END
  END y[195]
  PIN y[196]
    DIRECTION OUTPUT ;
    USE SIGNAL ;
    PORT
      LAYER M3 ;
        RECT  117.396 64.763 117.414 64.8 ;
    END
  END y[196]
  PIN y[197]
    DIRECTION OUTPUT ;
    USE SIGNAL ;
    PORT
      LAYER M3 ;
        RECT  117.468 64.763 117.486 64.8 ;
    END
  END y[197]
  PIN y[198]
    DIRECTION OUTPUT ;
    USE SIGNAL ;
    PORT
      LAYER M3 ;
        RECT  117.54 64.763 117.558 64.8 ;
    END
  END y[198]
  PIN y[199]
    DIRECTION OUTPUT ;
    USE SIGNAL ;
    PORT
      LAYER M3 ;
        RECT  117.612 64.763 117.63 64.8 ;
    END
  END y[199]
  PIN y[19]
    DIRECTION OUTPUT ;
    USE SIGNAL ;
    PORT
      LAYER M3 ;
        RECT  108.684 64.763 108.702 64.8 ;
    END
  END y[19]
  PIN y[1]
    DIRECTION OUTPUT ;
    USE SIGNAL ;
    PORT
      LAYER M3 ;
        RECT  107.388 64.763 107.406 64.8 ;
    END
  END y[1]
  PIN y[200]
    DIRECTION OUTPUT ;
    USE SIGNAL ;
    PORT
      LAYER M3 ;
        RECT  117.684 64.763 117.702 64.8 ;
    END
  END y[200]
  PIN y[201]
    DIRECTION OUTPUT ;
    USE SIGNAL ;
    PORT
      LAYER M3 ;
        RECT  117.756 64.763 117.774 64.8 ;
    END
  END y[201]
  PIN y[202]
    DIRECTION OUTPUT ;
    USE SIGNAL ;
    PORT
      LAYER M3 ;
        RECT  117.828 64.763 117.846 64.8 ;
    END
  END y[202]
  PIN y[203]
    DIRECTION OUTPUT ;
    USE SIGNAL ;
    PORT
      LAYER M3 ;
        RECT  117.9 64.763 117.918 64.8 ;
    END
  END y[203]
  PIN y[204]
    DIRECTION OUTPUT ;
    USE SIGNAL ;
    PORT
      LAYER M3 ;
        RECT  117.972 64.763 117.99 64.8 ;
    END
  END y[204]
  PIN y[205]
    DIRECTION OUTPUT ;
    USE SIGNAL ;
    PORT
      LAYER M3 ;
        RECT  118.044 64.763 118.062 64.8 ;
    END
  END y[205]
  PIN y[206]
    DIRECTION OUTPUT ;
    USE SIGNAL ;
    PORT
      LAYER M3 ;
        RECT  118.116 64.763 118.134 64.8 ;
    END
  END y[206]
  PIN y[207]
    DIRECTION OUTPUT ;
    USE SIGNAL ;
    PORT
      LAYER M3 ;
        RECT  118.188 64.763 118.206 64.8 ;
    END
  END y[207]
  PIN y[208]
    DIRECTION OUTPUT ;
    USE SIGNAL ;
    PORT
      LAYER M3 ;
        RECT  118.26 64.763 118.278 64.8 ;
    END
  END y[208]
  PIN y[209]
    DIRECTION OUTPUT ;
    USE SIGNAL ;
    PORT
      LAYER M3 ;
        RECT  118.332 64.763 118.35 64.8 ;
    END
  END y[209]
  PIN y[20]
    DIRECTION OUTPUT ;
    USE SIGNAL ;
    PORT
      LAYER M3 ;
        RECT  130.644 64.763 130.662 64.8 ;
    END
  END y[20]
  PIN y[210]
    DIRECTION OUTPUT ;
    USE SIGNAL ;
    PORT
      LAYER M3 ;
        RECT  118.404 64.763 118.422 64.8 ;
    END
  END y[210]
  PIN y[211]
    DIRECTION OUTPUT ;
    USE SIGNAL ;
    PORT
      LAYER M3 ;
        RECT  118.476 64.763 118.494 64.8 ;
    END
  END y[211]
  PIN y[212]
    DIRECTION OUTPUT ;
    USE SIGNAL ;
    PORT
      LAYER M3 ;
        RECT  97.236 64.763 97.254 64.8 ;
    END
  END y[212]
  PIN y[213]
    DIRECTION OUTPUT ;
    USE SIGNAL ;
    PORT
      LAYER M3 ;
        RECT  97.308 64.763 97.326 64.8 ;
    END
  END y[213]
  PIN y[214]
    DIRECTION OUTPUT ;
    USE SIGNAL ;
    PORT
      LAYER M3 ;
        RECT  97.38 64.763 97.398 64.8 ;
    END
  END y[214]
  PIN y[215]
    DIRECTION OUTPUT ;
    USE SIGNAL ;
    PORT
      LAYER M3 ;
        RECT  97.452 64.763 97.47 64.8 ;
    END
  END y[215]
  PIN y[216]
    DIRECTION OUTPUT ;
    USE SIGNAL ;
    PORT
      LAYER M3 ;
        RECT  97.524 64.763 97.542 64.8 ;
    END
  END y[216]
  PIN y[217]
    DIRECTION OUTPUT ;
    USE SIGNAL ;
    PORT
      LAYER M3 ;
        RECT  97.596 64.763 97.614 64.8 ;
    END
  END y[217]
  PIN y[218]
    DIRECTION OUTPUT ;
    USE SIGNAL ;
    PORT
      LAYER M3 ;
        RECT  97.668 64.763 97.686 64.8 ;
    END
  END y[218]
  PIN y[219]
    DIRECTION OUTPUT ;
    USE SIGNAL ;
    PORT
      LAYER M3 ;
        RECT  97.74 64.763 97.758 64.8 ;
    END
  END y[219]
  PIN y[21]
    DIRECTION OUTPUT ;
    USE SIGNAL ;
    PORT
      LAYER M3 ;
        RECT  130.716 64.763 130.734 64.8 ;
    END
  END y[21]
  PIN y[220]
    DIRECTION OUTPUT ;
    USE SIGNAL ;
    PORT
      LAYER M3 ;
        RECT  97.812 64.763 97.83 64.8 ;
    END
  END y[220]
  PIN y[221]
    DIRECTION OUTPUT ;
    USE SIGNAL ;
    PORT
      LAYER M3 ;
        RECT  97.884 64.763 97.902 64.8 ;
    END
  END y[221]
  PIN y[222]
    DIRECTION OUTPUT ;
    USE SIGNAL ;
    PORT
      LAYER M3 ;
        RECT  97.956 64.763 97.974 64.8 ;
    END
  END y[222]
  PIN y[223]
    DIRECTION OUTPUT ;
    USE SIGNAL ;
    PORT
      LAYER M3 ;
        RECT  98.028 64.763 98.046 64.8 ;
    END
  END y[223]
  PIN y[224]
    DIRECTION OUTPUT ;
    USE SIGNAL ;
    PORT
      LAYER M3 ;
        RECT  98.1 64.763 98.118 64.8 ;
    END
  END y[224]
  PIN y[225]
    DIRECTION OUTPUT ;
    USE SIGNAL ;
    PORT
      LAYER M3 ;
        RECT  98.172 64.763 98.19 64.8 ;
    END
  END y[225]
  PIN y[226]
    DIRECTION OUTPUT ;
    USE SIGNAL ;
    PORT
      LAYER M3 ;
        RECT  98.244 64.763 98.262 64.8 ;
    END
  END y[226]
  PIN y[227]
    DIRECTION OUTPUT ;
    USE SIGNAL ;
    PORT
      LAYER M3 ;
        RECT  98.316 64.763 98.334 64.8 ;
    END
  END y[227]
  PIN y[228]
    DIRECTION OUTPUT ;
    USE SIGNAL ;
    PORT
      LAYER M3 ;
        RECT  98.388 64.763 98.406 64.8 ;
    END
  END y[228]
  PIN y[229]
    DIRECTION OUTPUT ;
    USE SIGNAL ;
    PORT
      LAYER M3 ;
        RECT  98.46 64.763 98.478 64.8 ;
    END
  END y[229]
  PIN y[22]
    DIRECTION OUTPUT ;
    USE SIGNAL ;
    PORT
      LAYER M3 ;
        RECT  130.788 64.763 130.806 64.8 ;
    END
  END y[22]
  PIN y[230]
    DIRECTION OUTPUT ;
    USE SIGNAL ;
    PORT
      LAYER M3 ;
        RECT  98.532 64.763 98.55 64.8 ;
    END
  END y[230]
  PIN y[231]
    DIRECTION OUTPUT ;
    USE SIGNAL ;
    PORT
      LAYER M3 ;
        RECT  98.604 64.763 98.622 64.8 ;
    END
  END y[231]
  PIN y[232]
    DIRECTION OUTPUT ;
    USE SIGNAL ;
    PORT
      LAYER M3 ;
        RECT  98.676 64.763 98.694 64.8 ;
    END
  END y[232]
  PIN y[233]
    DIRECTION OUTPUT ;
    USE SIGNAL ;
    PORT
      LAYER M3 ;
        RECT  98.748 64.763 98.766 64.8 ;
    END
  END y[233]
  PIN y[234]
    DIRECTION OUTPUT ;
    USE SIGNAL ;
    PORT
      LAYER M3 ;
        RECT  98.82 64.763 98.838 64.8 ;
    END
  END y[234]
  PIN y[235]
    DIRECTION OUTPUT ;
    USE SIGNAL ;
    PORT
      LAYER M3 ;
        RECT  98.892 64.763 98.91 64.8 ;
    END
  END y[235]
  PIN y[236]
    DIRECTION OUTPUT ;
    USE SIGNAL ;
    PORT
      LAYER M3 ;
        RECT  98.964 64.763 98.982 64.8 ;
    END
  END y[236]
  PIN y[237]
    DIRECTION OUTPUT ;
    USE SIGNAL ;
    PORT
      LAYER M3 ;
        RECT  99.036 64.763 99.054 64.8 ;
    END
  END y[237]
  PIN y[238]
    DIRECTION OUTPUT ;
    USE SIGNAL ;
    PORT
      LAYER M3 ;
        RECT  99.108 64.763 99.126 64.8 ;
    END
  END y[238]
  PIN y[239]
    DIRECTION OUTPUT ;
    USE SIGNAL ;
    PORT
      LAYER M3 ;
        RECT  99.18 64.763 99.198 64.8 ;
    END
  END y[239]
  PIN y[23]
    DIRECTION OUTPUT ;
    USE SIGNAL ;
    PORT
      LAYER M3 ;
        RECT  130.86 64.763 130.878 64.8 ;
    END
  END y[23]
  PIN y[240]
    DIRECTION OUTPUT ;
    USE SIGNAL ;
    PORT
      LAYER M3 ;
        RECT  99.252 64.763 99.27 64.8 ;
    END
  END y[240]
  PIN y[241]
    DIRECTION OUTPUT ;
    USE SIGNAL ;
    PORT
      LAYER M3 ;
        RECT  99.324 64.763 99.342 64.8 ;
    END
  END y[241]
  PIN y[242]
    DIRECTION OUTPUT ;
    USE SIGNAL ;
    PORT
      LAYER M3 ;
        RECT  99.396 64.763 99.414 64.8 ;
    END
  END y[242]
  PIN y[243]
    DIRECTION OUTPUT ;
    USE SIGNAL ;
    PORT
      LAYER M3 ;
        RECT  99.468 64.763 99.486 64.8 ;
    END
  END y[243]
  PIN y[244]
    DIRECTION OUTPUT ;
    USE SIGNAL ;
    PORT
      LAYER M5 ;
        RECT  106.896 64.716 106.92 64.8 ;
    END
  END y[244]
  PIN y[245]
    DIRECTION OUTPUT ;
    USE SIGNAL ;
    PORT
      LAYER M5 ;
        RECT  106.992 64.716 107.016 64.8 ;
    END
  END y[245]
  PIN y[246]
    DIRECTION OUTPUT ;
    USE SIGNAL ;
    PORT
      LAYER M5 ;
        RECT  107.088 64.716 107.112 64.8 ;
    END
  END y[246]
  PIN y[247]
    DIRECTION OUTPUT ;
    USE SIGNAL ;
    PORT
      LAYER M5 ;
        RECT  107.184 64.716 107.208 64.8 ;
    END
  END y[247]
  PIN y[248]
    DIRECTION OUTPUT ;
    USE SIGNAL ;
    PORT
      LAYER M5 ;
        RECT  107.28 64.716 107.304 64.8 ;
    END
  END y[248]
  PIN y[249]
    DIRECTION OUTPUT ;
    USE SIGNAL ;
    PORT
      LAYER M5 ;
        RECT  107.376 64.716 107.4 64.8 ;
    END
  END y[249]
  PIN y[24]
    DIRECTION OUTPUT ;
    USE SIGNAL ;
    PORT
      LAYER M3 ;
        RECT  130.932 64.763 130.95 64.8 ;
    END
  END y[24]
  PIN y[250]
    DIRECTION OUTPUT ;
    USE SIGNAL ;
    PORT
      LAYER M5 ;
        RECT  107.472 64.716 107.496 64.8 ;
    END
  END y[250]
  PIN y[251]
    DIRECTION OUTPUT ;
    USE SIGNAL ;
    PORT
      LAYER M5 ;
        RECT  107.568 64.716 107.592 64.8 ;
    END
  END y[251]
  PIN y[252]
    DIRECTION OUTPUT ;
    USE SIGNAL ;
    PORT
      LAYER M5 ;
        RECT  107.664 64.716 107.688 64.8 ;
    END
  END y[252]
  PIN y[253]
    DIRECTION OUTPUT ;
    USE SIGNAL ;
    PORT
      LAYER M5 ;
        RECT  107.76 64.716 107.784 64.8 ;
    END
  END y[253]
  PIN y[254]
    DIRECTION OUTPUT ;
    USE SIGNAL ;
    PORT
      LAYER M5 ;
        RECT  107.856 64.716 107.88 64.8 ;
    END
  END y[254]
  PIN y[255]
    DIRECTION OUTPUT ;
    USE SIGNAL ;
    PORT
      LAYER M5 ;
        RECT  107.952 64.716 107.976 64.8 ;
    END
  END y[255]
  PIN y[256]
    DIRECTION OUTPUT ;
    USE SIGNAL ;
    PORT
      LAYER M5 ;
        RECT  108.048 64.716 108.072 64.8 ;
    END
  END y[256]
  PIN y[257]
    DIRECTION OUTPUT ;
    USE SIGNAL ;
    PORT
      LAYER M5 ;
        RECT  108.144 64.716 108.168 64.8 ;
    END
  END y[257]
  PIN y[258]
    DIRECTION OUTPUT ;
    USE SIGNAL ;
    PORT
      LAYER M5 ;
        RECT  108.24 64.716 108.264 64.8 ;
    END
  END y[258]
  PIN y[259]
    DIRECTION OUTPUT ;
    USE SIGNAL ;
    PORT
      LAYER M5 ;
        RECT  108.336 64.716 108.36 64.8 ;
    END
  END y[259]
  PIN y[25]
    DIRECTION OUTPUT ;
    USE SIGNAL ;
    PORT
      LAYER M3 ;
        RECT  131.004 64.763 131.022 64.8 ;
    END
  END y[25]
  PIN y[260]
    DIRECTION OUTPUT ;
    USE SIGNAL ;
    PORT
      LAYER M5 ;
        RECT  108.432 64.716 108.456 64.8 ;
    END
  END y[260]
  PIN y[261]
    DIRECTION OUTPUT ;
    USE SIGNAL ;
    PORT
      LAYER M5 ;
        RECT  108.528 64.716 108.552 64.8 ;
    END
  END y[261]
  PIN y[262]
    DIRECTION OUTPUT ;
    USE SIGNAL ;
    PORT
      LAYER M5 ;
        RECT  108.624 64.716 108.648 64.8 ;
    END
  END y[262]
  PIN y[263]
    DIRECTION OUTPUT ;
    USE SIGNAL ;
    PORT
      LAYER M5 ;
        RECT  108.72 64.716 108.744 64.8 ;
    END
  END y[263]
  PIN y[264]
    DIRECTION OUTPUT ;
    USE SIGNAL ;
    PORT
      LAYER M5 ;
        RECT  108.816 64.716 108.84 64.8 ;
    END
  END y[264]
  PIN y[265]
    DIRECTION OUTPUT ;
    USE SIGNAL ;
    PORT
      LAYER M5 ;
        RECT  108.912 64.716 108.936 64.8 ;
    END
  END y[265]
  PIN y[266]
    DIRECTION OUTPUT ;
    USE SIGNAL ;
    PORT
      LAYER M5 ;
        RECT  109.008 64.716 109.032 64.8 ;
    END
  END y[266]
  PIN y[267]
    DIRECTION OUTPUT ;
    USE SIGNAL ;
    PORT
      LAYER M5 ;
        RECT  109.104 64.716 109.128 64.8 ;
    END
  END y[267]
  PIN y[268]
    DIRECTION OUTPUT ;
    USE SIGNAL ;
    PORT
      LAYER M5 ;
        RECT  109.2 64.716 109.224 64.8 ;
    END
  END y[268]
  PIN y[269]
    DIRECTION OUTPUT ;
    USE SIGNAL ;
    PORT
      LAYER M5 ;
        RECT  109.296 64.716 109.32 64.8 ;
    END
  END y[269]
  PIN y[26]
    DIRECTION OUTPUT ;
    USE SIGNAL ;
    PORT
      LAYER M3 ;
        RECT  131.076 64.763 131.094 64.8 ;
    END
  END y[26]
  PIN y[270]
    DIRECTION OUTPUT ;
    USE SIGNAL ;
    PORT
      LAYER M5 ;
        RECT  109.392 64.716 109.416 64.8 ;
    END
  END y[270]
  PIN y[271]
    DIRECTION OUTPUT ;
    USE SIGNAL ;
    PORT
      LAYER M5 ;
        RECT  109.488 64.716 109.512 64.8 ;
    END
  END y[271]
  PIN y[272]
    DIRECTION OUTPUT ;
    USE SIGNAL ;
    PORT
      LAYER M5 ;
        RECT  109.584 64.716 109.608 64.8 ;
    END
  END y[272]
  PIN y[273]
    DIRECTION OUTPUT ;
    USE SIGNAL ;
    PORT
      LAYER M5 ;
        RECT  109.68 64.716 109.704 64.8 ;
    END
  END y[273]
  PIN y[274]
    DIRECTION OUTPUT ;
    USE SIGNAL ;
    PORT
      LAYER M5 ;
        RECT  109.776 64.716 109.8 64.8 ;
    END
  END y[274]
  PIN y[275]
    DIRECTION OUTPUT ;
    USE SIGNAL ;
    PORT
      LAYER M5 ;
        RECT  109.872 64.716 109.896 64.8 ;
    END
  END y[275]
  PIN y[276]
    DIRECTION OUTPUT ;
    USE SIGNAL ;
    PORT
      LAYER M3 ;
        RECT  118.548 64.763 118.566 64.8 ;
    END
  END y[276]
  PIN y[277]
    DIRECTION OUTPUT ;
    USE SIGNAL ;
    PORT
      LAYER M3 ;
        RECT  118.62 64.763 118.638 64.8 ;
    END
  END y[277]
  PIN y[278]
    DIRECTION OUTPUT ;
    USE SIGNAL ;
    PORT
      LAYER M3 ;
        RECT  118.692 64.763 118.71 64.8 ;
    END
  END y[278]
  PIN y[279]
    DIRECTION OUTPUT ;
    USE SIGNAL ;
    PORT
      LAYER M3 ;
        RECT  118.764 64.763 118.782 64.8 ;
    END
  END y[279]
  PIN y[27]
    DIRECTION OUTPUT ;
    USE SIGNAL ;
    PORT
      LAYER M3 ;
        RECT  131.148 64.763 131.166 64.8 ;
    END
  END y[27]
  PIN y[280]
    DIRECTION OUTPUT ;
    USE SIGNAL ;
    PORT
      LAYER M3 ;
        RECT  118.836 64.763 118.854 64.8 ;
    END
  END y[280]
  PIN y[281]
    DIRECTION OUTPUT ;
    USE SIGNAL ;
    PORT
      LAYER M3 ;
        RECT  118.908 64.763 118.926 64.8 ;
    END
  END y[281]
  PIN y[282]
    DIRECTION OUTPUT ;
    USE SIGNAL ;
    PORT
      LAYER M3 ;
        RECT  118.98 64.763 118.998 64.8 ;
    END
  END y[282]
  PIN y[283]
    DIRECTION OUTPUT ;
    USE SIGNAL ;
    PORT
      LAYER M3 ;
        RECT  119.052 64.763 119.07 64.8 ;
    END
  END y[283]
  PIN y[284]
    DIRECTION OUTPUT ;
    USE SIGNAL ;
    PORT
      LAYER M3 ;
        RECT  119.124 64.763 119.142 64.8 ;
    END
  END y[284]
  PIN y[285]
    DIRECTION OUTPUT ;
    USE SIGNAL ;
    PORT
      LAYER M3 ;
        RECT  119.196 64.763 119.214 64.8 ;
    END
  END y[285]
  PIN y[286]
    DIRECTION OUTPUT ;
    USE SIGNAL ;
    PORT
      LAYER M3 ;
        RECT  119.268 64.763 119.286 64.8 ;
    END
  END y[286]
  PIN y[287]
    DIRECTION OUTPUT ;
    USE SIGNAL ;
    PORT
      LAYER M3 ;
        RECT  119.34 64.763 119.358 64.8 ;
    END
  END y[287]
  PIN y[288]
    DIRECTION OUTPUT ;
    USE SIGNAL ;
    PORT
      LAYER M3 ;
        RECT  119.412 64.763 119.43 64.8 ;
    END
  END y[288]
  PIN y[289]
    DIRECTION OUTPUT ;
    USE SIGNAL ;
    PORT
      LAYER M3 ;
        RECT  119.484 64.763 119.502 64.8 ;
    END
  END y[289]
  PIN y[28]
    DIRECTION OUTPUT ;
    USE SIGNAL ;
    PORT
      LAYER M3 ;
        RECT  131.22 64.763 131.238 64.8 ;
    END
  END y[28]
  PIN y[290]
    DIRECTION OUTPUT ;
    USE SIGNAL ;
    PORT
      LAYER M3 ;
        RECT  119.556 64.763 119.574 64.8 ;
    END
  END y[290]
  PIN y[291]
    DIRECTION OUTPUT ;
    USE SIGNAL ;
    PORT
      LAYER M3 ;
        RECT  119.628 64.763 119.646 64.8 ;
    END
  END y[291]
  PIN y[292]
    DIRECTION OUTPUT ;
    USE SIGNAL ;
    PORT
      LAYER M3 ;
        RECT  119.7 64.763 119.718 64.8 ;
    END
  END y[292]
  PIN y[293]
    DIRECTION OUTPUT ;
    USE SIGNAL ;
    PORT
      LAYER M3 ;
        RECT  119.772 64.763 119.79 64.8 ;
    END
  END y[293]
  PIN y[294]
    DIRECTION OUTPUT ;
    USE SIGNAL ;
    PORT
      LAYER M3 ;
        RECT  119.844 64.763 119.862 64.8 ;
    END
  END y[294]
  PIN y[295]
    DIRECTION OUTPUT ;
    USE SIGNAL ;
    PORT
      LAYER M3 ;
        RECT  119.916 64.763 119.934 64.8 ;
    END
  END y[295]
  PIN y[296]
    DIRECTION OUTPUT ;
    USE SIGNAL ;
    PORT
      LAYER M3 ;
        RECT  119.988 64.763 120.006 64.8 ;
    END
  END y[296]
  PIN y[297]
    DIRECTION OUTPUT ;
    USE SIGNAL ;
    PORT
      LAYER M3 ;
        RECT  120.06 64.763 120.078 64.8 ;
    END
  END y[297]
  PIN y[298]
    DIRECTION OUTPUT ;
    USE SIGNAL ;
    PORT
      LAYER M3 ;
        RECT  120.132 64.763 120.15 64.8 ;
    END
  END y[298]
  PIN y[299]
    DIRECTION OUTPUT ;
    USE SIGNAL ;
    PORT
      LAYER M3 ;
        RECT  120.204 64.763 120.222 64.8 ;
    END
  END y[299]
  PIN y[29]
    DIRECTION OUTPUT ;
    USE SIGNAL ;
    PORT
      LAYER M3 ;
        RECT  131.292 64.763 131.31 64.8 ;
    END
  END y[29]
  PIN y[2]
    DIRECTION OUTPUT ;
    USE SIGNAL ;
    PORT
      LAYER M3 ;
        RECT  107.46 64.763 107.478 64.8 ;
    END
  END y[2]
  PIN y[300]
    DIRECTION OUTPUT ;
    USE SIGNAL ;
    PORT
      LAYER M3 ;
        RECT  120.276 64.763 120.294 64.8 ;
    END
  END y[300]
  PIN y[301]
    DIRECTION OUTPUT ;
    USE SIGNAL ;
    PORT
      LAYER M3 ;
        RECT  120.348 64.763 120.366 64.8 ;
    END
  END y[301]
  PIN y[302]
    DIRECTION OUTPUT ;
    USE SIGNAL ;
    PORT
      LAYER M3 ;
        RECT  120.42 64.763 120.438 64.8 ;
    END
  END y[302]
  PIN y[303]
    DIRECTION OUTPUT ;
    USE SIGNAL ;
    PORT
      LAYER M3 ;
        RECT  120.492 64.763 120.51 64.8 ;
    END
  END y[303]
  PIN y[304]
    DIRECTION OUTPUT ;
    USE SIGNAL ;
    PORT
      LAYER M3 ;
        RECT  120.564 64.763 120.582 64.8 ;
    END
  END y[304]
  PIN y[305]
    DIRECTION OUTPUT ;
    USE SIGNAL ;
    PORT
      LAYER M3 ;
        RECT  120.636 64.763 120.654 64.8 ;
    END
  END y[305]
  PIN y[306]
    DIRECTION OUTPUT ;
    USE SIGNAL ;
    PORT
      LAYER M3 ;
        RECT  120.708 64.763 120.726 64.8 ;
    END
  END y[306]
  PIN y[307]
    DIRECTION OUTPUT ;
    USE SIGNAL ;
    PORT
      LAYER M3 ;
        RECT  120.78 64.763 120.798 64.8 ;
    END
  END y[307]
  PIN y[308]
    DIRECTION OUTPUT ;
    USE SIGNAL ;
    PORT
      LAYER M3 ;
        RECT  104.148 64.763 104.166 64.8 ;
    END
  END y[308]
  PIN y[309]
    DIRECTION OUTPUT ;
    USE SIGNAL ;
    PORT
      LAYER M3 ;
        RECT  104.22 64.763 104.238 64.8 ;
    END
  END y[309]
  PIN y[30]
    DIRECTION OUTPUT ;
    USE SIGNAL ;
    PORT
      LAYER M3 ;
        RECT  131.364 64.763 131.382 64.8 ;
    END
  END y[30]
  PIN y[310]
    DIRECTION OUTPUT ;
    USE SIGNAL ;
    PORT
      LAYER M3 ;
        RECT  104.292 64.763 104.31 64.8 ;
    END
  END y[310]
  PIN y[311]
    DIRECTION OUTPUT ;
    USE SIGNAL ;
    PORT
      LAYER M3 ;
        RECT  104.364 64.763 104.382 64.8 ;
    END
  END y[311]
  PIN y[312]
    DIRECTION OUTPUT ;
    USE SIGNAL ;
    PORT
      LAYER M3 ;
        RECT  104.436 64.763 104.454 64.8 ;
    END
  END y[312]
  PIN y[313]
    DIRECTION OUTPUT ;
    USE SIGNAL ;
    PORT
      LAYER M3 ;
        RECT  104.508 64.763 104.526 64.8 ;
    END
  END y[313]
  PIN y[314]
    DIRECTION OUTPUT ;
    USE SIGNAL ;
    PORT
      LAYER M3 ;
        RECT  104.58 64.763 104.598 64.8 ;
    END
  END y[314]
  PIN y[315]
    DIRECTION OUTPUT ;
    USE SIGNAL ;
    PORT
      LAYER M3 ;
        RECT  104.652 64.763 104.67 64.8 ;
    END
  END y[315]
  PIN y[316]
    DIRECTION OUTPUT ;
    USE SIGNAL ;
    PORT
      LAYER M3 ;
        RECT  104.724 64.763 104.742 64.8 ;
    END
  END y[316]
  PIN y[317]
    DIRECTION OUTPUT ;
    USE SIGNAL ;
    PORT
      LAYER M3 ;
        RECT  104.796 64.763 104.814 64.8 ;
    END
  END y[317]
  PIN y[318]
    DIRECTION OUTPUT ;
    USE SIGNAL ;
    PORT
      LAYER M3 ;
        RECT  104.868 64.763 104.886 64.8 ;
    END
  END y[318]
  PIN y[319]
    DIRECTION OUTPUT ;
    USE SIGNAL ;
    PORT
      LAYER M3 ;
        RECT  104.94 64.763 104.958 64.8 ;
    END
  END y[319]
  PIN y[31]
    DIRECTION OUTPUT ;
    USE SIGNAL ;
    PORT
      LAYER M3 ;
        RECT  131.436 64.763 131.454 64.8 ;
    END
  END y[31]
  PIN y[320]
    DIRECTION OUTPUT ;
    USE SIGNAL ;
    PORT
      LAYER M3 ;
        RECT  105.012 64.763 105.03 64.8 ;
    END
  END y[320]
  PIN y[321]
    DIRECTION OUTPUT ;
    USE SIGNAL ;
    PORT
      LAYER M3 ;
        RECT  105.084 64.763 105.102 64.8 ;
    END
  END y[321]
  PIN y[322]
    DIRECTION OUTPUT ;
    USE SIGNAL ;
    PORT
      LAYER M3 ;
        RECT  105.156 64.763 105.174 64.8 ;
    END
  END y[322]
  PIN y[323]
    DIRECTION OUTPUT ;
    USE SIGNAL ;
    PORT
      LAYER M3 ;
        RECT  105.228 64.763 105.246 64.8 ;
    END
  END y[323]
  PIN y[324]
    DIRECTION OUTPUT ;
    USE SIGNAL ;
    PORT
      LAYER M3 ;
        RECT  105.3 64.763 105.318 64.8 ;
    END
  END y[324]
  PIN y[325]
    DIRECTION OUTPUT ;
    USE SIGNAL ;
    PORT
      LAYER M3 ;
        RECT  105.372 64.763 105.39 64.8 ;
    END
  END y[325]
  PIN y[326]
    DIRECTION OUTPUT ;
    USE SIGNAL ;
    PORT
      LAYER M3 ;
        RECT  105.444 64.763 105.462 64.8 ;
    END
  END y[326]
  PIN y[327]
    DIRECTION OUTPUT ;
    USE SIGNAL ;
    PORT
      LAYER M3 ;
        RECT  105.516 64.763 105.534 64.8 ;
    END
  END y[327]
  PIN y[328]
    DIRECTION OUTPUT ;
    USE SIGNAL ;
    PORT
      LAYER M3 ;
        RECT  105.588 64.763 105.606 64.8 ;
    END
  END y[328]
  PIN y[329]
    DIRECTION OUTPUT ;
    USE SIGNAL ;
    PORT
      LAYER M3 ;
        RECT  105.66 64.763 105.678 64.8 ;
    END
  END y[329]
  PIN y[32]
    DIRECTION OUTPUT ;
    USE SIGNAL ;
    PORT
      LAYER M3 ;
        RECT  131.508 64.763 131.526 64.8 ;
    END
  END y[32]
  PIN y[330]
    DIRECTION OUTPUT ;
    USE SIGNAL ;
    PORT
      LAYER M3 ;
        RECT  105.732 64.763 105.75 64.8 ;
    END
  END y[330]
  PIN y[331]
    DIRECTION OUTPUT ;
    USE SIGNAL ;
    PORT
      LAYER M3 ;
        RECT  105.804 64.763 105.822 64.8 ;
    END
  END y[331]
  PIN y[332]
    DIRECTION OUTPUT ;
    USE SIGNAL ;
    PORT
      LAYER M3 ;
        RECT  105.876 64.763 105.894 64.8 ;
    END
  END y[332]
  PIN y[333]
    DIRECTION OUTPUT ;
    USE SIGNAL ;
    PORT
      LAYER M3 ;
        RECT  105.948 64.763 105.966 64.8 ;
    END
  END y[333]
  PIN y[334]
    DIRECTION OUTPUT ;
    USE SIGNAL ;
    PORT
      LAYER M3 ;
        RECT  106.02 64.763 106.038 64.8 ;
    END
  END y[334]
  PIN y[335]
    DIRECTION OUTPUT ;
    USE SIGNAL ;
    PORT
      LAYER M3 ;
        RECT  106.092 64.763 106.11 64.8 ;
    END
  END y[335]
  PIN y[336]
    DIRECTION OUTPUT ;
    USE SIGNAL ;
    PORT
      LAYER M3 ;
        RECT  106.164 64.763 106.182 64.8 ;
    END
  END y[336]
  PIN y[337]
    DIRECTION OUTPUT ;
    USE SIGNAL ;
    PORT
      LAYER M3 ;
        RECT  106.236 64.763 106.254 64.8 ;
    END
  END y[337]
  PIN y[338]
    DIRECTION OUTPUT ;
    USE SIGNAL ;
    PORT
      LAYER M3 ;
        RECT  106.308 64.763 106.326 64.8 ;
    END
  END y[338]
  PIN y[339]
    DIRECTION OUTPUT ;
    USE SIGNAL ;
    PORT
      LAYER M3 ;
        RECT  106.38 64.763 106.398 64.8 ;
    END
  END y[339]
  PIN y[33]
    DIRECTION OUTPUT ;
    USE SIGNAL ;
    PORT
      LAYER M3 ;
        RECT  131.58 64.763 131.598 64.8 ;
    END
  END y[33]
  PIN y[340]
    DIRECTION OUTPUT ;
    USE SIGNAL ;
    PORT
      LAYER M5 ;
        RECT  113.04 64.716 113.064 64.8 ;
    END
  END y[340]
  PIN y[341]
    DIRECTION OUTPUT ;
    USE SIGNAL ;
    PORT
      LAYER M5 ;
        RECT  113.136 64.716 113.16 64.8 ;
    END
  END y[341]
  PIN y[342]
    DIRECTION OUTPUT ;
    USE SIGNAL ;
    PORT
      LAYER M5 ;
        RECT  113.232 64.716 113.256 64.8 ;
    END
  END y[342]
  PIN y[343]
    DIRECTION OUTPUT ;
    USE SIGNAL ;
    PORT
      LAYER M5 ;
        RECT  113.328 64.716 113.352 64.8 ;
    END
  END y[343]
  PIN y[344]
    DIRECTION OUTPUT ;
    USE SIGNAL ;
    PORT
      LAYER M5 ;
        RECT  113.424 64.716 113.448 64.8 ;
    END
  END y[344]
  PIN y[345]
    DIRECTION OUTPUT ;
    USE SIGNAL ;
    PORT
      LAYER M5 ;
        RECT  113.52 64.716 113.544 64.8 ;
    END
  END y[345]
  PIN y[346]
    DIRECTION OUTPUT ;
    USE SIGNAL ;
    PORT
      LAYER M5 ;
        RECT  113.616 64.716 113.64 64.8 ;
    END
  END y[346]
  PIN y[347]
    DIRECTION OUTPUT ;
    USE SIGNAL ;
    PORT
      LAYER M5 ;
        RECT  113.712 64.716 113.736 64.8 ;
    END
  END y[347]
  PIN y[348]
    DIRECTION OUTPUT ;
    USE SIGNAL ;
    PORT
      LAYER M5 ;
        RECT  113.808 64.716 113.832 64.8 ;
    END
  END y[348]
  PIN y[349]
    DIRECTION OUTPUT ;
    USE SIGNAL ;
    PORT
      LAYER M5 ;
        RECT  113.904 64.716 113.928 64.8 ;
    END
  END y[349]
  PIN y[34]
    DIRECTION OUTPUT ;
    USE SIGNAL ;
    PORT
      LAYER M3 ;
        RECT  131.652 64.763 131.67 64.8 ;
    END
  END y[34]
  PIN y[350]
    DIRECTION OUTPUT ;
    USE SIGNAL ;
    PORT
      LAYER M5 ;
        RECT  114 64.716 114.024 64.8 ;
    END
  END y[350]
  PIN y[351]
    DIRECTION OUTPUT ;
    USE SIGNAL ;
    PORT
      LAYER M5 ;
        RECT  114.096 64.716 114.12 64.8 ;
    END
  END y[351]
  PIN y[352]
    DIRECTION OUTPUT ;
    USE SIGNAL ;
    PORT
      LAYER M5 ;
        RECT  114.192 64.716 114.216 64.8 ;
    END
  END y[352]
  PIN y[353]
    DIRECTION OUTPUT ;
    USE SIGNAL ;
    PORT
      LAYER M5 ;
        RECT  114.288 64.716 114.312 64.8 ;
    END
  END y[353]
  PIN y[354]
    DIRECTION OUTPUT ;
    USE SIGNAL ;
    PORT
      LAYER M5 ;
        RECT  114.384 64.716 114.408 64.8 ;
    END
  END y[354]
  PIN y[355]
    DIRECTION OUTPUT ;
    USE SIGNAL ;
    PORT
      LAYER M5 ;
        RECT  114.48 64.716 114.504 64.8 ;
    END
  END y[355]
  PIN y[356]
    DIRECTION OUTPUT ;
    USE SIGNAL ;
    PORT
      LAYER M5 ;
        RECT  114.576 64.716 114.6 64.8 ;
    END
  END y[356]
  PIN y[357]
    DIRECTION OUTPUT ;
    USE SIGNAL ;
    PORT
      LAYER M5 ;
        RECT  114.672 64.716 114.696 64.8 ;
    END
  END y[357]
  PIN y[358]
    DIRECTION OUTPUT ;
    USE SIGNAL ;
    PORT
      LAYER M5 ;
        RECT  114.768 64.716 114.792 64.8 ;
    END
  END y[358]
  PIN y[359]
    DIRECTION OUTPUT ;
    USE SIGNAL ;
    PORT
      LAYER M5 ;
        RECT  114.864 64.716 114.888 64.8 ;
    END
  END y[359]
  PIN y[35]
    DIRECTION OUTPUT ;
    USE SIGNAL ;
    PORT
      LAYER M3 ;
        RECT  131.724 64.763 131.742 64.8 ;
    END
  END y[35]
  PIN y[360]
    DIRECTION OUTPUT ;
    USE SIGNAL ;
    PORT
      LAYER M5 ;
        RECT  114.96 64.716 114.984 64.8 ;
    END
  END y[360]
  PIN y[361]
    DIRECTION OUTPUT ;
    USE SIGNAL ;
    PORT
      LAYER M5 ;
        RECT  115.056 64.716 115.08 64.8 ;
    END
  END y[361]
  PIN y[362]
    DIRECTION OUTPUT ;
    USE SIGNAL ;
    PORT
      LAYER M5 ;
        RECT  115.152 64.716 115.176 64.8 ;
    END
  END y[362]
  PIN y[363]
    DIRECTION OUTPUT ;
    USE SIGNAL ;
    PORT
      LAYER M5 ;
        RECT  115.248 64.716 115.272 64.8 ;
    END
  END y[363]
  PIN y[364]
    DIRECTION OUTPUT ;
    USE SIGNAL ;
    PORT
      LAYER M5 ;
        RECT  115.344 64.716 115.368 64.8 ;
    END
  END y[364]
  PIN y[365]
    DIRECTION OUTPUT ;
    USE SIGNAL ;
    PORT
      LAYER M5 ;
        RECT  115.44 64.716 115.464 64.8 ;
    END
  END y[365]
  PIN y[366]
    DIRECTION OUTPUT ;
    USE SIGNAL ;
    PORT
      LAYER M5 ;
        RECT  115.536 64.716 115.56 64.8 ;
    END
  END y[366]
  PIN y[367]
    DIRECTION OUTPUT ;
    USE SIGNAL ;
    PORT
      LAYER M5 ;
        RECT  115.632 64.716 115.656 64.8 ;
    END
  END y[367]
  PIN y[368]
    DIRECTION OUTPUT ;
    USE SIGNAL ;
    PORT
      LAYER M5 ;
        RECT  115.728 64.716 115.752 64.8 ;
    END
  END y[368]
  PIN y[369]
    DIRECTION OUTPUT ;
    USE SIGNAL ;
    PORT
      LAYER M5 ;
        RECT  115.824 64.716 115.848 64.8 ;
    END
  END y[369]
  PIN y[36]
    DIRECTION OUTPUT ;
    USE SIGNAL ;
    PORT
      LAYER M3 ;
        RECT  131.796 64.763 131.814 64.8 ;
    END
  END y[36]
  PIN y[370]
    DIRECTION OUTPUT ;
    USE SIGNAL ;
    PORT
      LAYER M5 ;
        RECT  115.92 64.716 115.944 64.8 ;
    END
  END y[370]
  PIN y[371]
    DIRECTION OUTPUT ;
    USE SIGNAL ;
    PORT
      LAYER M5 ;
        RECT  116.016 64.716 116.04 64.8 ;
    END
  END y[371]
  PIN y[372]
    DIRECTION OUTPUT ;
    USE SIGNAL ;
    PORT
      LAYER M3 ;
        RECT  111.636 64.763 111.654 64.8 ;
    END
  END y[372]
  PIN y[373]
    DIRECTION OUTPUT ;
    USE SIGNAL ;
    PORT
      LAYER M3 ;
        RECT  111.708 64.763 111.726 64.8 ;
    END
  END y[373]
  PIN y[374]
    DIRECTION OUTPUT ;
    USE SIGNAL ;
    PORT
      LAYER M3 ;
        RECT  111.78 64.763 111.798 64.8 ;
    END
  END y[374]
  PIN y[375]
    DIRECTION OUTPUT ;
    USE SIGNAL ;
    PORT
      LAYER M3 ;
        RECT  111.852 64.763 111.87 64.8 ;
    END
  END y[375]
  PIN y[376]
    DIRECTION OUTPUT ;
    USE SIGNAL ;
    PORT
      LAYER M3 ;
        RECT  111.924 64.763 111.942 64.8 ;
    END
  END y[376]
  PIN y[377]
    DIRECTION OUTPUT ;
    USE SIGNAL ;
    PORT
      LAYER M3 ;
        RECT  111.996 64.763 112.014 64.8 ;
    END
  END y[377]
  PIN y[378]
    DIRECTION OUTPUT ;
    USE SIGNAL ;
    PORT
      LAYER M3 ;
        RECT  112.068 64.763 112.086 64.8 ;
    END
  END y[378]
  PIN y[379]
    DIRECTION OUTPUT ;
    USE SIGNAL ;
    PORT
      LAYER M3 ;
        RECT  112.14 64.763 112.158 64.8 ;
    END
  END y[379]
  PIN y[37]
    DIRECTION OUTPUT ;
    USE SIGNAL ;
    PORT
      LAYER M3 ;
        RECT  131.868 64.763 131.886 64.8 ;
    END
  END y[37]
  PIN y[380]
    DIRECTION OUTPUT ;
    USE SIGNAL ;
    PORT
      LAYER M3 ;
        RECT  112.212 64.763 112.23 64.8 ;
    END
  END y[380]
  PIN y[381]
    DIRECTION OUTPUT ;
    USE SIGNAL ;
    PORT
      LAYER M3 ;
        RECT  112.284 64.763 112.302 64.8 ;
    END
  END y[381]
  PIN y[382]
    DIRECTION OUTPUT ;
    USE SIGNAL ;
    PORT
      LAYER M3 ;
        RECT  112.356 64.763 112.374 64.8 ;
    END
  END y[382]
  PIN y[383]
    DIRECTION OUTPUT ;
    USE SIGNAL ;
    PORT
      LAYER M3 ;
        RECT  112.428 64.763 112.446 64.8 ;
    END
  END y[383]
  PIN y[384]
    DIRECTION OUTPUT ;
    USE SIGNAL ;
    PORT
      LAYER M3 ;
        RECT  112.5 64.763 112.518 64.8 ;
    END
  END y[384]
  PIN y[385]
    DIRECTION OUTPUT ;
    USE SIGNAL ;
    PORT
      LAYER M3 ;
        RECT  112.572 64.763 112.59 64.8 ;
    END
  END y[385]
  PIN y[386]
    DIRECTION OUTPUT ;
    USE SIGNAL ;
    PORT
      LAYER M3 ;
        RECT  112.644 64.763 112.662 64.8 ;
    END
  END y[386]
  PIN y[387]
    DIRECTION OUTPUT ;
    USE SIGNAL ;
    PORT
      LAYER M3 ;
        RECT  112.716 64.763 112.734 64.8 ;
    END
  END y[387]
  PIN y[388]
    DIRECTION OUTPUT ;
    USE SIGNAL ;
    PORT
      LAYER M3 ;
        RECT  112.788 64.763 112.806 64.8 ;
    END
  END y[388]
  PIN y[389]
    DIRECTION OUTPUT ;
    USE SIGNAL ;
    PORT
      LAYER M3 ;
        RECT  112.86 64.763 112.878 64.8 ;
    END
  END y[389]
  PIN y[38]
    DIRECTION OUTPUT ;
    USE SIGNAL ;
    PORT
      LAYER M3 ;
        RECT  131.94 64.763 131.958 64.8 ;
    END
  END y[38]
  PIN y[390]
    DIRECTION OUTPUT ;
    USE SIGNAL ;
    PORT
      LAYER M3 ;
        RECT  112.932 64.763 112.95 64.8 ;
    END
  END y[390]
  PIN y[391]
    DIRECTION OUTPUT ;
    USE SIGNAL ;
    PORT
      LAYER M3 ;
        RECT  113.004 64.763 113.022 64.8 ;
    END
  END y[391]
  PIN y[392]
    DIRECTION OUTPUT ;
    USE SIGNAL ;
    PORT
      LAYER M3 ;
        RECT  113.076 64.763 113.094 64.8 ;
    END
  END y[392]
  PIN y[393]
    DIRECTION OUTPUT ;
    USE SIGNAL ;
    PORT
      LAYER M3 ;
        RECT  113.148 64.763 113.166 64.8 ;
    END
  END y[393]
  PIN y[394]
    DIRECTION OUTPUT ;
    USE SIGNAL ;
    PORT
      LAYER M3 ;
        RECT  113.22 64.763 113.238 64.8 ;
    END
  END y[394]
  PIN y[395]
    DIRECTION OUTPUT ;
    USE SIGNAL ;
    PORT
      LAYER M3 ;
        RECT  113.292 64.763 113.31 64.8 ;
    END
  END y[395]
  PIN y[396]
    DIRECTION OUTPUT ;
    USE SIGNAL ;
    PORT
      LAYER M3 ;
        RECT  113.364 64.763 113.382 64.8 ;
    END
  END y[396]
  PIN y[397]
    DIRECTION OUTPUT ;
    USE SIGNAL ;
    PORT
      LAYER M3 ;
        RECT  113.436 64.763 113.454 64.8 ;
    END
  END y[397]
  PIN y[398]
    DIRECTION OUTPUT ;
    USE SIGNAL ;
    PORT
      LAYER M3 ;
        RECT  113.508 64.763 113.526 64.8 ;
    END
  END y[398]
  PIN y[399]
    DIRECTION OUTPUT ;
    USE SIGNAL ;
    PORT
      LAYER M3 ;
        RECT  113.58 64.763 113.598 64.8 ;
    END
  END y[399]
  PIN y[39]
    DIRECTION OUTPUT ;
    USE SIGNAL ;
    PORT
      LAYER M3 ;
        RECT  132.012 64.763 132.03 64.8 ;
    END
  END y[39]
  PIN y[3]
    DIRECTION OUTPUT ;
    USE SIGNAL ;
    PORT
      LAYER M3 ;
        RECT  107.532 64.763 107.55 64.8 ;
    END
  END y[3]
  PIN y[400]
    DIRECTION OUTPUT ;
    USE SIGNAL ;
    PORT
      LAYER M3 ;
        RECT  113.652 64.763 113.67 64.8 ;
    END
  END y[400]
  PIN y[401]
    DIRECTION OUTPUT ;
    USE SIGNAL ;
    PORT
      LAYER M3 ;
        RECT  113.724 64.763 113.742 64.8 ;
    END
  END y[401]
  PIN y[402]
    DIRECTION OUTPUT ;
    USE SIGNAL ;
    PORT
      LAYER M3 ;
        RECT  113.796 64.763 113.814 64.8 ;
    END
  END y[402]
  PIN y[403]
    DIRECTION OUTPUT ;
    USE SIGNAL ;
    PORT
      LAYER M3 ;
        RECT  113.868 64.763 113.886 64.8 ;
    END
  END y[403]
  PIN y[404]
    DIRECTION OUTPUT ;
    USE SIGNAL ;
    PORT
      LAYER M3 ;
        RECT  128.34 64.763 128.358 64.8 ;
    END
  END y[404]
  PIN y[405]
    DIRECTION OUTPUT ;
    USE SIGNAL ;
    PORT
      LAYER M3 ;
        RECT  128.412 64.763 128.43 64.8 ;
    END
  END y[405]
  PIN y[406]
    DIRECTION OUTPUT ;
    USE SIGNAL ;
    PORT
      LAYER M3 ;
        RECT  128.484 64.763 128.502 64.8 ;
    END
  END y[406]
  PIN y[407]
    DIRECTION OUTPUT ;
    USE SIGNAL ;
    PORT
      LAYER M3 ;
        RECT  128.556 64.763 128.574 64.8 ;
    END
  END y[407]
  PIN y[408]
    DIRECTION OUTPUT ;
    USE SIGNAL ;
    PORT
      LAYER M3 ;
        RECT  128.628 64.763 128.646 64.8 ;
    END
  END y[408]
  PIN y[409]
    DIRECTION OUTPUT ;
    USE SIGNAL ;
    PORT
      LAYER M3 ;
        RECT  128.7 64.763 128.718 64.8 ;
    END
  END y[409]
  PIN y[40]
    DIRECTION OUTPUT ;
    USE SIGNAL ;
    PORT
      LAYER M3 ;
        RECT  132.084 64.763 132.102 64.8 ;
    END
  END y[40]
  PIN y[410]
    DIRECTION OUTPUT ;
    USE SIGNAL ;
    PORT
      LAYER M3 ;
        RECT  128.772 64.763 128.79 64.8 ;
    END
  END y[410]
  PIN y[411]
    DIRECTION OUTPUT ;
    USE SIGNAL ;
    PORT
      LAYER M3 ;
        RECT  128.844 64.763 128.862 64.8 ;
    END
  END y[411]
  PIN y[412]
    DIRECTION OUTPUT ;
    USE SIGNAL ;
    PORT
      LAYER M3 ;
        RECT  128.916 64.763 128.934 64.8 ;
    END
  END y[412]
  PIN y[413]
    DIRECTION OUTPUT ;
    USE SIGNAL ;
    PORT
      LAYER M3 ;
        RECT  128.988 64.763 129.006 64.8 ;
    END
  END y[413]
  PIN y[414]
    DIRECTION OUTPUT ;
    USE SIGNAL ;
    PORT
      LAYER M3 ;
        RECT  129.06 64.763 129.078 64.8 ;
    END
  END y[414]
  PIN y[415]
    DIRECTION OUTPUT ;
    USE SIGNAL ;
    PORT
      LAYER M3 ;
        RECT  129.132 64.763 129.15 64.8 ;
    END
  END y[415]
  PIN y[416]
    DIRECTION OUTPUT ;
    USE SIGNAL ;
    PORT
      LAYER M3 ;
        RECT  129.204 64.763 129.222 64.8 ;
    END
  END y[416]
  PIN y[417]
    DIRECTION OUTPUT ;
    USE SIGNAL ;
    PORT
      LAYER M3 ;
        RECT  129.276 64.763 129.294 64.8 ;
    END
  END y[417]
  PIN y[418]
    DIRECTION OUTPUT ;
    USE SIGNAL ;
    PORT
      LAYER M3 ;
        RECT  129.348 64.763 129.366 64.8 ;
    END
  END y[418]
  PIN y[419]
    DIRECTION OUTPUT ;
    USE SIGNAL ;
    PORT
      LAYER M3 ;
        RECT  129.42 64.763 129.438 64.8 ;
    END
  END y[419]
  PIN y[41]
    DIRECTION OUTPUT ;
    USE SIGNAL ;
    PORT
      LAYER M3 ;
        RECT  132.156 64.763 132.174 64.8 ;
    END
  END y[41]
  PIN y[420]
    DIRECTION OUTPUT ;
    USE SIGNAL ;
    PORT
      LAYER M3 ;
        RECT  129.492 64.763 129.51 64.8 ;
    END
  END y[420]
  PIN y[421]
    DIRECTION OUTPUT ;
    USE SIGNAL ;
    PORT
      LAYER M3 ;
        RECT  129.564 64.763 129.582 64.8 ;
    END
  END y[421]
  PIN y[422]
    DIRECTION OUTPUT ;
    USE SIGNAL ;
    PORT
      LAYER M3 ;
        RECT  129.636 64.763 129.654 64.8 ;
    END
  END y[422]
  PIN y[423]
    DIRECTION OUTPUT ;
    USE SIGNAL ;
    PORT
      LAYER M3 ;
        RECT  129.708 64.763 129.726 64.8 ;
    END
  END y[423]
  PIN y[424]
    DIRECTION OUTPUT ;
    USE SIGNAL ;
    PORT
      LAYER M3 ;
        RECT  129.78 64.763 129.798 64.8 ;
    END
  END y[424]
  PIN y[425]
    DIRECTION OUTPUT ;
    USE SIGNAL ;
    PORT
      LAYER M3 ;
        RECT  129.852 64.763 129.87 64.8 ;
    END
  END y[425]
  PIN y[426]
    DIRECTION OUTPUT ;
    USE SIGNAL ;
    PORT
      LAYER M3 ;
        RECT  129.924 64.763 129.942 64.8 ;
    END
  END y[426]
  PIN y[427]
    DIRECTION OUTPUT ;
    USE SIGNAL ;
    PORT
      LAYER M3 ;
        RECT  129.996 64.763 130.014 64.8 ;
    END
  END y[427]
  PIN y[428]
    DIRECTION OUTPUT ;
    USE SIGNAL ;
    PORT
      LAYER M3 ;
        RECT  130.068 64.763 130.086 64.8 ;
    END
  END y[428]
  PIN y[429]
    DIRECTION OUTPUT ;
    USE SIGNAL ;
    PORT
      LAYER M3 ;
        RECT  130.14 64.763 130.158 64.8 ;
    END
  END y[429]
  PIN y[42]
    DIRECTION OUTPUT ;
    USE SIGNAL ;
    PORT
      LAYER M3 ;
        RECT  132.228 64.763 132.246 64.8 ;
    END
  END y[42]
  PIN y[430]
    DIRECTION OUTPUT ;
    USE SIGNAL ;
    PORT
      LAYER M3 ;
        RECT  130.212 64.763 130.23 64.8 ;
    END
  END y[430]
  PIN y[431]
    DIRECTION OUTPUT ;
    USE SIGNAL ;
    PORT
      LAYER M3 ;
        RECT  130.284 64.763 130.302 64.8 ;
    END
  END y[431]
  PIN y[432]
    DIRECTION OUTPUT ;
    USE SIGNAL ;
    PORT
      LAYER M3 ;
        RECT  130.356 64.763 130.374 64.8 ;
    END
  END y[432]
  PIN y[433]
    DIRECTION OUTPUT ;
    USE SIGNAL ;
    PORT
      LAYER M3 ;
        RECT  130.428 64.763 130.446 64.8 ;
    END
  END y[433]
  PIN y[434]
    DIRECTION OUTPUT ;
    USE SIGNAL ;
    PORT
      LAYER M3 ;
        RECT  130.5 64.763 130.518 64.8 ;
    END
  END y[434]
  PIN y[435]
    DIRECTION OUTPUT ;
    USE SIGNAL ;
    PORT
      LAYER M3 ;
        RECT  130.572 64.763 130.59 64.8 ;
    END
  END y[435]
  PIN y[436]
    DIRECTION OUTPUT ;
    USE SIGNAL ;
    PORT
      LAYER M5 ;
        RECT  103.056 64.716 103.08 64.8 ;
    END
  END y[436]
  PIN y[437]
    DIRECTION OUTPUT ;
    USE SIGNAL ;
    PORT
      LAYER M5 ;
        RECT  103.152 64.716 103.176 64.8 ;
    END
  END y[437]
  PIN y[438]
    DIRECTION OUTPUT ;
    USE SIGNAL ;
    PORT
      LAYER M5 ;
        RECT  103.248 64.716 103.272 64.8 ;
    END
  END y[438]
  PIN y[439]
    DIRECTION OUTPUT ;
    USE SIGNAL ;
    PORT
      LAYER M5 ;
        RECT  103.344 64.716 103.368 64.8 ;
    END
  END y[439]
  PIN y[43]
    DIRECTION OUTPUT ;
    USE SIGNAL ;
    PORT
      LAYER M3 ;
        RECT  132.3 64.763 132.318 64.8 ;
    END
  END y[43]
  PIN y[440]
    DIRECTION OUTPUT ;
    USE SIGNAL ;
    PORT
      LAYER M5 ;
        RECT  103.44 64.716 103.464 64.8 ;
    END
  END y[440]
  PIN y[441]
    DIRECTION OUTPUT ;
    USE SIGNAL ;
    PORT
      LAYER M5 ;
        RECT  103.536 64.716 103.56 64.8 ;
    END
  END y[441]
  PIN y[442]
    DIRECTION OUTPUT ;
    USE SIGNAL ;
    PORT
      LAYER M5 ;
        RECT  103.632 64.716 103.656 64.8 ;
    END
  END y[442]
  PIN y[443]
    DIRECTION OUTPUT ;
    USE SIGNAL ;
    PORT
      LAYER M5 ;
        RECT  103.728 64.716 103.752 64.8 ;
    END
  END y[443]
  PIN y[444]
    DIRECTION OUTPUT ;
    USE SIGNAL ;
    PORT
      LAYER M5 ;
        RECT  103.824 64.716 103.848 64.8 ;
    END
  END y[444]
  PIN y[445]
    DIRECTION OUTPUT ;
    USE SIGNAL ;
    PORT
      LAYER M5 ;
        RECT  103.92 64.716 103.944 64.8 ;
    END
  END y[445]
  PIN y[446]
    DIRECTION OUTPUT ;
    USE SIGNAL ;
    PORT
      LAYER M5 ;
        RECT  104.016 64.716 104.04 64.8 ;
    END
  END y[446]
  PIN y[447]
    DIRECTION OUTPUT ;
    USE SIGNAL ;
    PORT
      LAYER M5 ;
        RECT  104.112 64.716 104.136 64.8 ;
    END
  END y[447]
  PIN y[448]
    DIRECTION OUTPUT ;
    USE SIGNAL ;
    PORT
      LAYER M5 ;
        RECT  104.208 64.716 104.232 64.8 ;
    END
  END y[448]
  PIN y[449]
    DIRECTION OUTPUT ;
    USE SIGNAL ;
    PORT
      LAYER M5 ;
        RECT  104.304 64.716 104.328 64.8 ;
    END
  END y[449]
  PIN y[44]
    DIRECTION OUTPUT ;
    USE SIGNAL ;
    PORT
      LAYER M3 ;
        RECT  132.372 64.763 132.39 64.8 ;
    END
  END y[44]
  PIN y[450]
    DIRECTION OUTPUT ;
    USE SIGNAL ;
    PORT
      LAYER M5 ;
        RECT  104.4 64.716 104.424 64.8 ;
    END
  END y[450]
  PIN y[451]
    DIRECTION OUTPUT ;
    USE SIGNAL ;
    PORT
      LAYER M5 ;
        RECT  104.496 64.716 104.52 64.8 ;
    END
  END y[451]
  PIN y[452]
    DIRECTION OUTPUT ;
    USE SIGNAL ;
    PORT
      LAYER M5 ;
        RECT  104.592 64.716 104.616 64.8 ;
    END
  END y[452]
  PIN y[453]
    DIRECTION OUTPUT ;
    USE SIGNAL ;
    PORT
      LAYER M5 ;
        RECT  104.688 64.716 104.712 64.8 ;
    END
  END y[453]
  PIN y[454]
    DIRECTION OUTPUT ;
    USE SIGNAL ;
    PORT
      LAYER M5 ;
        RECT  104.784 64.716 104.808 64.8 ;
    END
  END y[454]
  PIN y[455]
    DIRECTION OUTPUT ;
    USE SIGNAL ;
    PORT
      LAYER M5 ;
        RECT  104.88 64.716 104.904 64.8 ;
    END
  END y[455]
  PIN y[456]
    DIRECTION OUTPUT ;
    USE SIGNAL ;
    PORT
      LAYER M5 ;
        RECT  104.976 64.716 105 64.8 ;
    END
  END y[456]
  PIN y[457]
    DIRECTION OUTPUT ;
    USE SIGNAL ;
    PORT
      LAYER M5 ;
        RECT  105.072 64.716 105.096 64.8 ;
    END
  END y[457]
  PIN y[458]
    DIRECTION OUTPUT ;
    USE SIGNAL ;
    PORT
      LAYER M5 ;
        RECT  105.168 64.716 105.192 64.8 ;
    END
  END y[458]
  PIN y[459]
    DIRECTION OUTPUT ;
    USE SIGNAL ;
    PORT
      LAYER M5 ;
        RECT  105.264 64.716 105.288 64.8 ;
    END
  END y[459]
  PIN y[45]
    DIRECTION OUTPUT ;
    USE SIGNAL ;
    PORT
      LAYER M3 ;
        RECT  132.444 64.763 132.462 64.8 ;
    END
  END y[45]
  PIN y[460]
    DIRECTION OUTPUT ;
    USE SIGNAL ;
    PORT
      LAYER M5 ;
        RECT  105.36 64.716 105.384 64.8 ;
    END
  END y[460]
  PIN y[461]
    DIRECTION OUTPUT ;
    USE SIGNAL ;
    PORT
      LAYER M5 ;
        RECT  105.456 64.716 105.48 64.8 ;
    END
  END y[461]
  PIN y[462]
    DIRECTION OUTPUT ;
    USE SIGNAL ;
    PORT
      LAYER M5 ;
        RECT  105.552 64.716 105.576 64.8 ;
    END
  END y[462]
  PIN y[463]
    DIRECTION OUTPUT ;
    USE SIGNAL ;
    PORT
      LAYER M5 ;
        RECT  105.648 64.716 105.672 64.8 ;
    END
  END y[463]
  PIN y[464]
    DIRECTION OUTPUT ;
    USE SIGNAL ;
    PORT
      LAYER M5 ;
        RECT  105.744 64.716 105.768 64.8 ;
    END
  END y[464]
  PIN y[465]
    DIRECTION OUTPUT ;
    USE SIGNAL ;
    PORT
      LAYER M5 ;
        RECT  105.84 64.716 105.864 64.8 ;
    END
  END y[465]
  PIN y[466]
    DIRECTION OUTPUT ;
    USE SIGNAL ;
    PORT
      LAYER M5 ;
        RECT  105.936 64.716 105.96 64.8 ;
    END
  END y[466]
  PIN y[467]
    DIRECTION OUTPUT ;
    USE SIGNAL ;
    PORT
      LAYER M5 ;
        RECT  106.032 64.716 106.056 64.8 ;
    END
  END y[467]
  PIN y[468]
    DIRECTION OUTPUT ;
    USE SIGNAL ;
    PORT
      LAYER M5 ;
        RECT  116.112 64.716 116.136 64.8 ;
    END
  END y[468]
  PIN y[469]
    DIRECTION OUTPUT ;
    USE SIGNAL ;
    PORT
      LAYER M5 ;
        RECT  116.208 64.716 116.232 64.8 ;
    END
  END y[469]
  PIN y[46]
    DIRECTION OUTPUT ;
    USE SIGNAL ;
    PORT
      LAYER M3 ;
        RECT  132.516 64.763 132.534 64.8 ;
    END
  END y[46]
  PIN y[470]
    DIRECTION OUTPUT ;
    USE SIGNAL ;
    PORT
      LAYER M5 ;
        RECT  116.304 64.716 116.328 64.8 ;
    END
  END y[470]
  PIN y[471]
    DIRECTION OUTPUT ;
    USE SIGNAL ;
    PORT
      LAYER M5 ;
        RECT  116.4 64.716 116.424 64.8 ;
    END
  END y[471]
  PIN y[472]
    DIRECTION OUTPUT ;
    USE SIGNAL ;
    PORT
      LAYER M5 ;
        RECT  116.496 64.716 116.52 64.8 ;
    END
  END y[472]
  PIN y[473]
    DIRECTION OUTPUT ;
    USE SIGNAL ;
    PORT
      LAYER M5 ;
        RECT  116.592 64.716 116.616 64.8 ;
    END
  END y[473]
  PIN y[474]
    DIRECTION OUTPUT ;
    USE SIGNAL ;
    PORT
      LAYER M5 ;
        RECT  116.688 64.716 116.712 64.8 ;
    END
  END y[474]
  PIN y[475]
    DIRECTION OUTPUT ;
    USE SIGNAL ;
    PORT
      LAYER M5 ;
        RECT  116.784 64.716 116.808 64.8 ;
    END
  END y[475]
  PIN y[476]
    DIRECTION OUTPUT ;
    USE SIGNAL ;
    PORT
      LAYER M5 ;
        RECT  116.88 64.716 116.904 64.8 ;
    END
  END y[476]
  PIN y[477]
    DIRECTION OUTPUT ;
    USE SIGNAL ;
    PORT
      LAYER M5 ;
        RECT  116.976 64.716 117 64.8 ;
    END
  END y[477]
  PIN y[478]
    DIRECTION OUTPUT ;
    USE SIGNAL ;
    PORT
      LAYER M5 ;
        RECT  117.072 64.716 117.096 64.8 ;
    END
  END y[478]
  PIN y[479]
    DIRECTION OUTPUT ;
    USE SIGNAL ;
    PORT
      LAYER M5 ;
        RECT  117.168 64.716 117.192 64.8 ;
    END
  END y[479]
  PIN y[47]
    DIRECTION OUTPUT ;
    USE SIGNAL ;
    PORT
      LAYER M3 ;
        RECT  132.588 64.763 132.606 64.8 ;
    END
  END y[47]
  PIN y[480]
    DIRECTION OUTPUT ;
    USE SIGNAL ;
    PORT
      LAYER M5 ;
        RECT  117.264 64.716 117.288 64.8 ;
    END
  END y[480]
  PIN y[481]
    DIRECTION OUTPUT ;
    USE SIGNAL ;
    PORT
      LAYER M5 ;
        RECT  117.36 64.716 117.384 64.8 ;
    END
  END y[481]
  PIN y[482]
    DIRECTION OUTPUT ;
    USE SIGNAL ;
    PORT
      LAYER M5 ;
        RECT  117.456 64.716 117.48 64.8 ;
    END
  END y[482]
  PIN y[483]
    DIRECTION OUTPUT ;
    USE SIGNAL ;
    PORT
      LAYER M5 ;
        RECT  117.552 64.716 117.576 64.8 ;
    END
  END y[483]
  PIN y[484]
    DIRECTION OUTPUT ;
    USE SIGNAL ;
    PORT
      LAYER M5 ;
        RECT  117.648 64.716 117.672 64.8 ;
    END
  END y[484]
  PIN y[485]
    DIRECTION OUTPUT ;
    USE SIGNAL ;
    PORT
      LAYER M5 ;
        RECT  117.744 64.716 117.768 64.8 ;
    END
  END y[485]
  PIN y[486]
    DIRECTION OUTPUT ;
    USE SIGNAL ;
    PORT
      LAYER M5 ;
        RECT  117.84 64.716 117.864 64.8 ;
    END
  END y[486]
  PIN y[487]
    DIRECTION OUTPUT ;
    USE SIGNAL ;
    PORT
      LAYER M5 ;
        RECT  117.936 64.716 117.96 64.8 ;
    END
  END y[487]
  PIN y[488]
    DIRECTION OUTPUT ;
    USE SIGNAL ;
    PORT
      LAYER M5 ;
        RECT  118.032 64.716 118.056 64.8 ;
    END
  END y[488]
  PIN y[489]
    DIRECTION OUTPUT ;
    USE SIGNAL ;
    PORT
      LAYER M5 ;
        RECT  118.128 64.716 118.152 64.8 ;
    END
  END y[489]
  PIN y[48]
    DIRECTION OUTPUT ;
    USE SIGNAL ;
    PORT
      LAYER M3 ;
        RECT  132.66 64.763 132.678 64.8 ;
    END
  END y[48]
  PIN y[490]
    DIRECTION OUTPUT ;
    USE SIGNAL ;
    PORT
      LAYER M5 ;
        RECT  118.224 64.716 118.248 64.8 ;
    END
  END y[490]
  PIN y[491]
    DIRECTION OUTPUT ;
    USE SIGNAL ;
    PORT
      LAYER M5 ;
        RECT  118.32 64.716 118.344 64.8 ;
    END
  END y[491]
  PIN y[492]
    DIRECTION OUTPUT ;
    USE SIGNAL ;
    PORT
      LAYER M5 ;
        RECT  118.416 64.716 118.44 64.8 ;
    END
  END y[492]
  PIN y[493]
    DIRECTION OUTPUT ;
    USE SIGNAL ;
    PORT
      LAYER M5 ;
        RECT  118.512 64.716 118.536 64.8 ;
    END
  END y[493]
  PIN y[494]
    DIRECTION OUTPUT ;
    USE SIGNAL ;
    PORT
      LAYER M5 ;
        RECT  118.608 64.716 118.632 64.8 ;
    END
  END y[494]
  PIN y[495]
    DIRECTION OUTPUT ;
    USE SIGNAL ;
    PORT
      LAYER M5 ;
        RECT  118.704 64.716 118.728 64.8 ;
    END
  END y[495]
  PIN y[496]
    DIRECTION OUTPUT ;
    USE SIGNAL ;
    PORT
      LAYER M5 ;
        RECT  118.8 64.716 118.824 64.8 ;
    END
  END y[496]
  PIN y[497]
    DIRECTION OUTPUT ;
    USE SIGNAL ;
    PORT
      LAYER M5 ;
        RECT  118.896 64.716 118.92 64.8 ;
    END
  END y[497]
  PIN y[498]
    DIRECTION OUTPUT ;
    USE SIGNAL ;
    PORT
      LAYER M5 ;
        RECT  118.992 64.716 119.016 64.8 ;
    END
  END y[498]
  PIN y[499]
    DIRECTION OUTPUT ;
    USE SIGNAL ;
    PORT
      LAYER M5 ;
        RECT  119.088 64.716 119.112 64.8 ;
    END
  END y[499]
  PIN y[49]
    DIRECTION OUTPUT ;
    USE SIGNAL ;
    PORT
      LAYER M3 ;
        RECT  132.732 64.763 132.75 64.8 ;
    END
  END y[49]
  PIN y[4]
    DIRECTION OUTPUT ;
    USE SIGNAL ;
    PORT
      LAYER M3 ;
        RECT  107.604 64.763 107.622 64.8 ;
    END
  END y[4]
  PIN y[500]
    DIRECTION OUTPUT ;
    USE SIGNAL ;
    PORT
      LAYER M5 ;
        RECT  131.088 64.716 131.112 64.8 ;
    END
  END y[500]
  PIN y[501]
    DIRECTION OUTPUT ;
    USE SIGNAL ;
    PORT
      LAYER M5 ;
        RECT  131.184 64.716 131.208 64.8 ;
    END
  END y[501]
  PIN y[502]
    DIRECTION OUTPUT ;
    USE SIGNAL ;
    PORT
      LAYER M5 ;
        RECT  131.28 64.716 131.304 64.8 ;
    END
  END y[502]
  PIN y[503]
    DIRECTION OUTPUT ;
    USE SIGNAL ;
    PORT
      LAYER M5 ;
        RECT  131.376 64.716 131.4 64.8 ;
    END
  END y[503]
  PIN y[504]
    DIRECTION OUTPUT ;
    USE SIGNAL ;
    PORT
      LAYER M5 ;
        RECT  131.472 64.716 131.496 64.8 ;
    END
  END y[504]
  PIN y[505]
    DIRECTION OUTPUT ;
    USE SIGNAL ;
    PORT
      LAYER M5 ;
        RECT  131.568 64.716 131.592 64.8 ;
    END
  END y[505]
  PIN y[506]
    DIRECTION OUTPUT ;
    USE SIGNAL ;
    PORT
      LAYER M5 ;
        RECT  131.664 64.716 131.688 64.8 ;
    END
  END y[506]
  PIN y[507]
    DIRECTION OUTPUT ;
    USE SIGNAL ;
    PORT
      LAYER M5 ;
        RECT  131.76 64.716 131.784 64.8 ;
    END
  END y[507]
  PIN y[508]
    DIRECTION OUTPUT ;
    USE SIGNAL ;
    PORT
      LAYER M5 ;
        RECT  131.856 64.716 131.88 64.8 ;
    END
  END y[508]
  PIN y[509]
    DIRECTION OUTPUT ;
    USE SIGNAL ;
    PORT
      LAYER M5 ;
        RECT  131.952 64.716 131.976 64.8 ;
    END
  END y[509]
  PIN y[50]
    DIRECTION OUTPUT ;
    USE SIGNAL ;
    PORT
      LAYER M3 ;
        RECT  132.804 64.763 132.822 64.8 ;
    END
  END y[50]
  PIN y[510]
    DIRECTION OUTPUT ;
    USE SIGNAL ;
    PORT
      LAYER M5 ;
        RECT  132.048 64.716 132.072 64.8 ;
    END
  END y[510]
  PIN y[511]
    DIRECTION OUTPUT ;
    USE SIGNAL ;
    PORT
      LAYER M5 ;
        RECT  132.144 64.716 132.168 64.8 ;
    END
  END y[511]
  PIN y[51]
    DIRECTION OUTPUT ;
    USE SIGNAL ;
    PORT
      LAYER M3 ;
        RECT  132.876 64.763 132.894 64.8 ;
    END
  END y[51]
  PIN y[52]
    DIRECTION OUTPUT ;
    USE SIGNAL ;
    PORT
      LAYER M3 ;
        RECT  99.54 64.763 99.558 64.8 ;
    END
  END y[52]
  PIN y[53]
    DIRECTION OUTPUT ;
    USE SIGNAL ;
    PORT
      LAYER M3 ;
        RECT  99.612 64.763 99.63 64.8 ;
    END
  END y[53]
  PIN y[54]
    DIRECTION OUTPUT ;
    USE SIGNAL ;
    PORT
      LAYER M3 ;
        RECT  99.684 64.763 99.702 64.8 ;
    END
  END y[54]
  PIN y[55]
    DIRECTION OUTPUT ;
    USE SIGNAL ;
    PORT
      LAYER M3 ;
        RECT  99.756 64.763 99.774 64.8 ;
    END
  END y[55]
  PIN y[56]
    DIRECTION OUTPUT ;
    USE SIGNAL ;
    PORT
      LAYER M3 ;
        RECT  99.828 64.763 99.846 64.8 ;
    END
  END y[56]
  PIN y[57]
    DIRECTION OUTPUT ;
    USE SIGNAL ;
    PORT
      LAYER M3 ;
        RECT  99.9 64.763 99.918 64.8 ;
    END
  END y[57]
  PIN y[58]
    DIRECTION OUTPUT ;
    USE SIGNAL ;
    PORT
      LAYER M3 ;
        RECT  99.972 64.763 99.99 64.8 ;
    END
  END y[58]
  PIN y[59]
    DIRECTION OUTPUT ;
    USE SIGNAL ;
    PORT
      LAYER M3 ;
        RECT  100.044 64.763 100.062 64.8 ;
    END
  END y[59]
  PIN y[5]
    DIRECTION OUTPUT ;
    USE SIGNAL ;
    PORT
      LAYER M3 ;
        RECT  107.676 64.763 107.694 64.8 ;
    END
  END y[5]
  PIN y[60]
    DIRECTION OUTPUT ;
    USE SIGNAL ;
    PORT
      LAYER M3 ;
        RECT  100.116 64.763 100.134 64.8 ;
    END
  END y[60]
  PIN y[61]
    DIRECTION OUTPUT ;
    USE SIGNAL ;
    PORT
      LAYER M3 ;
        RECT  100.188 64.763 100.206 64.8 ;
    END
  END y[61]
  PIN y[62]
    DIRECTION OUTPUT ;
    USE SIGNAL ;
    PORT
      LAYER M3 ;
        RECT  100.26 64.763 100.278 64.8 ;
    END
  END y[62]
  PIN y[63]
    DIRECTION OUTPUT ;
    USE SIGNAL ;
    PORT
      LAYER M3 ;
        RECT  100.332 64.763 100.35 64.8 ;
    END
  END y[63]
  PIN y[64]
    DIRECTION OUTPUT ;
    USE SIGNAL ;
    PORT
      LAYER M3 ;
        RECT  100.404 64.763 100.422 64.8 ;
    END
  END y[64]
  PIN y[65]
    DIRECTION OUTPUT ;
    USE SIGNAL ;
    PORT
      LAYER M3 ;
        RECT  100.476 64.763 100.494 64.8 ;
    END
  END y[65]
  PIN y[66]
    DIRECTION OUTPUT ;
    USE SIGNAL ;
    PORT
      LAYER M3 ;
        RECT  100.548 64.763 100.566 64.8 ;
    END
  END y[66]
  PIN y[67]
    DIRECTION OUTPUT ;
    USE SIGNAL ;
    PORT
      LAYER M3 ;
        RECT  100.62 64.763 100.638 64.8 ;
    END
  END y[67]
  PIN y[68]
    DIRECTION OUTPUT ;
    USE SIGNAL ;
    PORT
      LAYER M3 ;
        RECT  100.692 64.763 100.71 64.8 ;
    END
  END y[68]
  PIN y[69]
    DIRECTION OUTPUT ;
    USE SIGNAL ;
    PORT
      LAYER M3 ;
        RECT  100.764 64.763 100.782 64.8 ;
    END
  END y[69]
  PIN y[6]
    DIRECTION OUTPUT ;
    USE SIGNAL ;
    PORT
      LAYER M3 ;
        RECT  107.748 64.763 107.766 64.8 ;
    END
  END y[6]
  PIN y[70]
    DIRECTION OUTPUT ;
    USE SIGNAL ;
    PORT
      LAYER M3 ;
        RECT  100.836 64.763 100.854 64.8 ;
    END
  END y[70]
  PIN y[71]
    DIRECTION OUTPUT ;
    USE SIGNAL ;
    PORT
      LAYER M3 ;
        RECT  100.908 64.763 100.926 64.8 ;
    END
  END y[71]
  PIN y[72]
    DIRECTION OUTPUT ;
    USE SIGNAL ;
    PORT
      LAYER M3 ;
        RECT  100.98 64.763 100.998 64.8 ;
    END
  END y[72]
  PIN y[73]
    DIRECTION OUTPUT ;
    USE SIGNAL ;
    PORT
      LAYER M3 ;
        RECT  101.052 64.763 101.07 64.8 ;
    END
  END y[73]
  PIN y[74]
    DIRECTION OUTPUT ;
    USE SIGNAL ;
    PORT
      LAYER M3 ;
        RECT  101.124 64.763 101.142 64.8 ;
    END
  END y[74]
  PIN y[75]
    DIRECTION OUTPUT ;
    USE SIGNAL ;
    PORT
      LAYER M3 ;
        RECT  101.196 64.763 101.214 64.8 ;
    END
  END y[75]
  PIN y[76]
    DIRECTION OUTPUT ;
    USE SIGNAL ;
    PORT
      LAYER M3 ;
        RECT  101.268 64.763 101.286 64.8 ;
    END
  END y[76]
  PIN y[77]
    DIRECTION OUTPUT ;
    USE SIGNAL ;
    PORT
      LAYER M3 ;
        RECT  101.34 64.763 101.358 64.8 ;
    END
  END y[77]
  PIN y[78]
    DIRECTION OUTPUT ;
    USE SIGNAL ;
    PORT
      LAYER M3 ;
        RECT  101.412 64.763 101.43 64.8 ;
    END
  END y[78]
  PIN y[79]
    DIRECTION OUTPUT ;
    USE SIGNAL ;
    PORT
      LAYER M3 ;
        RECT  101.484 64.763 101.502 64.8 ;
    END
  END y[79]
  PIN y[7]
    DIRECTION OUTPUT ;
    USE SIGNAL ;
    PORT
      LAYER M3 ;
        RECT  107.82 64.763 107.838 64.8 ;
    END
  END y[7]
  PIN y[80]
    DIRECTION OUTPUT ;
    USE SIGNAL ;
    PORT
      LAYER M3 ;
        RECT  101.556 64.763 101.574 64.8 ;
    END
  END y[80]
  PIN y[81]
    DIRECTION OUTPUT ;
    USE SIGNAL ;
    PORT
      LAYER M3 ;
        RECT  101.628 64.763 101.646 64.8 ;
    END
  END y[81]
  PIN y[82]
    DIRECTION OUTPUT ;
    USE SIGNAL ;
    PORT
      LAYER M3 ;
        RECT  101.7 64.763 101.718 64.8 ;
    END
  END y[82]
  PIN y[83]
    DIRECTION OUTPUT ;
    USE SIGNAL ;
    PORT
      LAYER M3 ;
        RECT  101.772 64.763 101.79 64.8 ;
    END
  END y[83]
  PIN y[84]
    DIRECTION OUTPUT ;
    USE SIGNAL ;
    PORT
      LAYER M5 ;
        RECT  132.24 64.716 132.264 64.8 ;
    END
  END y[84]
  PIN y[85]
    DIRECTION OUTPUT ;
    USE SIGNAL ;
    PORT
      LAYER M5 ;
        RECT  132.336 64.716 132.36 64.8 ;
    END
  END y[85]
  PIN y[86]
    DIRECTION OUTPUT ;
    USE SIGNAL ;
    PORT
      LAYER M5 ;
        RECT  132.432 64.716 132.456 64.8 ;
    END
  END y[86]
  PIN y[87]
    DIRECTION OUTPUT ;
    USE SIGNAL ;
    PORT
      LAYER M5 ;
        RECT  132.528 64.716 132.552 64.8 ;
    END
  END y[87]
  PIN y[88]
    DIRECTION OUTPUT ;
    USE SIGNAL ;
    PORT
      LAYER M5 ;
        RECT  132.624 64.716 132.648 64.8 ;
    END
  END y[88]
  PIN y[89]
    DIRECTION OUTPUT ;
    USE SIGNAL ;
    PORT
      LAYER M5 ;
        RECT  132.72 64.716 132.744 64.8 ;
    END
  END y[89]
  PIN y[8]
    DIRECTION OUTPUT ;
    USE SIGNAL ;
    PORT
      LAYER M3 ;
        RECT  107.892 64.763 107.91 64.8 ;
    END
  END y[8]
  PIN y[90]
    DIRECTION OUTPUT ;
    USE SIGNAL ;
    PORT
      LAYER M5 ;
        RECT  132.816 64.716 132.84 64.8 ;
    END
  END y[90]
  PIN y[91]
    DIRECTION OUTPUT ;
    USE SIGNAL ;
    PORT
      LAYER M5 ;
        RECT  132.912 64.716 132.936 64.8 ;
    END
  END y[91]
  PIN y[92]
    DIRECTION OUTPUT ;
    USE SIGNAL ;
    PORT
      LAYER M5 ;
        RECT  133.008 64.716 133.032 64.8 ;
    END
  END y[92]
  PIN y[93]
    DIRECTION OUTPUT ;
    USE SIGNAL ;
    PORT
      LAYER M5 ;
        RECT  133.104 64.716 133.128 64.8 ;
    END
  END y[93]
  PIN y[94]
    DIRECTION OUTPUT ;
    USE SIGNAL ;
    PORT
      LAYER M5 ;
        RECT  133.2 64.716 133.224 64.8 ;
    END
  END y[94]
  PIN y[95]
    DIRECTION OUTPUT ;
    USE SIGNAL ;
    PORT
      LAYER M5 ;
        RECT  133.296 64.716 133.32 64.8 ;
    END
  END y[95]
  PIN y[96]
    DIRECTION OUTPUT ;
    USE SIGNAL ;
    PORT
      LAYER M5 ;
        RECT  133.392 64.716 133.416 64.8 ;
    END
  END y[96]
  PIN y[97]
    DIRECTION OUTPUT ;
    USE SIGNAL ;
    PORT
      LAYER M5 ;
        RECT  133.488 64.716 133.512 64.8 ;
    END
  END y[97]
  PIN y[98]
    DIRECTION OUTPUT ;
    USE SIGNAL ;
    PORT
      LAYER M5 ;
        RECT  133.584 64.716 133.608 64.8 ;
    END
  END y[98]
  PIN y[99]
    DIRECTION OUTPUT ;
    USE SIGNAL ;
    PORT
      LAYER M5 ;
        RECT  133.68 64.716 133.704 64.8 ;
    END
  END y[99]
  PIN y[9]
    DIRECTION OUTPUT ;
    USE SIGNAL ;
    PORT
      LAYER M3 ;
        RECT  107.964 64.763 107.982 64.8 ;
    END
  END y[9]
  PIN VDD
    DIRECTION INOUT ;
    USE POWER ;
    PORT
      LAYER M5 ;
        RECT  180.792 2.151 180.912 62.649 ;
        RECT  175.392 2.151 175.512 62.649 ;
        RECT  169.992 2.151 170.112 62.649 ;
        RECT  164.592 2.151 164.712 62.649 ;
        RECT  159.192 2.151 159.312 62.649 ;
        RECT  153.792 2.151 153.912 62.649 ;
        RECT  148.392 2.151 148.512 62.649 ;
        RECT  142.992 2.151 143.112 62.649 ;
        RECT  137.592 2.151 137.712 62.649 ;
        RECT  132.192 2.151 132.312 62.649 ;
        RECT  126.792 2.151 126.912 62.649 ;
        RECT  121.392 2.151 121.512 62.649 ;
        RECT  115.992 2.151 116.112 62.649 ;
        RECT  110.592 2.151 110.712 62.649 ;
        RECT  105.192 2.151 105.312 62.649 ;
        RECT  99.792 2.151 99.912 62.649 ;
        RECT  94.392 2.151 94.512 62.649 ;
        RECT  88.992 2.151 89.112 62.649 ;
        RECT  83.592 2.151 83.712 62.649 ;
        RECT  78.192 2.151 78.312 62.649 ;
        RECT  72.792 2.151 72.912 62.649 ;
        RECT  67.392 2.151 67.512 62.649 ;
        RECT  61.992 2.151 62.112 62.649 ;
        RECT  56.592 2.151 56.712 62.649 ;
        RECT  51.192 2.151 51.312 62.649 ;
        RECT  45.792 2.151 45.912 62.649 ;
        RECT  40.392 2.151 40.512 62.649 ;
        RECT  34.992 2.151 35.112 62.649 ;
        RECT  29.592 2.151 29.712 62.649 ;
        RECT  24.192 2.151 24.312 62.649 ;
        RECT  18.792 2.151 18.912 62.649 ;
        RECT  13.392 2.151 13.512 62.649 ;
        RECT  7.992 2.151 8.112 62.649 ;
        RECT  2.592 2.151 2.712 62.649 ;
    END
  END VDD
  PIN VSS
    DIRECTION INOUT ;
    USE GROUND ;
    PORT
      LAYER M5 ;
        RECT  180.6 2.137 180.72 62.663 ;
        RECT  175.2 2.137 175.32 62.663 ;
        RECT  169.8 2.137 169.92 62.663 ;
        RECT  164.4 2.137 164.52 62.663 ;
        RECT  159 2.137 159.12 62.663 ;
        RECT  153.6 2.137 153.72 62.663 ;
        RECT  148.2 2.137 148.32 62.663 ;
        RECT  142.8 2.137 142.92 62.663 ;
        RECT  137.4 2.137 137.52 62.663 ;
        RECT  132 2.137 132.12 62.663 ;
        RECT  126.6 2.137 126.72 62.663 ;
        RECT  121.2 2.137 121.32 62.663 ;
        RECT  115.8 2.137 115.92 62.663 ;
        RECT  110.4 2.137 110.52 62.663 ;
        RECT  105 2.137 105.12 62.663 ;
        RECT  99.6 2.137 99.72 62.663 ;
        RECT  94.2 2.137 94.32 62.663 ;
        RECT  88.8 2.137 88.92 62.663 ;
        RECT  83.4 2.137 83.52 62.663 ;
        RECT  78 2.137 78.12 62.663 ;
        RECT  72.6 2.137 72.72 62.663 ;
        RECT  67.2 2.137 67.32 62.663 ;
        RECT  61.8 2.137 61.92 62.663 ;
        RECT  56.4 2.137 56.52 62.663 ;
        RECT  51 2.137 51.12 62.663 ;
        RECT  45.6 2.137 45.72 62.663 ;
        RECT  40.2 2.137 40.32 62.663 ;
        RECT  34.8 2.137 34.92 62.663 ;
        RECT  29.4 2.137 29.52 62.663 ;
        RECT  24 2.137 24.12 62.663 ;
        RECT  18.6 2.137 18.72 62.663 ;
        RECT  13.2 2.137 13.32 62.663 ;
        RECT  7.8 2.137 7.92 62.663 ;
        RECT  2.4 2.137 2.52 62.663 ;
    END
  END VSS
  # OT_OBS_CLOSED layer=M5 d_um=1.536 added=121
  OBS
    LAYER RVTN ;
     RECT  2.16 2.16 181.44 2.295 ;
     RECT  2.16 2.565 181.44 2.835 ;
     RECT  2.16 3.105 181.44 3.375 ;
     RECT  2.16 3.645 181.44 3.915 ;
     RECT  2.16 4.185 181.44 4.455 ;
     RECT  2.16 4.725 181.44 4.995 ;
     RECT  2.16 5.265 181.44 5.535 ;
     RECT  2.16 5.805 181.44 6.075 ;
     RECT  2.16 6.345 181.44 6.615 ;
     RECT  2.16 6.885 181.44 7.155 ;
     RECT  2.16 7.425 181.44 7.695 ;
     RECT  2.16 7.965 181.44 8.235 ;
     RECT  2.16 8.505 181.44 8.775 ;
     RECT  2.16 9.045 181.44 9.315 ;
     RECT  2.16 9.585 181.44 9.855 ;
     RECT  2.16 10.125 181.44 10.395 ;
     RECT  2.16 10.665 181.44 10.935 ;
     RECT  2.16 11.205 181.44 11.475 ;
     RECT  2.16 11.745 181.44 12.015 ;
     RECT  2.16 12.285 181.44 12.555 ;
     RECT  2.16 12.825 181.44 13.095 ;
     RECT  2.16 13.365 181.44 13.635 ;
     RECT  2.16 13.905 181.44 14.175 ;
     RECT  2.16 14.445 181.44 14.715 ;
     RECT  2.16 14.985 181.44 15.255 ;
     RECT  2.16 15.525 181.44 15.795 ;
     RECT  2.16 16.065 181.44 16.335 ;
     RECT  2.16 16.605 181.44 16.875 ;
     RECT  2.16 17.145 181.44 17.415 ;
     RECT  2.16 17.685 181.44 17.955 ;
     RECT  2.16 18.225 181.44 18.495 ;
     RECT  2.16 18.765 181.44 19.035 ;
     RECT  2.16 19.305 181.44 19.575 ;
     RECT  2.16 19.845 181.44 20.115 ;
     RECT  2.16 20.385 181.44 20.655 ;
     RECT  2.16 20.925 181.44 21.195 ;
     RECT  2.16 21.465 181.44 21.735 ;
     RECT  2.16 22.005 181.44 22.275 ;
     RECT  2.16 22.545 181.44 22.815 ;
     RECT  2.16 23.085 181.44 23.355 ;
     RECT  2.16 23.625 181.44 23.895 ;
     RECT  2.16 24.165 181.44 24.435 ;
     RECT  2.16 24.705 181.44 24.975 ;
     RECT  2.16 25.245 181.44 25.515 ;
     RECT  2.16 25.785 181.44 26.055 ;
     RECT  2.16 26.325 181.44 26.595 ;
     RECT  2.16 26.865 181.44 27.135 ;
     RECT  2.16 27.405 181.44 27.675 ;
     RECT  2.16 27.945 181.44 28.215 ;
     RECT  2.16 28.485 181.44 28.755 ;
     RECT  2.16 29.025 181.44 29.295 ;
     RECT  2.16 29.565 181.44 29.835 ;
     RECT  2.16 30.105 181.44 30.375 ;
     RECT  2.16 30.645 181.44 30.915 ;
     RECT  2.16 31.185 181.44 31.455 ;
     RECT  2.16 31.725 181.44 31.995 ;
     RECT  2.16 32.265 181.44 32.535 ;
     RECT  2.16 32.805 181.44 33.075 ;
     RECT  2.16 33.345 181.44 33.615 ;
     RECT  2.16 33.885 181.44 34.155 ;
     RECT  2.16 34.425 181.44 34.695 ;
     RECT  2.16 34.965 181.44 35.235 ;
     RECT  2.16 35.505 181.44 35.775 ;
     RECT  2.16 36.045 181.44 36.315 ;
     RECT  2.16 36.585 181.44 36.855 ;
     RECT  2.16 37.125 181.44 37.395 ;
     RECT  2.16 37.665 181.44 37.935 ;
     RECT  2.16 38.205 181.44 38.475 ;
     RECT  2.16 38.745 181.44 39.015 ;
     RECT  2.16 39.285 181.44 39.555 ;
     RECT  2.16 39.825 181.44 40.095 ;
     RECT  2.16 40.365 181.44 40.635 ;
     RECT  2.16 40.905 181.44 41.175 ;
     RECT  2.16 41.445 181.44 41.715 ;
     RECT  2.16 41.985 181.44 42.255 ;
     RECT  2.16 42.525 181.44 42.795 ;
     RECT  2.16 43.065 181.44 43.335 ;
     RECT  2.16 43.605 181.44 43.875 ;
     RECT  2.16 44.145 181.44 44.415 ;
     RECT  2.16 44.685 181.44 44.955 ;
     RECT  2.16 45.225 181.44 45.495 ;
     RECT  2.16 45.765 181.44 46.035 ;
     RECT  2.16 46.305 181.44 46.575 ;
     RECT  2.16 46.845 181.44 47.115 ;
     RECT  2.16 47.385 181.44 47.655 ;
     RECT  2.16 47.925 181.44 48.195 ;
     RECT  2.16 48.465 181.44 48.735 ;
     RECT  2.16 49.005 181.44 49.275 ;
     RECT  2.16 49.545 181.44 49.815 ;
     RECT  2.16 50.085 181.44 50.355 ;
     RECT  2.16 50.625 181.44 50.895 ;
     RECT  2.16 51.165 181.44 51.435 ;
     RECT  2.16 51.705 181.44 51.975 ;
     RECT  2.16 52.245 181.44 52.515 ;
     RECT  2.16 52.785 181.44 53.055 ;
     RECT  2.16 53.325 181.44 53.595 ;
     RECT  2.16 53.865 181.44 54.135 ;
     RECT  2.16 54.405 181.44 54.675 ;
     RECT  2.16 54.945 181.44 55.215 ;
     RECT  2.16 55.485 181.44 55.755 ;
     RECT  2.16 56.025 181.44 56.295 ;
     RECT  2.16 56.565 181.44 56.835 ;
     RECT  2.16 57.105 181.44 57.375 ;
     RECT  2.16 57.645 181.44 57.915 ;
     RECT  2.16 58.185 181.44 58.455 ;
     RECT  2.16 58.725 181.44 58.995 ;
     RECT  2.16 59.265 181.44 59.535 ;
     RECT  2.16 59.805 181.44 60.075 ;
     RECT  2.16 60.345 181.44 60.615 ;
     RECT  2.16 60.885 181.44 61.155 ;
     RECT  2.16 61.425 181.44 61.695 ;
     RECT  2.16 61.965 181.44 62.235 ;
     RECT  2.16 62.505 181.44 62.64 ;
    LAYER RVTP ;
     RECT  2.16 2.295 181.44 2.565 ;
     RECT  2.16 2.835 181.44 3.105 ;
     RECT  2.16 3.375 181.44 3.645 ;
     RECT  2.16 3.915 181.44 4.185 ;
     RECT  2.16 4.455 181.44 4.725 ;
     RECT  2.16 4.995 181.44 5.265 ;
     RECT  2.16 5.535 181.44 5.805 ;
     RECT  2.16 6.075 181.44 6.345 ;
     RECT  2.16 6.615 181.44 6.885 ;
     RECT  2.16 7.155 181.44 7.425 ;
     RECT  2.16 7.695 181.44 7.965 ;
     RECT  2.16 8.235 181.44 8.505 ;
     RECT  2.16 8.775 181.44 9.045 ;
     RECT  2.16 9.315 181.44 9.585 ;
     RECT  2.16 9.855 181.44 10.125 ;
     RECT  2.16 10.395 181.44 10.665 ;
     RECT  2.16 10.935 181.44 11.205 ;
     RECT  2.16 11.475 181.44 11.745 ;
     RECT  2.16 12.015 181.44 12.285 ;
     RECT  2.16 12.555 181.44 12.825 ;
     RECT  2.16 13.095 181.44 13.365 ;
     RECT  2.16 13.635 181.44 13.905 ;
     RECT  2.16 14.175 181.44 14.445 ;
     RECT  2.16 14.715 181.44 14.985 ;
     RECT  2.16 15.255 181.44 15.525 ;
     RECT  2.16 15.795 181.44 16.065 ;
     RECT  2.16 16.335 181.44 16.605 ;
     RECT  2.16 16.875 181.44 17.145 ;
     RECT  2.16 17.415 181.44 17.685 ;
     RECT  2.16 17.955 181.44 18.225 ;
     RECT  2.16 18.495 181.44 18.765 ;
     RECT  2.16 19.035 181.44 19.305 ;
     RECT  2.16 19.575 181.44 19.845 ;
     RECT  2.16 20.115 181.44 20.385 ;
     RECT  2.16 20.655 181.44 20.925 ;
     RECT  2.16 21.195 181.44 21.465 ;
     RECT  2.16 21.735 181.44 22.005 ;
     RECT  2.16 22.275 181.44 22.545 ;
     RECT  2.16 22.815 181.44 23.085 ;
     RECT  2.16 23.355 181.44 23.625 ;
     RECT  2.16 23.895 181.44 24.165 ;
     RECT  2.16 24.435 181.44 24.705 ;
     RECT  2.16 24.975 181.44 25.245 ;
     RECT  2.16 25.515 181.44 25.785 ;
     RECT  2.16 26.055 181.44 26.325 ;
     RECT  2.16 26.595 181.44 26.865 ;
     RECT  2.16 27.135 181.44 27.405 ;
     RECT  2.16 27.675 181.44 27.945 ;
     RECT  2.16 28.215 181.44 28.485 ;
     RECT  2.16 28.755 181.44 29.025 ;
     RECT  2.16 29.295 181.44 29.565 ;
     RECT  2.16 29.835 181.44 30.105 ;
     RECT  2.16 30.375 181.44 30.645 ;
     RECT  2.16 30.915 181.44 31.185 ;
     RECT  2.16 31.455 181.44 31.725 ;
     RECT  2.16 31.995 181.44 32.265 ;
     RECT  2.16 32.535 181.44 32.805 ;
     RECT  2.16 33.075 181.44 33.345 ;
     RECT  2.16 33.615 181.44 33.885 ;
     RECT  2.16 34.155 181.44 34.425 ;
     RECT  2.16 34.695 181.44 34.965 ;
     RECT  2.16 35.235 181.44 35.505 ;
     RECT  2.16 35.775 181.44 36.045 ;
     RECT  2.16 36.315 181.44 36.585 ;
     RECT  2.16 36.855 181.44 37.125 ;
     RECT  2.16 37.395 181.44 37.665 ;
     RECT  2.16 37.935 181.44 38.205 ;
     RECT  2.16 38.475 181.44 38.745 ;
     RECT  2.16 39.015 181.44 39.285 ;
     RECT  2.16 39.555 181.44 39.825 ;
     RECT  2.16 40.095 181.44 40.365 ;
     RECT  2.16 40.635 181.44 40.905 ;
     RECT  2.16 41.175 181.44 41.445 ;
     RECT  2.16 41.715 181.44 41.985 ;
     RECT  2.16 42.255 181.44 42.525 ;
     RECT  2.16 42.795 181.44 43.065 ;
     RECT  2.16 43.335 181.44 43.605 ;
     RECT  2.16 43.875 181.44 44.145 ;
     RECT  2.16 44.415 181.44 44.685 ;
     RECT  2.16 44.955 181.44 45.225 ;
     RECT  2.16 45.495 181.44 45.765 ;
     RECT  2.16 46.035 181.44 46.305 ;
     RECT  2.16 46.575 181.44 46.845 ;
     RECT  2.16 47.115 181.44 47.385 ;
     RECT  2.16 47.655 181.44 47.925 ;
     RECT  2.16 48.195 181.44 48.465 ;
     RECT  2.16 48.735 181.44 49.005 ;
     RECT  2.16 49.275 181.44 49.545 ;
     RECT  2.16 49.815 181.44 50.085 ;
     RECT  2.16 50.355 181.44 50.625 ;
     RECT  2.16 50.895 181.44 51.165 ;
     RECT  2.16 51.435 181.44 51.705 ;
     RECT  2.16 51.975 181.44 52.245 ;
     RECT  2.16 52.515 181.44 52.785 ;
     RECT  2.16 53.055 181.44 53.325 ;
     RECT  2.16 53.595 181.44 53.865 ;
     RECT  2.16 54.135 181.44 54.405 ;
     RECT  2.16 54.675 181.44 54.945 ;
     RECT  2.16 55.215 181.44 55.485 ;
     RECT  2.16 55.755 181.44 56.025 ;
     RECT  2.16 56.295 181.44 56.565 ;
     RECT  2.16 56.835 181.44 57.105 ;
     RECT  2.16 57.375 181.44 57.645 ;
     RECT  2.16 57.915 181.44 58.185 ;
     RECT  2.16 58.455 181.44 58.725 ;
     RECT  2.16 58.995 181.44 59.265 ;
     RECT  2.16 59.535 181.44 59.805 ;
     RECT  2.16 60.075 181.44 60.345 ;
     RECT  2.16 60.615 181.44 60.885 ;
     RECT  2.16 61.155 181.44 61.425 ;
     RECT  2.16 61.695 181.44 61.965 ;
     RECT  2.16 62.235 181.44 62.505 ;
    LAYER M1 ;
     RECT  2.16 2.151 181.44 62.649 ;
    LAYER M2 ;
     RECT  2.16 2.151 76.495 62.649 ;
     RECT  76.495 2.034 77.639 62.649 ;
     RECT  79.375 0.036 79.519 0.054 ;
     RECT  79.519 0.036 79.555 0.279 ;
     RECT  77.827 1.116 79.555 1.134 ;
     RECT  79.555 0.036 79.763 1.134 ;
     RECT  79.807 1.152 80.707 1.17 ;
     RECT  80.707 1.152 80.743 1.242 ;
     RECT  77.639 2.151 80.743 62.649 ;
     RECT  80.743 1.152 80.807 62.649 ;
     RECT  80.807 1.728 80.987 62.649 ;
     RECT  79.763 0.036 81.175 0.054 ;
     RECT  81.175 0.036 81.463 0.198 ;
     RECT  81.463 0.036 81.671 0.594 ;
     RECT  81.671 0.108 82.355 0.594 ;
     RECT  82.355 0.108 82.427 0.126 ;
     RECT  80.987 2.151 82.435 62.649 ;
     RECT  82.435 2.151 82.579 62.802 ;
     RECT  82.579 2.151 82.615 62.874 ;
     RECT  82.615 2.151 83.083 63.576 ;
     RECT  83.083 2.151 83.947 63.648 ;
     RECT  83.947 2.151 84.019 63.882 ;
     RECT  84.019 2.151 84.343 63.999 ;
     RECT  83.119 64.746 84.343 64.764 ;
     RECT  85.351 1.152 85.451 1.17 ;
     RECT  84.343 2.151 86.971 64.764 ;
     RECT  86.395 0.036 87.079 0.054 ;
     RECT  87.079 0.036 87.179 0.126 ;
     RECT  86.971 1.764 87.179 64.764 ;
     RECT  87.179 0.036 88.159 0.054 ;
     RECT  88.159 0.036 88.799 0.126 ;
     RECT  88.951 0.261 89.267 0.279 ;
     RECT  87.979 1.152 89.267 1.17 ;
     RECT  87.179 2.151 89.267 64.764 ;
     RECT  89.267 64.746 89.843 64.764 ;
     RECT  89.267 2.151 90.059 63.954 ;
     RECT  90.059 63.864 90.203 63.954 ;
     RECT  90.059 2.151 90.275 62.964 ;
     RECT  90.275 2.151 90.563 62.919 ;
     RECT  90.203 63.936 91.139 63.954 ;
     RECT  90.563 2.151 91.399 62.766 ;
     RECT  91.399 2.151 91.499 62.802 ;
     RECT  91.651 64.674 91.859 64.692 ;
     RECT  91.499 2.151 92.399 62.766 ;
     RECT  92.399 2.151 93.523 62.73 ;
     RECT  93.523 2.106 94.415 62.73 ;
     RECT  94.415 2.151 94.775 62.73 ;
     RECT  97.699 64.674 97.735 64.692 ;
     RECT  97.735 64.674 97.871 64.764 ;
     RECT  97.871 64.674 97.907 64.692 ;
     RECT  94.775 2.151 98.131 62.649 ;
     RECT  98.131 2.151 98.339 62.694 ;
     RECT  98.851 64.746 98.887 64.764 ;
     RECT  98.339 2.151 99.247 62.649 ;
     RECT  93.739 63.558 99.247 63.576 ;
     RECT  99.247 2.151 99.679 63.576 ;
     RECT  98.887 64.674 99.895 64.764 ;
     RECT  99.679 2.151 99.967 63.612 ;
     RECT  99.895 64.566 99.967 64.764 ;
     RECT  99.967 2.151 101.975 64.764 ;
     RECT  101.975 2.151 102.847 64.728 ;
     RECT  102.847 2.151 102.911 64.764 ;
     RECT  102.911 2.151 103.639 63.774 ;
     RECT  103.639 2.151 104.215 63.81 ;
     RECT  102.911 64.566 104.215 64.764 ;
     RECT  104.215 2.151 108.815 64.764 ;
     RECT  108.815 2.151 109.535 63.81 ;
     RECT  108.815 64.71 109.571 64.764 ;
     RECT  109.535 2.151 110.111 63.648 ;
     RECT  109.571 64.71 110.147 64.728 ;
     RECT  110.111 2.151 110.903 63 ;
     RECT  111.559 64.746 111.595 64.764 ;
     RECT  111.595 64.674 111.955 64.764 ;
     RECT  110.903 2.151 112.207 62.649 ;
     RECT  111.955 64.602 112.423 64.764 ;
     RECT  112.423 64.521 112.523 64.764 ;
     RECT  112.523 64.602 112.739 64.764 ;
     RECT  112.207 2.151 113.071 62.73 ;
     RECT  113.071 2.151 113.143 63.27 ;
     RECT  113.143 2.151 113.503 63.306 ;
     RECT  113.503 2.151 113.575 63.954 ;
     RECT  112.739 64.746 113.575 64.764 ;
     RECT  113.575 2.151 113.747 64.764 ;
     RECT  113.747 64.098 113.855 64.764 ;
     RECT  113.855 64.746 113.963 64.764 ;
     RECT  113.747 2.151 114.215 63.306 ;
     RECT  114.215 2.151 116.167 62.649 ;
     RECT  116.167 2.151 116.311 62.73 ;
     RECT  116.311 2.151 116.995 62.919 ;
     RECT  116.995 2.151 117.247 62.964 ;
     RECT  117.247 2.151 117.319 63 ;
     RECT  117.319 2.151 117.419 63.072 ;
     RECT  117.463 64.638 117.599 64.656 ;
     RECT  117.419 2.151 117.959 62.964 ;
     RECT  117.959 2.151 118.139 62.919 ;
     RECT  118.139 2.151 118.903 62.838 ;
     RECT  118.867 64.638 119.003 64.656 ;
     RECT  118.903 2.151 119.119 63.306 ;
     RECT  119.119 2.151 119.191 63.378 ;
     RECT  119.191 2.151 119.227 63.459 ;
     RECT  119.227 2.151 119.363 63.612 ;
     RECT  119.363 2.151 120.703 62.964 ;
     RECT  120.703 2.151 121.099 63.036 ;
     RECT  121.099 2.151 121.307 63.072 ;
     RECT  121.307 2.151 122.071 62.874 ;
     RECT  122.071 2.151 122.215 62.919 ;
     RECT  122.215 2.151 122.351 62.964 ;
     RECT  122.351 2.151 123.107 62.919 ;
     RECT  123.107 2.151 128.263 62.649 ;
     RECT  128.263 2.151 128.371 62.802 ;
     RECT  128.371 2.151 128.723 62.874 ;
     RECT  128.723 2.151 129.595 62.802 ;
     RECT  129.595 2.151 129.631 62.838 ;
     RECT  129.631 2.151 129.767 62.919 ;
     RECT  129.767 2.151 130.127 62.838 ;
     RECT  130.127 2.151 130.963 62.802 ;
     RECT  130.963 2.151 131.215 62.874 ;
     RECT  131.215 2.151 131.351 63.189 ;
     RECT  131.351 2.151 132.295 62.919 ;
     RECT  132.295 2.151 132.367 63.378 ;
     RECT  132.367 2.151 132.439 63.459 ;
     RECT  132.439 2.151 132.575 63.54 ;
     RECT  132.575 2.151 133.007 62.964 ;
     RECT  133.007 2.151 133.151 62.838 ;
     RECT  133.151 2.151 181.44 62.649 ;
    LAYER M3 ;
     RECT  79.47 0.012 79.524 0.031 ;
     RECT  79.542 0.012 79.596 0.031 ;
     RECT  79.614 0.012 79.668 0.031 ;
     RECT  79.686 0.012 79.74 0.031 ;
     RECT  79.758 0.012 79.812 0.031 ;
     RECT  79.83 0.012 79.884 0.031 ;
     RECT  79.902 0.012 79.956 0.031 ;
     RECT  79.974 0.012 80.028 0.031 ;
     RECT  80.046 0.012 80.1 0.031 ;
     RECT  80.118 0.012 80.172 0.031 ;
     RECT  80.19 0.012 80.244 0.031 ;
     RECT  80.262 0.012 80.316 0.031 ;
     RECT  80.334 0.012 80.388 0.031 ;
     RECT  80.406 0.012 80.46 0.031 ;
     RECT  80.478 0.012 80.532 0.031 ;
     RECT  80.55 0.012 80.604 0.031 ;
     RECT  80.622 0.012 80.676 0.031 ;
     RECT  80.694 0.012 80.748 0.031 ;
     RECT  80.766 0.012 80.82 0.031 ;
     RECT  80.838 0.012 80.892 0.031 ;
     RECT  80.91 0.012 80.964 0.031 ;
     RECT  80.982 0.012 81.036 0.031 ;
     RECT  81.054 0.012 81.108 0.031 ;
     RECT  81.126 0.012 81.18 0.031 ;
     RECT  81.198 0.012 81.252 0.031 ;
     RECT  81.27 0.012 81.324 0.031 ;
     RECT  81.342 0.012 81.396 0.031 ;
     RECT  81.414 0.012 81.468 0.031 ;
     RECT  81.486 0.012 81.54 0.031 ;
     RECT  81.558 0.012 81.612 0.031 ;
     RECT  81.63 0.012 81.684 0.031 ;
     RECT  86.958 0.012 87.012 0.031 ;
     RECT  87.03 0.012 87.084 0.031 ;
     RECT  87.102 0.012 87.156 0.031 ;
     RECT  87.174 0.012 87.228 0.031 ;
     RECT  87.246 0.012 87.3 0.031 ;
     RECT  87.318 0.012 87.372 0.031 ;
     RECT  87.39 0.012 87.444 0.031 ;
     RECT  87.462 0.012 87.516 0.031 ;
     RECT  87.534 0.012 87.588 0.031 ;
     RECT  87.606 0.012 87.66 0.031 ;
     RECT  87.678 0.012 87.732 0.031 ;
     RECT  87.75 0.012 87.804 0.031 ;
     RECT  87.822 0.012 87.876 0.031 ;
     RECT  87.894 0.012 87.948 0.031 ;
     RECT  87.966 0.012 88.02 0.031 ;
     RECT  88.038 0.012 88.092 0.031 ;
     RECT  88.11 0.012 88.164 0.031 ;
     RECT  88.182 0.012 88.236 0.031 ;
     RECT  88.254 0.012 88.308 0.031 ;
     RECT  88.326 0.012 88.38 0.031 ;
     RECT  88.398 0.012 88.452 0.031 ;
     RECT  88.47 0.012 88.524 0.031 ;
     RECT  88.542 0.012 88.596 0.031 ;
     RECT  88.614 0.012 88.668 0.031 ;
     RECT  88.686 0.012 88.74 0.031 ;
     RECT  88.758 0.012 88.812 0.031 ;
     RECT  88.83 0.012 88.884 0.031 ;
     RECT  88.902 0.012 88.956 0.031 ;
     RECT  88.974 0.012 89.028 0.031 ;
     RECT  89.046 0.012 89.1 0.031 ;
     RECT  89.118 0.012 89.172 0.031 ;
     RECT  86.4 0.031 86.94 0.037 ;
     RECT  86.958 0.031 87.012 0.037 ;
     RECT  87.03 0.031 87.084 0.037 ;
     RECT  87.102 0.031 87.156 0.037 ;
     RECT  87.174 0.031 87.228 0.037 ;
     RECT  87.246 0.031 87.3 0.037 ;
     RECT  87.318 0.031 87.372 0.037 ;
     RECT  87.39 0.031 87.444 0.037 ;
     RECT  87.462 0.031 87.516 0.037 ;
     RECT  87.534 0.031 87.588 0.037 ;
     RECT  87.606 0.031 87.66 0.037 ;
     RECT  87.678 0.031 87.732 0.037 ;
     RECT  87.75 0.031 87.804 0.037 ;
     RECT  87.822 0.031 87.876 0.037 ;
     RECT  87.894 0.031 87.948 0.037 ;
     RECT  87.966 0.031 88.02 0.037 ;
     RECT  88.038 0.031 88.092 0.037 ;
     RECT  88.11 0.031 88.164 0.037 ;
     RECT  88.182 0.031 88.236 0.037 ;
     RECT  88.254 0.031 88.308 0.037 ;
     RECT  88.326 0.031 88.38 0.037 ;
     RECT  88.398 0.031 88.452 0.037 ;
     RECT  88.47 0.031 88.524 0.037 ;
     RECT  88.542 0.031 88.596 0.037 ;
     RECT  88.614 0.031 88.668 0.037 ;
     RECT  88.686 0.031 88.74 0.037 ;
     RECT  88.758 0.031 88.812 0.037 ;
     RECT  88.83 0.031 88.884 0.037 ;
     RECT  88.902 0.031 88.956 0.037 ;
     RECT  88.974 0.031 89.028 0.037 ;
     RECT  89.046 0.031 89.1 0.037 ;
     RECT  89.118 0.031 89.172 0.037 ;
     RECT  86.4 0.037 89.19 0.043 ;
     RECT  86.4 0.043 89.334 0.091 ;
     RECT  79.38 0.031 79.452 0.037 ;
     RECT  79.47 0.031 79.524 0.037 ;
     RECT  79.542 0.031 79.596 0.037 ;
     RECT  79.614 0.031 79.668 0.037 ;
     RECT  79.686 0.031 79.74 0.037 ;
     RECT  79.758 0.031 79.812 0.037 ;
     RECT  79.83 0.031 79.884 0.037 ;
     RECT  79.902 0.031 79.956 0.037 ;
     RECT  79.974 0.031 80.028 0.037 ;
     RECT  80.046 0.031 80.1 0.037 ;
     RECT  80.118 0.031 80.172 0.037 ;
     RECT  80.19 0.031 80.244 0.037 ;
     RECT  80.262 0.031 80.316 0.037 ;
     RECT  80.334 0.031 80.388 0.037 ;
     RECT  80.406 0.031 80.46 0.037 ;
     RECT  80.478 0.031 80.532 0.037 ;
     RECT  80.55 0.031 80.604 0.037 ;
     RECT  80.622 0.031 80.676 0.037 ;
     RECT  80.694 0.031 80.748 0.037 ;
     RECT  80.766 0.031 80.82 0.037 ;
     RECT  80.838 0.031 80.892 0.037 ;
     RECT  80.91 0.031 80.964 0.037 ;
     RECT  80.982 0.031 81.036 0.037 ;
     RECT  81.054 0.031 81.108 0.037 ;
     RECT  81.126 0.031 81.18 0.037 ;
     RECT  81.198 0.031 81.252 0.037 ;
     RECT  81.27 0.031 81.324 0.037 ;
     RECT  81.342 0.031 81.396 0.037 ;
     RECT  81.414 0.031 81.468 0.037 ;
     RECT  81.486 0.031 81.54 0.037 ;
     RECT  81.558 0.031 81.612 0.037 ;
     RECT  81.63 0.031 81.684 0.037 ;
     RECT  79.38 0.037 81.702 0.103 ;
     RECT  82.656 0.091 82.674 0.103 ;
     RECT  78.444 0.091 78.462 0.139 ;
     RECT  84.312 0.091 84.33 0.139 ;
     RECT  85.176 0.091 85.482 0.139 ;
     RECT  86.4 0.091 90.09 0.139 ;
     RECT  90.972 0.091 90.99 0.139 ;
     RECT  92.7 0.091 93.366 0.221 ;
     RECT  78.444 0.139 78.534 0.269 ;
     RECT  93.924 0.235 93.942 0.283 ;
     RECT  78.516 0.269 78.534 0.317 ;
     RECT  84.312 0.139 90.09 0.317 ;
     RECT  79.38 0.103 82.674 0.331 ;
     RECT  85.104 0.317 90.09 0.365 ;
     RECT  85.356 0.365 90.09 0.509 ;
     RECT  85.356 0.509 89.262 0.557 ;
     RECT  77.256 0.475 77.274 0.571 ;
     RECT  90.072 0.509 90.09 0.571 ;
     RECT  90.828 0.139 90.99 0.571 ;
     RECT  90.072 0.571 90.99 0.605 ;
     RECT  77.256 0.571 77.634 1.099 ;
     RECT  92.7 0.221 92.79 1.147 ;
     RECT  85.356 0.557 86.418 1.175 ;
     RECT  77.256 1.099 77.958 1.675 ;
     RECT  77.256 1.675 78.174 1.723 ;
     RECT  79.38 0.331 82.998 1.723 ;
     RECT  87.156 0.557 89.262 1.723 ;
     RECT  90.072 0.605 90.774 1.723 ;
     RECT  92.7 1.147 92.826 1.723 ;
     RECT  93.924 0.283 94.662 1.723 ;
     RECT  102.708 0.571 102.726 1.723 ;
     RECT  85.428 1.175 86.418 1.759 ;
     RECT  87.156 1.723 90.774 1.759 ;
     RECT  85.428 1.759 90.774 1.771 ;
     RECT  92.304 1.723 94.842 1.771 ;
     RECT  95.724 1.723 95.85 1.771 ;
     RECT  85.428 1.771 91.386 1.819 ;
     RECT  92.304 1.771 95.85 1.819 ;
     RECT  102.708 1.723 103.626 1.819 ;
     RECT  77.256 1.723 78.354 1.963 ;
     RECT  79.38 1.723 83.106 1.963 ;
     RECT  84.312 0.317 84.33 1.963 ;
     RECT  76.968 1.963 78.354 2.011 ;
     RECT  76.968 2.011 78.606 2.029 ;
     RECT  76.5 2.029 78.606 2.155 ;
     RECT  79.38 1.963 84.33 2.155 ;
     RECT  76.5 2.155 84.33 2.191 ;
     RECT  85.428 1.819 95.85 2.191 ;
     RECT  96.588 2.059 96.606 2.191 ;
     RECT  97.668 1.723 97.686 2.191 ;
     RECT  97.668 2.191 98.118 2.227 ;
     RECT  76.068 2.191 96.606 2.237 ;
     RECT  76.176 2.237 96.606 2.263 ;
     RECT  97.38 2.227 98.118 2.263 ;
     RECT  102.708 1.819 103.662 2.371 ;
     RECT  105.015 2.143 105.105 2.371 ;
     RECT  2.415 2.143 2.505 2.413 ;
     RECT  7.815 2.143 7.905 2.413 ;
     RECT  13.215 2.143 13.305 2.413 ;
     RECT  18.615 2.143 18.705 2.413 ;
     RECT  24.015 2.143 24.105 2.413 ;
     RECT  29.415 2.143 29.505 2.413 ;
     RECT  34.815 2.143 34.905 2.413 ;
     RECT  40.215 2.143 40.305 2.413 ;
     RECT  45.615 2.143 45.705 2.413 ;
     RECT  51.015 2.143 51.105 2.413 ;
     RECT  56.415 2.143 56.505 2.413 ;
     RECT  61.815 2.143 61.905 2.413 ;
     RECT  67.215 2.143 67.305 2.413 ;
     RECT  72.615 2.143 72.705 2.413 ;
     RECT  99.615 2.143 99.705 2.413 ;
     RECT  102.636 2.371 105.105 2.413 ;
     RECT  110.415 2.143 110.505 2.413 ;
     RECT  115.815 2.143 115.905 2.413 ;
     RECT  121.215 2.143 121.305 2.413 ;
     RECT  126.615 2.143 126.705 2.413 ;
     RECT  132.015 2.143 132.105 2.413 ;
     RECT  137.415 2.143 137.505 2.413 ;
     RECT  142.815 2.143 142.905 2.413 ;
     RECT  148.215 2.143 148.305 2.413 ;
     RECT  153.615 2.143 153.705 2.413 ;
     RECT  159.015 2.143 159.105 2.413 ;
     RECT  164.415 2.143 164.505 2.413 ;
     RECT  169.815 2.143 169.905 2.413 ;
     RECT  175.215 2.143 175.305 2.413 ;
     RECT  180.615 2.143 180.705 2.413 ;
     RECT  102.636 2.413 105.297 2.489 ;
     RECT  76.176 2.263 98.118 2.635 ;
     RECT  102.816 2.489 105.297 2.717 ;
     RECT  102.96 2.717 105.297 2.759 ;
     RECT  99.615 2.413 99.897 2.767 ;
     RECT  99.216 2.767 99.897 2.813 ;
     RECT  103.284 2.759 105.297 3.065 ;
     RECT  76.176 2.635 98.442 3.181 ;
     RECT  75.78 3.181 98.622 3.307 ;
     RECT  75.204 3.307 98.622 3.721 ;
     RECT  75.204 3.721 98.838 3.847 ;
     RECT  99.615 2.813 99.897 3.847 ;
     RECT  74.376 3.883 74.394 4.531 ;
     RECT  75.204 3.847 99.897 4.531 ;
     RECT  74.376 4.531 99.897 4.801 ;
     RECT  74.376 4.801 100.386 4.987 ;
     RECT  101.16 4.801 101.178 4.987 ;
     RECT  74.376 4.987 101.178 5.071 ;
     RECT  74.376 5.071 101.286 5.117 ;
     RECT  102.096 5.341 102.402 5.431 ;
     RECT  72.615 2.413 72.897 5.467 ;
     RECT  72.615 5.467 73.53 5.504 ;
     RECT  102.096 5.431 102.618 5.575 ;
     RECT  101.772 5.575 102.618 5.605 ;
     RECT  103.464 3.065 105.297 5.605 ;
     RECT  72.615 5.504 73.17 5.845 ;
     RECT  74.376 5.117 100.782 5.851 ;
     RECT  101.772 5.605 105.297 5.881 ;
     RECT  74.376 5.851 100.89 6.151 ;
     RECT  101.664 5.881 105.297 6.151 ;
     RECT  74.052 6.151 105.297 6.331 ;
     RECT  73.908 6.331 105.297 6.349 ;
     RECT  106.056 6.241 106.29 6.349 ;
     RECT  72.252 5.845 73.17 6.379 ;
     RECT  71.532 6.379 73.17 6.419 ;
     RECT  72 6.419 73.17 6.421 ;
     RECT  73.908 6.349 106.29 6.421 ;
     RECT  72 6.421 106.29 7.195 ;
     RECT  70.128 6.961 70.146 7.231 ;
     RECT  71.1 6.583 71.118 7.231 ;
     RECT  71.892 7.195 106.29 7.231 ;
     RECT  107.064 6.241 107.766 7.231 ;
     RECT  108.504 7.159 108.522 7.231 ;
     RECT  109.332 7.087 109.35 7.231 ;
     RECT  70.884 7.231 71.118 7.321 ;
     RECT  71.892 7.231 109.35 7.321 ;
     RECT  69.984 7.231 70.146 7.501 ;
     RECT  70.884 7.321 109.35 7.501 ;
     RECT  69.984 7.501 109.35 7.735 ;
     RECT  69.876 7.735 109.35 7.771 ;
     RECT  69.624 7.771 109.386 7.861 ;
     RECT  110.415 2.413 110.697 7.861 ;
     RECT  69.3 7.861 110.697 8.311 ;
     RECT  68.76 8.311 110.697 8.545 ;
     RECT  67.215 2.413 67.497 9.121 ;
     RECT  68.688 8.545 110.697 9.121 ;
     RECT  67.215 9.121 110.697 9.617 ;
     RECT  68.292 9.617 110.697 9.661 ;
     RECT  68.292 9.661 110.79 9.931 ;
     RECT  68.292 9.931 111.222 10.049 ;
     RECT  68.328 10.049 111.222 10.895 ;
     RECT  68.904 10.895 111.222 11.011 ;
     RECT  68.904 11.011 111.366 11.789 ;
     RECT  68.904 11.789 110.862 12.631 ;
     RECT  111.6 11.821 111.618 12.631 ;
     RECT  68.904 12.631 111.618 12.785 ;
     RECT  68.904 12.785 68.922 13.531 ;
     RECT  69.84 12.785 111.618 13.531 ;
     RECT  68.904 13.531 111.618 13.567 ;
     RECT  68.904 13.567 111.978 13.568 ;
     RECT  68.904 13.568 68.922 17.375 ;
     RECT  69.84 13.568 111.978 18.301 ;
     RECT  69.84 18.301 112.014 19.627 ;
     RECT  69.768 19.627 112.014 20.381 ;
     RECT  68.868 17.491 68.886 20.461 ;
     RECT  70.416 20.381 112.014 21.155 ;
     RECT  70.488 21.155 112.014 22.747 ;
     RECT  68.868 20.461 69.426 23.371 ;
     RECT  68.724 23.371 69.426 23.585 ;
     RECT  69.408 23.585 69.426 23.701 ;
     RECT  69.408 23.701 69.678 24.205 ;
     RECT  69.408 24.205 69.714 24.359 ;
     RECT  69.408 24.359 69.606 24.395 ;
     RECT  70.488 22.747 112.41 25.583 ;
     RECT  69.408 24.395 69.534 26.221 ;
     RECT  70.488 25.583 112.374 26.221 ;
     RECT  69.408 26.221 112.374 27.095 ;
     RECT  70.776 27.095 112.374 27.779 ;
     RECT  69.408 27.095 69.534 28.715 ;
     RECT  69.408 28.715 69.498 30.029 ;
     RECT  69.48 30.029 69.498 30.181 ;
     RECT  70.776 27.779 112.302 30.451 ;
     RECT  70.56 30.451 112.302 30.685 ;
     RECT  69.48 30.181 69.534 30.721 ;
     RECT  70.308 30.685 112.302 30.721 ;
     RECT  69.48 30.721 112.302 30.955 ;
     RECT  69.264 30.955 112.302 30.992 ;
     RECT  69.48 30.992 112.302 31.955 ;
     RECT  70.452 31.955 112.302 32.189 ;
     RECT  69.48 31.955 69.498 32.683 ;
     RECT  69.336 32.683 69.498 32.729 ;
     RECT  70.452 32.189 112.086 32.881 ;
     RECT  70.272 32.881 112.086 33.043 ;
     RECT  69.804 33.043 112.086 33.305 ;
     RECT  70.128 33.305 112.086 33.421 ;
     RECT  70.128 33.421 112.266 33.691 ;
     RECT  70.128 33.691 112.374 33.845 ;
     RECT  70.452 33.845 112.374 34.231 ;
     RECT  70.452 34.231 112.554 39.893 ;
     RECT  70.452 39.893 112.302 40.055 ;
     RECT  70.488 40.055 112.302 41.521 ;
     RECT  70.488 41.521 112.338 41.755 ;
     RECT  70.344 41.755 112.338 42.173 ;
     RECT  70.596 42.173 112.338 42.601 ;
     RECT  70.596 42.601 112.698 44.141 ;
     RECT  2.415 2.413 2.697 44.995 ;
     RECT  70.596 44.141 112.662 44.995 ;
     RECT  2.412 44.995 2.697 45.163 ;
     RECT  70.596 44.995 112.986 45.293 ;
     RECT  5.868 45.265 5.886 45.499 ;
     RECT  24.015 2.413 24.297 45.499 ;
     RECT  3.456 45.265 4.086 45.535 ;
     RECT  5.112 45.499 5.13 45.535 ;
     RECT  22.824 45.499 22.842 45.535 ;
     RECT  23.868 45.499 24.297 45.535 ;
     RECT  2.304 45.163 2.697 45.547 ;
     RECT  3.456 45.535 5.13 45.547 ;
     RECT  34.815 2.413 35.097 45.547 ;
     RECT  22.824 45.535 22.95 45.563 ;
     RECT  2.304 45.547 5.13 45.571 ;
     RECT  5.868 45.499 6.03 45.571 ;
     RECT  23.76 45.535 24.297 45.571 ;
     RECT  34.416 45.547 35.097 45.571 ;
     RECT  22.932 45.563 22.95 45.581 ;
     RECT  29.415 2.413 29.697 45.661 ;
     RECT  2.304 45.571 6.354 45.689 ;
     RECT  14.328 45.427 14.346 45.689 ;
     RECT  23.76 45.571 24.57 45.689 ;
     RECT  2.304 45.689 4.77 45.725 ;
     RECT  5.724 45.689 6.354 45.725 ;
     RECT  23.868 45.689 24.57 45.725 ;
     RECT  34.416 45.571 35.298 45.725 ;
     RECT  34.596 45.725 35.298 45.733 ;
     RECT  47.7 45.739 47.718 45.805 ;
     RECT  34.596 45.733 35.406 45.841 ;
     RECT  13.215 2.413 13.497 45.931 ;
     RECT  2.415 45.725 4.77 45.959 ;
     RECT  34.596 45.841 35.73 45.959 ;
     RECT  36.792 45.841 36.81 45.959 ;
     RECT  23.868 45.725 24.297 45.965 ;
     RECT  13.104 45.931 13.497 45.968 ;
     RECT  2.415 45.959 4.698 45.995 ;
     RECT  29.415 45.661 29.79 45.995 ;
     RECT  34.815 45.959 35.73 45.995 ;
     RECT  41.868 45.661 41.886 45.995 ;
     RECT  40.215 2.413 40.497 46.027 ;
     RECT  51.015 2.413 51.297 46.027 ;
     RECT  2.415 45.995 4.086 46.067 ;
     RECT  5.724 45.725 6.03 46.067 ;
     RECT  46.728 46.027 46.746 46.067 ;
     RECT  49.572 46.039 49.59 46.075 ;
     RECT  2.415 46.067 3.294 46.103 ;
     RECT  4.068 46.067 4.086 46.103 ;
     RECT  47.484 45.805 47.718 46.103 ;
     RECT  47.7 46.103 47.718 46.109 ;
     RECT  48.636 46.027 48.654 46.111 ;
     RECT  49.428 46.075 49.59 46.111 ;
     RECT  50.364 46.027 51.297 46.111 ;
     RECT  6.012 46.067 6.03 46.139 ;
     RECT  48.024 46.111 51.297 46.229 ;
     RECT  48.024 46.229 48.474 46.265 ;
     RECT  50.148 46.229 51.297 46.345 ;
     RECT  40.215 46.027 40.698 46.349 ;
     RECT  39.168 46.315 39.186 46.381 ;
     RECT  50.148 46.345 51.93 46.381 ;
     RECT  70.596 45.293 112.662 46.381 ;
     RECT  48.096 46.265 48.186 46.499 ;
     RECT  50.148 46.381 52.002 46.499 ;
     RECT  48.168 46.499 48.186 46.535 ;
     RECT  39.132 46.381 39.186 46.541 ;
     RECT  54.324 46.579 54.342 46.615 ;
     RECT  50.184 46.499 52.002 46.643 ;
     RECT  54.324 46.615 54.63 46.645 ;
     RECT  50.364 46.643 52.002 46.651 ;
     RECT  52.812 46.345 52.83 46.651 ;
     RECT  53.784 46.645 54.63 46.651 ;
     RECT  56.415 2.413 56.697 46.651 ;
     RECT  50.364 46.651 55.458 46.733 ;
     RECT  51.015 46.733 55.458 46.795 ;
     RECT  56.268 46.651 56.697 46.795 ;
     RECT  51.015 46.795 55.494 46.805 ;
     RECT  55.116 46.805 55.494 46.813 ;
     RECT  56.268 46.795 57.33 46.813 ;
     RECT  58.068 46.777 58.086 46.813 ;
     RECT  39.132 46.541 39.15 46.877 ;
     RECT  40.215 46.349 40.59 46.877 ;
     RECT  68.976 46.747 68.994 46.877 ;
     RECT  55.116 46.813 57.33 46.921 ;
     RECT  58.068 46.813 58.158 46.921 ;
     RECT  54.324 46.805 54.342 46.973 ;
     RECT  55.116 46.921 58.626 46.973 ;
     RECT  60.192 46.921 60.282 46.973 ;
     RECT  70.596 46.381 112.698 47.035 ;
     RECT  55.116 46.973 55.674 47.039 ;
     RECT  56.415 46.973 58.626 47.039 ;
     RECT  60.192 46.973 60.21 47.039 ;
     RECT  51.015 46.805 53.478 47.075 ;
     RECT  55.188 47.039 55.458 47.075 ;
     RECT  56.415 47.039 57.114 47.075 ;
     RECT  58.068 47.039 58.626 47.075 ;
     RECT  70.128 47.035 112.698 47.075 ;
     RECT  70.848 47.075 112.698 47.131 ;
     RECT  51.015 47.075 53.442 47.183 ;
     RECT  52.524 47.183 52.542 47.309 ;
     RECT  53.424 47.183 53.442 47.309 ;
     RECT  56.415 47.075 57.006 47.309 ;
     RECT  70.848 47.131 113.058 47.309 ;
     RECT  56.415 47.309 56.898 47.345 ;
     RECT  70.848 47.309 112.878 47.579 ;
     RECT  70.848 47.579 112.446 47.849 ;
     RECT  70.848 47.849 112.374 48.379 ;
     RECT  70.776 48.379 112.374 48.425 ;
     RECT  67.215 9.617 67.497 48.523 ;
     RECT  67.104 48.523 67.497 48.569 ;
     RECT  70.848 48.425 112.374 48.901 ;
     RECT  70.848 48.901 112.626 48.965 ;
     RECT  70.956 48.965 112.626 48.989 ;
     RECT  70.956 48.989 112.05 50.009 ;
     RECT  70.956 50.009 111.762 50.045 ;
     RECT  70.956 50.045 111.33 50.107 ;
     RECT  70.596 50.107 111.33 50.153 ;
     RECT  70.992 50.153 111.33 50.315 ;
     RECT  112.5 50.161 112.518 50.315 ;
     RECT  70.992 50.315 110.862 50.333 ;
     RECT  112.644 50.431 112.662 50.585 ;
     RECT  70.992 50.333 110.826 50.855 ;
     RECT  71.316 50.855 110.826 51.125 ;
     RECT  71.424 51.125 110.826 51.629 ;
     RECT  71.424 51.629 110.754 51.773 ;
     RECT  71.424 51.773 109.35 51.809 ;
     RECT  110.415 51.773 110.754 52.411 ;
     RECT  71.532 51.809 109.35 52.493 ;
     RECT  72.144 52.493 109.35 52.825 ;
     RECT  72.144 52.825 109.386 53.015 ;
     RECT  72.324 53.015 109.386 53.401 ;
     RECT  72.324 53.401 109.458 53.555 ;
     RECT  72.468 53.555 109.458 53.825 ;
     RECT  72.615 53.825 109.35 53.933 ;
     RECT  107.928 53.933 109.35 53.969 ;
     RECT  107.928 53.969 108.342 54.059 ;
     RECT  108.18 54.059 108.342 54.131 ;
     RECT  72.615 53.933 107.19 54.329 ;
     RECT  108.216 54.131 108.342 55.183 ;
     RECT  73.872 54.329 107.19 55.409 ;
     RECT  73.872 55.409 73.89 55.445 ;
     RECT  74.808 55.409 107.19 55.723 ;
     RECT  74.808 55.723 107.226 56.219 ;
     RECT  74.808 56.219 75.114 56.489 ;
     RECT  74.808 56.489 74.826 56.525 ;
     RECT  76.032 56.219 107.226 56.533 ;
     RECT  108 55.183 108.342 56.533 ;
     RECT  76.032 56.533 108.342 56.759 ;
     RECT  109.332 53.969 109.35 56.779 ;
     RECT  76.968 56.759 108.342 56.911 ;
     RECT  109.332 56.779 109.494 56.911 ;
     RECT  76.032 56.759 76.194 57.001 ;
     RECT  76.968 56.911 109.494 57.029 ;
     RECT  75.96 57.001 76.194 57.053 ;
     RECT  76.032 57.053 76.194 57.299 ;
     RECT  78.015 57.029 109.494 57.299 ;
     RECT  76.968 57.029 77.166 57.335 ;
     RECT  78.015 57.299 78.39 57.335 ;
     RECT  76.968 57.335 77.058 57.569 ;
     RECT  79.704 57.299 109.494 57.569 ;
     RECT  76.968 57.569 76.986 57.605 ;
     RECT  79.704 57.569 79.722 57.605 ;
     RECT  80.856 57.569 109.494 57.839 ;
     RECT  110.415 52.411 110.826 57.883 ;
     RECT  110.415 57.883 110.862 57.991 ;
     RECT  80.856 57.839 81.234 58.109 ;
     RECT  82.548 57.839 109.494 58.145 ;
     RECT  83.232 58.145 109.494 58.171 ;
     RECT  110.415 57.991 110.898 58.219 ;
     RECT  83.232 58.171 109.53 58.829 ;
     RECT  83.376 58.829 109.53 58.891 ;
     RECT  83.376 58.891 109.566 58.955 ;
     RECT  82.476 58.987 82.494 59.773 ;
     RECT  83.415 58.955 109.566 59.773 ;
     RECT  82.476 59.773 109.566 60.035 ;
     RECT  110.415 58.219 110.97 60.655 ;
     RECT  84.492 60.035 109.566 60.952 ;
     RECT  110.34 60.655 110.97 60.952 ;
     RECT  112.068 60.961 112.086 61.195 ;
     RECT  82.476 60.035 83.697 61.243 ;
     RECT  84.492 60.952 110.97 61.243 ;
     RECT  117.324 61.195 117.774 61.501 ;
     RECT  132.015 2.413 132.297 61.501 ;
     RECT  111.996 61.195 112.842 61.735 ;
     RECT  115.815 2.413 116.097 61.735 ;
     RECT  117 61.501 117.918 61.735 ;
     RECT  132.015 61.501 132.462 61.735 ;
     RECT  115.815 61.735 119.07 61.897 ;
     RECT  82.476 61.243 110.97 62.041 ;
     RECT  111.96 61.735 113.85 62.041 ;
     RECT  115.815 61.897 119.106 62.041 ;
     RECT  121.215 2.413 121.497 62.041 ;
     RECT  129.348 61.897 129.366 62.041 ;
     RECT  131.256 61.735 132.786 62.041 ;
     RECT  82.476 62.041 114.21 62.275 ;
     RECT  115.092 62.041 122.31 62.275 ;
     RECT  129.024 62.041 133.686 62.275 ;
     RECT  2.415 46.103 2.697 62.387 ;
     RECT  7.815 2.413 8.097 62.387 ;
     RECT  13.215 45.968 13.497 62.387 ;
     RECT  18.615 2.413 18.897 62.387 ;
     RECT  24.015 45.965 24.297 62.387 ;
     RECT  29.415 45.995 29.697 62.387 ;
     RECT  34.815 45.995 35.097 62.387 ;
     RECT  40.215 46.877 40.497 62.387 ;
     RECT  45.615 2.413 45.897 62.387 ;
     RECT  51.015 47.183 51.297 62.387 ;
     RECT  56.415 47.345 56.697 62.387 ;
     RECT  61.815 2.413 62.097 62.387 ;
     RECT  67.215 48.569 67.497 62.387 ;
     RECT  72.615 54.329 72.897 62.387 ;
     RECT  78.015 57.335 78.297 62.387 ;
     RECT  126.615 2.413 126.897 62.387 ;
     RECT  137.415 2.413 137.697 62.387 ;
     RECT  142.815 2.413 143.097 62.387 ;
     RECT  148.215 2.413 148.497 62.387 ;
     RECT  153.615 2.413 153.897 62.387 ;
     RECT  159.015 2.413 159.297 62.387 ;
     RECT  164.415 2.413 164.697 62.387 ;
     RECT  169.815 2.413 170.097 62.387 ;
     RECT  175.215 2.413 175.497 62.387 ;
     RECT  180.615 2.413 180.897 62.387 ;
     RECT  82.44 62.275 123.066 62.429 ;
     RECT  93.168 62.429 95.238 62.465 ;
     RECT  93.204 62.465 95.238 62.477 ;
     RECT  96.912 62.429 123.066 62.581 ;
     RECT  128.268 62.275 135.126 62.581 ;
     RECT  93.204 62.477 95.13 62.621 ;
     RECT  2.415 62.387 2.505 62.657 ;
     RECT  7.815 62.387 7.905 62.657 ;
     RECT  13.215 62.387 13.305 62.657 ;
     RECT  18.615 62.387 18.705 62.657 ;
     RECT  24.015 62.387 24.105 62.657 ;
     RECT  29.415 62.387 29.505 62.657 ;
     RECT  34.815 62.387 34.905 62.657 ;
     RECT  40.215 62.387 40.305 62.657 ;
     RECT  45.615 62.387 45.705 62.657 ;
     RECT  51.015 62.387 51.105 62.657 ;
     RECT  56.415 62.387 56.505 62.657 ;
     RECT  61.815 62.387 61.905 62.657 ;
     RECT  67.215 62.387 67.305 62.657 ;
     RECT  72.615 62.387 72.705 62.657 ;
     RECT  78.015 62.387 78.105 62.657 ;
     RECT  126.615 62.387 126.705 62.657 ;
     RECT  137.415 62.387 137.505 62.657 ;
     RECT  142.815 62.387 142.905 62.657 ;
     RECT  148.215 62.387 148.305 62.657 ;
     RECT  153.615 62.387 153.705 62.657 ;
     RECT  159.015 62.387 159.105 62.657 ;
     RECT  164.415 62.387 164.505 62.657 ;
     RECT  169.815 62.387 169.905 62.657 ;
     RECT  175.215 62.387 175.305 62.657 ;
     RECT  180.615 62.387 180.705 62.657 ;
     RECT  93.204 62.621 95.022 62.717 ;
     RECT  93.204 62.717 94.77 62.735 ;
     RECT  82.44 62.429 92.394 62.771 ;
     RECT  82.44 62.771 92.178 62.807 ;
     RECT  128.268 62.581 135.234 62.807 ;
     RECT  82.584 62.807 92.178 62.813 ;
     RECT  82.584 62.813 91.926 62.879 ;
     RECT  93.204 62.735 94.374 63.245 ;
     RECT  96.912 62.581 123.102 63.293 ;
     RECT  128.34 62.807 135.234 63.293 ;
     RECT  93.6 63.245 94.374 63.389 ;
     RECT  82.62 62.879 91.926 63.581 ;
     RECT  93.744 63.389 94.374 63.581 ;
     RECT  83.088 63.581 91.926 63.629 ;
     RECT  83.088 63.629 83.142 63.653 ;
     RECT  83.88 63.629 91.926 63.677 ;
     RECT  128.34 63.293 135.09 63.821 ;
     RECT  93.78 63.581 94.374 63.869 ;
     RECT  83.952 63.677 91.926 63.883 ;
     RECT  83.952 63.883 91.998 63.887 ;
     RECT  97.236 63.293 123.102 63.917 ;
     RECT  83.988 63.887 91.998 63.959 ;
     RECT  83.988 63.959 84.366 64.049 ;
     RECT  85.284 63.959 91.998 64.121 ;
     RECT  85.284 64.121 86.67 64.193 ;
     RECT  97.236 63.917 110.142 64.267 ;
     RECT  87.444 64.121 91.998 64.363 ;
     RECT  85.284 64.193 86.382 64.445 ;
     RECT  94.356 63.869 94.374 64.507 ;
     RECT  83.988 64.049 84.294 64.541 ;
     RECT  93.456 64.459 93.474 64.555 ;
     RECT  94.356 64.507 95.094 64.555 ;
     RECT  96.048 64.411 96.066 64.555 ;
     RECT  96.804 64.267 110.142 64.555 ;
     RECT  94.356 64.555 110.142 64.589 ;
     RECT  83.988 64.541 84.006 64.637 ;
     RECT  85.932 64.445 86.382 64.637 ;
     RECT  87.444 64.363 92.142 64.637 ;
     RECT  92.916 64.555 93.474 64.637 ;
     RECT  86.112 64.637 86.382 64.661 ;
     RECT  86.364 64.661 86.382 64.685 ;
     RECT  92.916 64.637 92.934 64.685 ;
     RECT  94.356 64.589 96.462 64.685 ;
     RECT  97.236 64.589 110.142 64.685 ;
     RECT  111.312 63.917 123.102 64.685 ;
     RECT  128.34 63.821 133.902 64.685 ;
     RECT  96.444 64.685 96.462 64.733 ;
     RECT  97.236 64.685 108.81 64.733 ;
     RECT  109.548 64.685 110.142 64.733 ;
     RECT  83.124 63.653 83.142 64.769 ;
     RECT  109.548 64.733 109.566 64.769 ;
     RECT  111.564 64.685 113.958 64.763 ;
     RECT  111.564 64.763 111.636 64.769 ;
     RECT  111.654 64.763 111.708 64.769 ;
     RECT  111.726 64.763 111.78 64.769 ;
     RECT  111.798 64.763 111.852 64.769 ;
     RECT  111.87 64.763 111.924 64.769 ;
     RECT  111.942 64.763 111.996 64.769 ;
     RECT  112.014 64.763 112.068 64.769 ;
     RECT  112.086 64.763 112.14 64.769 ;
     RECT  112.158 64.763 112.212 64.769 ;
     RECT  112.23 64.763 112.284 64.769 ;
     RECT  112.302 64.763 112.356 64.769 ;
     RECT  112.374 64.763 112.428 64.769 ;
     RECT  112.446 64.763 112.5 64.769 ;
     RECT  112.518 64.763 112.572 64.769 ;
     RECT  112.59 64.763 112.644 64.769 ;
     RECT  112.662 64.763 112.716 64.769 ;
     RECT  112.734 64.763 112.788 64.769 ;
     RECT  112.806 64.763 112.86 64.769 ;
     RECT  112.878 64.763 112.932 64.769 ;
     RECT  112.95 64.763 113.004 64.769 ;
     RECT  113.022 64.763 113.076 64.769 ;
     RECT  113.094 64.763 113.148 64.769 ;
     RECT  113.166 64.763 113.22 64.769 ;
     RECT  113.238 64.763 113.292 64.769 ;
     RECT  113.31 64.763 113.364 64.769 ;
     RECT  113.382 64.763 113.436 64.769 ;
     RECT  113.454 64.763 113.508 64.769 ;
     RECT  113.526 64.763 113.58 64.769 ;
     RECT  113.598 64.763 113.652 64.769 ;
     RECT  113.67 64.763 113.724 64.769 ;
     RECT  113.742 64.763 113.796 64.769 ;
     RECT  113.814 64.763 113.868 64.769 ;
     RECT  113.886 64.763 113.958 64.769 ;
     RECT  87.444 64.637 91.998 64.763 ;
     RECT  87.462 64.763 87.516 64.781 ;
     RECT  87.534 64.763 87.588 64.781 ;
     RECT  87.606 64.763 87.66 64.781 ;
     RECT  87.678 64.763 87.732 64.781 ;
     RECT  87.75 64.763 87.804 64.781 ;
     RECT  87.822 64.763 87.876 64.781 ;
     RECT  87.894 64.763 87.948 64.781 ;
     RECT  87.966 64.763 88.02 64.781 ;
     RECT  88.038 64.763 88.092 64.781 ;
     RECT  88.11 64.763 88.164 64.781 ;
     RECT  88.182 64.763 88.236 64.781 ;
     RECT  88.254 64.763 88.308 64.781 ;
     RECT  88.326 64.763 88.38 64.781 ;
     RECT  88.398 64.763 88.452 64.781 ;
     RECT  88.47 64.763 88.524 64.781 ;
     RECT  88.542 64.763 88.596 64.781 ;
     RECT  88.614 64.763 88.668 64.781 ;
     RECT  88.686 64.763 88.74 64.781 ;
     RECT  88.758 64.763 88.812 64.781 ;
     RECT  88.83 64.763 88.884 64.781 ;
     RECT  88.902 64.763 88.956 64.781 ;
     RECT  88.974 64.763 89.028 64.781 ;
     RECT  89.046 64.763 89.1 64.781 ;
     RECT  89.118 64.763 89.172 64.781 ;
     RECT  89.19 64.763 89.244 64.781 ;
     RECT  89.262 64.763 89.316 64.781 ;
     RECT  89.334 64.763 89.388 64.781 ;
     RECT  89.406 64.763 89.46 64.781 ;
     RECT  89.478 64.763 89.532 64.781 ;
     RECT  89.55 64.763 89.604 64.781 ;
     RECT  89.622 64.763 89.676 64.781 ;
     RECT  89.694 64.763 89.748 64.781 ;
     RECT  89.766 64.763 89.82 64.781 ;
     RECT  89.838 64.763 89.892 64.781 ;
     RECT  89.91 64.763 89.964 64.781 ;
     RECT  89.982 64.763 90.036 64.781 ;
     RECT  90.054 64.763 90.108 64.781 ;
     RECT  90.126 64.763 90.18 64.781 ;
     RECT  90.198 64.763 90.252 64.781 ;
     RECT  90.27 64.763 90.324 64.781 ;
     RECT  90.342 64.763 90.396 64.781 ;
     RECT  90.414 64.763 90.468 64.781 ;
     RECT  90.486 64.763 90.54 64.781 ;
     RECT  90.558 64.763 90.612 64.781 ;
     RECT  90.63 64.763 90.684 64.781 ;
     RECT  90.702 64.763 90.756 64.781 ;
     RECT  90.774 64.763 90.828 64.781 ;
     RECT  90.846 64.763 90.9 64.781 ;
     RECT  90.918 64.763 90.972 64.781 ;
     RECT  90.99 64.763 91.044 64.781 ;
     RECT  91.062 64.763 91.116 64.781 ;
     RECT  91.134 64.763 91.188 64.781 ;
     RECT  91.206 64.763 91.26 64.781 ;
     RECT  91.278 64.763 91.332 64.781 ;
     RECT  91.35 64.763 91.404 64.781 ;
     RECT  91.422 64.763 91.476 64.781 ;
     RECT  91.494 64.763 91.548 64.781 ;
     RECT  91.566 64.763 91.62 64.781 ;
     RECT  91.638 64.763 91.692 64.781 ;
     RECT  91.71 64.763 91.764 64.781 ;
     RECT  91.782 64.763 91.836 64.781 ;
     RECT  91.854 64.763 91.908 64.781 ;
     RECT  91.926 64.763 91.98 64.781 ;
     RECT  97.236 64.733 108.702 64.763 ;
     RECT  97.254 64.763 97.308 64.781 ;
     RECT  97.326 64.763 97.38 64.781 ;
     RECT  97.398 64.763 97.452 64.781 ;
     RECT  97.47 64.763 97.524 64.781 ;
     RECT  97.542 64.763 97.596 64.781 ;
     RECT  97.614 64.763 97.668 64.781 ;
     RECT  97.686 64.763 97.74 64.781 ;
     RECT  97.758 64.763 97.812 64.781 ;
     RECT  97.83 64.763 97.884 64.781 ;
     RECT  97.902 64.763 97.956 64.781 ;
     RECT  97.974 64.763 98.028 64.781 ;
     RECT  98.046 64.763 98.1 64.781 ;
     RECT  98.118 64.763 98.172 64.781 ;
     RECT  98.19 64.763 98.244 64.781 ;
     RECT  98.262 64.763 98.316 64.781 ;
     RECT  98.334 64.763 98.388 64.781 ;
     RECT  98.406 64.763 98.46 64.781 ;
     RECT  98.478 64.763 98.532 64.781 ;
     RECT  98.55 64.763 98.604 64.781 ;
     RECT  98.622 64.763 98.676 64.781 ;
     RECT  98.694 64.763 98.748 64.781 ;
     RECT  98.766 64.763 98.82 64.781 ;
     RECT  98.838 64.763 98.892 64.781 ;
     RECT  98.91 64.763 98.964 64.781 ;
     RECT  98.982 64.763 99.036 64.781 ;
     RECT  99.054 64.763 99.108 64.781 ;
     RECT  99.126 64.763 99.18 64.781 ;
     RECT  99.198 64.763 99.252 64.781 ;
     RECT  99.27 64.763 99.324 64.781 ;
     RECT  99.342 64.763 99.396 64.781 ;
     RECT  99.414 64.763 99.468 64.781 ;
     RECT  99.486 64.763 99.54 64.781 ;
     RECT  99.558 64.763 99.612 64.781 ;
     RECT  99.63 64.763 99.684 64.781 ;
     RECT  99.702 64.763 99.756 64.781 ;
     RECT  99.774 64.763 99.828 64.781 ;
     RECT  99.846 64.763 99.9 64.781 ;
     RECT  99.918 64.763 99.972 64.781 ;
     RECT  99.99 64.763 100.044 64.781 ;
     RECT  100.062 64.763 100.116 64.781 ;
     RECT  100.134 64.763 100.188 64.781 ;
     RECT  100.206 64.763 100.26 64.781 ;
     RECT  100.278 64.763 100.332 64.781 ;
     RECT  100.35 64.763 100.404 64.781 ;
     RECT  100.422 64.763 100.476 64.781 ;
     RECT  100.494 64.763 100.548 64.781 ;
     RECT  100.566 64.763 100.62 64.781 ;
     RECT  100.638 64.763 100.692 64.781 ;
     RECT  100.71 64.763 100.764 64.781 ;
     RECT  100.782 64.763 100.836 64.781 ;
     RECT  100.854 64.763 100.908 64.781 ;
     RECT  100.926 64.763 100.98 64.781 ;
     RECT  100.998 64.763 101.052 64.781 ;
     RECT  101.07 64.763 101.124 64.781 ;
     RECT  101.142 64.763 101.196 64.781 ;
     RECT  101.214 64.763 101.268 64.781 ;
     RECT  101.286 64.763 101.34 64.781 ;
     RECT  101.358 64.763 101.412 64.781 ;
     RECT  101.43 64.763 101.484 64.781 ;
     RECT  101.502 64.763 101.556 64.781 ;
     RECT  101.574 64.763 101.628 64.781 ;
     RECT  101.646 64.763 101.7 64.781 ;
     RECT  101.718 64.763 101.772 64.781 ;
     RECT  101.79 64.763 101.844 64.781 ;
     RECT  101.862 64.763 101.916 64.781 ;
     RECT  101.934 64.763 101.988 64.781 ;
     RECT  102.006 64.763 102.06 64.781 ;
     RECT  102.078 64.763 102.132 64.781 ;
     RECT  102.15 64.763 102.204 64.781 ;
     RECT  102.222 64.763 102.276 64.781 ;
     RECT  102.294 64.763 102.348 64.781 ;
     RECT  102.366 64.763 102.42 64.781 ;
     RECT  102.438 64.763 102.492 64.781 ;
     RECT  102.51 64.763 102.564 64.781 ;
     RECT  102.582 64.763 102.636 64.781 ;
     RECT  102.654 64.763 102.708 64.781 ;
     RECT  102.726 64.763 102.78 64.781 ;
     RECT  102.798 64.763 102.852 64.781 ;
     RECT  102.87 64.763 102.924 64.781 ;
     RECT  102.942 64.763 102.996 64.781 ;
     RECT  103.014 64.763 103.068 64.781 ;
     RECT  103.086 64.763 103.14 64.781 ;
     RECT  103.158 64.763 103.212 64.781 ;
     RECT  103.23 64.763 103.284 64.781 ;
     RECT  103.302 64.763 103.356 64.781 ;
     RECT  103.374 64.763 103.428 64.781 ;
     RECT  103.446 64.763 103.5 64.781 ;
     RECT  103.518 64.763 103.572 64.781 ;
     RECT  103.59 64.763 103.644 64.781 ;
     RECT  103.662 64.763 103.716 64.781 ;
     RECT  103.734 64.763 103.788 64.781 ;
     RECT  103.806 64.763 103.86 64.781 ;
     RECT  103.878 64.763 103.932 64.781 ;
     RECT  103.95 64.763 104.004 64.781 ;
     RECT  104.022 64.763 104.076 64.781 ;
     RECT  104.094 64.763 104.148 64.781 ;
     RECT  104.166 64.763 104.22 64.781 ;
     RECT  104.238 64.763 104.292 64.781 ;
     RECT  104.31 64.763 104.364 64.781 ;
     RECT  104.382 64.763 104.436 64.781 ;
     RECT  104.454 64.763 104.508 64.781 ;
     RECT  104.526 64.763 104.58 64.781 ;
     RECT  104.598 64.763 104.652 64.781 ;
     RECT  104.67 64.763 104.724 64.781 ;
     RECT  104.742 64.763 104.796 64.781 ;
     RECT  104.814 64.763 104.868 64.781 ;
     RECT  104.886 64.763 104.94 64.781 ;
     RECT  104.958 64.763 105.012 64.781 ;
     RECT  105.03 64.763 105.084 64.781 ;
     RECT  105.102 64.763 105.156 64.781 ;
     RECT  105.174 64.763 105.228 64.781 ;
     RECT  105.246 64.763 105.3 64.781 ;
     RECT  105.318 64.763 105.372 64.781 ;
     RECT  105.39 64.763 105.444 64.781 ;
     RECT  105.462 64.763 105.516 64.781 ;
     RECT  105.534 64.763 105.588 64.781 ;
     RECT  105.606 64.763 105.66 64.781 ;
     RECT  105.678 64.763 105.732 64.781 ;
     RECT  105.75 64.763 105.804 64.781 ;
     RECT  105.822 64.763 105.876 64.781 ;
     RECT  105.894 64.763 105.948 64.781 ;
     RECT  105.966 64.763 106.02 64.781 ;
     RECT  106.038 64.763 106.092 64.781 ;
     RECT  106.11 64.763 106.164 64.781 ;
     RECT  106.182 64.763 106.236 64.781 ;
     RECT  106.254 64.763 106.308 64.781 ;
     RECT  106.326 64.763 106.38 64.781 ;
     RECT  106.398 64.763 106.452 64.781 ;
     RECT  106.47 64.763 106.524 64.781 ;
     RECT  106.542 64.763 106.596 64.781 ;
     RECT  106.614 64.763 106.668 64.781 ;
     RECT  106.686 64.763 106.74 64.781 ;
     RECT  106.758 64.763 106.812 64.781 ;
     RECT  106.83 64.763 106.884 64.781 ;
     RECT  106.902 64.763 106.956 64.781 ;
     RECT  106.974 64.763 107.028 64.781 ;
     RECT  107.046 64.763 107.1 64.781 ;
     RECT  107.118 64.763 107.172 64.781 ;
     RECT  107.19 64.763 107.244 64.781 ;
     RECT  107.262 64.763 107.316 64.781 ;
     RECT  107.334 64.763 107.388 64.781 ;
     RECT  107.406 64.763 107.46 64.781 ;
     RECT  107.478 64.763 107.532 64.781 ;
     RECT  107.55 64.763 107.604 64.781 ;
     RECT  107.622 64.763 107.676 64.781 ;
     RECT  107.694 64.763 107.748 64.781 ;
     RECT  107.766 64.763 107.82 64.781 ;
     RECT  107.838 64.763 107.892 64.781 ;
     RECT  107.91 64.763 107.964 64.781 ;
     RECT  107.982 64.763 108.036 64.781 ;
     RECT  108.054 64.763 108.108 64.781 ;
     RECT  108.126 64.763 108.18 64.781 ;
     RECT  108.198 64.763 108.252 64.781 ;
     RECT  108.27 64.763 108.324 64.781 ;
     RECT  108.342 64.763 108.396 64.781 ;
     RECT  108.414 64.763 108.468 64.781 ;
     RECT  108.486 64.763 108.54 64.781 ;
     RECT  108.558 64.763 108.612 64.781 ;
     RECT  108.63 64.763 108.684 64.781 ;
     RECT  111.654 64.769 111.708 64.781 ;
     RECT  111.726 64.769 111.78 64.781 ;
     RECT  111.798 64.769 111.852 64.781 ;
     RECT  111.87 64.769 111.924 64.781 ;
     RECT  111.942 64.769 111.996 64.781 ;
     RECT  112.014 64.769 112.068 64.781 ;
     RECT  112.086 64.769 112.14 64.781 ;
     RECT  112.158 64.769 112.212 64.781 ;
     RECT  112.23 64.769 112.284 64.781 ;
     RECT  112.302 64.769 112.356 64.781 ;
     RECT  112.374 64.769 112.428 64.781 ;
     RECT  112.446 64.769 112.5 64.781 ;
     RECT  112.518 64.769 112.572 64.781 ;
     RECT  112.59 64.769 112.644 64.781 ;
     RECT  112.662 64.769 112.716 64.781 ;
     RECT  112.734 64.769 112.788 64.781 ;
     RECT  112.806 64.769 112.86 64.781 ;
     RECT  112.878 64.769 112.932 64.781 ;
     RECT  112.95 64.769 113.004 64.781 ;
     RECT  113.022 64.769 113.076 64.781 ;
     RECT  113.094 64.769 113.148 64.781 ;
     RECT  113.166 64.769 113.22 64.781 ;
     RECT  113.238 64.769 113.292 64.781 ;
     RECT  113.31 64.769 113.364 64.781 ;
     RECT  113.382 64.769 113.436 64.781 ;
     RECT  113.454 64.769 113.508 64.781 ;
     RECT  113.526 64.769 113.58 64.781 ;
     RECT  113.598 64.769 113.652 64.781 ;
     RECT  113.67 64.769 113.724 64.781 ;
     RECT  113.742 64.769 113.796 64.781 ;
     RECT  113.814 64.769 113.868 64.781 ;
     RECT  116.244 64.685 123.102 64.763 ;
     RECT  116.262 64.763 116.316 64.781 ;
     RECT  116.334 64.763 116.388 64.781 ;
     RECT  116.406 64.763 116.46 64.781 ;
     RECT  116.478 64.763 116.532 64.781 ;
     RECT  116.55 64.763 116.604 64.781 ;
     RECT  116.622 64.763 116.676 64.781 ;
     RECT  116.694 64.763 116.748 64.781 ;
     RECT  116.766 64.763 116.82 64.781 ;
     RECT  116.838 64.763 116.892 64.781 ;
     RECT  116.91 64.763 116.964 64.781 ;
     RECT  116.982 64.763 117.036 64.781 ;
     RECT  117.054 64.763 117.108 64.781 ;
     RECT  117.126 64.763 117.18 64.781 ;
     RECT  117.198 64.763 117.252 64.781 ;
     RECT  117.27 64.763 117.324 64.781 ;
     RECT  117.342 64.763 117.396 64.781 ;
     RECT  117.414 64.763 117.468 64.781 ;
     RECT  117.486 64.763 117.54 64.781 ;
     RECT  117.558 64.763 117.612 64.781 ;
     RECT  117.63 64.763 117.684 64.781 ;
     RECT  117.702 64.763 117.756 64.781 ;
     RECT  117.774 64.763 117.828 64.781 ;
     RECT  117.846 64.763 117.9 64.781 ;
     RECT  117.918 64.763 117.972 64.781 ;
     RECT  117.99 64.763 118.044 64.781 ;
     RECT  118.062 64.763 118.116 64.781 ;
     RECT  118.134 64.763 118.188 64.781 ;
     RECT  118.206 64.763 118.26 64.781 ;
     RECT  118.278 64.763 118.332 64.781 ;
     RECT  118.35 64.763 118.404 64.781 ;
     RECT  118.422 64.763 118.476 64.781 ;
     RECT  118.494 64.763 118.548 64.781 ;
     RECT  118.566 64.763 118.62 64.781 ;
     RECT  118.638 64.763 118.692 64.781 ;
     RECT  118.71 64.763 118.764 64.781 ;
     RECT  118.782 64.763 118.836 64.781 ;
     RECT  118.854 64.763 118.908 64.781 ;
     RECT  118.926 64.763 118.98 64.781 ;
     RECT  118.998 64.763 119.052 64.781 ;
     RECT  119.07 64.763 119.124 64.781 ;
     RECT  119.142 64.763 119.196 64.781 ;
     RECT  119.214 64.763 119.268 64.781 ;
     RECT  119.286 64.763 119.34 64.781 ;
     RECT  119.358 64.763 119.412 64.781 ;
     RECT  119.43 64.763 119.484 64.781 ;
     RECT  119.502 64.763 119.556 64.781 ;
     RECT  119.574 64.763 119.628 64.781 ;
     RECT  119.646 64.763 119.7 64.781 ;
     RECT  119.718 64.763 119.772 64.781 ;
     RECT  119.79 64.763 119.844 64.781 ;
     RECT  119.862 64.763 119.916 64.781 ;
     RECT  119.934 64.763 119.988 64.781 ;
     RECT  120.006 64.763 120.06 64.781 ;
     RECT  120.078 64.763 120.132 64.781 ;
     RECT  120.15 64.763 120.204 64.781 ;
     RECT  120.222 64.763 120.276 64.781 ;
     RECT  120.294 64.763 120.348 64.781 ;
     RECT  120.366 64.763 120.42 64.781 ;
     RECT  120.438 64.763 120.492 64.781 ;
     RECT  120.51 64.763 120.564 64.781 ;
     RECT  120.582 64.763 120.636 64.781 ;
     RECT  120.654 64.763 120.708 64.781 ;
     RECT  120.726 64.763 120.78 64.781 ;
     RECT  120.798 64.763 120.852 64.781 ;
     RECT  120.87 64.763 120.924 64.781 ;
     RECT  120.942 64.763 120.996 64.781 ;
     RECT  121.014 64.763 121.068 64.781 ;
     RECT  121.086 64.763 121.14 64.781 ;
     RECT  121.158 64.763 121.212 64.781 ;
     RECT  121.23 64.763 121.284 64.781 ;
     RECT  121.302 64.763 121.356 64.781 ;
     RECT  121.374 64.763 121.428 64.781 ;
     RECT  121.446 64.763 121.5 64.781 ;
     RECT  121.518 64.763 121.572 64.781 ;
     RECT  121.59 64.763 121.644 64.781 ;
     RECT  121.662 64.763 121.716 64.781 ;
     RECT  121.734 64.763 121.788 64.781 ;
     RECT  121.806 64.763 121.86 64.781 ;
     RECT  121.878 64.763 121.932 64.781 ;
     RECT  121.95 64.763 122.004 64.781 ;
     RECT  122.022 64.763 122.076 64.781 ;
     RECT  122.094 64.763 122.148 64.781 ;
     RECT  122.166 64.763 122.22 64.781 ;
     RECT  122.238 64.763 122.292 64.781 ;
     RECT  122.31 64.763 122.364 64.781 ;
     RECT  122.382 64.763 122.436 64.781 ;
     RECT  122.454 64.763 122.508 64.781 ;
     RECT  122.526 64.763 122.58 64.781 ;
     RECT  122.598 64.763 122.652 64.781 ;
     RECT  122.67 64.763 122.724 64.781 ;
     RECT  122.742 64.763 122.796 64.781 ;
     RECT  122.814 64.763 122.868 64.781 ;
     RECT  122.886 64.763 122.94 64.781 ;
     RECT  122.958 64.763 123.012 64.781 ;
     RECT  123.03 64.763 123.084 64.781 ;
     RECT  128.34 64.685 132.894 64.763 ;
     RECT  128.358 64.763 128.412 64.781 ;
     RECT  128.43 64.763 128.484 64.781 ;
     RECT  128.502 64.763 128.556 64.781 ;
     RECT  128.574 64.763 128.628 64.781 ;
     RECT  128.646 64.763 128.7 64.781 ;
     RECT  128.718 64.763 128.772 64.781 ;
     RECT  128.79 64.763 128.844 64.781 ;
     RECT  128.862 64.763 128.916 64.781 ;
     RECT  128.934 64.763 128.988 64.781 ;
     RECT  129.006 64.763 129.06 64.781 ;
     RECT  129.078 64.763 129.132 64.781 ;
     RECT  129.15 64.763 129.204 64.781 ;
     RECT  129.222 64.763 129.276 64.781 ;
     RECT  129.294 64.763 129.348 64.781 ;
     RECT  129.366 64.763 129.42 64.781 ;
     RECT  129.438 64.763 129.492 64.781 ;
     RECT  129.51 64.763 129.564 64.781 ;
     RECT  129.582 64.763 129.636 64.781 ;
     RECT  129.654 64.763 129.708 64.781 ;
     RECT  129.726 64.763 129.78 64.781 ;
     RECT  129.798 64.763 129.852 64.781 ;
     RECT  129.87 64.763 129.924 64.781 ;
     RECT  129.942 64.763 129.996 64.781 ;
     RECT  130.014 64.763 130.068 64.781 ;
     RECT  130.086 64.763 130.14 64.781 ;
     RECT  130.158 64.763 130.212 64.781 ;
     RECT  130.23 64.763 130.284 64.781 ;
     RECT  130.302 64.763 130.356 64.781 ;
     RECT  130.374 64.763 130.428 64.781 ;
     RECT  130.446 64.763 130.5 64.781 ;
     RECT  130.518 64.763 130.572 64.781 ;
     RECT  130.59 64.763 130.644 64.781 ;
     RECT  130.662 64.763 130.716 64.781 ;
     RECT  130.734 64.763 130.788 64.781 ;
     RECT  130.806 64.763 130.86 64.781 ;
     RECT  130.878 64.763 130.932 64.781 ;
     RECT  130.95 64.763 131.004 64.781 ;
     RECT  131.022 64.763 131.076 64.781 ;
     RECT  131.094 64.763 131.148 64.781 ;
     RECT  131.166 64.763 131.22 64.781 ;
     RECT  131.238 64.763 131.292 64.781 ;
     RECT  131.31 64.763 131.364 64.781 ;
     RECT  131.382 64.763 131.436 64.781 ;
     RECT  131.454 64.763 131.508 64.781 ;
     RECT  131.526 64.763 131.58 64.781 ;
     RECT  131.598 64.763 131.652 64.781 ;
     RECT  131.67 64.763 131.724 64.781 ;
     RECT  131.742 64.763 131.796 64.781 ;
     RECT  131.814 64.763 131.868 64.781 ;
     RECT  131.886 64.763 131.94 64.781 ;
     RECT  131.958 64.763 132.012 64.781 ;
     RECT  132.03 64.763 132.084 64.781 ;
     RECT  132.102 64.763 132.156 64.781 ;
     RECT  132.174 64.763 132.228 64.781 ;
     RECT  132.246 64.763 132.3 64.781 ;
     RECT  132.318 64.763 132.372 64.781 ;
     RECT  132.39 64.763 132.444 64.781 ;
     RECT  132.462 64.763 132.516 64.781 ;
     RECT  132.534 64.763 132.588 64.781 ;
     RECT  132.606 64.763 132.66 64.781 ;
     RECT  132.678 64.763 132.732 64.781 ;
     RECT  132.75 64.763 132.804 64.781 ;
     RECT  132.822 64.763 132.876 64.781 ;
    LAYER M4 ;
     RECT  0.084 44.88 0.133 44.904 ;
     RECT  0.06 44.904 0.133 44.976 ;
     RECT  0.084 44.976 0.133 45 ;
     RECT  0.06 45 0.133 45.072 ;
     RECT  0.084 45.072 0.133 45.096 ;
     RECT  0.06 45.096 0.133 45.168 ;
     RECT  0.084 45.168 0.133 45.192 ;
     RECT  0.133 44.88 0.227 45.624 ;
     RECT  0.181 29.808 2.408 29.832 ;
     RECT  0.227 44.976 2.408 45.624 ;
     RECT  2.408 2.148 2.512 62.652 ;
     RECT  2.512 2.418 2.704 62.382 ;
     RECT  2.704 44.976 3.877 45.576 ;
     RECT  3.877 44.976 5.753 46.056 ;
     RECT  2.704 29.808 7.808 29.832 ;
     RECT  5.753 44.976 7.808 45.96 ;
     RECT  7.808 2.148 7.912 62.652 ;
     RECT  7.912 2.418 8.104 62.382 ;
     RECT  8.104 29.808 13.208 29.832 ;
     RECT  8.104 44.976 13.208 45.96 ;
     RECT  13.208 2.148 13.312 62.652 ;
     RECT  13.312 2.418 13.504 62.382 ;
     RECT  13.504 29.808 18.608 29.832 ;
     RECT  13.504 44.976 18.608 45.96 ;
     RECT  18.608 2.148 18.712 62.652 ;
     RECT  18.712 2.418 18.904 62.382 ;
     RECT  18.904 29.808 24.008 29.832 ;
     RECT  18.904 44.976 24.008 45.96 ;
     RECT  24.008 2.148 24.112 62.652 ;
     RECT  24.112 2.418 24.304 62.382 ;
     RECT  24.304 29.808 29.408 29.832 ;
     RECT  24.304 44.976 29.408 45.768 ;
     RECT  29.408 2.148 29.512 62.652 ;
     RECT  29.512 2.418 29.704 62.382 ;
     RECT  29.704 44.976 34.693 45.768 ;
     RECT  29.704 29.808 34.808 29.832 ;
     RECT  34.693 44.976 34.808 46.536 ;
     RECT  34.808 2.148 34.912 62.652 ;
     RECT  34.912 2.418 35.104 62.382 ;
     RECT  35.104 44.976 39.121 46.536 ;
     RECT  35.104 29.808 40.208 29.832 ;
     RECT  39.121 44.976 40.208 46.872 ;
     RECT  40.208 2.148 40.312 62.652 ;
     RECT  40.312 2.418 40.504 62.382 ;
     RECT  40.504 44.976 40.601 46.872 ;
     RECT  40.504 29.808 45.608 29.832 ;
     RECT  40.601 44.976 45.608 46.776 ;
     RECT  45.608 2.148 45.712 62.652 ;
     RECT  45.712 2.418 45.904 62.382 ;
     RECT  45.904 44.976 47.729 46.776 ;
     RECT  47.729 46.032 50.389 46.776 ;
     RECT  45.904 29.808 51.008 29.832 ;
     RECT  47.729 44.976 51.008 45 ;
     RECT  50.389 46.032 51.008 47.112 ;
     RECT  51.008 2.148 51.112 62.652 ;
     RECT  51.112 2.418 51.304 62.382 ;
     RECT  51.304 46.752 53.749 47.112 ;
     RECT  53.749 46.656 53.795 47.112 ;
     RECT  53.795 46.656 53.836 46.968 ;
     RECT  51.304 29.808 56.408 29.832 ;
     RECT  51.304 44.976 56.408 45 ;
     RECT  53.836 46.752 56.408 46.968 ;
     RECT  56.408 2.148 56.512 62.652 ;
     RECT  56.512 2.418 56.704 62.382 ;
     RECT  56.704 46.752 58.691 46.872 ;
     RECT  58.691 46.752 60.236 46.776 ;
     RECT  58.645 47.952 60.277 47.976 ;
     RECT  60.236 46.752 60.323 46.968 ;
     RECT  56.704 29.808 61.808 29.832 ;
     RECT  56.704 44.976 61.808 45 ;
     RECT  60.323 46.752 61.808 46.776 ;
     RECT  60.277 47.952 61.808 48.696 ;
     RECT  61.808 2.148 61.912 62.652 ;
     RECT  61.912 2.418 62.104 62.382 ;
     RECT  62.104 29.808 67.208 29.832 ;
     RECT  62.104 44.976 67.208 45 ;
     RECT  62.104 46.752 67.208 46.776 ;
     RECT  62.104 47.952 67.208 48.552 ;
     RECT  67.208 2.148 67.312 62.652 ;
     RECT  67.312 2.418 67.504 62.382 ;
     RECT  67.504 9.216 68.677 9.24 ;
     RECT  68.677 9.216 68.717 9.48 ;
     RECT  67.504 46.752 68.965 46.776 ;
     RECT  68.965 46.752 69.005 46.872 ;
     RECT  68.893 10.512 69.212 10.536 ;
     RECT  69.212 10.512 69.299 11.448 ;
     RECT  68.717 9.456 69.541 9.48 ;
     RECT  69.299 10.512 69.541 10.824 ;
     RECT  69.541 9.456 69.581 10.824 ;
     RECT  69.253 30.96 69.788 30.984 ;
     RECT  69.325 32.688 69.788 32.712 ;
     RECT  69.788 30.96 69.875 33.288 ;
     RECT  69.005 46.848 70.117 46.872 ;
     RECT  67.504 47.952 70.117 48.552 ;
     RECT  68.965 8.4 70.157 8.424 ;
     RECT  70.045 14.832 70.157 15.384 ;
     RECT  68.929 12.48 70.225 12.504 ;
     RECT  70.225 12 70.265 12.504 ;
     RECT  69.875 30.96 70.333 30.984 ;
     RECT  69.757 19.632 70.364 19.656 ;
     RECT  70.333 30.816 70.373 30.984 ;
     RECT  70.364 19.632 70.451 20.568 ;
     RECT  70.405 18.192 70.604 18.216 ;
     RECT  70.604 17.52 70.625 18.216 ;
     RECT  70.451 19.632 70.645 19.656 ;
     RECT  70.625 17.52 70.691 17.544 ;
     RECT  69.581 9.504 70.693 10.824 ;
     RECT  69.469 13.536 70.693 13.56 ;
     RECT  67.504 44.976 70.693 45 ;
     RECT  70.117 16.416 70.697 16.44 ;
     RECT  70.693 8.544 70.729 10.824 ;
     RECT  70.265 12 70.729 12.024 ;
     RECT  70.693 13.392 70.733 13.56 ;
     RECT  70.117 46.848 70.741 48.552 ;
     RECT  70.729 8.544 70.769 12.024 ;
     RECT  70.621 39.36 70.789 39.384 ;
     RECT  70.009 26.784 70.873 26.808 ;
     RECT  70.789 38.016 70.877 39.384 ;
     RECT  70.741 46.848 70.877 48.984 ;
     RECT  67.504 29.808 70.885 29.832 ;
     RECT  70.157 14.832 70.913 14.856 ;
     RECT  70.585 50.112 70.981 50.136 ;
     RECT  68.713 23.376 71.084 23.4 ;
     RECT  69.973 7.344 71.129 7.368 ;
     RECT  71.084 23.376 71.171 24.12 ;
     RECT  70.877 47.952 71.261 48.984 ;
     RECT  70.981 50.112 71.261 50.808 ;
     RECT  71.261 47.952 71.372 50.808 ;
     RECT  70.873 26.784 71.377 27.624 ;
     RECT  70.885 29.376 71.413 29.832 ;
     RECT  70.333 42.144 71.417 42.168 ;
     RECT  71.171 23.376 71.449 23.4 ;
     RECT  71.372 47.952 71.459 51.384 ;
     RECT  70.769 8.544 71.485 11.544 ;
     RECT  70.733 13.392 71.593 13.416 ;
     RECT  69.875 32.352 71.629 32.376 ;
     RECT  71.377 26.736 71.653 27.624 ;
     RECT  70.645 18.816 71.66 19.656 ;
     RECT  71.221 34.608 71.729 34.632 ;
     RECT  71.653 26.688 71.737 27.624 ;
     RECT  71.66 18.576 71.749 19.656 ;
     RECT  71.629 31.92 71.749 32.376 ;
     RECT  71.593 13.104 71.845 13.416 ;
     RECT  70.729 21.504 71.881 21.528 ;
     RECT  70.877 38.688 71.881 39.384 ;
     RECT  71.077 40.464 71.881 40.488 ;
     RECT  71.881 21.504 71.953 21.72 ;
     RECT  71.809 14.688 72.037 14.712 ;
     RECT  71.737 15.84 72.037 15.864 ;
     RECT  71.485 7.968 72.061 11.544 ;
     RECT  71.845 12.528 72.061 13.416 ;
     RECT  71.521 6.384 72.236 6.408 ;
     RECT  72.236 6.192 72.277 6.408 ;
     RECT  71.413 29.04 72.373 29.832 ;
     RECT  70.373 30.816 72.373 30.84 ;
     RECT  71.629 33.552 72.373 33.576 ;
     RECT  71.729 34.608 72.373 34.824 ;
     RECT  72.061 7.968 72.421 13.416 ;
     RECT  72.037 14.688 72.421 15.864 ;
     RECT  71.749 18.576 72.421 19.704 ;
     RECT  71.449 22.752 72.421 23.4 ;
     RECT  71.665 24.72 72.421 24.744 ;
     RECT  71.737 26.208 72.421 27.624 ;
     RECT  72.373 29.04 72.469 30.84 ;
     RECT  70.877 46.848 72.601 46.872 ;
     RECT  71.459 47.952 72.601 50.232 ;
     RECT  72.277 6.192 72.608 6.84 ;
     RECT  72.421 7.968 72.608 15.864 ;
     RECT  72.421 17.664 72.608 20.04 ;
     RECT  71.953 21.504 72.608 21.768 ;
     RECT  72.421 22.752 72.608 27.624 ;
     RECT  72.469 29.04 72.608 30.936 ;
     RECT  71.749 31.92 72.608 32.472 ;
     RECT  72.373 33.552 72.608 34.824 ;
     RECT  71.881 38.688 72.608 40.488 ;
     RECT  72.349 43.296 72.608 43.32 ;
     RECT  70.693 44.736 72.608 45 ;
     RECT  72.601 46.848 72.608 50.232 ;
     RECT  71.459 51.36 72.608 51.384 ;
     RECT  71.521 52.464 72.608 52.488 ;
     RECT  72.608 2.148 72.712 62.652 ;
     RECT  72.712 2.418 72.904 62.382 ;
     RECT  72.904 39.504 73.001 41.016 ;
     RECT  72.904 42 73.073 42.744 ;
     RECT  72.904 46.752 73.145 49.8 ;
     RECT  72.904 16.08 73.397 27.768 ;
     RECT  73.145 46.752 73.433 46.872 ;
     RECT  73.001 39.888 73.469 41.016 ;
     RECT  72.904 28.944 73.505 31.896 ;
     RECT  72.904 32.976 73.619 33.576 ;
     RECT  73.469 39.888 73.763 39.912 ;
     RECT  72.904 4.848 73.897 5.496 ;
     RECT  72.904 6.576 73.897 6.84 ;
     RECT  72.904 7.968 73.897 14.616 ;
     RECT  73.397 21.552 73.909 27.768 ;
     RECT  72.904 54.144 73.964 54.168 ;
     RECT  72.904 44.496 73.969 45 ;
     RECT  73.964 54.144 74.051 54.84 ;
     RECT  73.897 4.848 74.053 6.84 ;
     RECT  73.897 7.968 74.053 14.856 ;
     RECT  73.909 21.552 74.053 27.912 ;
     RECT  73.505 28.944 74.053 29.832 ;
     RECT  73.469 40.992 74.077 41.016 ;
     RECT  73.073 42.144 74.077 42.744 ;
     RECT  74.077 40.992 74.101 42.744 ;
     RECT  73.969 44.496 74.101 45.048 ;
     RECT  73.505 30.912 74.113 31.896 ;
     RECT  73.145 47.952 74.113 49.8 ;
     RECT  72.904 51.264 74.113 52.296 ;
     RECT  74.053 4.704 74.293 14.856 ;
     RECT  73.397 16.08 74.365 20.568 ;
     RECT  74.053 21.552 74.365 29.832 ;
     RECT  74.113 47.952 74.369 52.296 ;
     RECT  72.904 34.704 74.401 35.352 ;
     RECT  74.365 16.08 74.473 29.832 ;
     RECT  74.369 50.256 74.477 52.296 ;
     RECT  72.904 38.16 74.485 38.184 ;
     RECT  74.185 39.36 74.485 39.384 ;
     RECT  72.904 36.336 74.501 37.176 ;
     RECT  74.485 38.16 74.501 39.384 ;
     RECT  74.369 47.952 74.513 49.032 ;
     RECT  74.101 40.992 74.545 45.048 ;
     RECT  74.545 40.464 74.585 45.048 ;
     RECT  74.473 16.032 74.689 29.832 ;
     RECT  74.113 30.912 74.689 31.944 ;
     RECT  74.513 47.952 74.689 48.552 ;
     RECT  74.585 43.344 74.725 45.048 ;
     RECT  73.619 33.024 74.761 33.576 ;
     RECT  74.401 34.56 74.761 35.352 ;
     RECT  74.477 50.256 74.801 51.96 ;
     RECT  74.293 4.704 74.833 14.904 ;
     RECT  74.833 4.704 74.869 15.048 ;
     RECT  74.689 16.032 74.869 31.944 ;
     RECT  74.869 4.704 74.972 31.944 ;
     RECT  74.761 33.024 74.972 35.352 ;
     RECT  74.689 47.856 74.972 48.552 ;
     RECT  74.801 50.256 75.059 51.384 ;
     RECT  74.972 4.704 75.193 35.352 ;
     RECT  75.193 4.512 75.205 35.352 ;
     RECT  74.501 36.336 75.205 39.384 ;
     RECT  74.585 40.464 75.205 42.168 ;
     RECT  75.205 4.512 75.308 42.168 ;
     RECT  73.433 46.752 75.373 46.776 ;
     RECT  74.972 47.808 75.373 48.552 ;
     RECT  75.059 50.256 75.377 50.28 ;
     RECT  75.308 4.272 75.404 42.168 ;
     RECT  75.373 46.752 75.445 48.552 ;
     RECT  75.445 46.656 75.481 48.552 ;
     RECT  75.404 3.36 75.589 42.168 ;
     RECT  74.725 43.344 75.589 45.624 ;
     RECT  75.589 3.36 75.827 45.624 ;
     RECT  74.977 56.4 75.949 56.424 ;
     RECT  75.949 56.4 76.061 57.048 ;
     RECT  76.057 2.208 76.069 2.232 ;
     RECT  75.827 25.056 76.093 45.624 ;
     RECT  75.481 46.656 76.093 49.464 ;
     RECT  76.069 2.064 76.165 2.232 ;
     RECT  75.827 3.36 76.165 23.928 ;
     RECT  76.093 25.056 76.381 49.464 ;
     RECT  75.517 52.464 76.453 52.488 ;
     RECT  74.051 54.144 76.705 54.168 ;
     RECT  76.165 2.064 76.837 23.928 ;
     RECT  76.837 2.064 76.844 23.976 ;
     RECT  76.381 25.056 76.844 50.04 ;
     RECT  76.844 2.064 76.957 50.04 ;
     RECT  76.957 1.968 77.461 50.04 ;
     RECT  77.245 0.48 77.509 0.504 ;
     RECT  77.461 1.968 77.509 50.328 ;
     RECT  77.509 0.48 77.797 50.328 ;
     RECT  76.453 52.272 77.857 52.488 ;
     RECT  77.797 0.24 77.893 50.328 ;
     RECT  77.893 0.24 78.008 50.376 ;
     RECT  77.857 51.936 78.008 52.488 ;
     RECT  76.705 54.144 78.008 54.888 ;
     RECT  76.061 56.64 78.008 57.048 ;
     RECT  78.008 0.24 78.112 62.652 ;
     RECT  78.112 0.24 78.304 62.382 ;
     RECT  78.304 0.24 78.365 54.696 ;
     RECT  78.365 0.24 78.373 54.6 ;
     RECT  78.373 0.192 78.418 54.6 ;
     RECT  78.418 0.096 78.517 54.6 ;
     RECT  78.304 56.736 78.761 57.048 ;
     RECT  78.517 0.144 79.585 54.6 ;
     RECT  79.585 0.144 79.657 55.224 ;
     RECT  78.761 56.976 79.717 57.048 ;
     RECT  79.717 56.976 80.057 57.096 ;
     RECT  79.657 0.144 80.197 55.608 ;
     RECT  80.197 0.096 80.201 55.608 ;
     RECT  80.201 50.112 80.387 55.608 ;
     RECT  80.057 57.024 80.845 57.096 ;
     RECT  80.387 50.832 81.061 55.608 ;
     RECT  81.061 50.832 81.109 55.992 ;
     RECT  80.845 57.024 81.109 57.624 ;
     RECT  80.201 0.096 81.253 49.128 ;
     RECT  81.109 50.832 81.289 57.624 ;
     RECT  81.253 0.096 81.347 49.656 ;
     RECT  81.289 50.832 81.493 57.528 ;
     RECT  81.347 0.096 81.641 0.552 ;
     RECT  81.493 50.64 81.683 57.528 ;
     RECT  81.347 1.728 81.692 49.656 ;
     RECT  81.683 50.64 81.692 57.48 ;
     RECT  81.692 1.728 81.893 57.48 ;
     RECT  81.641 0.096 82.753 0.456 ;
     RECT  82.681 62.976 82.789 63 ;
     RECT  82.753 61.92 82.861 61.944 ;
     RECT  82.789 62.976 82.933 63.528 ;
     RECT  82.465 58.992 83.029 59.016 ;
     RECT  82.933 62.928 83.041 63.528 ;
     RECT  81.893 1.728 83.117 57.432 ;
     RECT  82.753 0.096 83.123 0.6 ;
     RECT  82.861 61.584 83.173 61.944 ;
     RECT  83.029 58.944 83.18 59.016 ;
     RECT  83.18 58.8 83.221 59.016 ;
     RECT  83.041 62.928 83.365 63.576 ;
     RECT  83.117 1.968 83.401 57.432 ;
     RECT  83.221 58.416 83.401 59.016 ;
     RECT  83.401 1.968 83.408 59.016 ;
     RECT  83.269 60 83.408 60.024 ;
     RECT  83.173 61.152 83.408 61.944 ;
     RECT  83.365 62.928 83.408 63.624 ;
     RECT  83.408 1.968 83.836 63.624 ;
     RECT  83.836 2.016 83.869 63.624 ;
     RECT  83.869 2.016 83.977 63.672 ;
     RECT  83.123 0.096 83.987 0.312 ;
     RECT  83.977 2.016 84.275 64.632 ;
     RECT  83.987 0.096 85.021 0.264 ;
     RECT  85.021 0.096 85.093 0.312 ;
     RECT  85.093 0.096 85.345 0.36 ;
     RECT  85.345 0.096 85.525 0.6 ;
     RECT  84.275 2.256 85.525 64.632 ;
     RECT  85.525 0.096 86.353 64.632 ;
     RECT  86.353 0.096 86.485 64.68 ;
     RECT  86.485 0.048 88.049 64.68 ;
     RECT  88.049 0.144 89.089 64.68 ;
     RECT  89.089 0.048 89.345 64.68 ;
     RECT  89.345 0.096 92.723 64.68 ;
     RECT  92.723 64.464 93.107 64.68 ;
     RECT  92.723 0.096 93.251 63.384 ;
     RECT  93.251 0.096 93.421 0.312 ;
     RECT  93.251 1.728 93.629 63.384 ;
     RECT  93.107 64.464 93.769 64.632 ;
     RECT  93.769 63.84 94.213 64.632 ;
     RECT  93.421 0.144 94.309 0.312 ;
     RECT  93.629 1.728 94.355 62.808 ;
     RECT  94.309 0.144 94.405 0.504 ;
     RECT  94.355 1.728 94.405 62.712 ;
     RECT  94.213 63.84 94.547 64.68 ;
     RECT  94.547 64.416 94.643 64.68 ;
     RECT  94.405 0.144 94.693 62.712 ;
     RECT  94.693 0.096 95.033 62.712 ;
     RECT  95.033 0.096 95.843 62.664 ;
     RECT  95.843 0.096 95.939 0.168 ;
     RECT  94.643 64.464 95.941 64.68 ;
     RECT  95.939 0.096 96.131 0.12 ;
     RECT  95.843 1.152 96.131 62.664 ;
     RECT  95.941 64.416 96.325 64.68 ;
     RECT  96.325 64.368 96.433 64.68 ;
     RECT  96.433 64.368 96.469 64.728 ;
     RECT  96.131 1.728 96.901 62.664 ;
     RECT  96.901 1.728 97.285 63.288 ;
     RECT  96.469 64.272 97.285 64.728 ;
     RECT  97.285 1.728 97.625 64.728 ;
     RECT  97.625 1.728 97.697 31.944 ;
     RECT  97.697 2.256 98.129 31.944 ;
     RECT  98.129 2.64 98.453 31.944 ;
     RECT  98.453 2.784 99.157 31.944 ;
     RECT  97.625 32.928 99.157 64.728 ;
     RECT  99.157 2.784 99.608 64.728 ;
     RECT  99.608 2.148 99.712 64.728 ;
     RECT  99.712 2.418 99.904 64.728 ;
     RECT  99.904 4.848 100.348 64.728 ;
     RECT  100.348 30.048 100.397 64.728 ;
     RECT  100.397 34.752 100.549 64.728 ;
     RECT  100.348 4.848 101.189 29.064 ;
     RECT  101.189 4.848 101.219 8.712 ;
     RECT  101.219 5.088 101.315 8.712 ;
     RECT  101.189 9.888 101.405 29.064 ;
     RECT  101.405 10.32 101.413 29.064 ;
     RECT  100.397 30.048 101.413 33.672 ;
     RECT  100.549 35.328 101.477 64.728 ;
     RECT  101.413 10.32 101.699 33.672 ;
     RECT  101.699 10.32 101.747 10.872 ;
     RECT  101.699 12 101.801 33.672 ;
     RECT  101.801 12 102.017 29.16 ;
     RECT  101.315 5.568 102.277 8.712 ;
     RECT  101.747 10.32 102.373 10.68 ;
     RECT  102.277 5.376 102.413 8.712 ;
     RECT  102.373 10.128 102.469 10.68 ;
     RECT  102.413 5.616 102.509 8.712 ;
     RECT  101.801 30.192 102.553 33.672 ;
     RECT  102.509 5.616 102.589 8.76 ;
     RECT  102.469 9.744 102.589 10.68 ;
     RECT  102.553 30.192 102.589 34.344 ;
     RECT  101.477 35.328 102.589 40.488 ;
     RECT  102.517 2.688 102.769 2.712 ;
     RECT  102.017 27.36 102.769 29.16 ;
     RECT  102.589 30.192 102.769 40.488 ;
     RECT  102.589 5.616 102.805 10.68 ;
     RECT  102.017 12 102.805 26.28 ;
     RECT  102.769 27.36 102.841 40.488 ;
     RECT  101.477 41.472 102.841 64.728 ;
     RECT  102.697 0.576 102.899 0.6 ;
     RECT  102.841 27.36 102.899 64.728 ;
     RECT  102.805 5.616 102.925 26.28 ;
     RECT  102.769 1.776 102.949 2.712 ;
     RECT  102.925 16.176 103.045 26.28 ;
     RECT  102.899 27.36 103.045 29.064 ;
     RECT  102.925 5.616 103.133 14.904 ;
     RECT  103.045 16.176 103.133 29.064 ;
     RECT  103.133 16.272 103.187 29.064 ;
     RECT  103.187 16.272 103.205 26.808 ;
     RECT  103.133 5.712 103.277 14.904 ;
     RECT  103.205 18.192 103.313 26.808 ;
     RECT  103.205 16.272 103.493 17.064 ;
     RECT  102.949 1.728 103.637 2.712 ;
     RECT  103.637 1.824 103.673 2.712 ;
     RECT  103.673 2.688 103.781 2.712 ;
     RECT  103.313 18.192 103.789 25.368 ;
     RECT  103.277 6.192 103.961 14.904 ;
     RECT  103.187 27.84 104.137 29.064 ;
     RECT  102.899 30.144 104.137 64.728 ;
     RECT  103.493 16.272 104.165 17.016 ;
     RECT  103.961 6.24 104.197 14.904 ;
     RECT  104.165 15.984 104.197 17.016 ;
     RECT  103.789 18.816 104.281 25.368 ;
     RECT  103.313 26.64 104.281 26.808 ;
     RECT  104.197 6.24 104.749 17.016 ;
     RECT  104.281 18.816 104.773 26.808 ;
     RECT  104.137 27.84 104.773 64.728 ;
     RECT  104.749 6.24 104.869 17.496 ;
     RECT  104.453 2.832 105.008 2.856 ;
     RECT  104.869 6.24 105.008 17.544 ;
     RECT  104.773 18.816 105.008 64.728 ;
     RECT  105.008 2.148 105.112 64.728 ;
     RECT  105.112 2.418 105.304 64.728 ;
     RECT  105.304 26.208 105.443 64.728 ;
     RECT  105.443 26.208 105.545 34.536 ;
     RECT  105.545 26.208 105.683 33.096 ;
     RECT  105.304 6.816 105.82 25.128 ;
     RECT  105.443 35.856 105.941 64.728 ;
     RECT  105.683 26.64 105.977 33.096 ;
     RECT  105.82 6.816 106.019 12.552 ;
     RECT  106.019 6.96 106.085 12.552 ;
     RECT  105.977 26.736 106.121 33.096 ;
     RECT  106.085 6.96 106.157 11.976 ;
     RECT  106.157 8.496 106.163 11.976 ;
     RECT  105.941 55.2 106.193 64.728 ;
     RECT  106.163 10.272 106.307 11.976 ;
     RECT  106.121 27.216 106.373 33.096 ;
     RECT  106.193 55.44 106.451 64.728 ;
     RECT  105.82 14.256 106.481 25.128 ;
     RECT  106.451 55.776 106.499 64.728 ;
     RECT  105.545 34.128 106.549 34.536 ;
     RECT  105.941 35.856 106.549 54.168 ;
     RECT  106.549 34.128 106.553 54.168 ;
     RECT  106.307 10.272 106.661 10.344 ;
     RECT  106.481 14.256 106.661 22.248 ;
     RECT  106.307 11.328 106.697 11.976 ;
     RECT  106.157 7.2 106.739 7.272 ;
     RECT  106.553 34.128 106.739 54.12 ;
     RECT  106.661 10.272 106.769 10.296 ;
     RECT  106.661 14.256 106.777 22.2 ;
     RECT  106.739 34.128 106.837 53.976 ;
     RECT  106.777 14.256 106.883 18.888 ;
     RECT  106.837 33.6 106.924 53.976 ;
     RECT  106.481 23.376 106.945 25.128 ;
     RECT  106.924 33.936 106.985 53.976 ;
     RECT  106.945 23.376 107.075 25.704 ;
     RECT  107.075 24.48 107.125 25.704 ;
     RECT  106.163 8.496 107.132 9.144 ;
     RECT  107.125 24.48 107.161 25.896 ;
     RECT  106.373 27.216 107.161 32.52 ;
     RECT  106.883 14.256 107.171 14.904 ;
     RECT  107.075 23.376 107.171 23.448 ;
     RECT  106.985 33.936 107.171 53.016 ;
     RECT  107.132 8.304 107.219 9.144 ;
     RECT  107.171 14.784 107.345 14.904 ;
     RECT  107.171 23.424 107.345 23.448 ;
     RECT  106.739 7.2 107.417 7.224 ;
     RECT  106.883 15.936 107.417 18.888 ;
     RECT  106.499 56.208 107.557 59.016 ;
     RECT  106.499 60.096 107.557 64.728 ;
     RECT  107.171 51.072 107.596 53.016 ;
     RECT  107.161 24.48 107.605 32.52 ;
     RECT  107.219 8.544 107.669 9.144 ;
     RECT  107.417 18.864 107.669 18.888 ;
     RECT  107.171 33.936 107.741 50.088 ;
     RECT  107.605 24.48 107.747 32.616 ;
     RECT  107.747 24.48 107.885 32.52 ;
     RECT  107.485 13.104 107.941 13.128 ;
     RECT  106.697 11.952 107.948 11.976 ;
     RECT  107.941 13.104 107.948 13.8 ;
     RECT  107.596 52.992 107.957 53.016 ;
     RECT  107.557 56.208 107.987 64.728 ;
     RECT  107.885 24.528 107.993 32.52 ;
     RECT  107.741 34.8 107.993 50.088 ;
     RECT  107.948 11.952 108.028 13.8 ;
     RECT  107.941 33.6 108.028 33.624 ;
     RECT  107.417 15.936 108.131 17.64 ;
     RECT  107.993 35.616 108.131 50.088 ;
     RECT  108.131 35.664 108.179 50.088 ;
     RECT  108.179 38.688 108.241 50.088 ;
     RECT  107.596 51.072 108.241 51.912 ;
     RECT  108.179 35.664 108.316 37.656 ;
     RECT  108.316 35.904 108.323 37.656 ;
     RECT  108.028 11.952 108.325 13.128 ;
     RECT  107.669 8.544 108.353 8.568 ;
     RECT  108.325 11.28 108.371 13.128 ;
     RECT  108.371 11.28 108.412 11.4 ;
     RECT  108.131 16.992 108.425 17.64 ;
     RECT  108.241 23.28 108.457 23.304 ;
     RECT  108.241 38.688 108.515 51.912 ;
     RECT  108.515 51.36 108.611 51.912 ;
     RECT  108.131 15.936 108.641 15.96 ;
     RECT  106.777 19.872 108.707 22.2 ;
     RECT  108.457 23.28 108.745 23.4 ;
     RECT  108.707 19.872 108.749 20.088 ;
     RECT  108.515 38.688 108.803 50.184 ;
     RECT  107.993 25.152 108.821 32.52 ;
     RECT  108.425 16.992 108.851 17.112 ;
     RECT  108.745 23.232 108.851 23.4 ;
     RECT  108.323 35.904 108.851 37.608 ;
     RECT  108.803 38.688 108.851 49.608 ;
     RECT  107.345 14.784 108.853 14.808 ;
     RECT  108.821 29.664 108.857 32.52 ;
     RECT  108.851 23.232 108.893 23.304 ;
     RECT  108.371 12.528 108.899 13.128 ;
     RECT  107.987 56.208 108.899 59.016 ;
     RECT  108.851 38.688 108.947 41.112 ;
     RECT  108.851 42.192 108.947 49.608 ;
     RECT  108.821 25.152 108.965 28.296 ;
     RECT  108.085 33.552 108.965 33.576 ;
     RECT  108.947 42.192 108.965 48.984 ;
     RECT  108.947 38.688 108.995 39.336 ;
     RECT  108.899 56.256 108.995 59.016 ;
     RECT  108.707 21.072 109.001 22.2 ;
     RECT  109.001 21.408 109.037 22.2 ;
     RECT  108.893 23.232 109.073 23.256 ;
     RECT  108.899 13.104 109.105 13.128 ;
     RECT  108.853 14.784 109.105 15.192 ;
     RECT  108.965 25.152 109.141 27.912 ;
     RECT  108.749 19.92 109.145 20.088 ;
     RECT  109.141 24.912 109.145 27.912 ;
     RECT  108.611 51.36 109.145 51.384 ;
     RECT  108.947 40.416 109.181 41.112 ;
     RECT  109.145 24.912 109.187 25.704 ;
     RECT  108.851 36.432 109.187 37.608 ;
     RECT  107.987 60.144 109.289 64.728 ;
     RECT  108.457 18.144 109.321 18.168 ;
     RECT  109.181 40.992 109.361 41.112 ;
     RECT  108.857 31.536 109.427 32.52 ;
     RECT  108.421 7.776 109.429 7.8 ;
     RECT  108.412 11.376 109.429 11.4 ;
     RECT  109.105 13.104 109.433 13.464 ;
     RECT  108.851 17.04 109.669 17.112 ;
     RECT  109.321 18.144 109.669 18.84 ;
     RECT  109.289 60.672 109.757 64.728 ;
     RECT  108.857 29.664 109.825 30.312 ;
     RECT  109.82 9.648 109.861 9.672 ;
     RECT  109.033 33.6 109.909 33.624 ;
     RECT  109.669 17.04 109.969 18.84 ;
     RECT  109.969 16.896 110.185 18.84 ;
     RECT  109.145 20.064 110.185 20.088 ;
     RECT  109.187 37.584 110.185 37.608 ;
     RECT  108.995 38.688 110.185 38.712 ;
     RECT  109.925 39.888 110.185 39.912 ;
     RECT  109.037 22.176 110.221 22.2 ;
     RECT  110.185 16.896 110.245 20.088 ;
     RECT  109.909 33.6 110.293 33.816 ;
     RECT  109.429 7.776 110.408 8.568 ;
     RECT  109.861 9.648 110.408 9.816 ;
     RECT  109.429 11.376 110.408 11.784 ;
     RECT  109.433 13.44 110.408 13.464 ;
     RECT  109.105 14.496 110.408 15.192 ;
     RECT  110.245 16.896 110.408 20.568 ;
     RECT  110.221 21.84 110.408 22.2 ;
     RECT  109.187 24.912 110.408 24.936 ;
     RECT  109.145 27.312 110.408 27.912 ;
     RECT  109.825 29.04 110.408 30.312 ;
     RECT  109.427 31.536 110.408 32.472 ;
     RECT  110.293 33.6 110.408 33.96 ;
     RECT  109.187 36.432 110.408 36.456 ;
     RECT  110.185 37.584 110.408 39.912 ;
     RECT  109.361 40.992 110.408 41.016 ;
     RECT  108.965 42.192 110.408 42.216 ;
     RECT  108.965 43.824 110.408 48.984 ;
     RECT  109.861 50.304 110.408 50.328 ;
     RECT  108.995 56.784 110.408 59.016 ;
     RECT  109.757 60.672 110.408 64.632 ;
     RECT  110.408 2.148 110.512 64.632 ;
     RECT  110.512 2.418 110.704 64.632 ;
     RECT  110.704 62.256 110.765 64.632 ;
     RECT  110.704 16.896 110.801 18.168 ;
     RECT  110.801 16.896 110.819 17.112 ;
     RECT  110.704 37.872 110.819 37.896 ;
     RECT  110.704 38.88 110.819 39.528 ;
     RECT  110.704 43.344 110.819 50.328 ;
     RECT  110.765 62.448 110.837 64.632 ;
     RECT  110.704 57.408 110.867 59.016 ;
     RECT  110.704 27.696 110.873 27.912 ;
     RECT  110.819 48.96 110.873 50.328 ;
     RECT  110.704 11.76 110.909 11.784 ;
     RECT  110.704 20.064 110.909 20.424 ;
     RECT  110.867 57.696 110.981 59.016 ;
     RECT  110.801 18.144 111.089 18.168 ;
     RECT  110.819 43.344 111.089 47.688 ;
     RECT  111.089 44.448 111.107 47.688 ;
     RECT  110.704 22.752 111.155 23.592 ;
     RECT  110.981 57.696 111.203 57.72 ;
     RECT  110.909 20.4 111.233 20.424 ;
     RECT  110.704 29.04 111.233 29.64 ;
     RECT  110.704 30.816 111.233 30.84 ;
     RECT  111.233 29.616 111.244 29.64 ;
     RECT  110.981 58.992 111.299 59.016 ;
     RECT  110.837 62.688 111.301 64.632 ;
     RECT  111.107 44.448 111.341 45.24 ;
     RECT  111.107 46.32 111.341 47.688 ;
     RECT  111.155 22.752 111.449 22.776 ;
     RECT  110.704 33.936 111.449 34.776 ;
     RECT  111.341 44.448 111.449 44.472 ;
     RECT  111.449 33.936 111.629 33.96 ;
     RECT  110.873 27.888 111.665 27.912 ;
     RECT  110.873 48.96 111.773 49.896 ;
     RECT  111.089 43.344 111.881 43.368 ;
     RECT  111.341 46.32 111.881 47.16 ;
     RECT  111.881 47.088 111.989 47.16 ;
     RECT  111.301 62.688 112.132 64.68 ;
     RECT  112.132 62.64 112.237 64.68 ;
     RECT  112.237 62.544 112.453 64.68 ;
     RECT  112.453 62.544 112.499 64.728 ;
     RECT  112.499 64.656 112.565 64.728 ;
     RECT  111.773 48.96 112.637 48.984 ;
     RECT  112.499 62.544 112.741 63.336 ;
     RECT  112.741 62.16 112.853 63.336 ;
     RECT  111.989 47.136 113.069 47.16 ;
     RECT  112.853 62.736 113.468 63.336 ;
     RECT  112.565 64.656 113.468 64.68 ;
     RECT  113.468 62.736 113.501 64.68 ;
     RECT  113.893 62.64 114.005 62.664 ;
     RECT  113.501 63.84 114.514 64.68 ;
     RECT  114.514 63.792 115.037 64.68 ;
     RECT  115.037 63.216 115.808 64.68 ;
     RECT  115.808 2.148 115.912 64.68 ;
     RECT  115.912 2.418 116.104 64.68 ;
     RECT  116.104 62.16 117.397 64.68 ;
     RECT  117.397 61.584 117.497 64.68 ;
     RECT  117.497 62.16 118.396 64.68 ;
     RECT  118.396 62.736 118.547 64.68 ;
     RECT  118.547 62.832 118.835 64.68 ;
     RECT  118.835 64.608 118.973 64.68 ;
     RECT  118.835 62.832 119.027 63.288 ;
     RECT  118.973 64.656 119.045 64.68 ;
     RECT  119.027 62.832 119.123 62.856 ;
     RECT  119.509 62.784 119.693 62.808 ;
     RECT  120.121 62.736 121.208 62.76 ;
     RECT  121.208 2.148 121.241 62.76 ;
     RECT  121.241 2.148 121.312 62.652 ;
     RECT  121.312 2.418 121.504 62.382 ;
     RECT  122.785 62.736 122.932 62.76 ;
     RECT  122.932 62.736 123.013 62.808 ;
     RECT  123.013 62.736 123.113 63 ;
     RECT  126.608 2.148 126.712 62.652 ;
     RECT  126.712 2.418 126.904 62.382 ;
     RECT  129.772 62.784 129.952 62.808 ;
     RECT  129.952 62.736 129.953 62.808 ;
     RECT  129.953 62.736 131.077 62.76 ;
     RECT  130.885 63.84 131.077 63.864 ;
     RECT  131.077 62.736 131.101 63.864 ;
     RECT  131.101 62.736 131.605 63.912 ;
     RECT  131.605 62.16 131.893 63.912 ;
     RECT  131.893 62.16 132.008 64.632 ;
     RECT  132.008 2.148 132.112 64.632 ;
     RECT  132.112 2.418 132.304 64.632 ;
     RECT  132.304 62.16 132.329 64.632 ;
     RECT  132.329 62.16 132.797 62.76 ;
     RECT  132.329 63.84 132.965 64.632 ;
     RECT  132.797 62.304 133.333 62.76 ;
     RECT  132.965 63.84 133.333 64.68 ;
     RECT  133.333 62.304 133.373 64.68 ;
     RECT  133.373 62.736 133.715 64.68 ;
     RECT  133.715 63.264 133.913 64.68 ;
     RECT  133.913 63.264 135.101 63.816 ;
     RECT  135.101 63.264 135.289 63.288 ;
     RECT  137.408 2.148 137.512 62.652 ;
     RECT  137.512 2.418 137.704 62.382 ;
     RECT  142.808 2.148 142.912 62.652 ;
     RECT  142.912 2.418 143.104 62.382 ;
     RECT  148.208 2.148 148.312 62.652 ;
     RECT  148.312 2.418 148.504 62.382 ;
     RECT  153.608 2.148 153.712 62.652 ;
     RECT  153.712 2.418 153.904 62.382 ;
     RECT  159.008 2.148 159.112 62.652 ;
     RECT  159.112 2.418 159.304 62.382 ;
     RECT  164.408 2.148 164.512 62.652 ;
     RECT  164.512 2.418 164.704 62.382 ;
     RECT  169.808 2.148 169.912 62.652 ;
     RECT  169.912 2.418 170.104 62.382 ;
     RECT  175.208 2.148 175.312 62.652 ;
     RECT  175.312 2.418 175.504 62.382 ;
     RECT  180.608 2.148 180.712 62.652 ;
     RECT  180.712 2.418 180.904 62.382 ;
    LAYER M5 ;
     RECT  77.544 0.016 77.616 0.084 ;
     RECT  77.64 0.016 77.712 0.084 ;
     RECT  77.736 0.016 77.808 0.084 ;
     RECT  77.832 0.016 77.904 0.084 ;
     RECT  77.928 0.016 78 0.084 ;
     RECT  78.024 0.016 78.096 0.084 ;
     RECT  78.12 0.016 78.192 0.084 ;
     RECT  78.216 0.016 78.288 0.084 ;
     RECT  78.312 0.016 78.384 0.084 ;
     RECT  78.408 0.016 78.48 0.084 ;
     RECT  78.504 0.016 78.576 0.084 ;
     RECT  78.6 0.016 78.672 0.084 ;
     RECT  78.696 0.016 78.768 0.084 ;
     RECT  78.792 0.016 78.864 0.084 ;
     RECT  78.888 0.016 78.96 0.084 ;
     RECT  78.984 0.016 79.056 0.084 ;
     RECT  79.08 0.016 79.152 0.084 ;
     RECT  79.176 0.016 79.248 0.084 ;
     RECT  79.272 0.016 79.344 0.084 ;
     RECT  79.368 0.016 79.44 0.084 ;
     RECT  79.464 0.016 79.536 0.084 ;
     RECT  79.56 0.016 79.632 0.084 ;
     RECT  79.656 0.016 79.728 0.084 ;
     RECT  79.752 0.016 79.824 0.084 ;
     RECT  79.848 0.016 79.92 0.084 ;
     RECT  79.944 0.016 80.016 0.084 ;
     RECT  80.04 0.016 80.112 0.084 ;
     RECT  80.136 0.016 80.208 0.084 ;
     RECT  80.232 0.016 80.304 0.084 ;
     RECT  80.328 0.016 80.4 0.084 ;
     RECT  80.424 0.016 80.496 0.084 ;
     RECT  80.52 0.016 80.592 0.084 ;
     RECT  80.616 0.016 80.688 0.084 ;
     RECT  80.712 0.016 80.784 0.084 ;
     RECT  80.808 0.016 80.88 0.084 ;
     RECT  80.904 0.016 80.976 0.084 ;
     RECT  81 0.016 81.072 0.084 ;
     RECT  81.096 0.016 81.168 0.084 ;
     RECT  81.192 0.016 81.264 0.084 ;
     RECT  81.288 0.016 81.36 0.084 ;
     RECT  81.384 0.016 81.456 0.084 ;
     RECT  81.48 0.016 81.552 0.084 ;
     RECT  81.576 0.016 81.648 0.084 ;
     RECT  81.672 0.016 81.744 0.084 ;
     RECT  81.768 0.016 81.84 0.084 ;
     RECT  81.864 0.016 81.936 0.084 ;
     RECT  81.96 0.016 82.032 0.084 ;
     RECT  82.056 0.016 82.128 0.084 ;
     RECT  82.152 0.016 82.224 0.084 ;
     RECT  82.248 0.016 82.32 0.084 ;
     RECT  82.344 0.016 82.416 0.084 ;
     RECT  82.44 0.016 82.512 0.084 ;
     RECT  82.536 0.016 82.608 0.084 ;
     RECT  82.632 0.016 82.704 0.084 ;
     RECT  82.728 0.016 82.8 0.084 ;
     RECT  82.824 0.016 82.896 0.084 ;
     RECT  82.92 0.016 82.992 0.084 ;
     RECT  83.016 0.016 83.088 0.084 ;
     RECT  83.112 0.016 83.184 0.084 ;
     RECT  83.208 0.016 83.28 0.084 ;
     RECT  83.304 0.016 83.376 0.084 ;
     RECT  83.4 0.016 83.472 0.084 ;
     RECT  83.496 0.016 83.568 0.084 ;
     RECT  83.592 0.016 83.664 0.084 ;
     RECT  83.688 0.016 83.76 0.084 ;
     RECT  83.784 0.016 83.856 0.084 ;
     RECT  83.88 0.016 83.952 0.084 ;
     RECT  83.976 0.016 84.048 0.084 ;
     RECT  84.072 0.016 84.144 0.084 ;
     RECT  84.168 0.016 84.24 0.084 ;
     RECT  84.264 0.016 84.336 0.084 ;
     RECT  84.36 0.016 84.432 0.084 ;
     RECT  84.456 0.016 84.528 0.084 ;
     RECT  84.552 0.016 84.624 0.084 ;
     RECT  84.648 0.016 84.72 0.084 ;
     RECT  84.744 0.016 84.816 0.084 ;
     RECT  84.84 0.016 84.912 0.084 ;
     RECT  84.936 0.016 85.008 0.084 ;
     RECT  85.032 0.016 85.104 0.084 ;
     RECT  85.128 0.016 85.2 0.084 ;
     RECT  85.224 0.016 85.296 0.084 ;
     RECT  85.32 0.016 85.392 0.084 ;
     RECT  85.416 0.016 85.488 0.084 ;
     RECT  85.512 0.016 85.584 0.084 ;
     RECT  85.608 0.016 85.68 0.084 ;
     RECT  85.704 0.016 85.776 0.084 ;
     RECT  85.8 0.016 85.872 0.084 ;
     RECT  85.896 0.016 85.968 0.084 ;
     RECT  85.992 0.016 86.064 0.084 ;
     RECT  86.088 0.016 86.16 0.084 ;
     RECT  86.184 0.016 86.256 0.084 ;
     RECT  86.28 0.016 86.352 0.084 ;
     RECT  86.376 0.016 86.448 0.084 ;
     RECT  86.472 0.016 86.544 0.084 ;
     RECT  86.568 0.016 86.64 0.084 ;
     RECT  86.664 0.016 86.736 0.084 ;
     RECT  86.76 0.016 86.832 0.084 ;
     RECT  86.856 0.016 86.928 0.084 ;
     RECT  86.952 0.016 87.024 0.084 ;
     RECT  87.048 0.016 87.12 0.084 ;
     RECT  87.144 0.016 87.216 0.084 ;
     RECT  87.24 0.016 87.312 0.084 ;
     RECT  87.336 0.016 87.408 0.084 ;
     RECT  87.432 0.016 87.504 0.084 ;
     RECT  87.528 0.016 87.6 0.084 ;
     RECT  87.624 0.016 87.696 0.084 ;
     RECT  87.72 0.016 87.792 0.084 ;
     RECT  87.816 0.016 87.888 0.084 ;
     RECT  87.912 0.016 87.984 0.084 ;
     RECT  88.008 0.016 88.08 0.084 ;
     RECT  88.104 0.016 88.176 0.084 ;
     RECT  88.2 0.016 88.272 0.084 ;
     RECT  88.296 0.016 88.368 0.084 ;
     RECT  88.392 0.016 88.464 0.084 ;
     RECT  88.488 0.016 88.56 0.084 ;
     RECT  88.584 0.016 88.656 0.084 ;
     RECT  88.68 0.016 88.752 0.084 ;
     RECT  88.776 0.016 88.848 0.084 ;
     RECT  88.872 0.016 88.944 0.084 ;
     RECT  88.968 0.016 89.04 0.084 ;
     RECT  89.064 0.016 89.136 0.084 ;
     RECT  89.16 0.016 89.232 0.084 ;
     RECT  89.256 0.016 89.328 0.084 ;
     RECT  89.352 0.016 89.424 0.084 ;
     RECT  89.448 0.016 89.52 0.084 ;
     RECT  89.544 0.016 89.616 0.084 ;
     RECT  89.64 0.016 89.712 0.084 ;
     RECT  89.736 0.016 89.808 0.084 ;
     RECT  89.832 0.016 89.904 0.084 ;
     RECT  89.928 0.016 90 0.084 ;
     RECT  90.024 0.016 90.096 0.084 ;
     RECT  90.12 0.016 90.192 0.084 ;
     RECT  90.216 0.016 90.288 0.084 ;
     RECT  90.312 0.016 90.384 0.084 ;
     RECT  90.408 0.016 90.48 0.084 ;
     RECT  90.504 0.016 90.576 0.084 ;
     RECT  90.6 0.016 90.672 0.084 ;
     RECT  90.696 0.016 90.768 0.084 ;
     RECT  90.792 0.016 90.864 0.084 ;
     RECT  90.888 0.016 90.96 0.084 ;
     RECT  90.984 0.016 91.056 0.084 ;
     RECT  91.08 0.016 91.152 0.084 ;
     RECT  91.176 0.016 91.248 0.084 ;
     RECT  91.272 0.016 91.344 0.084 ;
     RECT  91.368 0.016 91.44 0.084 ;
     RECT  91.464 0.016 91.536 0.084 ;
     RECT  91.56 0.016 91.632 0.084 ;
     RECT  91.656 0.016 91.728 0.084 ;
     RECT  91.752 0.016 91.824 0.084 ;
     RECT  91.848 0.016 91.92 0.084 ;
     RECT  91.944 0.016 92.016 0.084 ;
     RECT  92.04 0.016 92.112 0.084 ;
     RECT  92.136 0.016 92.208 0.084 ;
     RECT  92.232 0.016 92.304 0.084 ;
     RECT  92.328 0.016 92.4 0.084 ;
     RECT  92.424 0.016 92.496 0.084 ;
     RECT  92.52 0.016 92.592 0.084 ;
     RECT  92.616 0.016 92.688 0.084 ;
     RECT  92.712 0.016 92.784 0.084 ;
     RECT  92.808 0.016 92.88 0.084 ;
     RECT  92.904 0.016 92.976 0.084 ;
     RECT  93 0.016 93.072 0.084 ;
     RECT  93.096 0.016 93.168 0.084 ;
     RECT  93.192 0.016 93.264 0.084 ;
     RECT  93.288 0.016 93.36 0.084 ;
     RECT  93.384 0.016 93.456 0.084 ;
     RECT  93.48 0.016 93.552 0.084 ;
     RECT  93.576 0.016 93.648 0.084 ;
     RECT  93.672 0.016 93.744 0.084 ;
     RECT  93.768 0.016 93.84 0.084 ;
     RECT  93.864 0.016 93.936 0.084 ;
     RECT  93.96 0.016 94.032 0.084 ;
     RECT  94.056 0.016 94.128 0.084 ;
     RECT  94.152 0.016 94.224 0.084 ;
     RECT  94.248 0.016 94.32 0.084 ;
     RECT  94.344 0.016 94.416 0.084 ;
     RECT  94.44 0.016 94.512 0.084 ;
     RECT  94.536 0.016 94.608 0.084 ;
     RECT  94.632 0.016 94.704 0.084 ;
     RECT  94.728 0.016 94.8 0.084 ;
     RECT  94.824 0.016 94.896 0.084 ;
     RECT  94.92 0.016 94.992 0.084 ;
     RECT  95.016 0.016 95.088 0.084 ;
     RECT  95.112 0.016 95.184 0.084 ;
     RECT  95.208 0.016 95.28 0.084 ;
     RECT  95.304 0.016 95.376 0.084 ;
     RECT  95.4 0.016 95.472 0.084 ;
     RECT  95.496 0.016 95.568 0.084 ;
     RECT  95.592 0.016 95.664 0.084 ;
     RECT  95.688 0.016 95.76 0.084 ;
     RECT  95.784 0.016 95.856 0.084 ;
     RECT  77.52 0.084 95.88 0.085 ;
     RECT  102.888 0.016 102.96 0.084 ;
     RECT  102.984 0.016 103.056 0.084 ;
     RECT  103.08 0.016 103.152 0.084 ;
     RECT  103.176 0.016 103.248 0.084 ;
     RECT  103.272 0.016 103.344 0.084 ;
     RECT  103.368 0.016 103.44 0.084 ;
     RECT  103.464 0.016 103.536 0.084 ;
     RECT  102.864 0.084 103.56 0.611 ;
     RECT  77.52 0.085 96.12 1.091 ;
     RECT  77.616 1.091 96.12 1.187 ;
     RECT  102.96 0.611 103.56 1.859 ;
     RECT  77.616 1.187 96.024 2.053 ;
     RECT  77.568 2.053 96.024 2.149 ;
     RECT  2.4 2.137 2.52 2.151 ;
     RECT  7.8 2.137 7.92 2.151 ;
     RECT  13.2 2.137 13.32 2.151 ;
     RECT  18.6 2.137 18.72 2.151 ;
     RECT  24 2.137 24.12 2.151 ;
     RECT  29.4 2.137 29.52 2.151 ;
     RECT  34.8 2.137 34.92 2.151 ;
     RECT  40.2 2.137 40.32 2.151 ;
     RECT  45.6 2.137 45.72 2.151 ;
     RECT  51 2.137 51.12 2.151 ;
     RECT  56.4 2.137 56.52 2.151 ;
     RECT  61.8 2.137 61.92 2.151 ;
     RECT  67.2 2.137 67.32 2.151 ;
     RECT  72.6 2.137 72.72 2.151 ;
     RECT  99.6 2.137 99.72 2.151 ;
     RECT  105 2.137 105.12 2.151 ;
     RECT  110.4 2.137 110.52 2.151 ;
     RECT  115.8 2.137 115.92 2.151 ;
     RECT  121.2 2.137 121.32 2.151 ;
     RECT  126.6 2.137 126.72 2.151 ;
     RECT  132 2.137 132.12 2.151 ;
     RECT  137.4 2.137 137.52 2.151 ;
     RECT  142.8 2.137 142.92 2.151 ;
     RECT  148.2 2.137 148.32 2.151 ;
     RECT  153.6 2.137 153.72 2.151 ;
     RECT  159 2.137 159.12 2.151 ;
     RECT  164.4 2.137 164.52 2.151 ;
     RECT  169.8 2.137 169.92 2.151 ;
     RECT  175.2 2.137 175.32 2.151 ;
     RECT  180.6 2.137 180.72 2.151 ;
     RECT  76.08 2.053 76.104 2.197 ;
     RECT  77.568 2.149 96.456 2.197 ;
     RECT  76.08 2.197 96.456 2.485 ;
     RECT  102.96 1.859 103.512 2.677 ;
     RECT  98.064 2.245 98.088 2.773 ;
     RECT  76.08 2.485 96.84 2.821 ;
     RECT  98.064 2.773 98.136 2.821 ;
     RECT  105 2.151 105.312 2.821 ;
     RECT  76.08 2.821 98.136 3.205 ;
     RECT  99.6 2.151 99.912 3.205 ;
     RECT  76.08 3.205 99.912 3.349 ;
     RECT  75.456 3.349 99.912 4.261 ;
     RECT  72.6 2.151 72.912 4.837 ;
     RECT  74.064 4.693 74.088 4.837 ;
     RECT  75.36 4.261 99.912 4.837 ;
     RECT  72.6 4.837 74.088 4.981 ;
     RECT  75.36 4.837 101.208 4.981 ;
     RECT  72.6 4.981 101.208 5.077 ;
     RECT  102.528 2.677 103.512 5.365 ;
     RECT  72.6 5.077 101.304 5.653 ;
     RECT  102.288 5.365 103.512 5.653 ;
     RECT  72.6 5.653 103.512 6.181 ;
     RECT  104.496 2.821 105.312 6.181 ;
     RECT  72.288 6.181 105.312 6.371 ;
     RECT  74.688 6.371 105.312 6.805 ;
     RECT  72.288 6.371 73.128 6.851 ;
     RECT  74.688 6.805 106.008 7.237 ;
     RECT  72.48 6.851 73.128 7.477 ;
     RECT  74.688 7.237 106.728 7.477 ;
     RECT  110.4 2.151 110.712 7.765 ;
     RECT  72.48 7.477 106.728 8.051 ;
     RECT  72.6 8.051 106.728 8.293 ;
     RECT  72.6 8.293 107.208 8.435 ;
     RECT  72.6 8.435 73.128 8.579 ;
     RECT  109.44 7.765 110.712 8.579 ;
     RECT  74.592 8.435 107.208 9.155 ;
     RECT  74.592 9.155 106.152 9.491 ;
     RECT  110.4 8.579 110.712 9.637 ;
     RECT  72.6 8.579 72.912 10.693 ;
     RECT  75.024 9.491 106.152 10.693 ;
     RECT  74.592 10.693 106.152 11.269 ;
     RECT  71.184 10.789 71.208 11.411 ;
     RECT  109.872 9.637 110.712 11.411 ;
     RECT  74.592 11.269 106.296 11.605 ;
     RECT  72.384 10.693 72.912 11.795 ;
     RECT  73.968 11.605 106.296 11.797 ;
     RECT  72.6 11.795 72.912 12.373 ;
     RECT  73.92 11.797 106.296 12.373 ;
     RECT  108.336 11.269 108.36 12.373 ;
     RECT  69.264 10.501 69.288 12.515 ;
     RECT  108 12.373 108.36 12.517 ;
     RECT  72.6 12.373 106.296 12.757 ;
     RECT  108 12.517 108.888 13.093 ;
     RECT  72.432 12.757 106.296 13.763 ;
     RECT  72.48 13.763 106.296 14.245 ;
     RECT  107.952 13.093 108.888 14.245 ;
     RECT  72.48 14.245 108.888 14.867 ;
     RECT  75.024 14.867 108.888 14.915 ;
     RECT  72.48 14.867 73.896 15.061 ;
     RECT  108 14.915 108.888 15.203 ;
     RECT  75.024 14.915 106.872 15.731 ;
     RECT  72.048 15.061 73.896 15.875 ;
     RECT  72.48 15.875 73.896 16.501 ;
     RECT  75.024 15.731 106.296 16.501 ;
     RECT  108 15.203 108.024 16.501 ;
     RECT  108 16.501 108.12 16.547 ;
     RECT  72.48 16.501 106.296 16.885 ;
     RECT  110.4 11.411 110.712 16.885 ;
     RECT  108.096 16.547 108.12 16.981 ;
     RECT  72.48 16.885 106.728 17.029 ;
     RECT  108.096 16.981 108.84 17.029 ;
     RECT  110.4 16.885 110.808 17.029 ;
     RECT  108.096 17.029 110.808 17.123 ;
     RECT  109.68 17.123 110.712 17.891 ;
     RECT  72.48 17.029 106.872 18.133 ;
     RECT  70.656 16.405 70.68 18.181 ;
     RECT  72.48 18.133 107.016 18.565 ;
     RECT  70.416 18.181 70.68 18.851 ;
     RECT  71.712 18.565 107.016 19.235 ;
     RECT  110.4 17.891 110.712 19.333 ;
     RECT  71.76 19.235 107.016 19.861 ;
     RECT  108.096 17.123 108.12 19.861 ;
     RECT  71.76 19.861 108.12 20.051 ;
     RECT  76.08 20.051 108.12 20.485 ;
     RECT  70.416 18.851 70.44 20.579 ;
     RECT  71.76 20.051 74.808 20.579 ;
     RECT  110.256 19.333 110.712 20.579 ;
     RECT  76.08 20.485 108.696 21.443 ;
     RECT  76.08 21.443 108.648 21.779 ;
     RECT  71.76 20.579 74.472 22.165 ;
     RECT  76.08 21.779 99.912 22.165 ;
     RECT  71.76 22.165 74.616 22.693 ;
     RECT  75.6 22.165 99.912 22.693 ;
     RECT  110.4 20.579 110.712 22.741 ;
     RECT  71.76 22.693 99.912 23.173 ;
     RECT  101.136 21.779 108.648 23.173 ;
     RECT  71.76 23.173 108.648 23.269 ;
     RECT  71.76 23.269 108.84 23.365 ;
     RECT  71.136 23.365 108.84 23.411 ;
     RECT  71.136 23.411 108.648 23.459 ;
     RECT  110.4 22.741 111.144 23.603 ;
     RECT  71.136 23.459 103.176 24.131 ;
     RECT  104.256 23.459 108.648 24.563 ;
     RECT  107.232 24.563 108.648 24.611 ;
     RECT  107.856 24.611 108.648 24.901 ;
     RECT  104.544 24.563 106.248 25.139 ;
     RECT  107.856 24.901 109.176 25.715 ;
     RECT  107.856 25.715 108.648 25.861 ;
     RECT  71.76 24.131 103.176 26.291 ;
     RECT  71.76 26.291 100.872 26.677 ;
     RECT  71.664 26.677 100.872 26.773 ;
     RECT  70.896 26.773 100.872 26.819 ;
     RECT  104.544 25.139 105.864 26.819 ;
     RECT  104.784 26.819 105.864 27.205 ;
     RECT  107.136 25.861 108.648 27.205 ;
     RECT  101.952 26.291 103.176 27.301 ;
     RECT  101.76 27.301 103.176 27.395 ;
     RECT  104.784 27.205 108.648 27.443 ;
     RECT  110.4 23.603 110.712 27.685 ;
     RECT  106.56 27.443 108.648 27.781 ;
     RECT  109.968 27.685 110.712 27.781 ;
     RECT  106.56 27.781 110.712 27.971 ;
     RECT  104.784 27.443 105.432 28.309 ;
     RECT  104.112 28.309 105.432 28.453 ;
     RECT  103.824 28.453 105.432 29.029 ;
     RECT  107.088 27.971 110.712 29.029 ;
     RECT  101.76 27.395 102.84 29.123 ;
     RECT  102.816 29.123 102.84 29.171 ;
     RECT  103.824 29.029 106.008 29.365 ;
     RECT  106.992 29.029 110.712 29.605 ;
     RECT  106.992 29.605 111.192 29.699 ;
     RECT  101.76 29.123 101.784 29.941 ;
     RECT  70.896 26.819 100.296 30.133 ;
     RECT  101.424 29.941 101.784 30.133 ;
     RECT  102.864 29.365 106.008 30.181 ;
     RECT  106.992 29.699 109.32 30.181 ;
     RECT  102.864 30.181 109.32 30.275 ;
     RECT  102.864 30.275 109.224 30.323 ;
     RECT  70.896 30.133 101.784 30.421 ;
     RECT  102.864 30.323 109.176 30.421 ;
     RECT  70.896 30.421 109.176 30.803 ;
     RECT  70.896 30.803 108.168 30.851 ;
     RECT  110.4 29.699 111.192 30.851 ;
     RECT  109.152 30.803 109.176 31.525 ;
     RECT  71.664 30.851 108.168 31.813 ;
     RECT  109.152 31.525 109.416 31.813 ;
     RECT  71.664 31.813 109.416 32.341 ;
     RECT  71.232 32.341 109.416 32.437 ;
     RECT  110.4 30.851 110.712 32.437 ;
     RECT  69.84 31.765 69.864 33.299 ;
     RECT  71.232 32.437 110.712 33.683 ;
     RECT  71.232 33.683 100.776 34.067 ;
     RECT  75.024 34.067 100.776 34.259 ;
     RECT  71.232 34.067 74.04 34.643 ;
     RECT  71.76 34.643 74.04 34.835 ;
     RECT  102.528 33.683 110.712 34.835 ;
     RECT  72.6 34.835 74.04 35.317 ;
     RECT  75.36 34.259 100.776 35.317 ;
     RECT  102.528 34.835 107.016 35.605 ;
     RECT  108.096 34.835 110.712 35.651 ;
     RECT  72.6 35.317 100.872 35.797 ;
     RECT  72.6 35.797 101.304 35.845 ;
     RECT  102.384 35.605 107.016 35.845 ;
     RECT  72.6 35.845 107.16 36.515 ;
     RECT  108.144 35.651 110.712 36.949 ;
     RECT  108.096 36.949 110.712 37.091 ;
     RECT  108.096 37.091 108.312 37.667 ;
     RECT  109.968 37.091 110.712 37.861 ;
     RECT  108.096 37.667 108.168 38.677 ;
     RECT  72.6 36.515 107.112 38.725 ;
     RECT  108.096 38.677 108.936 38.725 ;
     RECT  72.6 38.725 108.936 39.301 ;
     RECT  70.8 38.005 70.824 39.349 ;
     RECT  70.8 39.349 71.112 39.395 ;
     RECT  109.968 37.861 110.808 39.539 ;
     RECT  72.6 39.301 108.984 39.923 ;
     RECT  109.968 39.539 110.712 39.923 ;
     RECT  71.088 39.395 71.112 40.499 ;
     RECT  74.592 39.923 100.968 40.499 ;
     RECT  74.64 40.499 100.968 40.981 ;
     RECT  101.952 39.923 108.984 40.981 ;
     RECT  74.64 40.981 108.984 42.709 ;
     RECT  74.112 42.709 108.984 43.571 ;
     RECT  110.4 39.923 110.712 44.437 ;
     RECT  72.6 39.923 72.912 44.725 ;
     RECT  74.688 43.571 108.984 44.725 ;
     RECT  0.192 29.797 0.216 44.915 ;
     RECT  72.6 44.725 108.984 44.915 ;
     RECT  72.6 44.915 108.792 45.011 ;
     RECT  74.688 45.011 108.792 45.059 ;
     RECT  110.4 44.437 111.096 45.443 ;
     RECT  34.8 2.151 35.112 45.541 ;
     RECT  0.144 45.061 0.168 45.635 ;
     RECT  74.736 45.059 108.792 45.635 ;
     RECT  34.704 45.541 35.112 46.547 ;
     RECT  110.4 45.443 110.712 46.597 ;
     RECT  51 2.151 51.312 46.693 ;
     RECT  75.456 45.635 79.128 46.741 ;
     RECT  75.024 46.741 79.128 46.787 ;
     RECT  110.4 46.597 110.808 46.787 ;
     RECT  80.112 45.635 108.792 46.835 ;
     RECT  76.368 46.787 76.44 46.931 ;
     RECT  50.4 46.693 51.312 47.123 ;
     RECT  53.76 46.645 53.784 47.123 ;
     RECT  76.416 46.931 76.44 47.363 ;
     RECT  77.52 46.787 79.128 47.651 ;
     RECT  78 47.651 79.128 47.939 ;
     RECT  58.656 46.837 58.68 47.987 ;
     RECT  110.4 46.787 110.712 48.421 ;
     RECT  80.112 46.835 107.592 48.563 ;
     RECT  108.768 46.835 108.792 48.661 ;
     RECT  60.288 46.933 60.312 48.707 ;
     RECT  72.6 45.011 72.912 48.949 ;
     RECT  70.752 47.029 70.776 48.995 ;
     RECT  78 47.939 79.032 49.381 ;
     RECT  80.112 48.563 107.16 49.381 ;
     RECT  72.192 48.949 72.912 49.525 ;
     RECT  78 49.381 107.16 49.525 ;
     RECT  110.4 48.421 110.808 49.571 ;
     RECT  108.672 48.661 108.792 49.573 ;
     RECT  108.672 49.573 108.936 50.101 ;
     RECT  71.28 49.525 72.912 50.195 ;
     RECT  77.904 49.525 107.16 50.195 ;
     RECT  71.28 50.195 71.448 50.243 ;
     RECT  77.904 50.195 106.728 50.387 ;
     RECT  108.432 50.101 108.936 51.061 ;
     RECT  71.424 50.243 71.448 51.395 ;
     RECT  75.024 46.787 75.048 51.395 ;
     RECT  78 50.387 106.728 51.541 ;
     RECT  107.808 51.061 108.936 51.541 ;
     RECT  78 51.541 108.936 51.971 ;
     RECT  78 51.971 81.768 52.981 ;
     RECT  83.232 51.971 108.936 52.981 ;
     RECT  78 52.981 108.936 54.419 ;
     RECT  78 54.419 82.056 54.563 ;
     RECT  78 54.563 79.752 54.611 ;
     RECT  74.016 54.133 74.04 54.851 ;
     RECT  83.04 54.419 108.936 56.245 ;
     RECT  79.728 54.611 79.752 57.107 ;
     RECT  83.04 56.245 108.984 57.205 ;
     RECT  110.4 49.571 110.712 57.205 ;
     RECT  83.04 57.205 110.712 57.397 ;
     RECT  80.88 54.563 82.056 57.443 ;
     RECT  80.88 57.443 81.672 57.539 ;
     RECT  80.88 57.539 81.24 57.635 ;
     RECT  83.04 57.397 110.856 57.685 ;
     RECT  83.04 57.685 111.192 58.979 ;
     RECT  83.232 58.979 111.192 58.981 ;
     RECT  83.232 58.981 111.288 60.131 ;
     RECT  84.912 60.131 111.288 61.043 ;
     RECT  83.232 60.131 83.712 61.141 ;
     RECT  83.184 61.141 83.712 61.619 ;
     RECT  115.8 2.151 116.112 62.149 ;
     RECT  117.408 61.573 117.432 62.149 ;
     RECT  132 2.151 132.312 62.149 ;
     RECT  131.664 62.149 132.648 62.197 ;
     RECT  131.664 62.197 132.744 62.293 ;
     RECT  112.752 62.149 112.776 62.533 ;
     RECT  85.2 61.043 111.288 62.629 ;
     RECT  112.272 62.533 112.776 62.629 ;
     RECT  2.4 2.151 2.712 62.649 ;
     RECT  7.8 2.151 8.112 62.649 ;
     RECT  13.2 2.151 13.512 62.649 ;
     RECT  18.6 2.151 18.912 62.649 ;
     RECT  24 2.151 24.312 62.649 ;
     RECT  29.4 2.151 29.712 62.649 ;
     RECT  34.8 46.547 35.112 62.649 ;
     RECT  40.2 2.151 40.512 62.649 ;
     RECT  45.6 2.151 45.912 62.649 ;
     RECT  51 47.123 51.312 62.649 ;
     RECT  56.4 2.151 56.712 62.649 ;
     RECT  61.8 2.151 62.112 62.649 ;
     RECT  67.2 2.151 67.512 62.649 ;
     RECT  72.6 50.195 72.912 62.649 ;
     RECT  78 54.611 78.312 62.649 ;
     RECT  83.4 61.619 83.712 62.649 ;
     RECT  121.2 2.151 121.512 62.649 ;
     RECT  126.6 2.151 126.912 62.649 ;
     RECT  137.4 2.151 137.712 62.649 ;
     RECT  142.8 2.151 143.112 62.649 ;
     RECT  148.2 2.151 148.512 62.649 ;
     RECT  153.6 2.151 153.912 62.649 ;
     RECT  159 2.151 159.312 62.649 ;
     RECT  164.4 2.151 164.712 62.649 ;
     RECT  169.8 2.151 170.112 62.649 ;
     RECT  175.2 2.151 175.512 62.649 ;
     RECT  180.6 2.151 180.912 62.649 ;
     RECT  2.4 62.649 2.52 62.663 ;
     RECT  7.8 62.649 7.92 62.663 ;
     RECT  13.2 62.649 13.32 62.663 ;
     RECT  18.6 62.649 18.72 62.663 ;
     RECT  24 62.649 24.12 62.663 ;
     RECT  29.4 62.649 29.52 62.663 ;
     RECT  34.8 62.649 34.92 62.663 ;
     RECT  40.2 62.649 40.32 62.663 ;
     RECT  45.6 62.649 45.72 62.663 ;
     RECT  51 62.649 51.12 62.663 ;
     RECT  56.4 62.649 56.52 62.663 ;
     RECT  61.8 62.649 61.92 62.663 ;
     RECT  67.2 62.649 67.32 62.663 ;
     RECT  72.6 62.649 72.72 62.663 ;
     RECT  78 62.649 78.12 62.663 ;
     RECT  83.4 62.649 83.52 62.663 ;
     RECT  121.2 62.649 121.32 62.663 ;
     RECT  126.6 62.649 126.72 62.663 ;
     RECT  137.4 62.649 137.52 62.663 ;
     RECT  142.8 62.649 142.92 62.663 ;
     RECT  148.2 62.649 148.32 62.663 ;
     RECT  153.6 62.649 153.72 62.663 ;
     RECT  159 62.649 159.12 62.663 ;
     RECT  164.4 62.649 164.52 62.663 ;
     RECT  169.8 62.649 169.92 62.663 ;
     RECT  175.2 62.649 175.32 62.663 ;
     RECT  180.6 62.649 180.72 62.663 ;
     RECT  85.2 62.629 112.776 62.725 ;
     RECT  113.904 62.629 113.928 62.725 ;
     RECT  115.8 62.149 118.344 62.725 ;
     RECT  131.664 62.293 133.32 62.725 ;
     RECT  115.8 62.725 118.536 62.821 ;
     RECT  131.664 62.725 133.704 62.821 ;
     RECT  123.024 62.773 123.048 63.011 ;
     RECT  115.8 62.821 119.112 63.205 ;
     RECT  131.28 62.821 133.704 63.205 ;
     RECT  131.088 63.205 133.704 63.253 ;
     RECT  85.2 62.725 113.928 63.395 ;
     RECT  85.392 63.395 113.928 63.781 ;
     RECT  115.056 63.205 119.112 63.781 ;
     RECT  85.392 63.781 119.112 64.115 ;
     RECT  85.68 64.115 119.112 64.499 ;
     RECT  85.824 64.499 119.112 64.595 ;
     RECT  85.824 64.595 85.848 64.643 ;
     RECT  87.696 64.595 119.112 64.716 ;
     RECT  87.72 64.716 87.792 64.784 ;
     RECT  87.816 64.716 87.888 64.784 ;
     RECT  87.912 64.716 87.984 64.784 ;
     RECT  88.008 64.716 88.08 64.784 ;
     RECT  88.104 64.716 88.176 64.784 ;
     RECT  88.2 64.716 88.272 64.784 ;
     RECT  88.296 64.716 88.368 64.784 ;
     RECT  88.392 64.716 88.464 64.784 ;
     RECT  88.488 64.716 88.56 64.784 ;
     RECT  88.584 64.716 88.656 64.784 ;
     RECT  88.68 64.716 88.752 64.784 ;
     RECT  88.776 64.716 88.848 64.784 ;
     RECT  88.872 64.716 88.944 64.784 ;
     RECT  88.968 64.716 89.04 64.784 ;
     RECT  89.064 64.716 89.136 64.784 ;
     RECT  89.16 64.716 89.232 64.784 ;
     RECT  89.256 64.716 89.328 64.784 ;
     RECT  89.352 64.716 89.424 64.784 ;
     RECT  89.448 64.716 89.52 64.784 ;
     RECT  89.544 64.716 89.616 64.784 ;
     RECT  89.64 64.716 89.712 64.784 ;
     RECT  89.736 64.716 89.808 64.784 ;
     RECT  89.832 64.716 89.904 64.784 ;
     RECT  89.928 64.716 90 64.784 ;
     RECT  90.024 64.716 90.096 64.784 ;
     RECT  90.12 64.716 90.192 64.784 ;
     RECT  90.216 64.716 90.288 64.784 ;
     RECT  90.312 64.716 90.384 64.784 ;
     RECT  90.408 64.716 90.48 64.784 ;
     RECT  90.504 64.716 90.576 64.784 ;
     RECT  90.6 64.716 90.672 64.784 ;
     RECT  90.696 64.716 90.768 64.784 ;
     RECT  90.792 64.716 90.864 64.784 ;
     RECT  90.888 64.716 90.96 64.784 ;
     RECT  90.984 64.716 91.056 64.784 ;
     RECT  91.08 64.716 91.152 64.784 ;
     RECT  91.176 64.716 91.248 64.784 ;
     RECT  91.272 64.716 91.344 64.784 ;
     RECT  91.368 64.716 91.44 64.784 ;
     RECT  91.464 64.716 91.536 64.784 ;
     RECT  91.56 64.716 91.632 64.784 ;
     RECT  91.656 64.716 91.728 64.784 ;
     RECT  91.752 64.716 91.824 64.784 ;
     RECT  91.848 64.716 91.92 64.784 ;
     RECT  91.944 64.716 92.016 64.784 ;
     RECT  92.04 64.716 92.112 64.784 ;
     RECT  92.136 64.716 92.208 64.784 ;
     RECT  92.232 64.716 92.304 64.784 ;
     RECT  92.328 64.716 92.4 64.784 ;
     RECT  92.424 64.716 92.496 64.784 ;
     RECT  92.52 64.716 92.592 64.784 ;
     RECT  92.616 64.716 92.688 64.784 ;
     RECT  92.712 64.716 92.784 64.784 ;
     RECT  92.808 64.716 92.88 64.784 ;
     RECT  92.904 64.716 92.976 64.784 ;
     RECT  93 64.716 93.072 64.784 ;
     RECT  93.096 64.716 93.168 64.784 ;
     RECT  93.192 64.716 93.264 64.784 ;
     RECT  93.288 64.716 93.36 64.784 ;
     RECT  93.384 64.716 93.456 64.784 ;
     RECT  93.48 64.716 93.552 64.784 ;
     RECT  93.576 64.716 93.648 64.784 ;
     RECT  93.672 64.716 93.744 64.784 ;
     RECT  93.768 64.716 93.84 64.784 ;
     RECT  93.864 64.716 93.936 64.784 ;
     RECT  93.96 64.716 94.032 64.784 ;
     RECT  94.056 64.716 94.128 64.784 ;
     RECT  94.152 64.716 94.224 64.784 ;
     RECT  94.248 64.716 94.32 64.784 ;
     RECT  94.344 64.716 94.416 64.784 ;
     RECT  94.44 64.716 94.512 64.784 ;
     RECT  94.536 64.716 94.608 64.784 ;
     RECT  94.632 64.716 94.704 64.784 ;
     RECT  94.728 64.716 94.8 64.784 ;
     RECT  94.824 64.716 94.896 64.784 ;
     RECT  94.92 64.716 94.992 64.784 ;
     RECT  95.016 64.716 95.088 64.784 ;
     RECT  95.112 64.716 95.184 64.784 ;
     RECT  95.208 64.716 95.28 64.784 ;
     RECT  95.304 64.716 95.376 64.784 ;
     RECT  95.4 64.716 95.472 64.784 ;
     RECT  95.496 64.716 95.568 64.784 ;
     RECT  95.592 64.716 95.664 64.784 ;
     RECT  95.688 64.716 95.76 64.784 ;
     RECT  95.784 64.716 95.856 64.784 ;
     RECT  95.88 64.716 95.952 64.784 ;
     RECT  95.976 64.716 96.048 64.784 ;
     RECT  96.072 64.716 96.144 64.784 ;
     RECT  96.168 64.716 96.24 64.784 ;
     RECT  96.264 64.716 96.336 64.784 ;
     RECT  96.36 64.716 96.432 64.784 ;
     RECT  96.456 64.716 96.528 64.784 ;
     RECT  96.552 64.716 96.624 64.784 ;
     RECT  96.648 64.716 96.72 64.784 ;
     RECT  96.744 64.716 96.816 64.784 ;
     RECT  96.84 64.716 96.912 64.784 ;
     RECT  96.936 64.716 97.008 64.784 ;
     RECT  97.032 64.716 97.104 64.784 ;
     RECT  97.128 64.716 97.2 64.784 ;
     RECT  97.224 64.716 97.296 64.784 ;
     RECT  97.32 64.716 97.392 64.784 ;
     RECT  97.416 64.716 97.488 64.784 ;
     RECT  97.512 64.716 97.584 64.784 ;
     RECT  97.608 64.716 97.68 64.784 ;
     RECT  97.704 64.716 97.776 64.784 ;
     RECT  97.8 64.716 97.872 64.784 ;
     RECT  97.896 64.716 97.968 64.784 ;
     RECT  97.992 64.716 98.064 64.784 ;
     RECT  98.088 64.716 98.16 64.784 ;
     RECT  98.184 64.716 98.256 64.784 ;
     RECT  98.28 64.716 98.352 64.784 ;
     RECT  98.376 64.716 98.448 64.784 ;
     RECT  98.472 64.716 98.544 64.784 ;
     RECT  98.568 64.716 98.64 64.784 ;
     RECT  98.664 64.716 98.736 64.784 ;
     RECT  98.76 64.716 98.832 64.784 ;
     RECT  98.856 64.716 98.928 64.784 ;
     RECT  98.952 64.716 99.024 64.784 ;
     RECT  99.048 64.716 99.12 64.784 ;
     RECT  99.144 64.716 99.216 64.784 ;
     RECT  99.24 64.716 99.312 64.784 ;
     RECT  99.336 64.716 99.408 64.784 ;
     RECT  99.432 64.716 99.504 64.784 ;
     RECT  99.528 64.716 99.6 64.784 ;
     RECT  99.624 64.716 99.696 64.784 ;
     RECT  99.72 64.716 99.792 64.784 ;
     RECT  99.816 64.716 99.888 64.784 ;
     RECT  99.912 64.716 99.984 64.784 ;
     RECT  100.008 64.716 100.08 64.784 ;
     RECT  100.104 64.716 100.176 64.784 ;
     RECT  100.2 64.716 100.272 64.784 ;
     RECT  100.296 64.716 100.368 64.784 ;
     RECT  100.392 64.716 100.464 64.784 ;
     RECT  100.488 64.716 100.56 64.784 ;
     RECT  100.584 64.716 100.656 64.784 ;
     RECT  100.68 64.716 100.752 64.784 ;
     RECT  100.776 64.716 100.848 64.784 ;
     RECT  100.872 64.716 100.944 64.784 ;
     RECT  100.968 64.716 101.04 64.784 ;
     RECT  101.064 64.716 101.136 64.784 ;
     RECT  101.16 64.716 101.232 64.784 ;
     RECT  101.256 64.716 101.328 64.784 ;
     RECT  101.352 64.716 101.424 64.784 ;
     RECT  101.448 64.716 101.52 64.784 ;
     RECT  101.544 64.716 101.616 64.784 ;
     RECT  101.64 64.716 101.712 64.784 ;
     RECT  101.736 64.716 101.808 64.784 ;
     RECT  101.832 64.716 101.904 64.784 ;
     RECT  101.928 64.716 102 64.784 ;
     RECT  102.024 64.716 102.096 64.784 ;
     RECT  102.12 64.716 102.192 64.784 ;
     RECT  102.216 64.716 102.288 64.784 ;
     RECT  102.312 64.716 102.384 64.784 ;
     RECT  102.408 64.716 102.48 64.784 ;
     RECT  102.504 64.716 102.576 64.784 ;
     RECT  102.6 64.716 102.672 64.784 ;
     RECT  102.696 64.716 102.768 64.784 ;
     RECT  102.792 64.716 102.864 64.784 ;
     RECT  102.888 64.716 102.96 64.784 ;
     RECT  102.984 64.716 103.056 64.784 ;
     RECT  103.08 64.716 103.152 64.784 ;
     RECT  103.176 64.716 103.248 64.784 ;
     RECT  103.272 64.716 103.344 64.784 ;
     RECT  103.368 64.716 103.44 64.784 ;
     RECT  103.464 64.716 103.536 64.784 ;
     RECT  103.56 64.716 103.632 64.784 ;
     RECT  103.656 64.716 103.728 64.784 ;
     RECT  103.752 64.716 103.824 64.784 ;
     RECT  103.848 64.716 103.92 64.784 ;
     RECT  103.944 64.716 104.016 64.784 ;
     RECT  104.04 64.716 104.112 64.784 ;
     RECT  104.136 64.716 104.208 64.784 ;
     RECT  104.232 64.716 104.304 64.784 ;
     RECT  104.328 64.716 104.4 64.784 ;
     RECT  104.424 64.716 104.496 64.784 ;
     RECT  104.52 64.716 104.592 64.784 ;
     RECT  104.616 64.716 104.688 64.784 ;
     RECT  104.712 64.716 104.784 64.784 ;
     RECT  104.808 64.716 104.88 64.784 ;
     RECT  104.904 64.716 104.976 64.784 ;
     RECT  105 64.716 105.072 64.784 ;
     RECT  105.096 64.716 105.168 64.784 ;
     RECT  105.192 64.716 105.264 64.784 ;
     RECT  105.288 64.716 105.36 64.784 ;
     RECT  105.384 64.716 105.456 64.784 ;
     RECT  105.48 64.716 105.552 64.784 ;
     RECT  105.576 64.716 105.648 64.784 ;
     RECT  105.672 64.716 105.744 64.784 ;
     RECT  105.768 64.716 105.84 64.784 ;
     RECT  105.864 64.716 105.936 64.784 ;
     RECT  105.96 64.716 106.032 64.784 ;
     RECT  106.056 64.716 106.896 64.784 ;
     RECT  106.92 64.716 106.992 64.784 ;
     RECT  107.016 64.716 107.088 64.784 ;
     RECT  107.112 64.716 107.184 64.784 ;
     RECT  107.208 64.716 107.28 64.784 ;
     RECT  107.304 64.716 107.376 64.784 ;
     RECT  107.4 64.716 107.472 64.784 ;
     RECT  107.496 64.716 107.568 64.784 ;
     RECT  107.592 64.716 107.664 64.784 ;
     RECT  107.688 64.716 107.76 64.784 ;
     RECT  107.784 64.716 107.856 64.784 ;
     RECT  107.88 64.716 107.952 64.784 ;
     RECT  107.976 64.716 108.048 64.784 ;
     RECT  108.072 64.716 108.144 64.784 ;
     RECT  108.168 64.716 108.24 64.784 ;
     RECT  108.264 64.716 108.336 64.784 ;
     RECT  108.36 64.716 108.432 64.784 ;
     RECT  108.456 64.716 108.528 64.784 ;
     RECT  108.552 64.716 108.624 64.784 ;
     RECT  108.648 64.716 108.72 64.784 ;
     RECT  108.744 64.716 108.816 64.784 ;
     RECT  108.84 64.716 108.912 64.784 ;
     RECT  108.936 64.716 109.008 64.784 ;
     RECT  109.032 64.716 109.104 64.784 ;
     RECT  109.128 64.716 109.2 64.784 ;
     RECT  109.224 64.716 109.296 64.784 ;
     RECT  109.32 64.716 109.392 64.784 ;
     RECT  109.416 64.716 109.488 64.784 ;
     RECT  109.512 64.716 109.584 64.784 ;
     RECT  109.608 64.716 109.68 64.784 ;
     RECT  109.704 64.716 109.776 64.784 ;
     RECT  109.8 64.716 109.872 64.784 ;
     RECT  109.896 64.716 109.968 64.784 ;
     RECT  109.992 64.716 110.064 64.784 ;
     RECT  110.088 64.716 110.16 64.784 ;
     RECT  110.184 64.716 110.256 64.784 ;
     RECT  110.28 64.716 110.352 64.784 ;
     RECT  110.376 64.716 110.448 64.784 ;
     RECT  110.472 64.716 110.544 64.784 ;
     RECT  110.568 64.716 110.64 64.784 ;
     RECT  110.664 64.716 110.736 64.784 ;
     RECT  110.76 64.716 110.832 64.784 ;
     RECT  110.856 64.716 110.928 64.784 ;
     RECT  110.952 64.716 111.024 64.784 ;
     RECT  111.048 64.716 111.12 64.784 ;
     RECT  111.144 64.716 111.216 64.784 ;
     RECT  111.24 64.716 111.312 64.784 ;
     RECT  111.336 64.716 111.408 64.784 ;
     RECT  111.432 64.716 111.504 64.784 ;
     RECT  111.528 64.716 111.6 64.784 ;
     RECT  111.624 64.716 111.696 64.784 ;
     RECT  111.72 64.716 111.792 64.784 ;
     RECT  111.816 64.716 111.888 64.784 ;
     RECT  111.912 64.716 111.984 64.784 ;
     RECT  112.008 64.716 112.08 64.784 ;
     RECT  112.104 64.716 112.176 64.784 ;
     RECT  112.2 64.716 112.272 64.784 ;
     RECT  112.296 64.716 112.368 64.784 ;
     RECT  112.392 64.716 112.464 64.784 ;
     RECT  112.488 64.716 112.56 64.784 ;
     RECT  112.584 64.716 112.656 64.784 ;
     RECT  112.68 64.716 112.752 64.784 ;
     RECT  112.776 64.716 112.848 64.784 ;
     RECT  112.872 64.716 112.944 64.784 ;
     RECT  112.968 64.716 113.04 64.784 ;
     RECT  113.064 64.716 113.136 64.784 ;
     RECT  113.16 64.716 113.232 64.784 ;
     RECT  113.256 64.716 113.328 64.784 ;
     RECT  113.352 64.716 113.424 64.784 ;
     RECT  113.448 64.716 113.52 64.784 ;
     RECT  113.544 64.716 113.616 64.784 ;
     RECT  113.64 64.716 113.712 64.784 ;
     RECT  113.736 64.716 113.808 64.784 ;
     RECT  113.832 64.716 113.904 64.784 ;
     RECT  113.928 64.716 114 64.784 ;
     RECT  114.024 64.716 114.096 64.784 ;
     RECT  114.12 64.716 114.192 64.784 ;
     RECT  114.216 64.716 114.288 64.784 ;
     RECT  114.312 64.716 114.384 64.784 ;
     RECT  114.408 64.716 114.48 64.784 ;
     RECT  114.504 64.716 114.576 64.784 ;
     RECT  114.6 64.716 114.672 64.784 ;
     RECT  114.696 64.716 114.768 64.784 ;
     RECT  114.792 64.716 114.864 64.784 ;
     RECT  114.888 64.716 114.96 64.784 ;
     RECT  114.984 64.716 115.056 64.784 ;
     RECT  115.08 64.716 115.152 64.784 ;
     RECT  115.176 64.716 115.248 64.784 ;
     RECT  115.272 64.716 115.344 64.784 ;
     RECT  115.368 64.716 115.44 64.784 ;
     RECT  115.464 64.716 115.536 64.784 ;
     RECT  115.56 64.716 115.632 64.784 ;
     RECT  115.656 64.716 115.728 64.784 ;
     RECT  115.752 64.716 115.824 64.784 ;
     RECT  115.848 64.716 115.92 64.784 ;
     RECT  115.944 64.716 116.016 64.784 ;
     RECT  116.04 64.716 116.112 64.784 ;
     RECT  116.136 64.716 116.208 64.784 ;
     RECT  116.232 64.716 116.304 64.784 ;
     RECT  116.328 64.716 116.4 64.784 ;
     RECT  116.424 64.716 116.496 64.784 ;
     RECT  116.52 64.716 116.592 64.784 ;
     RECT  116.616 64.716 116.688 64.784 ;
     RECT  116.712 64.716 116.784 64.784 ;
     RECT  116.808 64.716 116.88 64.784 ;
     RECT  116.904 64.716 116.976 64.784 ;
     RECT  117 64.716 117.072 64.784 ;
     RECT  117.096 64.716 117.168 64.784 ;
     RECT  117.192 64.716 117.264 64.784 ;
     RECT  117.288 64.716 117.36 64.784 ;
     RECT  117.384 64.716 117.456 64.784 ;
     RECT  117.48 64.716 117.552 64.784 ;
     RECT  117.576 64.716 117.648 64.784 ;
     RECT  117.672 64.716 117.744 64.784 ;
     RECT  117.768 64.716 117.84 64.784 ;
     RECT  117.864 64.716 117.936 64.784 ;
     RECT  117.96 64.716 118.032 64.784 ;
     RECT  118.056 64.716 118.128 64.784 ;
     RECT  118.152 64.716 118.224 64.784 ;
     RECT  118.248 64.716 118.32 64.784 ;
     RECT  118.344 64.716 118.416 64.784 ;
     RECT  118.44 64.716 118.512 64.784 ;
     RECT  118.536 64.716 118.608 64.784 ;
     RECT  118.632 64.716 118.704 64.784 ;
     RECT  118.728 64.716 118.8 64.784 ;
     RECT  118.824 64.716 118.896 64.784 ;
     RECT  118.92 64.716 118.992 64.784 ;
     RECT  119.016 64.716 119.088 64.784 ;
     RECT  131.088 63.253 135.24 64.716 ;
     RECT  131.112 64.716 131.184 64.784 ;
     RECT  131.208 64.716 131.28 64.784 ;
     RECT  131.304 64.716 131.376 64.784 ;
     RECT  131.4 64.716 131.472 64.784 ;
     RECT  131.496 64.716 131.568 64.784 ;
     RECT  131.592 64.716 131.664 64.784 ;
     RECT  131.688 64.716 131.76 64.784 ;
     RECT  131.784 64.716 131.856 64.784 ;
     RECT  131.88 64.716 131.952 64.784 ;
     RECT  131.976 64.716 132.048 64.784 ;
     RECT  132.072 64.716 132.144 64.784 ;
     RECT  132.168 64.716 132.24 64.784 ;
     RECT  132.264 64.716 132.336 64.784 ;
     RECT  132.36 64.716 132.432 64.784 ;
     RECT  132.456 64.716 132.528 64.784 ;
     RECT  132.552 64.716 132.624 64.784 ;
     RECT  132.648 64.716 132.72 64.784 ;
     RECT  132.744 64.716 132.816 64.784 ;
     RECT  132.84 64.716 132.912 64.784 ;
     RECT  132.936 64.716 133.008 64.784 ;
     RECT  133.032 64.716 133.104 64.784 ;
     RECT  133.128 64.716 133.2 64.784 ;
     RECT  133.224 64.716 133.296 64.784 ;
     RECT  133.32 64.716 133.392 64.784 ;
     RECT  133.416 64.716 133.488 64.784 ;
     RECT  133.512 64.716 133.584 64.784 ;
     RECT  133.608 64.716 133.68 64.784 ;
     RECT  133.704 64.716 133.776 64.784 ;
     RECT  133.8 64.716 133.872 64.784 ;
     RECT  133.896 64.716 133.968 64.784 ;
     RECT  133.992 64.716 134.064 64.784 ;
     RECT  134.088 64.716 134.16 64.784 ;
     RECT  134.184 64.716 134.256 64.784 ;
     RECT  134.28 64.716 134.352 64.784 ;
     RECT  134.376 64.716 134.448 64.784 ;
     RECT  134.472 64.716 134.544 64.784 ;
     RECT  134.568 64.716 134.64 64.784 ;
     RECT  134.664 64.716 134.736 64.784 ;
     RECT  134.76 64.716 134.832 64.784 ;
     RECT  134.856 64.716 134.928 64.784 ;
     RECT  134.952 64.716 135.024 64.784 ;
     RECT  135.048 64.716 135.12 64.784 ;
     RECT  135.144 64.716 135.216 64.784 ;
     RECT  77.52 1.091 77.616 2.053 ;
     RECT  96.024 1.187 96.12 2.149 ;
     RECT  103.512 1.859 103.56 2.137 ;
     RECT  76.104 2.053 77.568 2.197 ;
     RECT  103.512 2.137 105 2.821 ;
     RECT  98.088 2.245 99.6 2.773 ;
     RECT  96.84 2.485 98.064 2.821 ;
     RECT  98.136 2.773 99.6 3.205 ;
     RECT  103.512 2.821 104.496 6.181 ;
     RECT  72.912 4.693 74.064 4.837 ;
     RECT  74.088 4.693 75.36 4.981 ;
     RECT  101.208 4.837 102.528 5.077 ;
     RECT  101.304 5.077 102.528 5.365 ;
     RECT  101.304 5.365 102.288 5.653 ;
     RECT  73.128 6.371 74.688 7.477 ;
     RECT  73.128 8.435 74.592 8.579 ;
     RECT  109.872 8.579 110.4 9.637 ;
     RECT  74.592 9.491 75.024 10.693 ;
     RECT  71.208 10.789 72.384 11.411 ;
     RECT  108.36 11.269 109.872 11.411 ;
     RECT  108.36 11.411 110.4 12.517 ;
     RECT  72.912 11.605 73.968 11.797 ;
     RECT  72.432 11.795 72.6 12.757 ;
     RECT  72.912 11.797 73.92 12.373 ;
     RECT  108.888 12.517 110.4 15.203 ;
     RECT  72.432 13.763 72.48 15.061 ;
     RECT  73.896 14.867 75.024 16.501 ;
     RECT  106.872 14.915 108 15.731 ;
     RECT  108.024 15.203 108.12 16.501 ;
     RECT  106.296 15.731 108 16.547 ;
     RECT  106.296 16.547 108.096 16.885 ;
     RECT  106.728 16.885 108.096 17.029 ;
     RECT  106.872 17.029 108.096 18.133 ;
     RECT  110.256 17.891 110.4 19.333 ;
     RECT  107.016 18.133 108.096 19.861 ;
     RECT  70.68 18.565 71.712 18.851 ;
     RECT  70.44 18.851 71.712 19.235 ;
     RECT  70.44 19.235 71.76 20.579 ;
     RECT  74.808 20.051 76.08 20.579 ;
     RECT  99.912 21.779 101.136 23.173 ;
     RECT  74.616 22.165 75.6 22.693 ;
     RECT  108.648 23.411 108.84 24.901 ;
     RECT  103.176 23.459 104.256 24.563 ;
     RECT  103.176 24.563 104.544 26.819 ;
     RECT  106.248 24.563 107.232 24.611 ;
     RECT  106.248 24.611 107.856 25.139 ;
     RECT  109.176 24.901 110.4 25.715 ;
     RECT  105.864 25.139 107.856 25.861 ;
     RECT  105.864 25.861 107.136 27.205 ;
     RECT  100.872 26.291 101.952 26.819 ;
     RECT  100.296 26.819 101.952 27.301 ;
     RECT  103.176 26.819 104.784 27.395 ;
     RECT  100.296 27.301 101.76 29.941 ;
     RECT  102.84 27.395 104.784 28.309 ;
     RECT  105.432 27.443 106.56 27.971 ;
     RECT  108.648 27.685 109.968 27.781 ;
     RECT  105.432 27.971 107.088 29.029 ;
     RECT  102.84 28.309 104.112 28.453 ;
     RECT  102.84 28.453 103.824 29.171 ;
     RECT  106.008 29.029 106.992 30.181 ;
     RECT  101.784 29.123 102.816 29.171 ;
     RECT  101.784 29.171 103.824 29.365 ;
     RECT  101.784 29.365 102.864 30.421 ;
     RECT  109.32 29.699 110.4 30.275 ;
     RECT  100.296 29.941 101.424 30.133 ;
     RECT  109.224 30.275 110.4 30.323 ;
     RECT  109.176 30.323 110.4 31.525 ;
     RECT  108.168 30.803 109.152 31.813 ;
     RECT  70.896 30.851 71.664 31.765 ;
     RECT  109.416 31.525 110.4 32.437 ;
     RECT  69.864 31.765 71.664 32.341 ;
     RECT  69.864 32.341 71.232 33.299 ;
     RECT  74.04 34.067 75.024 34.259 ;
     RECT  74.04 34.259 75.36 35.317 ;
     RECT  107.016 34.835 108.096 35.651 ;
     RECT  100.872 35.605 102.384 35.797 ;
     RECT  107.016 35.651 108.144 35.845 ;
     RECT  101.304 35.797 102.384 35.845 ;
     RECT  107.16 35.845 108.144 36.515 ;
     RECT  107.112 36.515 108.144 36.949 ;
     RECT  107.112 36.949 108.096 38.725 ;
     RECT  108.168 37.667 108.312 38.677 ;
     RECT  108.936 38.677 109.968 39.301 ;
     RECT  108.984 39.301 109.968 39.923 ;
     RECT  71.112 39.349 72.6 40.499 ;
     RECT  100.968 39.923 101.952 40.981 ;
     RECT  108.984 39.923 110.4 44.915 ;
     RECT  72.912 42.709 74.112 43.571 ;
     RECT  72.912 43.571 74.688 44.725 ;
     RECT  110.712 45.443 110.808 46.597 ;
     RECT  75.024 45.635 75.456 46.741 ;
     RECT  79.128 45.635 80.112 47.939 ;
     RECT  75.048 46.787 76.368 46.931 ;
     RECT  76.44 46.787 77.52 47.363 ;
     RECT  107.592 46.835 108.768 48.563 ;
     RECT  75.048 46.931 76.416 47.363 ;
     RECT  60.312 46.933 61.8 48.707 ;
     RECT  79.032 47.939 80.112 49.381 ;
     RECT  107.16 48.563 108.768 48.661 ;
     RECT  107.16 48.661 108.672 50.101 ;
     RECT  70.776 48.949 72.192 48.995 ;
     RECT  71.28 48.995 72.192 49.525 ;
     RECT  108.936 49.573 110.4 56.245 ;
     RECT  107.16 50.101 108.432 50.195 ;
     RECT  71.448 50.195 72.6 51.395 ;
     RECT  106.728 50.195 108.432 51.061 ;
     RECT  106.728 51.061 107.808 51.541 ;
     RECT  81.768 51.971 83.232 52.981 ;
     RECT  72.912 54.133 74.016 54.851 ;
     RECT  82.056 54.419 83.04 57.443 ;
     RECT  79.752 54.563 80.88 57.107 ;
     RECT  78.312 54.611 79.728 57.107 ;
     RECT  108.984 56.245 110.4 57.205 ;
     RECT  81.672 57.443 83.04 57.539 ;
     RECT  83.712 60.131 84.912 61.043 ;
     RECT  83.712 61.043 85.2 62.649 ;
     RECT  116.112 61.573 117.408 62.149 ;
     RECT  111.288 62.149 112.752 62.533 ;
     RECT  111.288 62.533 112.272 62.629 ;
     RECT  112.776 62.629 113.904 62.725 ;
     RECT  113.928 63.205 115.056 63.781 ;
  END
END ot_hgi_xp_aq_bypass13
END LIBRARY
